VERSION 5.8 ;
BUSBITCHARS "[]" ;
DIVIDERCHAR "/" ;
UNITS
    DATABASE MICRONS 1000 ;
END UNITS

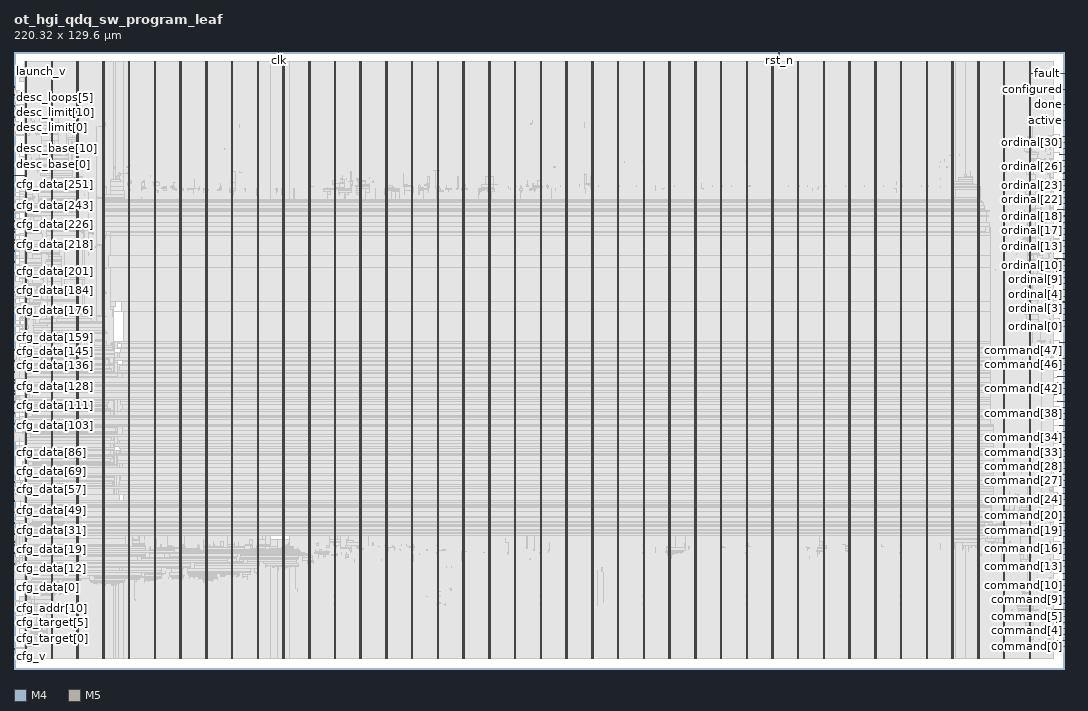
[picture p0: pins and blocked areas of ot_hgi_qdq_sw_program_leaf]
MACRO ot_hgi_qdq_sw_program_leaf
  FOREIGN ot_hgi_qdq_sw_program_leaf 0 0 ;
  CLASS BLOCK ;
  SIZE 220.32 BY 129.6 ;
  PIN active
    DIRECTION OUTPUT ;
    USE SIGNAL ;
    PORT
      LAYER M4 ;
        RECT  220.236 115.056 220.32 115.08 ;
    END
    PORT
      LAYER M4 ;
        RECT  219.409 115.056 220.284 115.08 ;
    END
  END active
  PIN cfg_addr[0]
    DIRECTION INPUT ;
    USE SIGNAL ;
    PORT
      LAYER M4 ;
        RECT  0 11.136 0.084 11.16 ;
    END
  END cfg_addr[0]
  PIN cfg_addr[10]
    DIRECTION INPUT ;
    USE SIGNAL ;
    PORT
      LAYER M4 ;
        RECT  0 14.4 0.084 14.424 ;
    END
  END cfg_addr[10]
  PIN cfg_addr[11]
    DIRECTION INPUT ;
    USE SIGNAL ;
    PORT
      LAYER M4 ;
        RECT  0 14.736 0.084 14.76 ;
    END
  END cfg_addr[11]
  PIN cfg_addr[1]
    DIRECTION INPUT ;
    USE SIGNAL ;
    PORT
      LAYER M4 ;
        RECT  0 11.472 0.084 11.496 ;
    END
  END cfg_addr[1]
  PIN cfg_addr[2]
    DIRECTION INPUT ;
    USE SIGNAL ;
    PORT
      LAYER M4 ;
        RECT  0 11.76 0.084 11.784 ;
    END
  END cfg_addr[2]
  PIN cfg_addr[3]
    DIRECTION INPUT ;
    USE SIGNAL ;
    PORT
      LAYER M4 ;
        RECT  0 12.096 0.084 12.12 ;
    END
  END cfg_addr[3]
  PIN cfg_addr[4]
    DIRECTION INPUT ;
    USE SIGNAL ;
    PORT
      LAYER M4 ;
        RECT  0 12.432 0.084 12.456 ;
    END
  END cfg_addr[4]
  PIN cfg_addr[5]
    DIRECTION INPUT ;
    USE SIGNAL ;
    PORT
      LAYER M4 ;
        RECT  0 12.768 0.084 12.792 ;
    END
  END cfg_addr[5]
  PIN cfg_addr[6]
    DIRECTION INPUT ;
    USE SIGNAL ;
    PORT
      LAYER M4 ;
        RECT  0 13.104 0.084 13.128 ;
    END
  END cfg_addr[6]
  PIN cfg_addr[7]
    DIRECTION INPUT ;
    USE SIGNAL ;
    PORT
      LAYER M4 ;
        RECT  0 13.44 0.084 13.464 ;
    END
  END cfg_addr[7]
  PIN cfg_addr[8]
    DIRECTION INPUT ;
    USE SIGNAL ;
    PORT
      LAYER M4 ;
        RECT  0 13.776 0.084 13.8 ;
    END
  END cfg_addr[8]
  PIN cfg_addr[9]
    DIRECTION INPUT ;
    USE SIGNAL ;
    PORT
      LAYER M4 ;
        RECT  0 14.112 0.084 14.136 ;
    END
  END cfg_addr[9]
  PIN cfg_data[0]
    DIRECTION INPUT ;
    USE SIGNAL ;
    PORT
      LAYER M4 ;
        RECT  0 17.088 0.084 17.112 ;
    END
  END cfg_data[0]
  PIN cfg_data[100]
    DIRECTION INPUT ;
    USE SIGNAL ;
    PORT
      LAYER M4 ;
        RECT  0 50.064 0.084 50.088 ;
    END
  END cfg_data[100]
  PIN cfg_data[101]
    DIRECTION INPUT ;
    USE SIGNAL ;
    PORT
      LAYER M4 ;
        RECT  0 50.4 0.084 50.424 ;
    END
  END cfg_data[101]
  PIN cfg_data[102]
    DIRECTION INPUT ;
    USE SIGNAL ;
    PORT
      LAYER M4 ;
        RECT  0 50.736 0.084 50.76 ;
    END
  END cfg_data[102]
  PIN cfg_data[103]
    DIRECTION INPUT ;
    USE SIGNAL ;
    PORT
      LAYER M4 ;
        RECT  0 51.072 0.084 51.096 ;
    END
  END cfg_data[103]
  PIN cfg_data[104]
    DIRECTION INPUT ;
    USE SIGNAL ;
    PORT
      LAYER M4 ;
        RECT  0 51.408 0.084 51.432 ;
    END
  END cfg_data[104]
  PIN cfg_data[105]
    DIRECTION INPUT ;
    USE SIGNAL ;
    PORT
      LAYER M4 ;
        RECT  0 51.744 0.084 51.768 ;
    END
  END cfg_data[105]
  PIN cfg_data[106]
    DIRECTION INPUT ;
    USE SIGNAL ;
    PORT
      LAYER M4 ;
        RECT  0 52.08 0.084 52.104 ;
    END
  END cfg_data[106]
  PIN cfg_data[107]
    DIRECTION INPUT ;
    USE SIGNAL ;
    PORT
      LAYER M4 ;
        RECT  0 52.416 0.084 52.44 ;
    END
  END cfg_data[107]
  PIN cfg_data[108]
    DIRECTION INPUT ;
    USE SIGNAL ;
    PORT
      LAYER M4 ;
        RECT  0 52.704 0.084 52.728 ;
    END
  END cfg_data[108]
  PIN cfg_data[109]
    DIRECTION INPUT ;
    USE SIGNAL ;
    PORT
      LAYER M4 ;
        RECT  0 53.04 0.084 53.064 ;
    END
  END cfg_data[109]
  PIN cfg_data[10]
    DIRECTION INPUT ;
    USE SIGNAL ;
    PORT
      LAYER M4 ;
        RECT  0 20.4 0.084 20.424 ;
    END
  END cfg_data[10]
  PIN cfg_data[110]
    DIRECTION INPUT ;
    USE SIGNAL ;
    PORT
      LAYER M4 ;
        RECT  0 53.376 0.084 53.4 ;
    END
  END cfg_data[110]
  PIN cfg_data[111]
    DIRECTION INPUT ;
    USE SIGNAL ;
    PORT
      LAYER M4 ;
        RECT  0 53.712 0.084 53.736 ;
    END
  END cfg_data[111]
  PIN cfg_data[112]
    DIRECTION INPUT ;
    USE SIGNAL ;
    PORT
      LAYER M4 ;
        RECT  0 54.048 0.084 54.072 ;
    END
  END cfg_data[112]
  PIN cfg_data[113]
    DIRECTION INPUT ;
    USE SIGNAL ;
    PORT
      LAYER M4 ;
        RECT  0 54.384 0.084 54.408 ;
    END
  END cfg_data[113]
  PIN cfg_data[114]
    DIRECTION INPUT ;
    USE SIGNAL ;
    PORT
      LAYER M4 ;
        RECT  0 54.72 0.084 54.744 ;
    END
  END cfg_data[114]
  PIN cfg_data[115]
    DIRECTION INPUT ;
    USE SIGNAL ;
    PORT
      LAYER M4 ;
        RECT  0 55.056 0.084 55.08 ;
    END
  END cfg_data[115]
  PIN cfg_data[116]
    DIRECTION INPUT ;
    USE SIGNAL ;
    PORT
      LAYER M4 ;
        RECT  0 55.344 0.084 55.368 ;
    END
  END cfg_data[116]
  PIN cfg_data[117]
    DIRECTION INPUT ;
    USE SIGNAL ;
    PORT
      LAYER M4 ;
        RECT  0 55.68 0.084 55.704 ;
    END
  END cfg_data[117]
  PIN cfg_data[118]
    DIRECTION INPUT ;
    USE SIGNAL ;
    PORT
      LAYER M4 ;
        RECT  0 56.016 0.084 56.04 ;
    END
  END cfg_data[118]
  PIN cfg_data[119]
    DIRECTION INPUT ;
    USE SIGNAL ;
    PORT
      LAYER M4 ;
        RECT  0 56.352 0.084 56.376 ;
    END
  END cfg_data[119]
  PIN cfg_data[11]
    DIRECTION INPUT ;
    USE SIGNAL ;
    PORT
      LAYER M4 ;
        RECT  0 20.736 0.084 20.76 ;
    END
  END cfg_data[11]
  PIN cfg_data[120]
    DIRECTION INPUT ;
    USE SIGNAL ;
    PORT
      LAYER M4 ;
        RECT  0 56.688 0.084 56.712 ;
    END
  END cfg_data[120]
  PIN cfg_data[121]
    DIRECTION INPUT ;
    USE SIGNAL ;
    PORT
      LAYER M4 ;
        RECT  0 57.024 0.084 57.048 ;
    END
  END cfg_data[121]
  PIN cfg_data[122]
    DIRECTION INPUT ;
    USE SIGNAL ;
    PORT
      LAYER M4 ;
        RECT  0 57.36 0.084 57.384 ;
    END
  END cfg_data[122]
  PIN cfg_data[123]
    DIRECTION INPUT ;
    USE SIGNAL ;
    PORT
      LAYER M4 ;
        RECT  0 57.696 0.084 57.72 ;
    END
  END cfg_data[123]
  PIN cfg_data[124]
    DIRECTION INPUT ;
    USE SIGNAL ;
    PORT
      LAYER M4 ;
        RECT  0 57.984 0.084 58.008 ;
    END
  END cfg_data[124]
  PIN cfg_data[125]
    DIRECTION INPUT ;
    USE SIGNAL ;
    PORT
      LAYER M4 ;
        RECT  0 58.32 0.084 58.344 ;
    END
  END cfg_data[125]
  PIN cfg_data[126]
    DIRECTION INPUT ;
    USE SIGNAL ;
    PORT
      LAYER M4 ;
        RECT  0 58.656 0.084 58.68 ;
    END
  END cfg_data[126]
  PIN cfg_data[127]
    DIRECTION INPUT ;
    USE SIGNAL ;
    PORT
      LAYER M4 ;
        RECT  0 58.992 0.084 59.016 ;
    END
  END cfg_data[127]
  PIN cfg_data[128]
    DIRECTION INPUT ;
    USE SIGNAL ;
    PORT
      LAYER M4 ;
        RECT  0 59.328 0.084 59.352 ;
    END
  END cfg_data[128]
  PIN cfg_data[129]
    DIRECTION INPUT ;
    USE SIGNAL ;
    PORT
      LAYER M4 ;
        RECT  0 59.664 0.084 59.688 ;
    END
  END cfg_data[129]
  PIN cfg_data[12]
    DIRECTION INPUT ;
    USE SIGNAL ;
    PORT
      LAYER M4 ;
        RECT  0 21.024 0.084 21.048 ;
    END
  END cfg_data[12]
  PIN cfg_data[130]
    DIRECTION INPUT ;
    USE SIGNAL ;
    PORT
      LAYER M4 ;
        RECT  0 60 0.084 60.024 ;
    END
  END cfg_data[130]
  PIN cfg_data[131]
    DIRECTION INPUT ;
    USE SIGNAL ;
    PORT
      LAYER M4 ;
        RECT  0 60.336 0.084 60.36 ;
    END
  END cfg_data[131]
  PIN cfg_data[132]
    DIRECTION INPUT ;
    USE SIGNAL ;
    PORT
      LAYER M4 ;
        RECT  0 60.624 0.084 60.648 ;
    END
  END cfg_data[132]
  PIN cfg_data[133]
    DIRECTION INPUT ;
    USE SIGNAL ;
    PORT
      LAYER M4 ;
        RECT  0 60.96 0.084 60.984 ;
    END
  END cfg_data[133]
  PIN cfg_data[134]
    DIRECTION INPUT ;
    USE SIGNAL ;
    PORT
      LAYER M4 ;
        RECT  0 61.296 0.084 61.32 ;
    END
  END cfg_data[134]
  PIN cfg_data[135]
    DIRECTION INPUT ;
    USE SIGNAL ;
    PORT
      LAYER M4 ;
        RECT  0 61.632 0.084 61.656 ;
    END
  END cfg_data[135]
  PIN cfg_data[136]
    DIRECTION INPUT ;
    USE SIGNAL ;
    PORT
      LAYER M4 ;
        RECT  0 61.968 0.084 61.992 ;
    END
  END cfg_data[136]
  PIN cfg_data[137]
    DIRECTION INPUT ;
    USE SIGNAL ;
    PORT
      LAYER M4 ;
        RECT  0 62.304 0.084 62.328 ;
    END
  END cfg_data[137]
  PIN cfg_data[138]
    DIRECTION INPUT ;
    USE SIGNAL ;
    PORT
      LAYER M4 ;
        RECT  0 62.64 0.084 62.664 ;
    END
  END cfg_data[138]
  PIN cfg_data[139]
    DIRECTION INPUT ;
    USE SIGNAL ;
    PORT
      LAYER M4 ;
        RECT  0 62.976 0.084 63 ;
    END
  END cfg_data[139]
  PIN cfg_data[13]
    DIRECTION INPUT ;
    USE SIGNAL ;
    PORT
      LAYER M4 ;
        RECT  0 21.36 0.084 21.384 ;
    END
  END cfg_data[13]
  PIN cfg_data[140]
    DIRECTION INPUT ;
    USE SIGNAL ;
    PORT
      LAYER M4 ;
        RECT  0 63.264 0.084 63.288 ;
    END
  END cfg_data[140]
  PIN cfg_data[141]
    DIRECTION INPUT ;
    USE SIGNAL ;
    PORT
      LAYER M4 ;
        RECT  0 63.6 0.084 63.624 ;
    END
  END cfg_data[141]
  PIN cfg_data[142]
    DIRECTION INPUT ;
    USE SIGNAL ;
    PORT
      LAYER M4 ;
        RECT  0 63.936 0.084 63.96 ;
    END
  END cfg_data[142]
  PIN cfg_data[143]
    DIRECTION INPUT ;
    USE SIGNAL ;
    PORT
      LAYER M4 ;
        RECT  0 64.272 0.084 64.296 ;
    END
  END cfg_data[143]
  PIN cfg_data[144]
    DIRECTION INPUT ;
    USE SIGNAL ;
    PORT
      LAYER M4 ;
        RECT  0 64.608 0.084 64.632 ;
    END
  END cfg_data[144]
  PIN cfg_data[145]
    DIRECTION INPUT ;
    USE SIGNAL ;
    PORT
      LAYER M4 ;
        RECT  0 64.944 0.084 64.968 ;
    END
  END cfg_data[145]
  PIN cfg_data[146]
    DIRECTION INPUT ;
    USE SIGNAL ;
    PORT
      LAYER M4 ;
        RECT  0 65.28 0.084 65.304 ;
    END
  END cfg_data[146]
  PIN cfg_data[147]
    DIRECTION INPUT ;
    USE SIGNAL ;
    PORT
      LAYER M4 ;
        RECT  0 65.616 0.084 65.64 ;
    END
  END cfg_data[147]
  PIN cfg_data[148]
    DIRECTION INPUT ;
    USE SIGNAL ;
    PORT
      LAYER M4 ;
        RECT  0 65.904 0.084 65.928 ;
    END
  END cfg_data[148]
  PIN cfg_data[149]
    DIRECTION INPUT ;
    USE SIGNAL ;
    PORT
      LAYER M4 ;
        RECT  0 66.24 0.084 66.264 ;
    END
  END cfg_data[149]
  PIN cfg_data[14]
    DIRECTION INPUT ;
    USE SIGNAL ;
    PORT
      LAYER M4 ;
        RECT  0 21.696 0.084 21.72 ;
    END
  END cfg_data[14]
  PIN cfg_data[150]
    DIRECTION INPUT ;
    USE SIGNAL ;
    PORT
      LAYER M4 ;
        RECT  0 66.576 0.084 66.6 ;
    END
  END cfg_data[150]
  PIN cfg_data[151]
    DIRECTION INPUT ;
    USE SIGNAL ;
    PORT
      LAYER M4 ;
        RECT  0 66.912 0.084 66.936 ;
    END
  END cfg_data[151]
  PIN cfg_data[152]
    DIRECTION INPUT ;
    USE SIGNAL ;
    PORT
      LAYER M4 ;
        RECT  0 67.248 0.084 67.272 ;
    END
  END cfg_data[152]
  PIN cfg_data[153]
    DIRECTION INPUT ;
    USE SIGNAL ;
    PORT
      LAYER M4 ;
        RECT  0 67.584 0.084 67.608 ;
    END
  END cfg_data[153]
  PIN cfg_data[154]
    DIRECTION INPUT ;
    USE SIGNAL ;
    PORT
      LAYER M4 ;
        RECT  0 67.92 0.084 67.944 ;
    END
  END cfg_data[154]
  PIN cfg_data[155]
    DIRECTION INPUT ;
    USE SIGNAL ;
    PORT
      LAYER M4 ;
        RECT  0 68.256 0.084 68.28 ;
    END
  END cfg_data[155]
  PIN cfg_data[156]
    DIRECTION INPUT ;
    USE SIGNAL ;
    PORT
      LAYER M4 ;
        RECT  0 68.544 0.084 68.568 ;
    END
  END cfg_data[156]
  PIN cfg_data[157]
    DIRECTION INPUT ;
    USE SIGNAL ;
    PORT
      LAYER M4 ;
        RECT  0 68.88 0.084 68.904 ;
    END
  END cfg_data[157]
  PIN cfg_data[158]
    DIRECTION INPUT ;
    USE SIGNAL ;
    PORT
      LAYER M4 ;
        RECT  0 69.216 0.084 69.24 ;
    END
  END cfg_data[158]
  PIN cfg_data[159]
    DIRECTION INPUT ;
    USE SIGNAL ;
    PORT
      LAYER M4 ;
        RECT  0 69.552 0.084 69.576 ;
    END
  END cfg_data[159]
  PIN cfg_data[15]
    DIRECTION INPUT ;
    USE SIGNAL ;
    PORT
      LAYER M4 ;
        RECT  0 22.032 0.084 22.056 ;
    END
  END cfg_data[15]
  PIN cfg_data[160]
    DIRECTION INPUT ;
    USE SIGNAL ;
    PORT
      LAYER M4 ;
        RECT  0 69.888 0.084 69.912 ;
    END
  END cfg_data[160]
  PIN cfg_data[161]
    DIRECTION INPUT ;
    USE SIGNAL ;
    PORT
      LAYER M4 ;
        RECT  0 70.224 0.084 70.248 ;
    END
  END cfg_data[161]
  PIN cfg_data[162]
    DIRECTION INPUT ;
    USE SIGNAL ;
    PORT
      LAYER M4 ;
        RECT  0 70.56 0.084 70.584 ;
    END
  END cfg_data[162]
  PIN cfg_data[163]
    DIRECTION INPUT ;
    USE SIGNAL ;
    PORT
      LAYER M4 ;
        RECT  0 70.896 0.084 70.92 ;
    END
  END cfg_data[163]
  PIN cfg_data[164]
    DIRECTION INPUT ;
    USE SIGNAL ;
    PORT
      LAYER M4 ;
        RECT  0 71.184 0.084 71.208 ;
    END
  END cfg_data[164]
  PIN cfg_data[165]
    DIRECTION INPUT ;
    USE SIGNAL ;
    PORT
      LAYER M4 ;
        RECT  0 71.52 0.084 71.544 ;
    END
  END cfg_data[165]
  PIN cfg_data[166]
    DIRECTION INPUT ;
    USE SIGNAL ;
    PORT
      LAYER M4 ;
        RECT  0 71.856 0.084 71.88 ;
    END
  END cfg_data[166]
  PIN cfg_data[167]
    DIRECTION INPUT ;
    USE SIGNAL ;
    PORT
      LAYER M4 ;
        RECT  0 72.192 0.084 72.216 ;
    END
  END cfg_data[167]
  PIN cfg_data[168]
    DIRECTION INPUT ;
    USE SIGNAL ;
    PORT
      LAYER M4 ;
        RECT  0 72.528 0.084 72.552 ;
    END
  END cfg_data[168]
  PIN cfg_data[169]
    DIRECTION INPUT ;
    USE SIGNAL ;
    PORT
      LAYER M4 ;
        RECT  0 72.864 0.084 72.888 ;
    END
  END cfg_data[169]
  PIN cfg_data[16]
    DIRECTION INPUT ;
    USE SIGNAL ;
    PORT
      LAYER M4 ;
        RECT  0 22.368 0.084 22.392 ;
    END
  END cfg_data[16]
  PIN cfg_data[170]
    DIRECTION INPUT ;
    USE SIGNAL ;
    PORT
      LAYER M4 ;
        RECT  0 73.2 0.084 73.224 ;
    END
  END cfg_data[170]
  PIN cfg_data[171]
    DIRECTION INPUT ;
    USE SIGNAL ;
    PORT
      LAYER M4 ;
        RECT  0 73.536 0.084 73.56 ;
    END
  END cfg_data[171]
  PIN cfg_data[172]
    DIRECTION INPUT ;
    USE SIGNAL ;
    PORT
      LAYER M4 ;
        RECT  0 73.824 0.084 73.848 ;
    END
  END cfg_data[172]
  PIN cfg_data[173]
    DIRECTION INPUT ;
    USE SIGNAL ;
    PORT
      LAYER M4 ;
        RECT  0 74.16 0.084 74.184 ;
    END
  END cfg_data[173]
  PIN cfg_data[174]
    DIRECTION INPUT ;
    USE SIGNAL ;
    PORT
      LAYER M4 ;
        RECT  0 74.496 0.084 74.52 ;
    END
  END cfg_data[174]
  PIN cfg_data[175]
    DIRECTION INPUT ;
    USE SIGNAL ;
    PORT
      LAYER M4 ;
        RECT  0 74.832 0.084 74.856 ;
    END
  END cfg_data[175]
  PIN cfg_data[176]
    DIRECTION INPUT ;
    USE SIGNAL ;
    PORT
      LAYER M4 ;
        RECT  0 75.168 0.084 75.192 ;
    END
  END cfg_data[176]
  PIN cfg_data[177]
    DIRECTION INPUT ;
    USE SIGNAL ;
    PORT
      LAYER M4 ;
        RECT  0 75.504 0.084 75.528 ;
    END
  END cfg_data[177]
  PIN cfg_data[178]
    DIRECTION INPUT ;
    USE SIGNAL ;
    PORT
      LAYER M4 ;
        RECT  0 75.84 0.084 75.864 ;
    END
  END cfg_data[178]
  PIN cfg_data[179]
    DIRECTION INPUT ;
    USE SIGNAL ;
    PORT
      LAYER M4 ;
        RECT  0 76.176 0.084 76.2 ;
    END
  END cfg_data[179]
  PIN cfg_data[17]
    DIRECTION INPUT ;
    USE SIGNAL ;
    PORT
      LAYER M4 ;
        RECT  0 22.704 0.084 22.728 ;
    END
  END cfg_data[17]
  PIN cfg_data[180]
    DIRECTION INPUT ;
    USE SIGNAL ;
    PORT
      LAYER M4 ;
        RECT  0 76.464 0.084 76.488 ;
    END
  END cfg_data[180]
  PIN cfg_data[181]
    DIRECTION INPUT ;
    USE SIGNAL ;
    PORT
      LAYER M4 ;
        RECT  0 76.8 0.084 76.824 ;
    END
  END cfg_data[181]
  PIN cfg_data[182]
    DIRECTION INPUT ;
    USE SIGNAL ;
    PORT
      LAYER M4 ;
        RECT  0 77.136 0.084 77.16 ;
    END
  END cfg_data[182]
  PIN cfg_data[183]
    DIRECTION INPUT ;
    USE SIGNAL ;
    PORT
      LAYER M4 ;
        RECT  0 77.472 0.084 77.496 ;
    END
  END cfg_data[183]
  PIN cfg_data[184]
    DIRECTION INPUT ;
    USE SIGNAL ;
    PORT
      LAYER M4 ;
        RECT  0 77.808 0.084 77.832 ;
    END
  END cfg_data[184]
  PIN cfg_data[185]
    DIRECTION INPUT ;
    USE SIGNAL ;
    PORT
      LAYER M4 ;
        RECT  0 78.144 0.084 78.168 ;
    END
  END cfg_data[185]
  PIN cfg_data[186]
    DIRECTION INPUT ;
    USE SIGNAL ;
    PORT
      LAYER M4 ;
        RECT  0 78.48 0.084 78.504 ;
    END
  END cfg_data[186]
  PIN cfg_data[187]
    DIRECTION INPUT ;
    USE SIGNAL ;
    PORT
      LAYER M4 ;
        RECT  0 78.816 0.084 78.84 ;
    END
  END cfg_data[187]
  PIN cfg_data[188]
    DIRECTION INPUT ;
    USE SIGNAL ;
    PORT
      LAYER M4 ;
        RECT  0 79.104 0.084 79.128 ;
    END
  END cfg_data[188]
  PIN cfg_data[189]
    DIRECTION INPUT ;
    USE SIGNAL ;
    PORT
      LAYER M4 ;
        RECT  0 79.44 0.084 79.464 ;
    END
  END cfg_data[189]
  PIN cfg_data[18]
    DIRECTION INPUT ;
    USE SIGNAL ;
    PORT
      LAYER M4 ;
        RECT  0 23.04 0.084 23.064 ;
    END
  END cfg_data[18]
  PIN cfg_data[190]
    DIRECTION INPUT ;
    USE SIGNAL ;
    PORT
      LAYER M4 ;
        RECT  0 79.776 0.084 79.8 ;
    END
  END cfg_data[190]
  PIN cfg_data[191]
    DIRECTION INPUT ;
    USE SIGNAL ;
    PORT
      LAYER M4 ;
        RECT  0 80.112 0.084 80.136 ;
    END
  END cfg_data[191]
  PIN cfg_data[192]
    DIRECTION INPUT ;
    USE SIGNAL ;
    PORT
      LAYER M4 ;
        RECT  0 80.448 0.084 80.472 ;
    END
  END cfg_data[192]
  PIN cfg_data[193]
    DIRECTION INPUT ;
    USE SIGNAL ;
    PORT
      LAYER M4 ;
        RECT  0 80.784 0.084 80.808 ;
    END
  END cfg_data[193]
  PIN cfg_data[194]
    DIRECTION INPUT ;
    USE SIGNAL ;
    PORT
      LAYER M4 ;
        RECT  0 81.12 0.084 81.144 ;
    END
  END cfg_data[194]
  PIN cfg_data[195]
    DIRECTION INPUT ;
    USE SIGNAL ;
    PORT
      LAYER M4 ;
        RECT  0 81.456 0.084 81.48 ;
    END
  END cfg_data[195]
  PIN cfg_data[196]
    DIRECTION INPUT ;
    USE SIGNAL ;
    PORT
      LAYER M4 ;
        RECT  0 81.744 0.084 81.768 ;
    END
  END cfg_data[196]
  PIN cfg_data[197]
    DIRECTION INPUT ;
    USE SIGNAL ;
    PORT
      LAYER M4 ;
        RECT  0 82.08 0.084 82.104 ;
    END
  END cfg_data[197]
  PIN cfg_data[198]
    DIRECTION INPUT ;
    USE SIGNAL ;
    PORT
      LAYER M4 ;
        RECT  0 82.416 0.084 82.44 ;
    END
  END cfg_data[198]
  PIN cfg_data[199]
    DIRECTION INPUT ;
    USE SIGNAL ;
    PORT
      LAYER M4 ;
        RECT  0 82.752 0.084 82.776 ;
    END
  END cfg_data[199]
  PIN cfg_data[19]
    DIRECTION INPUT ;
    USE SIGNAL ;
    PORT
      LAYER M4 ;
        RECT  0 23.376 0.084 23.4 ;
    END
  END cfg_data[19]
  PIN cfg_data[1]
    DIRECTION INPUT ;
    USE SIGNAL ;
    PORT
      LAYER M4 ;
        RECT  0 17.424 0.084 17.448 ;
    END
  END cfg_data[1]
  PIN cfg_data[200]
    DIRECTION INPUT ;
    USE SIGNAL ;
    PORT
      LAYER M4 ;
        RECT  0 83.088 0.084 83.112 ;
    END
  END cfg_data[200]
  PIN cfg_data[201]
    DIRECTION INPUT ;
    USE SIGNAL ;
    PORT
      LAYER M4 ;
        RECT  0 83.424 0.084 83.448 ;
    END
  END cfg_data[201]
  PIN cfg_data[202]
    DIRECTION INPUT ;
    USE SIGNAL ;
    PORT
      LAYER M4 ;
        RECT  0 83.76 0.084 83.784 ;
    END
  END cfg_data[202]
  PIN cfg_data[203]
    DIRECTION INPUT ;
    USE SIGNAL ;
    PORT
      LAYER M4 ;
        RECT  0 84.096 0.084 84.12 ;
    END
  END cfg_data[203]
  PIN cfg_data[204]
    DIRECTION INPUT ;
    USE SIGNAL ;
    PORT
      LAYER M4 ;
        RECT  0 84.384 0.084 84.408 ;
    END
  END cfg_data[204]
  PIN cfg_data[205]
    DIRECTION INPUT ;
    USE SIGNAL ;
    PORT
      LAYER M4 ;
        RECT  0 84.72 0.084 84.744 ;
    END
  END cfg_data[205]
  PIN cfg_data[206]
    DIRECTION INPUT ;
    USE SIGNAL ;
    PORT
      LAYER M4 ;
        RECT  0 85.056 0.084 85.08 ;
    END
  END cfg_data[206]
  PIN cfg_data[207]
    DIRECTION INPUT ;
    USE SIGNAL ;
    PORT
      LAYER M4 ;
        RECT  0 85.392 0.084 85.416 ;
    END
  END cfg_data[207]
  PIN cfg_data[208]
    DIRECTION INPUT ;
    USE SIGNAL ;
    PORT
      LAYER M4 ;
        RECT  0 85.728 0.084 85.752 ;
    END
  END cfg_data[208]
  PIN cfg_data[209]
    DIRECTION INPUT ;
    USE SIGNAL ;
    PORT
      LAYER M4 ;
        RECT  0 86.064 0.084 86.088 ;
    END
  END cfg_data[209]
  PIN cfg_data[20]
    DIRECTION INPUT ;
    USE SIGNAL ;
    PORT
      LAYER M4 ;
        RECT  0 23.664 0.084 23.688 ;
    END
  END cfg_data[20]
  PIN cfg_data[210]
    DIRECTION INPUT ;
    USE SIGNAL ;
    PORT
      LAYER M4 ;
        RECT  0 86.4 0.084 86.424 ;
    END
  END cfg_data[210]
  PIN cfg_data[211]
    DIRECTION INPUT ;
    USE SIGNAL ;
    PORT
      LAYER M4 ;
        RECT  0 86.736 0.084 86.76 ;
    END
  END cfg_data[211]
  PIN cfg_data[212]
    DIRECTION INPUT ;
    USE SIGNAL ;
    PORT
      LAYER M4 ;
        RECT  0 87.024 0.084 87.048 ;
    END
  END cfg_data[212]
  PIN cfg_data[213]
    DIRECTION INPUT ;
    USE SIGNAL ;
    PORT
      LAYER M4 ;
        RECT  0 87.36 0.084 87.384 ;
    END
  END cfg_data[213]
  PIN cfg_data[214]
    DIRECTION INPUT ;
    USE SIGNAL ;
    PORT
      LAYER M4 ;
        RECT  0 87.696 0.084 87.72 ;
    END
  END cfg_data[214]
  PIN cfg_data[215]
    DIRECTION INPUT ;
    USE SIGNAL ;
    PORT
      LAYER M4 ;
        RECT  0 88.032 0.084 88.056 ;
    END
  END cfg_data[215]
  PIN cfg_data[216]
    DIRECTION INPUT ;
    USE SIGNAL ;
    PORT
      LAYER M4 ;
        RECT  0 88.368 0.084 88.392 ;
    END
  END cfg_data[216]
  PIN cfg_data[217]
    DIRECTION INPUT ;
    USE SIGNAL ;
    PORT
      LAYER M4 ;
        RECT  0 88.704 0.084 88.728 ;
    END
  END cfg_data[217]
  PIN cfg_data[218]
    DIRECTION INPUT ;
    USE SIGNAL ;
    PORT
      LAYER M4 ;
        RECT  0 89.04 0.084 89.064 ;
    END
  END cfg_data[218]
  PIN cfg_data[219]
    DIRECTION INPUT ;
    USE SIGNAL ;
    PORT
      LAYER M4 ;
        RECT  0 89.376 0.084 89.4 ;
    END
  END cfg_data[219]
  PIN cfg_data[21]
    DIRECTION INPUT ;
    USE SIGNAL ;
    PORT
      LAYER M4 ;
        RECT  0 24 0.084 24.024 ;
    END
  END cfg_data[21]
  PIN cfg_data[220]
    DIRECTION INPUT ;
    USE SIGNAL ;
    PORT
      LAYER M4 ;
        RECT  0 89.664 0.084 89.688 ;
    END
  END cfg_data[220]
  PIN cfg_data[221]
    DIRECTION INPUT ;
    USE SIGNAL ;
    PORT
      LAYER M4 ;
        RECT  0 90 0.084 90.024 ;
    END
  END cfg_data[221]
  PIN cfg_data[222]
    DIRECTION INPUT ;
    USE SIGNAL ;
    PORT
      LAYER M4 ;
        RECT  0 90.336 0.084 90.36 ;
    END
  END cfg_data[222]
  PIN cfg_data[223]
    DIRECTION INPUT ;
    USE SIGNAL ;
    PORT
      LAYER M4 ;
        RECT  0 90.672 0.084 90.696 ;
    END
  END cfg_data[223]
  PIN cfg_data[224]
    DIRECTION INPUT ;
    USE SIGNAL ;
    PORT
      LAYER M4 ;
        RECT  0 91.008 0.084 91.032 ;
    END
  END cfg_data[224]
  PIN cfg_data[225]
    DIRECTION INPUT ;
    USE SIGNAL ;
    PORT
      LAYER M4 ;
        RECT  0 91.344 0.084 91.368 ;
    END
  END cfg_data[225]
  PIN cfg_data[226]
    DIRECTION INPUT ;
    USE SIGNAL ;
    PORT
      LAYER M4 ;
        RECT  0 91.68 0.084 91.704 ;
    END
  END cfg_data[226]
  PIN cfg_data[227]
    DIRECTION INPUT ;
    USE SIGNAL ;
    PORT
      LAYER M4 ;
        RECT  0 92.016 0.084 92.04 ;
    END
  END cfg_data[227]
  PIN cfg_data[228]
    DIRECTION INPUT ;
    USE SIGNAL ;
    PORT
      LAYER M4 ;
        RECT  0 92.304 0.084 92.328 ;
    END
  END cfg_data[228]
  PIN cfg_data[229]
    DIRECTION INPUT ;
    USE SIGNAL ;
    PORT
      LAYER M4 ;
        RECT  0 92.64 0.084 92.664 ;
    END
  END cfg_data[229]
  PIN cfg_data[22]
    DIRECTION INPUT ;
    USE SIGNAL ;
    PORT
      LAYER M4 ;
        RECT  0 24.336 0.084 24.36 ;
    END
  END cfg_data[22]
  PIN cfg_data[230]
    DIRECTION INPUT ;
    USE SIGNAL ;
    PORT
      LAYER M4 ;
        RECT  0 92.976 0.084 93 ;
    END
  END cfg_data[230]
  PIN cfg_data[231]
    DIRECTION INPUT ;
    USE SIGNAL ;
    PORT
      LAYER M4 ;
        RECT  0 93.312 0.084 93.336 ;
    END
  END cfg_data[231]
  PIN cfg_data[232]
    DIRECTION INPUT ;
    USE SIGNAL ;
    PORT
      LAYER M4 ;
        RECT  0 93.648 0.084 93.672 ;
    END
  END cfg_data[232]
  PIN cfg_data[233]
    DIRECTION INPUT ;
    USE SIGNAL ;
    PORT
      LAYER M4 ;
        RECT  0 93.984 0.084 94.008 ;
    END
  END cfg_data[233]
  PIN cfg_data[234]
    DIRECTION INPUT ;
    USE SIGNAL ;
    PORT
      LAYER M4 ;
        RECT  0 94.32 0.084 94.344 ;
    END
  END cfg_data[234]
  PIN cfg_data[235]
    DIRECTION INPUT ;
    USE SIGNAL ;
    PORT
      LAYER M4 ;
        RECT  0 94.656 0.084 94.68 ;
    END
  END cfg_data[235]
  PIN cfg_data[236]
    DIRECTION INPUT ;
    USE SIGNAL ;
    PORT
      LAYER M4 ;
        RECT  0 94.944 0.084 94.968 ;
    END
  END cfg_data[236]
  PIN cfg_data[237]
    DIRECTION INPUT ;
    USE SIGNAL ;
    PORT
      LAYER M4 ;
        RECT  0 95.28 0.084 95.304 ;
    END
  END cfg_data[237]
  PIN cfg_data[238]
    DIRECTION INPUT ;
    USE SIGNAL ;
    PORT
      LAYER M4 ;
        RECT  0 95.616 0.084 95.64 ;
    END
  END cfg_data[238]
  PIN cfg_data[239]
    DIRECTION INPUT ;
    USE SIGNAL ;
    PORT
      LAYER M4 ;
        RECT  0 95.952 0.084 95.976 ;
    END
  END cfg_data[239]
  PIN cfg_data[23]
    DIRECTION INPUT ;
    USE SIGNAL ;
    PORT
      LAYER M4 ;
        RECT  0 24.672 0.084 24.696 ;
    END
  END cfg_data[23]
  PIN cfg_data[240]
    DIRECTION INPUT ;
    USE SIGNAL ;
    PORT
      LAYER M4 ;
        RECT  0 96.288 0.084 96.312 ;
    END
  END cfg_data[240]
  PIN cfg_data[241]
    DIRECTION INPUT ;
    USE SIGNAL ;
    PORT
      LAYER M4 ;
        RECT  0 96.624 0.084 96.648 ;
    END
  END cfg_data[241]
  PIN cfg_data[242]
    DIRECTION INPUT ;
    USE SIGNAL ;
    PORT
      LAYER M4 ;
        RECT  0 96.96 0.084 96.984 ;
    END
  END cfg_data[242]
  PIN cfg_data[243]
    DIRECTION INPUT ;
    USE SIGNAL ;
    PORT
      LAYER M4 ;
        RECT  0 97.296 0.084 97.32 ;
    END
  END cfg_data[243]
  PIN cfg_data[244]
    DIRECTION INPUT ;
    USE SIGNAL ;
    PORT
      LAYER M4 ;
        RECT  0 97.584 0.084 97.608 ;
    END
  END cfg_data[244]
  PIN cfg_data[245]
    DIRECTION INPUT ;
    USE SIGNAL ;
    PORT
      LAYER M4 ;
        RECT  0 97.92 0.084 97.944 ;
    END
  END cfg_data[245]
  PIN cfg_data[246]
    DIRECTION INPUT ;
    USE SIGNAL ;
    PORT
      LAYER M4 ;
        RECT  0 98.256 0.084 98.28 ;
    END
  END cfg_data[246]
  PIN cfg_data[247]
    DIRECTION INPUT ;
    USE SIGNAL ;
    PORT
      LAYER M4 ;
        RECT  0 98.592 0.084 98.616 ;
    END
  END cfg_data[247]
  PIN cfg_data[248]
    DIRECTION INPUT ;
    USE SIGNAL ;
    PORT
      LAYER M4 ;
        RECT  0 98.928 0.084 98.952 ;
    END
  END cfg_data[248]
  PIN cfg_data[249]
    DIRECTION INPUT ;
    USE SIGNAL ;
    PORT
      LAYER M4 ;
        RECT  0 99.264 0.084 99.288 ;
    END
  END cfg_data[249]
  PIN cfg_data[24]
    DIRECTION INPUT ;
    USE SIGNAL ;
    PORT
      LAYER M4 ;
        RECT  0 25.008 0.084 25.032 ;
    END
  END cfg_data[24]
  PIN cfg_data[250]
    DIRECTION INPUT ;
    USE SIGNAL ;
    PORT
      LAYER M4 ;
        RECT  0 99.6 0.084 99.624 ;
    END
  END cfg_data[250]
  PIN cfg_data[251]
    DIRECTION INPUT ;
    USE SIGNAL ;
    PORT
      LAYER M4 ;
        RECT  0 99.936 0.084 99.96 ;
    END
  END cfg_data[251]
  PIN cfg_data[252]
    DIRECTION INPUT ;
    USE SIGNAL ;
    PORT
      LAYER M4 ;
        RECT  0 100.224 0.084 100.248 ;
    END
  END cfg_data[252]
  PIN cfg_data[253]
    DIRECTION INPUT ;
    USE SIGNAL ;
    PORT
      LAYER M4 ;
        RECT  0 100.56 0.084 100.584 ;
    END
  END cfg_data[253]
  PIN cfg_data[254]
    DIRECTION INPUT ;
    USE SIGNAL ;
    PORT
      LAYER M4 ;
        RECT  0 100.896 0.084 100.92 ;
    END
  END cfg_data[254]
  PIN cfg_data[255]
    DIRECTION INPUT ;
    USE SIGNAL ;
    PORT
      LAYER M4 ;
        RECT  0 101.232 0.084 101.256 ;
    END
  END cfg_data[255]
  PIN cfg_data[25]
    DIRECTION INPUT ;
    USE SIGNAL ;
    PORT
      LAYER M4 ;
        RECT  0 25.344 0.084 25.368 ;
    END
  END cfg_data[25]
  PIN cfg_data[26]
    DIRECTION INPUT ;
    USE SIGNAL ;
    PORT
      LAYER M4 ;
        RECT  0 25.68 0.084 25.704 ;
    END
  END cfg_data[26]
  PIN cfg_data[27]
    DIRECTION INPUT ;
    USE SIGNAL ;
    PORT
      LAYER M4 ;
        RECT  0 26.016 0.084 26.04 ;
    END
  END cfg_data[27]
  PIN cfg_data[28]
    DIRECTION INPUT ;
    USE SIGNAL ;
    PORT
      LAYER M4 ;
        RECT  0 26.304 0.084 26.328 ;
    END
  END cfg_data[28]
  PIN cfg_data[29]
    DIRECTION INPUT ;
    USE SIGNAL ;
    PORT
      LAYER M4 ;
        RECT  0 26.64 0.084 26.664 ;
    END
  END cfg_data[29]
  PIN cfg_data[2]
    DIRECTION INPUT ;
    USE SIGNAL ;
    PORT
      LAYER M4 ;
        RECT  0 17.76 0.084 17.784 ;
    END
  END cfg_data[2]
  PIN cfg_data[30]
    DIRECTION INPUT ;
    USE SIGNAL ;
    PORT
      LAYER M4 ;
        RECT  0 26.976 0.084 27 ;
    END
  END cfg_data[30]
  PIN cfg_data[31]
    DIRECTION INPUT ;
    USE SIGNAL ;
    PORT
      LAYER M4 ;
        RECT  0 27.312 0.084 27.336 ;
    END
  END cfg_data[31]
  PIN cfg_data[32]
    DIRECTION INPUT ;
    USE SIGNAL ;
    PORT
      LAYER M4 ;
        RECT  0 27.648 0.084 27.672 ;
    END
  END cfg_data[32]
  PIN cfg_data[33]
    DIRECTION INPUT ;
    USE SIGNAL ;
    PORT
      LAYER M4 ;
        RECT  0 27.984 0.084 28.008 ;
    END
  END cfg_data[33]
  PIN cfg_data[34]
    DIRECTION INPUT ;
    USE SIGNAL ;
    PORT
      LAYER M4 ;
        RECT  0 28.32 0.084 28.344 ;
    END
  END cfg_data[34]
  PIN cfg_data[35]
    DIRECTION INPUT ;
    USE SIGNAL ;
    PORT
      LAYER M4 ;
        RECT  0 28.656 0.084 28.68 ;
    END
  END cfg_data[35]
  PIN cfg_data[36]
    DIRECTION INPUT ;
    USE SIGNAL ;
    PORT
      LAYER M4 ;
        RECT  0 28.944 0.084 28.968 ;
    END
  END cfg_data[36]
  PIN cfg_data[37]
    DIRECTION INPUT ;
    USE SIGNAL ;
    PORT
      LAYER M4 ;
        RECT  0 29.28 0.084 29.304 ;
    END
  END cfg_data[37]
  PIN cfg_data[38]
    DIRECTION INPUT ;
    USE SIGNAL ;
    PORT
      LAYER M4 ;
        RECT  0 29.616 0.084 29.64 ;
    END
  END cfg_data[38]
  PIN cfg_data[39]
    DIRECTION INPUT ;
    USE SIGNAL ;
    PORT
      LAYER M4 ;
        RECT  0 29.952 0.084 29.976 ;
    END
  END cfg_data[39]
  PIN cfg_data[3]
    DIRECTION INPUT ;
    USE SIGNAL ;
    PORT
      LAYER M4 ;
        RECT  0 18.096 0.084 18.12 ;
    END
  END cfg_data[3]
  PIN cfg_data[40]
    DIRECTION INPUT ;
    USE SIGNAL ;
    PORT
      LAYER M4 ;
        RECT  0 30.288 0.084 30.312 ;
    END
  END cfg_data[40]
  PIN cfg_data[41]
    DIRECTION INPUT ;
    USE SIGNAL ;
    PORT
      LAYER M4 ;
        RECT  0 30.624 0.084 30.648 ;
    END
  END cfg_data[41]
  PIN cfg_data[42]
    DIRECTION INPUT ;
    USE SIGNAL ;
    PORT
      LAYER M4 ;
        RECT  0 30.96 0.084 30.984 ;
    END
  END cfg_data[42]
  PIN cfg_data[43]
    DIRECTION INPUT ;
    USE SIGNAL ;
    PORT
      LAYER M4 ;
        RECT  0 31.296 0.084 31.32 ;
    END
  END cfg_data[43]
  PIN cfg_data[44]
    DIRECTION INPUT ;
    USE SIGNAL ;
    PORT
      LAYER M4 ;
        RECT  0 31.584 0.084 31.608 ;
    END
  END cfg_data[44]
  PIN cfg_data[45]
    DIRECTION INPUT ;
    USE SIGNAL ;
    PORT
      LAYER M4 ;
        RECT  0 31.92 0.084 31.944 ;
    END
  END cfg_data[45]
  PIN cfg_data[46]
    DIRECTION INPUT ;
    USE SIGNAL ;
    PORT
      LAYER M4 ;
        RECT  0 32.256 0.084 32.28 ;
    END
  END cfg_data[46]
  PIN cfg_data[47]
    DIRECTION INPUT ;
    USE SIGNAL ;
    PORT
      LAYER M4 ;
        RECT  0 32.592 0.084 32.616 ;
    END
  END cfg_data[47]
  PIN cfg_data[48]
    DIRECTION INPUT ;
    USE SIGNAL ;
    PORT
      LAYER M4 ;
        RECT  0 32.928 0.084 32.952 ;
    END
  END cfg_data[48]
  PIN cfg_data[49]
    DIRECTION INPUT ;
    USE SIGNAL ;
    PORT
      LAYER M4 ;
        RECT  0 33.264 0.084 33.288 ;
    END
  END cfg_data[49]
  PIN cfg_data[4]
    DIRECTION INPUT ;
    USE SIGNAL ;
    PORT
      LAYER M4 ;
        RECT  0 18.384 0.084 18.408 ;
    END
  END cfg_data[4]
  PIN cfg_data[50]
    DIRECTION INPUT ;
    USE SIGNAL ;
    PORT
      LAYER M4 ;
        RECT  0 33.6 0.084 33.624 ;
    END
  END cfg_data[50]
  PIN cfg_data[51]
    DIRECTION INPUT ;
    USE SIGNAL ;
    PORT
      LAYER M4 ;
        RECT  0 33.936 0.084 33.96 ;
    END
  END cfg_data[51]
  PIN cfg_data[52]
    DIRECTION INPUT ;
    USE SIGNAL ;
    PORT
      LAYER M4 ;
        RECT  0 34.224 0.084 34.248 ;
    END
  END cfg_data[52]
  PIN cfg_data[53]
    DIRECTION INPUT ;
    USE SIGNAL ;
    PORT
      LAYER M4 ;
        RECT  0 34.56 0.084 34.584 ;
    END
  END cfg_data[53]
  PIN cfg_data[54]
    DIRECTION INPUT ;
    USE SIGNAL ;
    PORT
      LAYER M4 ;
        RECT  0 34.896 0.084 34.92 ;
    END
  END cfg_data[54]
  PIN cfg_data[55]
    DIRECTION INPUT ;
    USE SIGNAL ;
    PORT
      LAYER M4 ;
        RECT  0 35.232 0.084 35.256 ;
    END
  END cfg_data[55]
  PIN cfg_data[56]
    DIRECTION INPUT ;
    USE SIGNAL ;
    PORT
      LAYER M4 ;
        RECT  0 35.568 0.084 35.592 ;
    END
  END cfg_data[56]
  PIN cfg_data[57]
    DIRECTION INPUT ;
    USE SIGNAL ;
    PORT
      LAYER M4 ;
        RECT  0 35.904 0.084 35.928 ;
    END
  END cfg_data[57]
  PIN cfg_data[58]
    DIRECTION INPUT ;
    USE SIGNAL ;
    PORT
      LAYER M4 ;
        RECT  0 36.24 0.084 36.264 ;
    END
  END cfg_data[58]
  PIN cfg_data[59]
    DIRECTION INPUT ;
    USE SIGNAL ;
    PORT
      LAYER M4 ;
        RECT  0 36.576 0.084 36.6 ;
    END
  END cfg_data[59]
  PIN cfg_data[5]
    DIRECTION INPUT ;
    USE SIGNAL ;
    PORT
      LAYER M4 ;
        RECT  0 18.72 0.084 18.744 ;
    END
  END cfg_data[5]
  PIN cfg_data[60]
    DIRECTION INPUT ;
    USE SIGNAL ;
    PORT
      LAYER M4 ;
        RECT  0 36.864 0.084 36.888 ;
    END
  END cfg_data[60]
  PIN cfg_data[61]
    DIRECTION INPUT ;
    USE SIGNAL ;
    PORT
      LAYER M4 ;
        RECT  0 37.2 0.084 37.224 ;
    END
  END cfg_data[61]
  PIN cfg_data[62]
    DIRECTION INPUT ;
    USE SIGNAL ;
    PORT
      LAYER M4 ;
        RECT  0 37.536 0.084 37.56 ;
    END
  END cfg_data[62]
  PIN cfg_data[63]
    DIRECTION INPUT ;
    USE SIGNAL ;
    PORT
      LAYER M4 ;
        RECT  0 37.872 0.084 37.896 ;
    END
  END cfg_data[63]
  PIN cfg_data[64]
    DIRECTION INPUT ;
    USE SIGNAL ;
    PORT
      LAYER M4 ;
        RECT  0 38.208 0.084 38.232 ;
    END
  END cfg_data[64]
  PIN cfg_data[65]
    DIRECTION INPUT ;
    USE SIGNAL ;
    PORT
      LAYER M4 ;
        RECT  0 38.544 0.084 38.568 ;
    END
  END cfg_data[65]
  PIN cfg_data[66]
    DIRECTION INPUT ;
    USE SIGNAL ;
    PORT
      LAYER M4 ;
        RECT  0 38.88 0.084 38.904 ;
    END
  END cfg_data[66]
  PIN cfg_data[67]
    DIRECTION INPUT ;
    USE SIGNAL ;
    PORT
      LAYER M4 ;
        RECT  0 39.216 0.084 39.24 ;
    END
  END cfg_data[67]
  PIN cfg_data[68]
    DIRECTION INPUT ;
    USE SIGNAL ;
    PORT
      LAYER M4 ;
        RECT  0 39.504 0.084 39.528 ;
    END
  END cfg_data[68]
  PIN cfg_data[69]
    DIRECTION INPUT ;
    USE SIGNAL ;
    PORT
      LAYER M4 ;
        RECT  0 39.84 0.084 39.864 ;
    END
  END cfg_data[69]
  PIN cfg_data[6]
    DIRECTION INPUT ;
    USE SIGNAL ;
    PORT
      LAYER M4 ;
        RECT  0 19.056 0.084 19.08 ;
    END
  END cfg_data[6]
  PIN cfg_data[70]
    DIRECTION INPUT ;
    USE SIGNAL ;
    PORT
      LAYER M4 ;
        RECT  0 40.176 0.084 40.2 ;
    END
  END cfg_data[70]
  PIN cfg_data[71]
    DIRECTION INPUT ;
    USE SIGNAL ;
    PORT
      LAYER M4 ;
        RECT  0 40.512 0.084 40.536 ;
    END
  END cfg_data[71]
  PIN cfg_data[72]
    DIRECTION INPUT ;
    USE SIGNAL ;
    PORT
      LAYER M4 ;
        RECT  0 40.848 0.084 40.872 ;
    END
  END cfg_data[72]
  PIN cfg_data[73]
    DIRECTION INPUT ;
    USE SIGNAL ;
    PORT
      LAYER M4 ;
        RECT  0 41.184 0.084 41.208 ;
    END
  END cfg_data[73]
  PIN cfg_data[74]
    DIRECTION INPUT ;
    USE SIGNAL ;
    PORT
      LAYER M4 ;
        RECT  0 41.52 0.084 41.544 ;
    END
  END cfg_data[74]
  PIN cfg_data[75]
    DIRECTION INPUT ;
    USE SIGNAL ;
    PORT
      LAYER M4 ;
        RECT  0 41.856 0.084 41.88 ;
    END
  END cfg_data[75]
  PIN cfg_data[76]
    DIRECTION INPUT ;
    USE SIGNAL ;
    PORT
      LAYER M4 ;
        RECT  0 42.144 0.084 42.168 ;
    END
  END cfg_data[76]
  PIN cfg_data[77]
    DIRECTION INPUT ;
    USE SIGNAL ;
    PORT
      LAYER M4 ;
        RECT  0 42.48 0.084 42.504 ;
    END
  END cfg_data[77]
  PIN cfg_data[78]
    DIRECTION INPUT ;
    USE SIGNAL ;
    PORT
      LAYER M4 ;
        RECT  0 42.816 0.084 42.84 ;
    END
  END cfg_data[78]
  PIN cfg_data[79]
    DIRECTION INPUT ;
    USE SIGNAL ;
    PORT
      LAYER M4 ;
        RECT  0 43.152 0.084 43.176 ;
    END
  END cfg_data[79]
  PIN cfg_data[7]
    DIRECTION INPUT ;
    USE SIGNAL ;
    PORT
      LAYER M4 ;
        RECT  0 19.392 0.084 19.416 ;
    END
  END cfg_data[7]
  PIN cfg_data[80]
    DIRECTION INPUT ;
    USE SIGNAL ;
    PORT
      LAYER M4 ;
        RECT  0 43.488 0.084 43.512 ;
    END
  END cfg_data[80]
  PIN cfg_data[81]
    DIRECTION INPUT ;
    USE SIGNAL ;
    PORT
      LAYER M4 ;
        RECT  0 43.824 0.084 43.848 ;
    END
  END cfg_data[81]
  PIN cfg_data[82]
    DIRECTION INPUT ;
    USE SIGNAL ;
    PORT
      LAYER M4 ;
        RECT  0 44.16 0.084 44.184 ;
    END
  END cfg_data[82]
  PIN cfg_data[83]
    DIRECTION INPUT ;
    USE SIGNAL ;
    PORT
      LAYER M4 ;
        RECT  0 44.496 0.084 44.52 ;
    END
  END cfg_data[83]
  PIN cfg_data[84]
    DIRECTION INPUT ;
    USE SIGNAL ;
    PORT
      LAYER M4 ;
        RECT  0 44.784 0.084 44.808 ;
    END
  END cfg_data[84]
  PIN cfg_data[85]
    DIRECTION INPUT ;
    USE SIGNAL ;
    PORT
      LAYER M4 ;
        RECT  0 45.12 0.084 45.144 ;
    END
  END cfg_data[85]
  PIN cfg_data[86]
    DIRECTION INPUT ;
    USE SIGNAL ;
    PORT
      LAYER M4 ;
        RECT  0 45.456 0.084 45.48 ;
    END
  END cfg_data[86]
  PIN cfg_data[87]
    DIRECTION INPUT ;
    USE SIGNAL ;
    PORT
      LAYER M4 ;
        RECT  0 45.792 0.084 45.816 ;
    END
  END cfg_data[87]
  PIN cfg_data[88]
    DIRECTION INPUT ;
    USE SIGNAL ;
    PORT
      LAYER M4 ;
        RECT  0 46.128 0.084 46.152 ;
    END
  END cfg_data[88]
  PIN cfg_data[89]
    DIRECTION INPUT ;
    USE SIGNAL ;
    PORT
      LAYER M4 ;
        RECT  0 46.464 0.084 46.488 ;
    END
  END cfg_data[89]
  PIN cfg_data[8]
    DIRECTION INPUT ;
    USE SIGNAL ;
    PORT
      LAYER M4 ;
        RECT  0 19.728 0.084 19.752 ;
    END
  END cfg_data[8]
  PIN cfg_data[90]
    DIRECTION INPUT ;
    USE SIGNAL ;
    PORT
      LAYER M4 ;
        RECT  0 46.8 0.084 46.824 ;
    END
  END cfg_data[90]
  PIN cfg_data[91]
    DIRECTION INPUT ;
    USE SIGNAL ;
    PORT
      LAYER M4 ;
        RECT  0 47.136 0.084 47.16 ;
    END
  END cfg_data[91]
  PIN cfg_data[92]
    DIRECTION INPUT ;
    USE SIGNAL ;
    PORT
      LAYER M4 ;
        RECT  0 47.424 0.084 47.448 ;
    END
  END cfg_data[92]
  PIN cfg_data[93]
    DIRECTION INPUT ;
    USE SIGNAL ;
    PORT
      LAYER M4 ;
        RECT  0 47.76 0.084 47.784 ;
    END
  END cfg_data[93]
  PIN cfg_data[94]
    DIRECTION INPUT ;
    USE SIGNAL ;
    PORT
      LAYER M4 ;
        RECT  0 48.096 0.084 48.12 ;
    END
  END cfg_data[94]
  PIN cfg_data[95]
    DIRECTION INPUT ;
    USE SIGNAL ;
    PORT
      LAYER M4 ;
        RECT  0 48.432 0.084 48.456 ;
    END
  END cfg_data[95]
  PIN cfg_data[96]
    DIRECTION INPUT ;
    USE SIGNAL ;
    PORT
      LAYER M4 ;
        RECT  0 48.768 0.084 48.792 ;
    END
  END cfg_data[96]
  PIN cfg_data[97]
    DIRECTION INPUT ;
    USE SIGNAL ;
    PORT
      LAYER M4 ;
        RECT  0 49.104 0.084 49.128 ;
    END
  END cfg_data[97]
  PIN cfg_data[98]
    DIRECTION INPUT ;
    USE SIGNAL ;
    PORT
      LAYER M4 ;
        RECT  0 49.44 0.084 49.464 ;
    END
  END cfg_data[98]
  PIN cfg_data[99]
    DIRECTION INPUT ;
    USE SIGNAL ;
    PORT
      LAYER M4 ;
        RECT  0 49.776 0.084 49.8 ;
    END
  END cfg_data[99]
  PIN cfg_data[9]
    DIRECTION INPUT ;
    USE SIGNAL ;
    PORT
      LAYER M4 ;
        RECT  0 20.064 0.084 20.088 ;
    END
  END cfg_data[9]
  PIN cfg_target[0]
    DIRECTION INPUT ;
    USE SIGNAL ;
    PORT
      LAYER M4 ;
        RECT  0 6.48 0.084 6.504 ;
    END
  END cfg_target[0]
  PIN cfg_target[1]
    DIRECTION INPUT ;
    USE SIGNAL ;
    PORT
      LAYER M4 ;
        RECT  0 6.816 0.084 6.84 ;
    END
  END cfg_target[1]
  PIN cfg_target[2]
    DIRECTION INPUT ;
    USE SIGNAL ;
    PORT
      LAYER M4 ;
        RECT  0 7.152 0.084 7.176 ;
    END
  END cfg_target[2]
  PIN cfg_target[3]
    DIRECTION INPUT ;
    USE SIGNAL ;
    PORT
      LAYER M4 ;
        RECT  0 7.488 0.084 7.512 ;
    END
  END cfg_target[3]
  PIN cfg_target[4]
    DIRECTION INPUT ;
    USE SIGNAL ;
    PORT
      LAYER M4 ;
        RECT  0 7.824 0.084 7.848 ;
    END
  END cfg_target[4]
  PIN cfg_target[5]
    DIRECTION INPUT ;
    USE SIGNAL ;
    PORT
      LAYER M4 ;
        RECT  0 8.112 0.084 8.136 ;
    END
  END cfg_target[5]
  PIN cfg_target[6]
    DIRECTION INPUT ;
    USE SIGNAL ;
    PORT
      LAYER M4 ;
        RECT  0 8.448 0.084 8.472 ;
    END
  END cfg_target[6]
  PIN cfg_target[7]
    DIRECTION INPUT ;
    USE SIGNAL ;
    PORT
      LAYER M4 ;
        RECT  0 8.784 0.084 8.808 ;
    END
  END cfg_target[7]
  PIN cfg_v
    DIRECTION INPUT ;
    USE SIGNAL ;
    PORT
      LAYER M4 ;
        RECT  0 4.176 0.084 4.2 ;
    END
    PORT
      LAYER M4 ;
        RECT  0.06 4.176 0.137 4.2 ;
    END
  END cfg_v
  PIN clk
    DIRECTION INPUT ;
    USE SIGNAL ;
    PORT
      LAYER M5 ;
        RECT  55.488 129.516 55.512 129.6 ;
    END
    PORT
      LAYER M5 ;
        RECT  55.488 127.463 55.512 129.552 ;
    END
  END clk
  PIN command[0]
    DIRECTION OUTPUT ;
    USE SIGNAL ;
    PORT
      LAYER M4 ;
        RECT  220.236 4.656 220.32 4.68 ;
    END
    PORT
      LAYER M4 ;
        RECT  218.869 4.656 220.284 4.68 ;
    END
  END command[0]
  PIN command[10]
    DIRECTION OUTPUT ;
    USE SIGNAL ;
    PORT
      LAYER M4 ;
        RECT  220.236 17.52 220.32 17.544 ;
    END
    PORT
      LAYER M4 ;
        RECT  219.409 17.52 220.284 17.544 ;
    END
  END command[10]
  PIN command[11]
    DIRECTION OUTPUT ;
    USE SIGNAL ;
    PORT
      LAYER M4 ;
        RECT  220.236 18.816 220.32 18.84 ;
    END
    PORT
      LAYER M4 ;
        RECT  219.409 18.816 220.284 18.84 ;
    END
  END command[11]
  PIN command[12]
    DIRECTION OUTPUT ;
    USE SIGNAL ;
    PORT
      LAYER M4 ;
        RECT  220.236 20.112 220.32 20.136 ;
    END
    PORT
      LAYER M4 ;
        RECT  219.409 20.112 220.284 20.136 ;
    END
  END command[12]
  PIN command[13]
    DIRECTION OUTPUT ;
    USE SIGNAL ;
    PORT
      LAYER M4 ;
        RECT  220.236 21.408 220.32 21.432 ;
    END
    PORT
      LAYER M4 ;
        RECT  219.409 21.408 220.284 21.432 ;
    END
  END command[13]
  PIN command[14]
    DIRECTION OUTPUT ;
    USE SIGNAL ;
    PORT
      LAYER M4 ;
        RECT  220.236 22.704 220.32 22.728 ;
    END
    PORT
      LAYER M4 ;
        RECT  219.409 22.704 220.284 22.728 ;
    END
  END command[14]
  PIN command[15]
    DIRECTION OUTPUT ;
    USE SIGNAL ;
    PORT
      LAYER M4 ;
        RECT  220.236 23.952 220.32 23.976 ;
    END
    PORT
      LAYER M4 ;
        RECT  219.409 23.952 220.284 23.976 ;
    END
  END command[15]
  PIN command[16]
    DIRECTION OUTPUT ;
    USE SIGNAL ;
    PORT
      LAYER M4 ;
        RECT  220.236 25.248 220.32 25.272 ;
    END
    PORT
      LAYER M4 ;
        RECT  219.445 25.248 220.284 25.272 ;
    END
  END command[16]
  PIN command[17]
    DIRECTION OUTPUT ;
    USE SIGNAL ;
    PORT
      LAYER M4 ;
        RECT  220.236 26.544 220.32 26.568 ;
    END
    PORT
      LAYER M4 ;
        RECT  219.409 26.544 220.284 26.568 ;
    END
  END command[17]
  PIN command[18]
    DIRECTION OUTPUT ;
    USE SIGNAL ;
    PORT
      LAYER M4 ;
        RECT  220.236 27.84 220.32 27.864 ;
    END
    PORT
      LAYER M4 ;
        RECT  219.409 27.84 220.284 27.864 ;
    END
  END command[18]
  PIN command[19]
    DIRECTION OUTPUT ;
    USE SIGNAL ;
    PORT
      LAYER M4 ;
        RECT  220.236 29.136 220.32 29.16 ;
    END
    PORT
      LAYER M4 ;
        RECT  219.445 29.136 220.284 29.16 ;
    END
  END command[19]
  PIN command[1]
    DIRECTION OUTPUT ;
    USE SIGNAL ;
    PORT
      LAYER M4 ;
        RECT  220.236 5.904 220.32 5.928 ;
    END
    PORT
      LAYER M4 ;
        RECT  218.869 5.904 220.284 5.928 ;
    END
  END command[1]
  PIN command[20]
    DIRECTION OUTPUT ;
    USE SIGNAL ;
    PORT
      LAYER M4 ;
        RECT  220.236 30.432 220.32 30.456 ;
    END
    PORT
      LAYER M4 ;
        RECT  219.445 30.432 220.284 30.456 ;
    END
  END command[20]
  PIN command[21]
    DIRECTION OUTPUT ;
    USE SIGNAL ;
    PORT
      LAYER M4 ;
        RECT  220.236 31.728 220.32 31.752 ;
    END
    PORT
      LAYER M4 ;
        RECT  218.833 31.728 220.284 31.752 ;
    END
  END command[21]
  PIN command[22]
    DIRECTION OUTPUT ;
    USE SIGNAL ;
    PORT
      LAYER M4 ;
        RECT  220.236 33.024 220.32 33.048 ;
    END
    PORT
      LAYER M4 ;
        RECT  219.409 33.024 220.284 33.048 ;
    END
  END command[22]
  PIN command[23]
    DIRECTION OUTPUT ;
    USE SIGNAL ;
    PORT
      LAYER M4 ;
        RECT  220.236 34.272 220.32 34.296 ;
    END
    PORT
      LAYER M4 ;
        RECT  219.409 34.272 220.284 34.296 ;
    END
  END command[23]
  PIN command[24]
    DIRECTION OUTPUT ;
    USE SIGNAL ;
    PORT
      LAYER M4 ;
        RECT  220.236 35.568 220.32 35.592 ;
    END
    PORT
      LAYER M4 ;
        RECT  219.445 35.568 220.284 35.592 ;
    END
  END command[24]
  PIN command[25]
    DIRECTION OUTPUT ;
    USE SIGNAL ;
    PORT
      LAYER M4 ;
        RECT  220.236 36.864 220.32 36.888 ;
    END
    PORT
      LAYER M4 ;
        RECT  218.833 36.864 220.284 36.888 ;
    END
  END command[25]
  PIN command[26]
    DIRECTION OUTPUT ;
    USE SIGNAL ;
    PORT
      LAYER M4 ;
        RECT  220.236 38.16 220.32 38.184 ;
    END
    PORT
      LAYER M4 ;
        RECT  219.409 38.16 220.284 38.184 ;
    END
  END command[26]
  PIN command[27]
    DIRECTION OUTPUT ;
    USE SIGNAL ;
    PORT
      LAYER M4 ;
        RECT  220.236 39.456 220.32 39.48 ;
    END
    PORT
      LAYER M4 ;
        RECT  219.409 39.456 220.284 39.48 ;
    END
  END command[27]
  PIN command[28]
    DIRECTION OUTPUT ;
    USE SIGNAL ;
    PORT
      LAYER M4 ;
        RECT  220.236 40.752 220.32 40.776 ;
    END
    PORT
      LAYER M4 ;
        RECT  219.409 40.752 220.284 40.776 ;
    END
  END command[28]
  PIN command[29]
    DIRECTION OUTPUT ;
    USE SIGNAL ;
    PORT
      LAYER M4 ;
        RECT  220.236 42.048 220.32 42.072 ;
    END
    PORT
      LAYER M4 ;
        RECT  219.409 42.048 220.284 42.072 ;
    END
  END command[29]
  PIN command[2]
    DIRECTION OUTPUT ;
    USE SIGNAL ;
    PORT
      LAYER M4 ;
        RECT  220.236 7.2 220.32 7.224 ;
    END
    PORT
      LAYER M4 ;
        RECT  218.833 7.2 220.284 7.224 ;
    END
  END command[2]
  PIN command[30]
    DIRECTION OUTPUT ;
    USE SIGNAL ;
    PORT
      LAYER M4 ;
        RECT  220.236 43.296 220.32 43.32 ;
    END
    PORT
      LAYER M4 ;
        RECT  219.409 43.296 220.284 43.32 ;
    END
  END command[30]
  PIN command[31]
    DIRECTION OUTPUT ;
    USE SIGNAL ;
    PORT
      LAYER M4 ;
        RECT  220.236 44.592 220.32 44.616 ;
    END
    PORT
      LAYER M4 ;
        RECT  219.409 44.592 220.284 44.616 ;
    END
  END command[31]
  PIN command[32]
    DIRECTION OUTPUT ;
    USE SIGNAL ;
    PORT
      LAYER M4 ;
        RECT  220.236 45.888 220.32 45.912 ;
    END
    PORT
      LAYER M4 ;
        RECT  218.869 45.888 220.284 45.912 ;
    END
  END command[32]
  PIN command[33]
    DIRECTION OUTPUT ;
    USE SIGNAL ;
    PORT
      LAYER M4 ;
        RECT  220.236 47.184 220.32 47.208 ;
    END
    PORT
      LAYER M4 ;
        RECT  219.409 47.184 220.284 47.208 ;
    END
  END command[33]
  PIN command[34]
    DIRECTION OUTPUT ;
    USE SIGNAL ;
    PORT
      LAYER M4 ;
        RECT  220.236 48.48 220.32 48.504 ;
    END
    PORT
      LAYER M4 ;
        RECT  219.445 48.48 220.284 48.504 ;
    END
  END command[34]
  PIN command[35]
    DIRECTION OUTPUT ;
    USE SIGNAL ;
    PORT
      LAYER M4 ;
        RECT  220.236 49.776 220.32 49.8 ;
    END
    PORT
      LAYER M4 ;
        RECT  218.869 49.776 220.284 49.8 ;
    END
  END command[35]
  PIN command[36]
    DIRECTION OUTPUT ;
    USE SIGNAL ;
    PORT
      LAYER M4 ;
        RECT  220.236 51.072 220.32 51.096 ;
    END
    PORT
      LAYER M4 ;
        RECT  219.409 51.072 220.284 51.096 ;
    END
  END command[36]
  PIN command[37]
    DIRECTION OUTPUT ;
    USE SIGNAL ;
    PORT
      LAYER M4 ;
        RECT  220.236 52.32 220.32 52.344 ;
    END
    PORT
      LAYER M4 ;
        RECT  219.409 52.32 220.284 52.344 ;
    END
  END command[37]
  PIN command[38]
    DIRECTION OUTPUT ;
    USE SIGNAL ;
    PORT
      LAYER M4 ;
        RECT  220.236 53.616 220.32 53.64 ;
    END
    PORT
      LAYER M4 ;
        RECT  219.445 53.616 220.284 53.64 ;
    END
  END command[38]
  PIN command[39]
    DIRECTION OUTPUT ;
    USE SIGNAL ;
    PORT
      LAYER M4 ;
        RECT  220.236 54.912 220.32 54.936 ;
    END
    PORT
      LAYER M4 ;
        RECT  219.409 54.912 220.284 54.936 ;
    END
  END command[39]
  PIN command[3]
    DIRECTION OUTPUT ;
    USE SIGNAL ;
    PORT
      LAYER M4 ;
        RECT  220.236 8.496 220.32 8.52 ;
    END
    PORT
      LAYER M4 ;
        RECT  218.293 8.496 220.284 8.52 ;
    END
  END command[3]
  PIN command[40]
    DIRECTION OUTPUT ;
    USE SIGNAL ;
    PORT
      LAYER M4 ;
        RECT  220.236 56.208 220.32 56.232 ;
    END
    PORT
      LAYER M4 ;
        RECT  218.869 56.208 220.284 56.232 ;
    END
  END command[40]
  PIN command[41]
    DIRECTION OUTPUT ;
    USE SIGNAL ;
    PORT
      LAYER M4 ;
        RECT  220.236 57.504 220.32 57.528 ;
    END
    PORT
      LAYER M4 ;
        RECT  218.293 57.504 220.284 57.528 ;
    END
  END command[41]
  PIN command[42]
    DIRECTION OUTPUT ;
    USE SIGNAL ;
    PORT
      LAYER M4 ;
        RECT  220.236 58.8 220.32 58.824 ;
    END
    PORT
      LAYER M4 ;
        RECT  219.445 58.8 220.284 58.824 ;
    END
  END command[42]
  PIN command[43]
    DIRECTION OUTPUT ;
    USE SIGNAL ;
    PORT
      LAYER M4 ;
        RECT  220.236 60.096 220.32 60.12 ;
    END
    PORT
      LAYER M4 ;
        RECT  218.869 60.096 220.284 60.12 ;
    END
  END command[43]
  PIN command[44]
    DIRECTION OUTPUT ;
    USE SIGNAL ;
    PORT
      LAYER M4 ;
        RECT  220.236 61.344 220.32 61.368 ;
    END
    PORT
      LAYER M4 ;
        RECT  218.869 61.344 220.284 61.368 ;
    END
  END command[44]
  PIN command[45]
    DIRECTION OUTPUT ;
    USE SIGNAL ;
    PORT
      LAYER M4 ;
        RECT  220.236 62.64 220.32 62.664 ;
    END
    PORT
      LAYER M4 ;
        RECT  218.869 62.64 220.284 62.664 ;
    END
  END command[45]
  PIN command[46]
    DIRECTION OUTPUT ;
    USE SIGNAL ;
    PORT
      LAYER M4 ;
        RECT  220.236 63.936 220.32 63.96 ;
    END
    PORT
      LAYER M4 ;
        RECT  219.445 63.936 220.284 63.96 ;
    END
  END command[46]
  PIN command[47]
    DIRECTION OUTPUT ;
    USE SIGNAL ;
    PORT
      LAYER M4 ;
        RECT  220.236 65.232 220.32 65.256 ;
    END
    PORT
      LAYER M4 ;
        RECT  219.409 65.232 220.284 65.256 ;
    END
  END command[47]
  PIN command[4]
    DIRECTION OUTPUT ;
    USE SIGNAL ;
    PORT
      LAYER M4 ;
        RECT  220.236 9.792 220.32 9.816 ;
    END
    PORT
      LAYER M4 ;
        RECT  218.833 9.792 220.284 9.816 ;
    END
  END command[4]
  PIN command[5]
    DIRECTION OUTPUT ;
    USE SIGNAL ;
    PORT
      LAYER M4 ;
        RECT  220.236 11.088 220.32 11.112 ;
    END
    PORT
      LAYER M4 ;
        RECT  219.409 11.088 220.284 11.112 ;
    END
  END command[5]
  PIN command[6]
    DIRECTION OUTPUT ;
    USE SIGNAL ;
    PORT
      LAYER M4 ;
        RECT  220.236 12.384 220.32 12.408 ;
    END
    PORT
      LAYER M4 ;
        RECT  218.293 12.384 220.284 12.408 ;
    END
  END command[6]
  PIN command[7]
    DIRECTION OUTPUT ;
    USE SIGNAL ;
    PORT
      LAYER M4 ;
        RECT  220.236 13.68 220.32 13.704 ;
    END
    PORT
      LAYER M4 ;
        RECT  219.409 13.68 220.284 13.704 ;
    END
  END command[7]
  PIN command[8]
    DIRECTION OUTPUT ;
    USE SIGNAL ;
    PORT
      LAYER M4 ;
        RECT  220.236 14.928 220.32 14.952 ;
    END
    PORT
      LAYER M4 ;
        RECT  218.833 14.928 220.284 14.952 ;
    END
  END command[8]
  PIN command[9]
    DIRECTION OUTPUT ;
    USE SIGNAL ;
    PORT
      LAYER M4 ;
        RECT  220.236 16.224 220.32 16.248 ;
    END
    PORT
      LAYER M4 ;
        RECT  218.869 16.224 220.284 16.248 ;
    END
  END command[9]
  PIN command_v
    DIRECTION OUTPUT ;
    USE SIGNAL ;
    PORT
      LAYER M4 ;
        RECT  220.236 68.544 220.32 68.568 ;
    END
    PORT
      LAYER M4 ;
        RECT  219.409 68.544 220.284 68.568 ;
    END
  END command_v
  PIN configured
    DIRECTION OUTPUT ;
    USE SIGNAL ;
    PORT
      LAYER M4 ;
        RECT  220.236 121.632 220.32 121.656 ;
    END
    PORT
      LAYER M4 ;
        RECT  219.409 121.632 220.284 121.656 ;
    END
  END configured
  PIN desc_base[0]
    DIRECTION INPUT ;
    USE SIGNAL ;
    PORT
      LAYER M4 ;
        RECT  0 105.888 0.084 105.912 ;
    END
  END desc_base[0]
  PIN desc_base[10]
    DIRECTION INPUT ;
    USE SIGNAL ;
    PORT
      LAYER M4 ;
        RECT  0 109.2 0.084 109.224 ;
    END
  END desc_base[10]
  PIN desc_base[11]
    DIRECTION INPUT ;
    USE SIGNAL ;
    PORT
      LAYER M4 ;
        RECT  0 109.536 0.084 109.56 ;
    END
  END desc_base[11]
  PIN desc_base[1]
    DIRECTION INPUT ;
    USE SIGNAL ;
    PORT
      LAYER M4 ;
        RECT  0 106.224 0.084 106.248 ;
    END
  END desc_base[1]
  PIN desc_base[2]
    DIRECTION INPUT ;
    USE SIGNAL ;
    PORT
      LAYER M4 ;
        RECT  0 106.56 0.084 106.584 ;
    END
  END desc_base[2]
  PIN desc_base[3]
    DIRECTION INPUT ;
    USE SIGNAL ;
    PORT
      LAYER M4 ;
        RECT  0 106.896 0.084 106.92 ;
    END
  END desc_base[3]
  PIN desc_base[4]
    DIRECTION INPUT ;
    USE SIGNAL ;
    PORT
      LAYER M4 ;
        RECT  0 107.232 0.084 107.256 ;
    END
  END desc_base[4]
  PIN desc_base[5]
    DIRECTION INPUT ;
    USE SIGNAL ;
    PORT
      LAYER M4 ;
        RECT  0 107.52 0.084 107.544 ;
    END
  END desc_base[5]
  PIN desc_base[6]
    DIRECTION INPUT ;
    USE SIGNAL ;
    PORT
      LAYER M4 ;
        RECT  0 107.856 0.084 107.88 ;
    END
  END desc_base[6]
  PIN desc_base[7]
    DIRECTION INPUT ;
    USE SIGNAL ;
    PORT
      LAYER M4 ;
        RECT  0 108.192 0.084 108.216 ;
    END
  END desc_base[7]
  PIN desc_base[8]
    DIRECTION INPUT ;
    USE SIGNAL ;
    PORT
      LAYER M4 ;
        RECT  0 108.528 0.084 108.552 ;
    END
  END desc_base[8]
  PIN desc_base[9]
    DIRECTION INPUT ;
    USE SIGNAL ;
    PORT
      LAYER M4 ;
        RECT  0 108.864 0.084 108.888 ;
    END
  END desc_base[9]
  PIN desc_limit[0]
    DIRECTION INPUT ;
    USE SIGNAL ;
    PORT
      LAYER M4 ;
        RECT  0 111.84 0.084 111.864 ;
    END
  END desc_limit[0]
  PIN desc_limit[10]
    DIRECTION INPUT ;
    USE SIGNAL ;
    PORT
      LAYER M4 ;
        RECT  0 115.152 0.084 115.176 ;
    END
  END desc_limit[10]
  PIN desc_limit[11]
    DIRECTION INPUT ;
    USE SIGNAL ;
    PORT
      LAYER M4 ;
        RECT  0 115.488 0.084 115.512 ;
    END
  END desc_limit[11]
  PIN desc_limit[12]
    DIRECTION INPUT ;
    USE SIGNAL ;
    PORT
      LAYER M4 ;
        RECT  0 115.824 0.084 115.848 ;
    END
  END desc_limit[12]
  PIN desc_limit[1]
    DIRECTION INPUT ;
    USE SIGNAL ;
    PORT
      LAYER M4 ;
        RECT  0 112.176 0.084 112.2 ;
    END
  END desc_limit[1]
  PIN desc_limit[2]
    DIRECTION INPUT ;
    USE SIGNAL ;
    PORT
      LAYER M4 ;
        RECT  0 112.512 0.084 112.536 ;
    END
  END desc_limit[2]
  PIN desc_limit[3]
    DIRECTION INPUT ;
    USE SIGNAL ;
    PORT
      LAYER M4 ;
        RECT  0 112.848 0.084 112.872 ;
    END
  END desc_limit[3]
  PIN desc_limit[4]
    DIRECTION INPUT ;
    USE SIGNAL ;
    PORT
      LAYER M4 ;
        RECT  0 113.184 0.084 113.208 ;
    END
  END desc_limit[4]
  PIN desc_limit[5]
    DIRECTION INPUT ;
    USE SIGNAL ;
    PORT
      LAYER M4 ;
        RECT  0 113.52 0.084 113.544 ;
    END
  END desc_limit[5]
  PIN desc_limit[6]
    DIRECTION INPUT ;
    USE SIGNAL ;
    PORT
      LAYER M4 ;
        RECT  0 113.856 0.084 113.88 ;
    END
  END desc_limit[6]
  PIN desc_limit[7]
    DIRECTION INPUT ;
    USE SIGNAL ;
    PORT
      LAYER M4 ;
        RECT  0 114.144 0.084 114.168 ;
    END
  END desc_limit[7]
  PIN desc_limit[8]
    DIRECTION INPUT ;
    USE SIGNAL ;
    PORT
      LAYER M4 ;
        RECT  0 114.48 0.084 114.504 ;
    END
  END desc_limit[8]
  PIN desc_limit[9]
    DIRECTION INPUT ;
    USE SIGNAL ;
    PORT
      LAYER M4 ;
        RECT  0 114.816 0.084 114.84 ;
    END
  END desc_limit[9]
  PIN desc_loops[0]
    DIRECTION INPUT ;
    USE SIGNAL ;
    PORT
      LAYER M4 ;
        RECT  0 118.128 0.084 118.152 ;
    END
  END desc_loops[0]
  PIN desc_loops[10]
    DIRECTION INPUT ;
    USE SIGNAL ;
    PORT
      LAYER M4 ;
        RECT  0 121.44 0.084 121.464 ;
    END
  END desc_loops[10]
  PIN desc_loops[11]
    DIRECTION INPUT ;
    USE SIGNAL ;
    PORT
      LAYER M4 ;
        RECT  0 121.776 0.084 121.8 ;
    END
  END desc_loops[11]
  PIN desc_loops[12]
    DIRECTION INPUT ;
    USE SIGNAL ;
    PORT
      LAYER M4 ;
        RECT  0 122.112 0.084 122.136 ;
    END
  END desc_loops[12]
  PIN desc_loops[13]
    DIRECTION INPUT ;
    USE SIGNAL ;
    PORT
      LAYER M4 ;
        RECT  0 122.448 0.084 122.472 ;
    END
  END desc_loops[13]
  PIN desc_loops[14]
    DIRECTION INPUT ;
    USE SIGNAL ;
    PORT
      LAYER M4 ;
        RECT  0 122.784 0.084 122.808 ;
    END
  END desc_loops[14]
  PIN desc_loops[15]
    DIRECTION INPUT ;
    USE SIGNAL ;
    PORT
      LAYER M4 ;
        RECT  0 123.072 0.084 123.096 ;
    END
  END desc_loops[15]
  PIN desc_loops[1]
    DIRECTION INPUT ;
    USE SIGNAL ;
    PORT
      LAYER M4 ;
        RECT  0 118.464 0.084 118.488 ;
    END
  END desc_loops[1]
  PIN desc_loops[2]
    DIRECTION INPUT ;
    USE SIGNAL ;
    PORT
      LAYER M4 ;
        RECT  0 118.8 0.084 118.824 ;
    END
  END desc_loops[2]
  PIN desc_loops[3]
    DIRECTION INPUT ;
    USE SIGNAL ;
    PORT
      LAYER M4 ;
        RECT  0 119.136 0.084 119.16 ;
    END
  END desc_loops[3]
  PIN desc_loops[4]
    DIRECTION INPUT ;
    USE SIGNAL ;
    PORT
      LAYER M4 ;
        RECT  0 119.472 0.084 119.496 ;
    END
  END desc_loops[4]
  PIN desc_loops[5]
    DIRECTION INPUT ;
    USE SIGNAL ;
    PORT
      LAYER M4 ;
        RECT  0 119.808 0.084 119.832 ;
    END
  END desc_loops[5]
  PIN desc_loops[6]
    DIRECTION INPUT ;
    USE SIGNAL ;
    PORT
      LAYER M4 ;
        RECT  0 120.144 0.084 120.168 ;
    END
  END desc_loops[6]
  PIN desc_loops[7]
    DIRECTION INPUT ;
    USE SIGNAL ;
    PORT
      LAYER M4 ;
        RECT  0 120.432 0.084 120.456 ;
    END
  END desc_loops[7]
  PIN desc_loops[8]
    DIRECTION INPUT ;
    USE SIGNAL ;
    PORT
      LAYER M4 ;
        RECT  0 120.768 0.084 120.792 ;
    END
  END desc_loops[8]
  PIN desc_loops[9]
    DIRECTION INPUT ;
    USE SIGNAL ;
    PORT
      LAYER M4 ;
        RECT  0 121.104 0.084 121.128 ;
    END
  END desc_loops[9]
  PIN desc_v
    DIRECTION INPUT ;
    USE SIGNAL ;
    PORT
      LAYER M4 ;
        RECT  0 103.584 0.084 103.608 ;
    END
    PORT
      LAYER M4 ;
        RECT  0.06 103.584 2.408 103.608 ;
    END
  END desc_v
  PIN done
    DIRECTION OUTPUT ;
    USE SIGNAL ;
    PORT
      LAYER M4 ;
        RECT  220.236 118.368 220.32 118.392 ;
    END
    PORT
      LAYER M4 ;
        RECT  220.201 118.368 220.284 118.392 ;
    END
  END done
  PIN fault
    DIRECTION OUTPUT ;
    USE SIGNAL ;
    PORT
      LAYER M4 ;
        RECT  220.236 124.944 220.32 124.968 ;
    END
    PORT
      LAYER M4 ;
        RECT  213.304 124.944 220.284 124.968 ;
    END
  END fault
  PIN launch_v
    DIRECTION INPUT ;
    USE SIGNAL ;
    PORT
      LAYER M4 ;
        RECT  0 125.424 0.084 125.448 ;
    END
    PORT
      LAYER M4 ;
        RECT  0.06 125.424 0.137 125.448 ;
    END
  END launch_v
  PIN ordinal[0]
    DIRECTION OUTPUT ;
    USE SIGNAL ;
    PORT
      LAYER M4 ;
        RECT  220.236 71.808 220.32 71.832 ;
    END
    PORT
      LAYER M4 ;
        RECT  219.409 71.808 220.284 71.832 ;
    END
  END ordinal[0]
  PIN ordinal[10]
    DIRECTION OUTPUT ;
    USE SIGNAL ;
    PORT
      LAYER M4 ;
        RECT  220.236 84.72 220.32 84.744 ;
    END
    PORT
      LAYER M4 ;
        RECT  219.409 84.72 220.284 84.744 ;
    END
  END ordinal[10]
  PIN ordinal[11]
    DIRECTION OUTPUT ;
    USE SIGNAL ;
    PORT
      LAYER M4 ;
        RECT  220.236 86.016 220.32 86.04 ;
    END
    PORT
      LAYER M4 ;
        RECT  218.293 86.016 220.284 86.04 ;
    END
  END ordinal[11]
  PIN ordinal[12]
    DIRECTION OUTPUT ;
    USE SIGNAL ;
    PORT
      LAYER M4 ;
        RECT  220.236 87.264 220.32 87.288 ;
    END
    PORT
      LAYER M4 ;
        RECT  219.409 87.264 220.284 87.288 ;
    END
  END ordinal[12]
  PIN ordinal[13]
    DIRECTION OUTPUT ;
    USE SIGNAL ;
    PORT
      LAYER M4 ;
        RECT  220.236 88.56 220.32 88.584 ;
    END
    PORT
      LAYER M4 ;
        RECT  220.201 88.56 220.284 88.584 ;
    END
  END ordinal[13]
  PIN ordinal[14]
    DIRECTION OUTPUT ;
    USE SIGNAL ;
    PORT
      LAYER M4 ;
        RECT  220.236 89.856 220.32 89.88 ;
    END
    PORT
      LAYER M4 ;
        RECT  219.409 89.856 220.284 89.88 ;
    END
  END ordinal[14]
  PIN ordinal[15]
    DIRECTION OUTPUT ;
    USE SIGNAL ;
    PORT
      LAYER M4 ;
        RECT  220.236 91.152 220.32 91.176 ;
    END
    PORT
      LAYER M4 ;
        RECT  219.409 91.152 220.284 91.176 ;
    END
  END ordinal[15]
  PIN ordinal[16]
    DIRECTION OUTPUT ;
    USE SIGNAL ;
    PORT
      LAYER M4 ;
        RECT  220.236 92.448 220.32 92.472 ;
    END
    PORT
      LAYER M4 ;
        RECT  219.409 92.448 220.284 92.472 ;
    END
  END ordinal[16]
  PIN ordinal[17]
    DIRECTION OUTPUT ;
    USE SIGNAL ;
    PORT
      LAYER M4 ;
        RECT  220.236 93.744 220.32 93.768 ;
    END
    PORT
      LAYER M4 ;
        RECT  220.201 93.744 220.284 93.768 ;
    END
  END ordinal[17]
  PIN ordinal[18]
    DIRECTION OUTPUT ;
    USE SIGNAL ;
    PORT
      LAYER M4 ;
        RECT  220.236 95.04 220.32 95.064 ;
    END
    PORT
      LAYER M4 ;
        RECT  220.201 95.04 220.284 95.064 ;
    END
  END ordinal[18]
  PIN ordinal[19]
    DIRECTION OUTPUT ;
    USE SIGNAL ;
    PORT
      LAYER M4 ;
        RECT  220.236 96.336 220.32 96.36 ;
    END
    PORT
      LAYER M4 ;
        RECT  218.869 96.336 220.284 96.36 ;
    END
  END ordinal[19]
  PIN ordinal[1]
    DIRECTION OUTPUT ;
    USE SIGNAL ;
    PORT
      LAYER M4 ;
        RECT  220.236 73.104 220.32 73.128 ;
    END
    PORT
      LAYER M4 ;
        RECT  219.409 73.104 220.284 73.128 ;
    END
  END ordinal[1]
  PIN ordinal[20]
    DIRECTION OUTPUT ;
    USE SIGNAL ;
    PORT
      LAYER M4 ;
        RECT  220.236 97.584 220.32 97.608 ;
    END
    PORT
      LAYER M4 ;
        RECT  219.409 97.584 220.284 97.608 ;
    END
  END ordinal[20]
  PIN ordinal[21]
    DIRECTION OUTPUT ;
    USE SIGNAL ;
    PORT
      LAYER M4 ;
        RECT  220.236 98.88 220.32 98.904 ;
    END
    PORT
      LAYER M4 ;
        RECT  219.409 98.88 220.284 98.904 ;
    END
  END ordinal[21]
  PIN ordinal[22]
    DIRECTION OUTPUT ;
    USE SIGNAL ;
    PORT
      LAYER M4 ;
        RECT  220.236 100.176 220.32 100.2 ;
    END
    PORT
      LAYER M4 ;
        RECT  219.409 100.176 220.284 100.2 ;
    END
  END ordinal[22]
  PIN ordinal[23]
    DIRECTION OUTPUT ;
    USE SIGNAL ;
    PORT
      LAYER M4 ;
        RECT  220.236 101.472 220.32 101.496 ;
    END
    PORT
      LAYER M4 ;
        RECT  219.445 101.472 220.284 101.496 ;
    END
  END ordinal[23]
  PIN ordinal[24]
    DIRECTION OUTPUT ;
    USE SIGNAL ;
    PORT
      LAYER M4 ;
        RECT  220.236 102.768 220.32 102.792 ;
    END
    PORT
      LAYER M4 ;
        RECT  219.409 102.768 220.284 102.792 ;
    END
  END ordinal[24]
  PIN ordinal[25]
    DIRECTION OUTPUT ;
    USE SIGNAL ;
    PORT
      LAYER M4 ;
        RECT  220.236 104.064 220.32 104.088 ;
    END
    PORT
      LAYER M4 ;
        RECT  219.409 104.064 220.284 104.088 ;
    END
  END ordinal[25]
  PIN ordinal[26]
    DIRECTION OUTPUT ;
    USE SIGNAL ;
    PORT
      LAYER M4 ;
        RECT  220.236 105.36 220.32 105.384 ;
    END
    PORT
      LAYER M4 ;
        RECT  220.201 105.36 220.284 105.384 ;
    END
  END ordinal[26]
  PIN ordinal[27]
    DIRECTION OUTPUT ;
    USE SIGNAL ;
    PORT
      LAYER M4 ;
        RECT  220.236 106.608 220.32 106.632 ;
    END
    PORT
      LAYER M4 ;
        RECT  218.869 106.608 220.284 106.632 ;
    END
  END ordinal[27]
  PIN ordinal[28]
    DIRECTION OUTPUT ;
    USE SIGNAL ;
    PORT
      LAYER M4 ;
        RECT  220.236 107.904 220.32 107.928 ;
    END
    PORT
      LAYER M4 ;
        RECT  219.409 107.904 220.284 107.928 ;
    END
  END ordinal[28]
  PIN ordinal[29]
    DIRECTION OUTPUT ;
    USE SIGNAL ;
    PORT
      LAYER M4 ;
        RECT  220.236 109.2 220.32 109.224 ;
    END
    PORT
      LAYER M4 ;
        RECT  219.409 109.2 220.284 109.224 ;
    END
  END ordinal[29]
  PIN ordinal[2]
    DIRECTION OUTPUT ;
    USE SIGNAL ;
    PORT
      LAYER M4 ;
        RECT  220.236 74.4 220.32 74.424 ;
    END
    PORT
      LAYER M4 ;
        RECT  219.409 74.4 220.284 74.424 ;
    END
  END ordinal[2]
  PIN ordinal[30]
    DIRECTION OUTPUT ;
    USE SIGNAL ;
    PORT
      LAYER M4 ;
        RECT  220.236 110.496 220.32 110.52 ;
    END
    PORT
      LAYER M4 ;
        RECT  220.201 110.496 220.284 110.52 ;
    END
  END ordinal[30]
  PIN ordinal[31]
    DIRECTION OUTPUT ;
    USE SIGNAL ;
    PORT
      LAYER M4 ;
        RECT  220.236 111.792 220.32 111.816 ;
    END
    PORT
      LAYER M4 ;
        RECT  219.409 111.792 220.284 111.816 ;
    END
  END ordinal[31]
  PIN ordinal[3]
    DIRECTION OUTPUT ;
    USE SIGNAL ;
    PORT
      LAYER M4 ;
        RECT  220.236 75.696 220.32 75.72 ;
    END
    PORT
      LAYER M4 ;
        RECT  220.201 75.696 220.284 75.72 ;
    END
  END ordinal[3]
  PIN ordinal[4]
    DIRECTION OUTPUT ;
    USE SIGNAL ;
    PORT
      LAYER M4 ;
        RECT  220.236 76.992 220.32 77.016 ;
    END
    PORT
      LAYER M4 ;
        RECT  219.409 76.992 220.284 77.016 ;
    END
  END ordinal[4]
  PIN ordinal[5]
    DIRECTION OUTPUT ;
    USE SIGNAL ;
    PORT
      LAYER M4 ;
        RECT  220.236 78.24 220.32 78.264 ;
    END
    PORT
      LAYER M4 ;
        RECT  219.409 78.24 220.284 78.264 ;
    END
  END ordinal[5]
  PIN ordinal[6]
    DIRECTION OUTPUT ;
    USE SIGNAL ;
    PORT
      LAYER M4 ;
        RECT  220.236 79.536 220.32 79.56 ;
    END
    PORT
      LAYER M4 ;
        RECT  218.833 79.536 220.284 79.56 ;
    END
  END ordinal[6]
  PIN ordinal[7]
    DIRECTION OUTPUT ;
    USE SIGNAL ;
    PORT
      LAYER M4 ;
        RECT  220.236 80.832 220.32 80.856 ;
    END
    PORT
      LAYER M4 ;
        RECT  219.409 80.832 220.284 80.856 ;
    END
  END ordinal[7]
  PIN ordinal[8]
    DIRECTION OUTPUT ;
    USE SIGNAL ;
    PORT
      LAYER M4 ;
        RECT  220.236 82.128 220.32 82.152 ;
    END
    PORT
      LAYER M4 ;
        RECT  218.833 82.128 220.284 82.152 ;
    END
  END ordinal[8]
  PIN ordinal[9]
    DIRECTION OUTPUT ;
    USE SIGNAL ;
    PORT
      LAYER M4 ;
        RECT  220.236 83.424 220.32 83.448 ;
    END
    PORT
      LAYER M4 ;
        RECT  218.833 83.424 220.284 83.448 ;
    END
  END ordinal[9]
  PIN rst_n
    DIRECTION INPUT ;
    USE SIGNAL ;
    PORT
      LAYER M5 ;
        RECT  160.512 129.516 160.536 129.6 ;
    END
    PORT
      LAYER M5 ;
        RECT  160.512 127.237 160.536 129.552 ;
    END
  END rst_n
  PIN VDD
    DIRECTION INOUT ;
    USE POWER ;
    PORT
      LAYER M5 ;
        RECT  213.192 2.151 213.312 127.449 ;
        RECT  207.792 2.151 207.912 127.449 ;
        RECT  202.392 2.151 202.512 127.449 ;
        RECT  196.992 2.151 197.112 127.449 ;
        RECT  191.592 2.151 191.712 127.449 ;
        RECT  186.192 2.151 186.312 127.449 ;
        RECT  180.792 2.151 180.912 127.449 ;
        RECT  175.392 2.151 175.512 127.449 ;
        RECT  169.992 2.151 170.112 127.449 ;
        RECT  164.592 2.151 164.712 127.449 ;
        RECT  159.192 2.151 159.312 127.449 ;
        RECT  153.792 2.151 153.912 127.449 ;
        RECT  148.392 2.151 148.512 127.449 ;
        RECT  142.992 2.151 143.112 127.449 ;
        RECT  137.592 2.151 137.712 127.449 ;
        RECT  132.192 2.151 132.312 127.449 ;
        RECT  126.792 2.151 126.912 127.449 ;
        RECT  121.392 2.151 121.512 127.449 ;
        RECT  115.992 2.151 116.112 127.449 ;
        RECT  110.592 2.151 110.712 127.449 ;
        RECT  105.192 2.151 105.312 127.449 ;
        RECT  99.792 2.151 99.912 127.449 ;
        RECT  94.392 2.151 94.512 127.449 ;
        RECT  88.992 2.151 89.112 127.449 ;
        RECT  83.592 2.151 83.712 127.449 ;
        RECT  78.192 2.151 78.312 127.449 ;
        RECT  72.792 2.151 72.912 127.449 ;
        RECT  67.392 2.151 67.512 127.449 ;
        RECT  61.992 2.151 62.112 127.449 ;
        RECT  56.592 2.151 56.712 127.449 ;
        RECT  51.192 2.151 51.312 127.449 ;
        RECT  45.792 2.151 45.912 127.449 ;
        RECT  40.392 2.151 40.512 127.449 ;
        RECT  34.992 2.151 35.112 127.449 ;
        RECT  29.592 2.151 29.712 127.449 ;
        RECT  24.192 2.151 24.312 127.449 ;
        RECT  18.792 2.151 18.912 127.449 ;
        RECT  13.392 2.151 13.512 127.449 ;
        RECT  7.992 2.151 8.112 127.449 ;
        RECT  2.592 2.151 2.712 127.449 ;
    END
  END VDD
  PIN VSS
    DIRECTION INOUT ;
    USE GROUND ;
    PORT
      LAYER M5 ;
        RECT  213 2.137 213.12 127.463 ;
        RECT  207.6 2.137 207.72 127.463 ;
        RECT  202.2 2.137 202.32 127.463 ;
        RECT  196.8 2.137 196.92 127.463 ;
        RECT  191.4 2.137 191.52 127.463 ;
        RECT  186 2.137 186.12 127.463 ;
        RECT  180.6 2.137 180.72 127.463 ;
        RECT  175.2 2.137 175.32 127.463 ;
        RECT  169.8 2.137 169.92 127.463 ;
        RECT  164.4 2.137 164.52 127.463 ;
        RECT  159 2.137 159.12 127.463 ;
        RECT  153.6 2.137 153.72 127.463 ;
        RECT  148.2 2.137 148.32 127.463 ;
        RECT  142.8 2.137 142.92 127.463 ;
        RECT  137.4 2.137 137.52 127.463 ;
        RECT  132 2.137 132.12 127.463 ;
        RECT  126.6 2.137 126.72 127.463 ;
        RECT  121.2 2.137 121.32 127.463 ;
        RECT  115.8 2.137 115.92 127.463 ;
        RECT  110.4 2.137 110.52 127.463 ;
        RECT  105 2.137 105.12 127.463 ;
        RECT  99.6 2.137 99.72 127.463 ;
        RECT  94.2 2.137 94.32 127.463 ;
        RECT  88.8 2.137 88.92 127.463 ;
        RECT  83.4 2.137 83.52 127.463 ;
        RECT  78 2.137 78.12 127.463 ;
        RECT  72.6 2.137 72.72 127.463 ;
        RECT  67.2 2.137 67.32 127.463 ;
        RECT  61.8 2.137 61.92 127.463 ;
        RECT  56.4 2.137 56.52 127.463 ;
        RECT  51 2.137 51.12 127.463 ;
        RECT  45.6 2.137 45.72 127.463 ;
        RECT  40.2 2.137 40.32 127.463 ;
        RECT  34.8 2.137 34.92 127.463 ;
        RECT  29.4 2.137 29.52 127.463 ;
        RECT  24 2.137 24.12 127.463 ;
        RECT  18.6 2.137 18.72 127.463 ;
        RECT  13.2 2.137 13.32 127.463 ;
        RECT  7.8 2.137 7.92 127.463 ;
        RECT  2.4 2.137 2.52 127.463 ;
    END
  END VSS
  # OT_OBS_CLOSED layer=M5 d_um=1.536 added=165
  OBS
    LAYER RVTN ;
     RECT  2.16 2.16 218.16 2.295 ;
     RECT  2.16 2.565 218.16 2.835 ;
     RECT  2.16 3.105 218.16 3.375 ;
     RECT  2.16 3.645 218.16 3.915 ;
     RECT  2.16 4.185 218.16 4.455 ;
     RECT  2.16 4.725 218.16 4.995 ;
     RECT  2.16 5.265 218.16 5.535 ;
     RECT  2.16 5.805 218.16 6.075 ;
     RECT  2.16 6.345 218.16 6.615 ;
     RECT  2.16 6.885 218.16 7.155 ;
     RECT  2.16 7.425 218.16 7.695 ;
     RECT  2.16 7.965 218.16 8.235 ;
     RECT  2.16 8.505 218.16 8.775 ;
     RECT  2.16 9.045 218.16 9.315 ;
     RECT  2.16 9.585 218.16 9.855 ;
     RECT  2.16 10.125 218.16 10.395 ;
     RECT  2.16 10.665 218.16 10.935 ;
     RECT  2.16 11.205 218.16 11.475 ;
     RECT  2.16 11.745 218.16 12.015 ;
     RECT  2.16 12.285 218.16 12.555 ;
     RECT  2.16 12.825 218.16 13.095 ;
     RECT  2.16 13.365 218.16 13.635 ;
     RECT  2.16 13.905 218.16 14.175 ;
     RECT  2.16 14.445 218.16 14.715 ;
     RECT  2.16 14.985 218.16 15.255 ;
     RECT  2.16 15.525 218.16 15.795 ;
     RECT  2.16 16.065 218.16 16.335 ;
     RECT  2.16 16.605 218.16 16.875 ;
     RECT  2.16 17.145 218.16 17.415 ;
     RECT  2.16 17.685 218.16 17.955 ;
     RECT  2.16 18.225 218.16 18.495 ;
     RECT  2.16 18.765 218.16 19.035 ;
     RECT  2.16 19.305 218.16 19.575 ;
     RECT  2.16 19.845 218.16 20.115 ;
     RECT  2.16 20.385 218.16 20.655 ;
     RECT  2.16 20.925 218.16 21.195 ;
     RECT  2.16 21.465 218.16 21.735 ;
     RECT  2.16 22.005 218.16 22.275 ;
     RECT  2.16 22.545 218.16 22.815 ;
     RECT  2.16 23.085 218.16 23.355 ;
     RECT  2.16 23.625 218.16 23.895 ;
     RECT  2.16 24.165 218.16 24.435 ;
     RECT  2.16 24.705 218.16 24.975 ;
     RECT  2.16 25.245 218.16 25.515 ;
     RECT  2.16 25.785 218.16 25.92 ;
     RECT  2.16 25.92 20.844 26.055 ;
     RECT  199.692 25.92 218.16 26.055 ;
     RECT  2.16 26.325 20.844 26.595 ;
     RECT  199.692 26.325 218.16 26.595 ;
     RECT  2.16 26.865 20.844 27.135 ;
     RECT  199.692 26.865 218.16 27.135 ;
     RECT  2.16 27.405 20.844 27.675 ;
     RECT  199.692 27.405 218.16 27.675 ;
     RECT  2.16 27.945 20.844 28.215 ;
     RECT  199.692 27.945 218.16 28.215 ;
     RECT  2.16 28.485 20.844 28.755 ;
     RECT  199.692 28.485 218.16 28.755 ;
     RECT  2.16 29.025 20.844 29.295 ;
     RECT  199.692 29.025 218.16 29.295 ;
     RECT  2.16 29.565 20.844 29.835 ;
     RECT  199.692 29.565 218.16 29.835 ;
     RECT  2.16 30.105 20.844 30.375 ;
     RECT  199.692 30.105 218.16 30.375 ;
     RECT  2.16 30.645 20.844 30.915 ;
     RECT  199.692 30.645 218.16 30.915 ;
     RECT  2.16 31.185 20.844 31.455 ;
     RECT  199.692 31.185 218.16 31.455 ;
     RECT  2.16 31.725 20.844 31.995 ;
     RECT  199.692 31.725 218.16 31.995 ;
     RECT  2.16 32.265 20.844 32.535 ;
     RECT  199.692 32.265 218.16 32.535 ;
     RECT  2.16 32.805 20.844 33.075 ;
     RECT  199.692 32.805 218.16 33.075 ;
     RECT  2.16 33.345 20.844 33.615 ;
     RECT  199.692 33.345 218.16 33.615 ;
     RECT  2.16 33.885 20.844 34.155 ;
     RECT  199.692 33.885 218.16 34.155 ;
     RECT  2.16 34.425 20.844 34.695 ;
     RECT  199.692 34.425 218.16 34.695 ;
     RECT  2.16 34.965 20.844 35.235 ;
     RECT  199.692 34.965 218.16 35.235 ;
     RECT  2.16 35.505 20.844 35.775 ;
     RECT  199.692 35.505 218.16 35.775 ;
     RECT  2.16 36.045 20.844 36.315 ;
     RECT  199.692 36.045 218.16 36.315 ;
     RECT  2.16 36.585 20.844 36.855 ;
     RECT  199.692 36.585 218.16 36.855 ;
     RECT  2.16 37.125 20.844 37.395 ;
     RECT  199.692 37.125 218.16 37.395 ;
     RECT  2.16 37.665 20.844 37.935 ;
     RECT  199.692 37.665 218.16 37.935 ;
     RECT  2.16 38.205 20.844 38.475 ;
     RECT  199.692 38.205 218.16 38.475 ;
     RECT  2.16 38.745 20.844 39.015 ;
     RECT  199.692 38.745 218.16 39.015 ;
     RECT  2.16 39.285 20.844 39.555 ;
     RECT  199.692 39.285 218.16 39.555 ;
     RECT  2.16 39.825 20.844 40.095 ;
     RECT  199.692 39.825 218.16 40.095 ;
     RECT  2.16 40.365 20.844 40.635 ;
     RECT  199.692 40.365 218.16 40.635 ;
     RECT  2.16 40.905 20.844 41.175 ;
     RECT  199.692 40.905 218.16 41.175 ;
     RECT  2.16 41.445 20.844 41.715 ;
     RECT  199.692 41.445 218.16 41.715 ;
     RECT  2.16 41.985 20.844 42.255 ;
     RECT  199.692 41.985 218.16 42.255 ;
     RECT  2.16 42.525 20.844 42.795 ;
     RECT  199.692 42.525 218.16 42.795 ;
     RECT  2.16 43.065 20.844 43.335 ;
     RECT  199.692 43.065 218.16 43.335 ;
     RECT  2.16 43.605 20.844 43.875 ;
     RECT  199.692 43.605 218.16 43.875 ;
     RECT  2.16 44.145 20.844 44.415 ;
     RECT  199.692 44.145 218.16 44.415 ;
     RECT  2.16 44.685 20.844 44.955 ;
     RECT  199.692 44.685 218.16 44.955 ;
     RECT  2.16 45.225 20.844 45.495 ;
     RECT  199.692 45.225 218.16 45.495 ;
     RECT  2.16 45.765 20.844 46.035 ;
     RECT  199.692 45.765 218.16 46.035 ;
     RECT  2.16 46.305 20.844 46.575 ;
     RECT  199.692 46.305 218.16 46.575 ;
     RECT  2.16 46.845 20.844 47.115 ;
     RECT  199.692 46.845 218.16 47.115 ;
     RECT  2.16 47.385 20.844 47.655 ;
     RECT  199.692 47.385 218.16 47.655 ;
     RECT  2.16 47.925 20.844 48.195 ;
     RECT  199.692 47.925 218.16 48.195 ;
     RECT  2.16 48.465 20.844 48.735 ;
     RECT  199.692 48.465 218.16 48.735 ;
     RECT  2.16 49.005 20.844 49.275 ;
     RECT  199.692 49.005 218.16 49.275 ;
     RECT  2.16 49.545 20.844 49.815 ;
     RECT  199.692 49.545 218.16 49.815 ;
     RECT  2.16 50.085 20.844 50.355 ;
     RECT  199.692 50.085 218.16 50.355 ;
     RECT  2.16 50.625 20.844 50.895 ;
     RECT  199.692 50.625 218.16 50.895 ;
     RECT  2.16 51.165 20.844 51.435 ;
     RECT  199.692 51.165 218.16 51.435 ;
     RECT  2.16 51.705 20.844 51.975 ;
     RECT  199.692 51.705 218.16 51.975 ;
     RECT  2.16 52.245 20.844 52.515 ;
     RECT  199.692 52.245 218.16 52.515 ;
     RECT  2.16 52.785 20.844 53.055 ;
     RECT  199.692 52.785 218.16 53.055 ;
     RECT  2.16 53.325 20.844 53.595 ;
     RECT  199.692 53.325 218.16 53.595 ;
     RECT  2.16 53.865 20.844 54.135 ;
     RECT  199.692 53.865 218.16 54.135 ;
     RECT  2.16 54.405 20.844 54.675 ;
     RECT  199.692 54.405 218.16 54.675 ;
     RECT  2.16 54.945 20.844 55.215 ;
     RECT  199.692 54.945 218.16 55.215 ;
     RECT  2.16 55.485 20.844 55.755 ;
     RECT  199.692 55.485 218.16 55.755 ;
     RECT  2.16 56.025 20.844 56.295 ;
     RECT  199.692 56.025 218.16 56.295 ;
     RECT  2.16 56.565 20.844 56.835 ;
     RECT  199.692 56.565 218.16 56.835 ;
     RECT  2.16 57.105 20.844 57.375 ;
     RECT  199.692 57.105 218.16 57.375 ;
     RECT  2.16 57.645 20.844 57.915 ;
     RECT  199.692 57.645 218.16 57.915 ;
     RECT  2.16 58.185 20.844 58.455 ;
     RECT  199.692 58.185 218.16 58.455 ;
     RECT  2.16 58.725 20.844 58.995 ;
     RECT  199.692 58.725 218.16 58.995 ;
     RECT  2.16 59.265 20.844 59.535 ;
     RECT  199.692 59.265 218.16 59.535 ;
     RECT  2.16 59.805 20.844 60.075 ;
     RECT  199.692 59.805 218.16 60.075 ;
     RECT  2.16 60.345 20.844 60.615 ;
     RECT  199.692 60.345 218.16 60.615 ;
     RECT  2.16 60.885 20.844 61.155 ;
     RECT  199.692 60.885 218.16 61.155 ;
     RECT  2.16 61.425 20.844 61.695 ;
     RECT  199.692 61.425 218.16 61.695 ;
     RECT  2.16 61.965 20.844 62.235 ;
     RECT  199.692 61.965 218.16 62.235 ;
     RECT  2.16 62.505 20.844 62.775 ;
     RECT  199.692 62.505 218.16 62.775 ;
     RECT  2.16 63.045 20.844 63.315 ;
     RECT  199.692 63.045 218.16 63.315 ;
     RECT  2.16 63.585 20.844 63.855 ;
     RECT  199.692 63.585 218.16 63.855 ;
     RECT  2.16 64.125 20.844 64.395 ;
     RECT  199.692 64.125 218.16 64.395 ;
     RECT  2.16 64.665 20.844 64.935 ;
     RECT  199.692 64.665 218.16 64.935 ;
     RECT  2.16 65.205 20.844 65.475 ;
     RECT  199.692 65.205 218.16 65.475 ;
     RECT  2.16 65.745 20.844 66.015 ;
     RECT  199.692 65.745 218.16 66.015 ;
     RECT  2.16 66.285 20.844 66.555 ;
     RECT  199.692 66.285 218.16 66.555 ;
     RECT  2.16 66.825 20.844 67.095 ;
     RECT  199.692 66.825 218.16 67.095 ;
     RECT  2.16 67.365 20.844 67.635 ;
     RECT  199.692 67.365 218.16 67.635 ;
     RECT  2.16 67.905 20.844 68.175 ;
     RECT  199.692 67.905 218.16 68.175 ;
     RECT  2.16 68.445 20.844 68.715 ;
     RECT  199.692 68.445 218.16 68.715 ;
     RECT  2.16 68.985 20.844 69.255 ;
     RECT  199.692 68.985 218.16 69.255 ;
     RECT  2.16 69.525 20.844 69.795 ;
     RECT  199.692 69.525 218.16 69.795 ;
     RECT  2.16 70.065 20.844 70.335 ;
     RECT  199.692 70.065 218.16 70.335 ;
     RECT  2.16 70.605 20.844 70.875 ;
     RECT  199.692 70.605 218.16 70.875 ;
     RECT  2.16 71.145 20.844 71.415 ;
     RECT  199.692 71.145 218.16 71.415 ;
     RECT  2.16 71.685 20.844 71.955 ;
     RECT  199.692 71.685 218.16 71.955 ;
     RECT  2.16 72.225 20.844 72.495 ;
     RECT  199.692 72.225 218.16 72.495 ;
     RECT  2.16 72.765 20.844 73.035 ;
     RECT  199.692 72.765 218.16 73.035 ;
     RECT  2.16 73.305 20.844 73.575 ;
     RECT  199.692 73.305 218.16 73.575 ;
     RECT  2.16 73.845 20.844 74.115 ;
     RECT  199.692 73.845 218.16 74.115 ;
     RECT  2.16 74.385 20.844 74.655 ;
     RECT  199.692 74.385 218.16 74.655 ;
     RECT  2.16 74.925 20.844 75.195 ;
     RECT  199.692 74.925 218.16 75.195 ;
     RECT  2.16 75.465 20.844 75.735 ;
     RECT  199.692 75.465 218.16 75.735 ;
     RECT  2.16 76.005 20.844 76.275 ;
     RECT  199.692 76.005 218.16 76.275 ;
     RECT  2.16 76.545 20.844 76.815 ;
     RECT  199.692 76.545 218.16 76.815 ;
     RECT  2.16 77.085 20.844 77.355 ;
     RECT  199.692 77.085 218.16 77.355 ;
     RECT  2.16 77.625 20.844 77.895 ;
     RECT  199.692 77.625 218.16 77.895 ;
     RECT  2.16 78.165 20.844 78.435 ;
     RECT  199.692 78.165 218.16 78.435 ;
     RECT  2.16 78.705 20.844 78.975 ;
     RECT  199.692 78.705 218.16 78.975 ;
     RECT  2.16 79.245 20.844 79.515 ;
     RECT  199.692 79.245 218.16 79.515 ;
     RECT  2.16 79.785 20.844 80.055 ;
     RECT  199.692 79.785 218.16 80.055 ;
     RECT  2.16 80.325 20.844 80.595 ;
     RECT  199.692 80.325 218.16 80.595 ;
     RECT  2.16 80.865 20.844 81.135 ;
     RECT  199.692 80.865 218.16 81.135 ;
     RECT  2.16 81.405 20.844 81.675 ;
     RECT  199.692 81.405 218.16 81.675 ;
     RECT  2.16 81.945 20.844 82.215 ;
     RECT  199.692 81.945 218.16 82.215 ;
     RECT  2.16 82.485 20.844 82.755 ;
     RECT  199.692 82.485 218.16 82.755 ;
     RECT  2.16 83.025 20.844 83.295 ;
     RECT  199.692 83.025 218.16 83.295 ;
     RECT  2.16 83.565 20.844 83.835 ;
     RECT  199.692 83.565 218.16 83.835 ;
     RECT  2.16 84.105 20.844 84.375 ;
     RECT  199.692 84.105 218.16 84.375 ;
     RECT  2.16 84.645 20.844 84.915 ;
     RECT  199.692 84.645 218.16 84.915 ;
     RECT  2.16 85.185 20.844 85.455 ;
     RECT  199.692 85.185 218.16 85.455 ;
     RECT  2.16 85.725 20.844 85.995 ;
     RECT  199.692 85.725 218.16 85.995 ;
     RECT  2.16 86.265 20.844 86.535 ;
     RECT  199.692 86.265 218.16 86.535 ;
     RECT  2.16 86.805 20.844 87.075 ;
     RECT  199.692 86.805 218.16 87.075 ;
     RECT  2.16 87.345 20.844 87.615 ;
     RECT  199.692 87.345 218.16 87.615 ;
     RECT  2.16 87.885 20.844 88.155 ;
     RECT  199.692 87.885 218.16 88.155 ;
     RECT  2.16 88.425 20.844 88.695 ;
     RECT  199.692 88.425 218.16 88.695 ;
     RECT  2.16 88.965 20.844 89.235 ;
     RECT  199.692 88.965 218.16 89.235 ;
     RECT  2.16 89.505 20.844 89.775 ;
     RECT  199.692 89.505 218.16 89.775 ;
     RECT  2.16 90.045 20.844 90.315 ;
     RECT  199.692 90.045 218.16 90.315 ;
     RECT  2.16 90.585 20.844 90.855 ;
     RECT  199.692 90.585 218.16 90.855 ;
     RECT  2.16 91.125 20.844 91.395 ;
     RECT  199.692 91.125 218.16 91.395 ;
     RECT  2.16 91.665 20.844 91.935 ;
     RECT  199.692 91.665 218.16 91.935 ;
     RECT  2.16 92.205 20.844 92.475 ;
     RECT  199.692 92.205 218.16 92.475 ;
     RECT  2.16 92.745 20.844 93.015 ;
     RECT  199.692 92.745 218.16 93.015 ;
     RECT  2.16 93.285 20.844 93.555 ;
     RECT  199.692 93.285 218.16 93.555 ;
     RECT  2.16 93.825 20.844 94.095 ;
     RECT  199.692 93.825 218.16 94.095 ;
     RECT  2.16 94.365 20.844 94.635 ;
     RECT  199.692 94.365 218.16 94.635 ;
     RECT  2.16 94.905 20.844 95.175 ;
     RECT  199.692 94.905 218.16 95.175 ;
     RECT  2.16 95.445 20.844 95.715 ;
     RECT  199.692 95.445 218.16 95.715 ;
     RECT  2.16 95.985 20.844 96.255 ;
     RECT  199.692 95.985 218.16 96.255 ;
     RECT  2.16 96.525 20.844 96.795 ;
     RECT  199.692 96.525 218.16 96.795 ;
     RECT  2.16 97.065 20.844 97.335 ;
     RECT  199.692 97.065 218.16 97.335 ;
     RECT  2.16 97.605 20.844 97.875 ;
     RECT  199.692 97.605 218.16 97.875 ;
     RECT  2.16 98.145 20.844 98.415 ;
     RECT  199.692 98.145 218.16 98.415 ;
     RECT  2.16 98.685 20.844 98.955 ;
     RECT  199.692 98.685 218.16 98.955 ;
     RECT  2.16 99.225 20.844 99.495 ;
     RECT  199.692 99.225 218.16 99.495 ;
     RECT  2.16 99.765 20.844 100.035 ;
     RECT  199.692 99.765 218.16 100.035 ;
     RECT  2.16 100.305 20.844 100.575 ;
     RECT  199.692 100.305 218.16 100.575 ;
     RECT  2.16 100.845 218.16 101.115 ;
     RECT  2.16 101.385 218.16 101.655 ;
     RECT  2.16 101.925 218.16 102.195 ;
     RECT  2.16 102.465 218.16 102.735 ;
     RECT  2.16 103.005 218.16 103.275 ;
     RECT  2.16 103.545 218.16 103.815 ;
     RECT  2.16 104.085 218.16 104.355 ;
     RECT  2.16 104.625 218.16 104.895 ;
     RECT  2.16 105.165 218.16 105.435 ;
     RECT  2.16 105.705 218.16 105.975 ;
     RECT  2.16 106.245 218.16 106.515 ;
     RECT  2.16 106.785 218.16 107.055 ;
     RECT  2.16 107.325 218.16 107.595 ;
     RECT  2.16 107.865 218.16 108.135 ;
     RECT  2.16 108.405 218.16 108.675 ;
     RECT  2.16 108.945 218.16 109.215 ;
     RECT  2.16 109.485 218.16 109.755 ;
     RECT  2.16 110.025 218.16 110.295 ;
     RECT  2.16 110.565 218.16 110.835 ;
     RECT  2.16 111.105 218.16 111.375 ;
     RECT  2.16 111.645 218.16 111.915 ;
     RECT  2.16 112.185 218.16 112.455 ;
     RECT  2.16 112.725 218.16 112.995 ;
     RECT  2.16 113.265 218.16 113.535 ;
     RECT  2.16 113.805 218.16 114.075 ;
     RECT  2.16 114.345 218.16 114.615 ;
     RECT  2.16 114.885 218.16 115.155 ;
     RECT  2.16 115.425 218.16 115.695 ;
     RECT  2.16 115.965 218.16 116.235 ;
     RECT  2.16 116.505 218.16 116.775 ;
     RECT  2.16 117.045 218.16 117.315 ;
     RECT  2.16 117.585 218.16 117.855 ;
     RECT  2.16 118.125 218.16 118.395 ;
     RECT  2.16 118.665 218.16 118.935 ;
     RECT  2.16 119.205 218.16 119.475 ;
     RECT  2.16 119.745 218.16 120.015 ;
     RECT  2.16 120.285 218.16 120.555 ;
     RECT  2.16 120.825 218.16 121.095 ;
     RECT  2.16 121.365 218.16 121.635 ;
     RECT  2.16 121.905 218.16 122.175 ;
     RECT  2.16 122.445 218.16 122.715 ;
     RECT  2.16 122.985 218.16 123.255 ;
     RECT  2.16 123.525 218.16 123.795 ;
     RECT  2.16 124.065 218.16 124.335 ;
     RECT  2.16 124.605 218.16 124.875 ;
     RECT  2.16 125.145 218.16 125.415 ;
     RECT  2.16 125.685 218.16 125.955 ;
     RECT  2.16 126.225 218.16 126.495 ;
     RECT  2.16 126.765 218.16 127.035 ;
     RECT  2.16 127.305 218.16 127.44 ;
    LAYER RVTP ;
     RECT  2.16 2.295 218.16 2.565 ;
     RECT  2.16 2.835 218.16 3.105 ;
     RECT  2.16 3.375 218.16 3.645 ;
     RECT  2.16 3.915 218.16 4.185 ;
     RECT  2.16 4.455 218.16 4.725 ;
     RECT  2.16 4.995 218.16 5.265 ;
     RECT  2.16 5.535 218.16 5.805 ;
     RECT  2.16 6.075 218.16 6.345 ;
     RECT  2.16 6.615 218.16 6.885 ;
     RECT  2.16 7.155 218.16 7.425 ;
     RECT  2.16 7.695 218.16 7.965 ;
     RECT  2.16 8.235 218.16 8.505 ;
     RECT  2.16 8.775 218.16 9.045 ;
     RECT  2.16 9.315 218.16 9.585 ;
     RECT  2.16 9.855 218.16 10.125 ;
     RECT  2.16 10.395 218.16 10.665 ;
     RECT  2.16 10.935 218.16 11.205 ;
     RECT  2.16 11.475 218.16 11.745 ;
     RECT  2.16 12.015 218.16 12.285 ;
     RECT  2.16 12.555 218.16 12.825 ;
     RECT  2.16 13.095 218.16 13.365 ;
     RECT  2.16 13.635 218.16 13.905 ;
     RECT  2.16 14.175 218.16 14.445 ;
     RECT  2.16 14.715 218.16 14.985 ;
     RECT  2.16 15.255 218.16 15.525 ;
     RECT  2.16 15.795 218.16 16.065 ;
     RECT  2.16 16.335 218.16 16.605 ;
     RECT  2.16 16.875 218.16 17.145 ;
     RECT  2.16 17.415 218.16 17.685 ;
     RECT  2.16 17.955 218.16 18.225 ;
     RECT  2.16 18.495 218.16 18.765 ;
     RECT  2.16 19.035 218.16 19.305 ;
     RECT  2.16 19.575 218.16 19.845 ;
     RECT  2.16 20.115 218.16 20.385 ;
     RECT  2.16 20.655 218.16 20.925 ;
     RECT  2.16 21.195 218.16 21.465 ;
     RECT  2.16 21.735 218.16 22.005 ;
     RECT  2.16 22.275 218.16 22.545 ;
     RECT  2.16 22.815 218.16 23.085 ;
     RECT  2.16 23.355 218.16 23.625 ;
     RECT  2.16 23.895 218.16 24.165 ;
     RECT  2.16 24.435 218.16 24.705 ;
     RECT  2.16 24.975 218.16 25.245 ;
     RECT  2.16 25.515 218.16 25.785 ;
     RECT  2.16 26.055 20.844 26.325 ;
     RECT  199.692 26.055 218.16 26.325 ;
     RECT  2.16 26.595 20.844 26.865 ;
     RECT  199.692 26.595 218.16 26.865 ;
     RECT  2.16 27.135 20.844 27.405 ;
     RECT  199.692 27.135 218.16 27.405 ;
     RECT  2.16 27.675 20.844 27.945 ;
     RECT  199.692 27.675 218.16 27.945 ;
     RECT  2.16 28.215 20.844 28.485 ;
     RECT  199.692 28.215 218.16 28.485 ;
     RECT  2.16 28.755 20.844 29.025 ;
     RECT  199.692 28.755 218.16 29.025 ;
     RECT  2.16 29.295 20.844 29.565 ;
     RECT  199.692 29.295 218.16 29.565 ;
     RECT  2.16 29.835 20.844 30.105 ;
     RECT  199.692 29.835 218.16 30.105 ;
     RECT  2.16 30.375 20.844 30.645 ;
     RECT  199.692 30.375 218.16 30.645 ;
     RECT  2.16 30.915 20.844 31.185 ;
     RECT  199.692 30.915 218.16 31.185 ;
     RECT  2.16 31.455 20.844 31.725 ;
     RECT  199.692 31.455 218.16 31.725 ;
     RECT  2.16 31.995 20.844 32.265 ;
     RECT  199.692 31.995 218.16 32.265 ;
     RECT  2.16 32.535 20.844 32.805 ;
     RECT  199.692 32.535 218.16 32.805 ;
     RECT  2.16 33.075 20.844 33.345 ;
     RECT  199.692 33.075 218.16 33.345 ;
     RECT  2.16 33.615 20.844 33.885 ;
     RECT  199.692 33.615 218.16 33.885 ;
     RECT  2.16 34.155 20.844 34.425 ;
     RECT  199.692 34.155 218.16 34.425 ;
     RECT  2.16 34.695 20.844 34.965 ;
     RECT  199.692 34.695 218.16 34.965 ;
     RECT  2.16 35.235 20.844 35.505 ;
     RECT  199.692 35.235 218.16 35.505 ;
     RECT  2.16 35.775 20.844 36.045 ;
     RECT  199.692 35.775 218.16 36.045 ;
     RECT  2.16 36.315 20.844 36.585 ;
     RECT  199.692 36.315 218.16 36.585 ;
     RECT  2.16 36.855 20.844 37.125 ;
     RECT  199.692 36.855 218.16 37.125 ;
     RECT  2.16 37.395 20.844 37.665 ;
     RECT  199.692 37.395 218.16 37.665 ;
     RECT  2.16 37.935 20.844 38.205 ;
     RECT  199.692 37.935 218.16 38.205 ;
     RECT  2.16 38.475 20.844 38.745 ;
     RECT  199.692 38.475 218.16 38.745 ;
     RECT  2.16 39.015 20.844 39.285 ;
     RECT  199.692 39.015 218.16 39.285 ;
     RECT  2.16 39.555 20.844 39.825 ;
     RECT  199.692 39.555 218.16 39.825 ;
     RECT  2.16 40.095 20.844 40.365 ;
     RECT  199.692 40.095 218.16 40.365 ;
     RECT  2.16 40.635 20.844 40.905 ;
     RECT  199.692 40.635 218.16 40.905 ;
     RECT  2.16 41.175 20.844 41.445 ;
     RECT  199.692 41.175 218.16 41.445 ;
     RECT  2.16 41.715 20.844 41.985 ;
     RECT  199.692 41.715 218.16 41.985 ;
     RECT  2.16 42.255 20.844 42.525 ;
     RECT  199.692 42.255 218.16 42.525 ;
     RECT  2.16 42.795 20.844 43.065 ;
     RECT  199.692 42.795 218.16 43.065 ;
     RECT  2.16 43.335 20.844 43.605 ;
     RECT  199.692 43.335 218.16 43.605 ;
     RECT  2.16 43.875 20.844 44.145 ;
     RECT  199.692 43.875 218.16 44.145 ;
     RECT  2.16 44.415 20.844 44.685 ;
     RECT  199.692 44.415 218.16 44.685 ;
     RECT  2.16 44.955 20.844 45.225 ;
     RECT  199.692 44.955 218.16 45.225 ;
     RECT  2.16 45.495 20.844 45.765 ;
     RECT  199.692 45.495 218.16 45.765 ;
     RECT  2.16 46.035 20.844 46.305 ;
     RECT  199.692 46.035 218.16 46.305 ;
     RECT  2.16 46.575 20.844 46.845 ;
     RECT  199.692 46.575 218.16 46.845 ;
     RECT  2.16 47.115 20.844 47.385 ;
     RECT  199.692 47.115 218.16 47.385 ;
     RECT  2.16 47.655 20.844 47.925 ;
     RECT  199.692 47.655 218.16 47.925 ;
     RECT  2.16 48.195 20.844 48.465 ;
     RECT  199.692 48.195 218.16 48.465 ;
     RECT  2.16 48.735 20.844 49.005 ;
     RECT  199.692 48.735 218.16 49.005 ;
     RECT  2.16 49.275 20.844 49.545 ;
     RECT  199.692 49.275 218.16 49.545 ;
     RECT  2.16 49.815 20.844 50.085 ;
     RECT  199.692 49.815 218.16 50.085 ;
     RECT  2.16 50.355 20.844 50.625 ;
     RECT  199.692 50.355 218.16 50.625 ;
     RECT  2.16 50.895 20.844 51.165 ;
     RECT  199.692 50.895 218.16 51.165 ;
     RECT  2.16 51.435 20.844 51.705 ;
     RECT  199.692 51.435 218.16 51.705 ;
     RECT  2.16 51.975 20.844 52.245 ;
     RECT  199.692 51.975 218.16 52.245 ;
     RECT  2.16 52.515 20.844 52.785 ;
     RECT  199.692 52.515 218.16 52.785 ;
     RECT  2.16 53.055 20.844 53.325 ;
     RECT  199.692 53.055 218.16 53.325 ;
     RECT  2.16 53.595 20.844 53.865 ;
     RECT  199.692 53.595 218.16 53.865 ;
     RECT  2.16 54.135 20.844 54.405 ;
     RECT  199.692 54.135 218.16 54.405 ;
     RECT  2.16 54.675 20.844 54.945 ;
     RECT  199.692 54.675 218.16 54.945 ;
     RECT  2.16 55.215 20.844 55.485 ;
     RECT  199.692 55.215 218.16 55.485 ;
     RECT  2.16 55.755 20.844 56.025 ;
     RECT  199.692 55.755 218.16 56.025 ;
     RECT  2.16 56.295 20.844 56.565 ;
     RECT  199.692 56.295 218.16 56.565 ;
     RECT  2.16 56.835 20.844 57.105 ;
     RECT  199.692 56.835 218.16 57.105 ;
     RECT  2.16 57.375 20.844 57.645 ;
     RECT  199.692 57.375 218.16 57.645 ;
     RECT  2.16 57.915 20.844 58.185 ;
     RECT  199.692 57.915 218.16 58.185 ;
     RECT  2.16 58.455 20.844 58.725 ;
     RECT  199.692 58.455 218.16 58.725 ;
     RECT  2.16 58.995 20.844 59.265 ;
     RECT  199.692 58.995 218.16 59.265 ;
     RECT  2.16 59.535 20.844 59.805 ;
     RECT  199.692 59.535 218.16 59.805 ;
     RECT  2.16 60.075 20.844 60.345 ;
     RECT  199.692 60.075 218.16 60.345 ;
     RECT  2.16 60.615 20.844 60.885 ;
     RECT  199.692 60.615 218.16 60.885 ;
     RECT  2.16 61.155 20.844 61.425 ;
     RECT  199.692 61.155 218.16 61.425 ;
     RECT  2.16 61.695 20.844 61.965 ;
     RECT  199.692 61.695 218.16 61.965 ;
     RECT  2.16 62.235 20.844 62.505 ;
     RECT  199.692 62.235 218.16 62.505 ;
     RECT  2.16 62.775 20.844 63.045 ;
     RECT  199.692 62.775 218.16 63.045 ;
     RECT  2.16 63.315 20.844 63.585 ;
     RECT  199.692 63.315 218.16 63.585 ;
     RECT  2.16 63.855 20.844 64.125 ;
     RECT  199.692 63.855 218.16 64.125 ;
     RECT  2.16 64.395 20.844 64.665 ;
     RECT  199.692 64.395 218.16 64.665 ;
     RECT  2.16 64.935 20.844 65.205 ;
     RECT  199.692 64.935 218.16 65.205 ;
     RECT  2.16 65.475 20.844 65.745 ;
     RECT  199.692 65.475 218.16 65.745 ;
     RECT  2.16 66.015 20.844 66.285 ;
     RECT  199.692 66.015 218.16 66.285 ;
     RECT  2.16 66.555 20.844 66.825 ;
     RECT  199.692 66.555 218.16 66.825 ;
     RECT  2.16 67.095 20.844 67.365 ;
     RECT  199.692 67.095 218.16 67.365 ;
     RECT  2.16 67.635 20.844 67.905 ;
     RECT  199.692 67.635 218.16 67.905 ;
     RECT  2.16 68.175 20.844 68.445 ;
     RECT  199.692 68.175 218.16 68.445 ;
     RECT  2.16 68.715 20.844 68.985 ;
     RECT  199.692 68.715 218.16 68.985 ;
     RECT  2.16 69.255 20.844 69.525 ;
     RECT  199.692 69.255 218.16 69.525 ;
     RECT  2.16 69.795 20.844 70.065 ;
     RECT  199.692 69.795 218.16 70.065 ;
     RECT  2.16 70.335 20.844 70.605 ;
     RECT  199.692 70.335 218.16 70.605 ;
     RECT  2.16 70.875 20.844 71.145 ;
     RECT  199.692 70.875 218.16 71.145 ;
     RECT  2.16 71.415 20.844 71.685 ;
     RECT  199.692 71.415 218.16 71.685 ;
     RECT  2.16 71.955 20.844 72.225 ;
     RECT  199.692 71.955 218.16 72.225 ;
     RECT  2.16 72.495 20.844 72.765 ;
     RECT  199.692 72.495 218.16 72.765 ;
     RECT  2.16 73.035 20.844 73.305 ;
     RECT  199.692 73.035 218.16 73.305 ;
     RECT  2.16 73.575 20.844 73.845 ;
     RECT  199.692 73.575 218.16 73.845 ;
     RECT  2.16 74.115 20.844 74.385 ;
     RECT  199.692 74.115 218.16 74.385 ;
     RECT  2.16 74.655 20.844 74.925 ;
     RECT  199.692 74.655 218.16 74.925 ;
     RECT  2.16 75.195 20.844 75.465 ;
     RECT  199.692 75.195 218.16 75.465 ;
     RECT  2.16 75.735 20.844 76.005 ;
     RECT  199.692 75.735 218.16 76.005 ;
     RECT  2.16 76.275 20.844 76.545 ;
     RECT  199.692 76.275 218.16 76.545 ;
     RECT  2.16 76.815 20.844 77.085 ;
     RECT  199.692 76.815 218.16 77.085 ;
     RECT  2.16 77.355 20.844 77.625 ;
     RECT  199.692 77.355 218.16 77.625 ;
     RECT  2.16 77.895 20.844 78.165 ;
     RECT  199.692 77.895 218.16 78.165 ;
     RECT  2.16 78.435 20.844 78.705 ;
     RECT  199.692 78.435 218.16 78.705 ;
     RECT  2.16 78.975 20.844 79.245 ;
     RECT  199.692 78.975 218.16 79.245 ;
     RECT  2.16 79.515 20.844 79.785 ;
     RECT  199.692 79.515 218.16 79.785 ;
     RECT  2.16 80.055 20.844 80.325 ;
     RECT  199.692 80.055 218.16 80.325 ;
     RECT  2.16 80.595 20.844 80.865 ;
     RECT  199.692 80.595 218.16 80.865 ;
     RECT  2.16 81.135 20.844 81.405 ;
     RECT  199.692 81.135 218.16 81.405 ;
     RECT  2.16 81.675 20.844 81.945 ;
     RECT  199.692 81.675 218.16 81.945 ;
     RECT  2.16 82.215 20.844 82.485 ;
     RECT  199.692 82.215 218.16 82.485 ;
     RECT  2.16 82.755 20.844 83.025 ;
     RECT  199.692 82.755 218.16 83.025 ;
     RECT  2.16 83.295 20.844 83.565 ;
     RECT  199.692 83.295 218.16 83.565 ;
     RECT  2.16 83.835 20.844 84.105 ;
     RECT  199.692 83.835 218.16 84.105 ;
     RECT  2.16 84.375 20.844 84.645 ;
     RECT  199.692 84.375 218.16 84.645 ;
     RECT  2.16 84.915 20.844 85.185 ;
     RECT  199.692 84.915 218.16 85.185 ;
     RECT  2.16 85.455 20.844 85.725 ;
     RECT  199.692 85.455 218.16 85.725 ;
     RECT  2.16 85.995 20.844 86.265 ;
     RECT  199.692 85.995 218.16 86.265 ;
     RECT  2.16 86.535 20.844 86.805 ;
     RECT  199.692 86.535 218.16 86.805 ;
     RECT  2.16 87.075 20.844 87.345 ;
     RECT  199.692 87.075 218.16 87.345 ;
     RECT  2.16 87.615 20.844 87.885 ;
     RECT  199.692 87.615 218.16 87.885 ;
     RECT  2.16 88.155 20.844 88.425 ;
     RECT  199.692 88.155 218.16 88.425 ;
     RECT  2.16 88.695 20.844 88.965 ;
     RECT  199.692 88.695 218.16 88.965 ;
     RECT  2.16 89.235 20.844 89.505 ;
     RECT  199.692 89.235 218.16 89.505 ;
     RECT  2.16 89.775 20.844 90.045 ;
     RECT  199.692 89.775 218.16 90.045 ;
     RECT  2.16 90.315 20.844 90.585 ;
     RECT  199.692 90.315 218.16 90.585 ;
     RECT  2.16 90.855 20.844 91.125 ;
     RECT  199.692 90.855 218.16 91.125 ;
     RECT  2.16 91.395 20.844 91.665 ;
     RECT  199.692 91.395 218.16 91.665 ;
     RECT  2.16 91.935 20.844 92.205 ;
     RECT  199.692 91.935 218.16 92.205 ;
     RECT  2.16 92.475 20.844 92.745 ;
     RECT  199.692 92.475 218.16 92.745 ;
     RECT  2.16 93.015 20.844 93.285 ;
     RECT  199.692 93.015 218.16 93.285 ;
     RECT  2.16 93.555 20.844 93.825 ;
     RECT  199.692 93.555 218.16 93.825 ;
     RECT  2.16 94.095 20.844 94.365 ;
     RECT  199.692 94.095 218.16 94.365 ;
     RECT  2.16 94.635 20.844 94.905 ;
     RECT  199.692 94.635 218.16 94.905 ;
     RECT  2.16 95.175 20.844 95.445 ;
     RECT  199.692 95.175 218.16 95.445 ;
     RECT  2.16 95.715 20.844 95.985 ;
     RECT  199.692 95.715 218.16 95.985 ;
     RECT  2.16 96.255 20.844 96.525 ;
     RECT  199.692 96.255 218.16 96.525 ;
     RECT  2.16 96.795 20.844 97.065 ;
     RECT  199.692 96.795 218.16 97.065 ;
     RECT  2.16 97.335 20.844 97.605 ;
     RECT  199.692 97.335 218.16 97.605 ;
     RECT  2.16 97.875 20.844 98.145 ;
     RECT  199.692 97.875 218.16 98.145 ;
     RECT  2.16 98.415 20.844 98.685 ;
     RECT  199.692 98.415 218.16 98.685 ;
     RECT  2.16 98.955 20.844 99.225 ;
     RECT  199.692 98.955 218.16 99.225 ;
     RECT  2.16 99.495 20.844 99.765 ;
     RECT  199.692 99.495 218.16 99.765 ;
     RECT  2.16 100.035 20.844 100.305 ;
     RECT  199.692 100.035 218.16 100.305 ;
     RECT  2.16 100.575 20.844 100.71 ;
     RECT  199.692 100.575 218.16 100.71 ;
     RECT  2.16 100.71 218.16 100.845 ;
     RECT  2.16 101.115 218.16 101.385 ;
     RECT  2.16 101.655 218.16 101.925 ;
     RECT  2.16 102.195 218.16 102.465 ;
     RECT  2.16 102.735 218.16 103.005 ;
     RECT  2.16 103.275 218.16 103.545 ;
     RECT  2.16 103.815 218.16 104.085 ;
     RECT  2.16 104.355 218.16 104.625 ;
     RECT  2.16 104.895 218.16 105.165 ;
     RECT  2.16 105.435 218.16 105.705 ;
     RECT  2.16 105.975 218.16 106.245 ;
     RECT  2.16 106.515 218.16 106.785 ;
     RECT  2.16 107.055 218.16 107.325 ;
     RECT  2.16 107.595 218.16 107.865 ;
     RECT  2.16 108.135 218.16 108.405 ;
     RECT  2.16 108.675 218.16 108.945 ;
     RECT  2.16 109.215 218.16 109.485 ;
     RECT  2.16 109.755 218.16 110.025 ;
     RECT  2.16 110.295 218.16 110.565 ;
     RECT  2.16 110.835 218.16 111.105 ;
     RECT  2.16 111.375 218.16 111.645 ;
     RECT  2.16 111.915 218.16 112.185 ;
     RECT  2.16 112.455 218.16 112.725 ;
     RECT  2.16 112.995 218.16 113.265 ;
     RECT  2.16 113.535 218.16 113.805 ;
     RECT  2.16 114.075 218.16 114.345 ;
     RECT  2.16 114.615 218.16 114.885 ;
     RECT  2.16 115.155 218.16 115.425 ;
     RECT  2.16 115.695 218.16 115.965 ;
     RECT  2.16 116.235 218.16 116.505 ;
     RECT  2.16 116.775 218.16 117.045 ;
     RECT  2.16 117.315 218.16 117.585 ;
     RECT  2.16 117.855 218.16 118.125 ;
     RECT  2.16 118.395 218.16 118.665 ;
     RECT  2.16 118.935 218.16 119.205 ;
     RECT  2.16 119.475 218.16 119.745 ;
     RECT  2.16 120.015 218.16 120.285 ;
     RECT  2.16 120.555 218.16 120.825 ;
     RECT  2.16 121.095 218.16 121.365 ;
     RECT  2.16 121.635 218.16 121.905 ;
     RECT  2.16 122.175 218.16 122.445 ;
     RECT  2.16 122.715 218.16 122.985 ;
     RECT  2.16 123.255 218.16 123.525 ;
     RECT  2.16 123.795 218.16 124.065 ;
     RECT  2.16 124.335 218.16 124.605 ;
     RECT  2.16 124.875 218.16 125.145 ;
     RECT  2.16 125.415 218.16 125.685 ;
     RECT  2.16 125.955 218.16 126.225 ;
     RECT  2.16 126.495 218.16 126.765 ;
     RECT  2.16 127.035 218.16 127.305 ;
    LAYER M1 ;
     RECT  2.16 2.151 218.16 25.929 ;
     RECT  22.896 28.08 197.64 98.55 ;
     RECT  2.16 25.929 20.844 100.701 ;
     RECT  199.692 25.929 218.16 100.701 ;
     RECT  2.16 100.701 218.16 127.449 ;
    LAYER M2 ;
     RECT  0.067 28.152 0.103 28.17 ;
     RECT  0.103 24.912 0.139 24.93 ;
     RECT  0.103 26.262 0.139 26.28 ;
     RECT  0.103 35.172 0.139 35.19 ;
     RECT  0.103 36.522 0.139 36.54 ;
     RECT  0.103 54.072 0.139 54.63 ;
     RECT  0.103 59.814 0.139 59.832 ;
     RECT  0.103 61.632 0.139 62.838 ;
     RECT  0.103 64.332 0.139 67.32 ;
     RECT  0.103 79.056 0.139 79.074 ;
     RECT  0.103 81.072 0.139 81.09 ;
     RECT  0.103 91.062 0.139 91.08 ;
     RECT  0.103 92.952 0.139 92.97 ;
     RECT  0.103 94.032 0.139 94.59 ;
     RECT  0.103 97.542 0.139 97.56 ;
     RECT  0.103 111.852 0.139 111.87 ;
     RECT  0.103 21.942 0.535 21.96 ;
     RECT  0.103 22.752 0.535 23.31 ;
     RECT  0.139 24.912 0.535 26.28 ;
     RECT  0.103 27.072 0.535 28.17 ;
     RECT  0.103 44.73 0.535 44.748 ;
     RECT  0.103 56.61 0.535 56.628 ;
     RECT  0.103 57.42 0.535 57.438 ;
     RECT  0.103 69.462 0.535 69.48 ;
     RECT  0.103 86.202 0.535 86.22 ;
     RECT  0.103 88.092 0.535 90.036 ;
     RECT  0.103 95.958 0.535 95.976 ;
     RECT  0.103 105.75 0.535 105.768 ;
     RECT  0.103 119.52 0.535 121.32 ;
     RECT  0.103 14.112 1.147 14.436 ;
     RECT  0.535 21.942 1.147 23.31 ;
     RECT  0.535 24.912 1.147 28.17 ;
     RECT  0.103 29.232 1.147 29.25 ;
     RECT  0.103 33.012 1.147 33.408 ;
     RECT  0.535 44.73 1.147 45.288 ;
     RECT  0.103 52.29 1.147 52.848 ;
     RECT  0.139 59.58 1.147 59.832 ;
     RECT  0.139 60.93 1.147 62.838 ;
     RECT  0.139 64.17 1.147 67.32 ;
     RECT  0.103 71.964 1.147 72.216 ;
     RECT  0.535 73.08 1.147 73.098 ;
     RECT  0.139 79.02 1.147 79.074 ;
     RECT  0.535 82.494 1.147 82.512 ;
     RECT  0.103 84.582 1.147 84.87 ;
     RECT  0.535 86.202 1.147 86.832 ;
     RECT  0.535 87.66 1.147 90.036 ;
     RECT  0.139 90.9 1.147 91.08 ;
     RECT  0.535 95.724 1.147 95.976 ;
     RECT  0.103 99.972 1.147 99.99 ;
     RECT  0.103 109.422 1.147 109.71 ;
     RECT  0.535 119.25 1.147 121.32 ;
     RECT  1.147 8.442 1.183 8.46 ;
     RECT  1.147 71.964 1.183 72.288 ;
     RECT  1.147 123.192 1.183 123.21 ;
     RECT  1.183 8.442 1.219 9 ;
     RECT  1.147 9.792 1.219 9.81 ;
     RECT  1.183 101.322 1.219 101.34 ;
     RECT  1.147 102.132 1.219 102.15 ;
     RECT  1.183 123.192 1.219 123.48 ;
     RECT  1.219 123.192 1.255 123.75 ;
     RECT  0.103 41.76 1.291 42.48 ;
     RECT  0.103 76.05 1.291 76.77 ;
     RECT  1.147 73.08 1.327 73.8 ;
     RECT  0.103 39.222 1.435 39.51 ;
     RECT  1.147 99.972 1.687 100.53 ;
     RECT  1.219 101.322 1.687 102.15 ;
     RECT  0.103 6.39 1.723 6.84 ;
     RECT  0.103 11.142 1.723 11.16 ;
     RECT  0.103 12.492 1.723 13.05 ;
     RECT  1.147 21.672 1.723 23.31 ;
     RECT  1.147 24.642 1.723 28.17 ;
     RECT  1.147 33.012 1.723 33.57 ;
     RECT  0.103 37.332 1.723 38.16 ;
     RECT  1.435 39.222 1.723 39.582 ;
     RECT  1.147 40.842 1.723 40.86 ;
     RECT  1.291 41.76 1.723 42.552 ;
     RECT  0.103 51.102 1.723 51.498 ;
     RECT  0.139 53.91 1.723 54.63 ;
     RECT  0.535 68.796 1.723 69.48 ;
     RECT  0.103 70.614 1.723 70.632 ;
     RECT  1.183 71.892 1.723 72.288 ;
     RECT  1.327 73.08 1.723 73.908 ;
     RECT  0.103 75.204 1.723 75.222 ;
     RECT  0.139 80.262 1.723 81.36 ;
     RECT  1.147 82.422 1.723 82.512 ;
     RECT  0.139 97.308 1.723 97.668 ;
     RECT  0.535 105.75 1.723 106.2 ;
     RECT  1.147 107.532 1.723 107.55 ;
     RECT  0.103 113.202 1.723 114.84 ;
     RECT  0.103 118.332 1.723 118.35 ;
     RECT  0.103 4.392 2.16 4.41 ;
     RECT  1.723 6.39 2.16 7.38 ;
     RECT  1.219 8.442 2.16 9.81 ;
     RECT  1.723 11.142 2.16 13.05 ;
     RECT  1.147 14.112 2.16 15.21 ;
     RECT  1.723 17.082 2.16 17.1 ;
     RECT  0.103 18.702 2.16 20.178 ;
     RECT  1.723 21.672 2.16 23.85 ;
     RECT  1.723 24.642 2.16 28.476 ;
     RECT  1.147 29.232 2.16 29.322 ;
     RECT  0.103 30.582 2.16 31.14 ;
     RECT  0.103 31.932 2.16 31.95 ;
     RECT  1.723 33.012 2.16 34.182 ;
     RECT  0.139 35.172 2.16 36.54 ;
     RECT  1.723 37.332 2.16 39.582 ;
     RECT  1.723 40.41 2.16 40.86 ;
     RECT  1.723 41.76 2.16 43.29 ;
     RECT  1.147 44.73 2.16 45.45 ;
     RECT  0.535 46.35 2.16 46.872 ;
     RECT  0.103 47.7 2.16 49.572 ;
     RECT  1.723 50.67 2.16 51.498 ;
     RECT  1.147 52.29 2.16 53.01 ;
     RECT  1.723 53.91 2.16 55.278 ;
     RECT  0.535 56.61 2.16 57.438 ;
     RECT  0.535 58.536 2.16 58.554 ;
     RECT  1.147 59.58 2.16 60.03 ;
     RECT  1.147 60.93 2.16 63.27 ;
     RECT  1.147 64.17 2.16 67.59 ;
     RECT  1.723 68.382 2.16 72.288 ;
     RECT  1.723 73.08 2.16 75.222 ;
     RECT  1.291 76.05 2.16 76.842 ;
     RECT  0.103 77.67 2.16 78.228 ;
     RECT  1.147 79.02 2.16 79.47 ;
     RECT  1.723 80.262 2.16 82.512 ;
     RECT  0.103 83.772 2.16 83.79 ;
     RECT  1.147 84.582 2.16 85.41 ;
     RECT  1.147 86.202 2.16 90.036 ;
     RECT  1.147 90.9 2.16 91.35 ;
     RECT  0.139 92.25 2.16 94.59 ;
     RECT  1.147 95.724 2.16 96.048 ;
     RECT  1.723 96.84 2.16 97.668 ;
     RECT  0.103 98.46 2.16 99.18 ;
     RECT  1.687 99.972 2.16 102.15 ;
     RECT  1.723 105.75 2.16 107.55 ;
     RECT  1.147 109.152 2.16 109.71 ;
     RECT  0.139 111.852 2.16 112.248 ;
     RECT  1.723 113.202 2.16 115.11 ;
     RECT  0.103 116.172 2.16 116.19 ;
     RECT  1.723 118.17 2.16 118.35 ;
     RECT  1.147 119.142 2.16 121.32 ;
     RECT  1.255 123.192 2.16 124.02 ;
     RECT  0.103 125.622 2.16 125.64 ;
     RECT  2.16 2.151 20.844 127.449 ;
     RECT  20.844 77.094 20.867 77.85 ;
     RECT  20.844 78.948 20.903 79.506 ;
     RECT  20.844 80.334 20.939 81.234 ;
     RECT  20.939 80.334 20.975 80.784 ;
     RECT  20.844 82.656 21.011 86.904 ;
     RECT  20.844 30.816 21.119 68.634 ;
     RECT  20.844 2.151 21.227 29.754 ;
     RECT  20.844 93.834 21.263 127.449 ;
     RECT  21.227 2.151 21.299 29.664 ;
     RECT  21.299 28.998 21.335 29.664 ;
     RECT  20.844 88.704 21.335 90.378 ;
     RECT  20.844 76.086 21.371 76.104 ;
     RECT  20.903 78.948 21.407 78.966 ;
     RECT  21.011 83.502 21.443 86.904 ;
     RECT  21.119 31.806 21.479 45.828 ;
     RECT  20.975 80.766 21.479 80.784 ;
     RECT  21.443 83.574 21.515 86.904 ;
     RECT  21.515 85.77 21.587 86.904 ;
     RECT  21.515 83.574 21.623 84.564 ;
     RECT  21.335 28.998 21.659 29.286 ;
     RECT  21.479 31.806 21.659 35.604 ;
     RECT  21.119 46.584 21.659 51.894 ;
     RECT  21.623 84.114 21.659 84.564 ;
     RECT  21.119 52.686 21.695 66.474 ;
     RECT  21.695 52.686 21.731 58.14 ;
     RECT  21.695 59.076 21.731 63.846 ;
     RECT  21.119 67.266 21.731 68.634 ;
     RECT  21.263 93.834 21.839 96.174 ;
     RECT  21.299 2.151 21.911 28.134 ;
     RECT  21.839 93.834 21.911 94.014 ;
     RECT  20.867 77.094 21.947 77.112 ;
     RECT  21.659 84.114 21.983 84.132 ;
     RECT  21.659 32.004 22.019 35.424 ;
     RECT  21.335 88.776 22.019 90.378 ;
     RECT  22.019 89.316 22.091 90.378 ;
     RECT  21.479 36.594 22.127 45.828 ;
     RECT  21.839 95.148 22.127 96.174 ;
     RECT  21.659 28.998 22.163 29.016 ;
     RECT  21.119 30.816 22.163 30.906 ;
     RECT  22.019 32.004 22.163 34.884 ;
     RECT  22.127 36.666 22.163 45.828 ;
     RECT  22.091 89.856 22.163 90.378 ;
     RECT  22.163 30.816 22.279 30.834 ;
     RECT  21.911 2.151 22.896 28.044 ;
     RECT  22.279 30.582 22.896 30.834 ;
     RECT  22.163 32.004 22.896 33.03 ;
     RECT  22.163 34.056 22.896 34.884 ;
     RECT  22.163 36.666 22.896 36.684 ;
     RECT  22.163 37.746 22.896 45.828 ;
     RECT  21.659 46.584 22.896 51.804 ;
     RECT  21.731 52.686 22.896 58.104 ;
     RECT  21.731 59.544 22.896 63.846 ;
     RECT  21.695 64.674 22.896 66.474 ;
     RECT  21.731 67.266 22.896 67.392 ;
     RECT  21.731 68.256 22.896 68.634 ;
     RECT  20.844 74.934 22.896 74.952 ;
     RECT  21.011 82.656 22.896 82.674 ;
     RECT  21.587 86.436 22.896 86.904 ;
     RECT  22.163 90.36 22.896 90.378 ;
     RECT  20.844 91.476 22.896 91.692 ;
     RECT  20.844 92.988 22.896 93.006 ;
     RECT  21.911 93.996 22.896 94.014 ;
     RECT  22.127 95.148 22.896 95.166 ;
     RECT  22.127 96.156 22.896 96.174 ;
     RECT  21.263 96.966 22.896 127.449 ;
     RECT  22.896 2.151 53.771 127.449 ;
     RECT  53.771 2.151 55.355 27.198 ;
     RECT  55.355 2.151 57.775 27.126 ;
     RECT  53.771 28.08 57.775 127.449 ;
     RECT  57.775 2.151 197.64 127.449 ;
     RECT  197.64 30.501 197.843 31.212 ;
     RECT  197.64 34.596 198.059 34.65 ;
     RECT  197.64 36.981 198.383 36.999 ;
     RECT  197.64 39.87 198.455 69.894 ;
     RECT  197.64 70.884 198.455 71.514 ;
     RECT  198.455 65.718 198.491 69.894 ;
     RECT  198.391 96.156 198.499 96.174 ;
     RECT  198.455 70.92 198.527 71.514 ;
     RECT  197.64 94.572 198.607 94.59 ;
     RECT  197.64 79.596 198.679 80.01 ;
     RECT  197.843 30.816 198.715 31.212 ;
     RECT  198.751 82.566 198.823 82.584 ;
     RECT  198.787 84.042 198.823 84.06 ;
     RECT  198.823 82.566 198.895 84.06 ;
     RECT  198.059 34.596 198.967 34.614 ;
     RECT  199.075 95.346 199.147 95.364 ;
     RECT  198.499 96.156 199.147 96.516 ;
     RECT  198.931 35.676 199.183 35.694 ;
     RECT  197.64 38.646 199.255 38.664 ;
     RECT  198.527 71.19 199.255 71.514 ;
     RECT  198.679 79.182 199.327 80.01 ;
     RECT  197.64 80.838 199.327 80.856 ;
     RECT  199.327 79.182 199.363 80.856 ;
     RECT  198.455 39.87 199.399 64.962 ;
     RECT  199.183 92.952 199.435 92.97 ;
     RECT  198.607 93.906 199.435 94.59 ;
     RECT  198.715 30.816 199.507 31.95 ;
     RECT  198.931 37.026 199.507 37.044 ;
     RECT  199.399 39.834 199.507 64.962 ;
     RECT  198.491 65.754 199.507 69.894 ;
     RECT  199.255 38.106 199.543 38.664 ;
     RECT  199.507 39.834 199.543 69.894 ;
     RECT  199.543 38.106 199.579 38.934 ;
     RECT  197.64 2.151 199.692 28.584 ;
     RECT  199.507 30.312 199.692 31.95 ;
     RECT  197.64 32.706 199.692 33.174 ;
     RECT  198.967 34.596 199.692 34.884 ;
     RECT  199.183 35.676 199.692 36.036 ;
     RECT  199.507 36.936 199.692 37.044 ;
     RECT  199.579 37.836 199.692 38.934 ;
     RECT  199.543 39.726 199.692 69.894 ;
     RECT  199.255 71.154 199.692 71.514 ;
     RECT  198.679 73.206 199.692 73.224 ;
     RECT  199.579 74.934 199.692 74.952 ;
     RECT  199.363 79.182 199.692 80.892 ;
     RECT  198.895 82.566 199.692 84.096 ;
     RECT  198.607 85.896 199.692 85.914 ;
     RECT  199.471 91.44 199.692 91.458 ;
     RECT  199.435 92.952 199.692 94.59 ;
     RECT  199.147 95.346 199.692 96.516 ;
     RECT  197.64 97.272 199.692 127.449 ;
     RECT  199.692 2.151 218.16 127.449 ;
     RECT  218.16 8.406 218.327 8.424 ;
     RECT  218.16 12.366 218.327 12.384 ;
     RECT  218.16 57.42 218.327 57.438 ;
     RECT  218.16 85.896 218.327 85.914 ;
     RECT  218.16 7.236 218.867 7.254 ;
     RECT  218.16 10.026 218.867 10.044 ;
     RECT  218.16 15.156 218.867 15.174 ;
     RECT  218.16 31.806 218.867 31.824 ;
     RECT  218.16 36.936 218.867 36.954 ;
     RECT  218.16 78.876 218.867 79.614 ;
     RECT  218.16 82.386 218.867 82.404 ;
     RECT  218.16 83.736 218.867 83.754 ;
     RECT  218.16 4.626 218.903 4.644 ;
     RECT  218.16 5.886 218.903 5.904 ;
     RECT  218.16 16.146 218.903 16.164 ;
     RECT  218.16 45.846 218.903 45.864 ;
     RECT  218.16 49.716 218.903 49.734 ;
     RECT  218.16 56.106 218.903 56.124 ;
     RECT  218.16 60.084 218.903 60.102 ;
     RECT  218.16 61.2 218.903 61.218 ;
     RECT  218.16 62.586 218.903 62.604 ;
     RECT  218.16 95.616 218.903 96.174 ;
     RECT  218.16 106.416 218.903 106.434 ;
     RECT  218.16 11.376 219.443 11.394 ;
     RECT  218.16 13.806 219.443 13.824 ;
     RECT  218.16 17.586 219.443 17.604 ;
     RECT  218.16 18.666 219.443 18.684 ;
     RECT  218.16 20.124 219.443 20.142 ;
     RECT  218.16 21.636 219.443 21.654 ;
     RECT  218.16 22.986 219.443 23.004 ;
     RECT  218.16 24.336 219.443 24.894 ;
     RECT  218.16 26.766 219.443 26.784 ;
     RECT  218.16 27.846 219.443 27.864 ;
     RECT  218.16 33.246 219.443 33.264 ;
     RECT  218.16 34.326 219.443 34.344 ;
     RECT  218.16 38.376 219.443 38.394 ;
     RECT  218.16 39.726 219.443 39.744 ;
     RECT  218.16 41.346 219.443 42.084 ;
     RECT  218.16 43.506 219.443 43.524 ;
     RECT  218.16 44.856 219.443 44.874 ;
     RECT  218.16 47.322 219.443 47.34 ;
     RECT  218.16 51.102 219.443 51.12 ;
     RECT  218.16 52.416 219.443 52.434 ;
     RECT  218.16 55.116 219.443 55.134 ;
     RECT  218.16 65.916 219.443 65.934 ;
     RECT  218.16 68.886 219.443 68.904 ;
     RECT  218.16 72.126 219.443 72.144 ;
     RECT  218.16 73.476 219.443 73.494 ;
     RECT  218.16 74.556 219.443 74.574 ;
     RECT  218.16 77.256 219.443 77.274 ;
     RECT  218.867 78.876 219.443 78.894 ;
     RECT  218.16 81.036 219.443 81.054 ;
     RECT  218.16 84.816 219.443 84.834 ;
     RECT  218.16 87.516 219.443 87.534 ;
     RECT  218.16 90.216 219.443 90.234 ;
     RECT  218.16 91.17 219.443 91.188 ;
     RECT  218.16 92.646 219.443 92.664 ;
     RECT  218.16 97.776 219.443 97.794 ;
     RECT  218.16 99.126 219.443 99.144 ;
     RECT  218.16 100.746 219.443 101.304 ;
     RECT  218.16 102.78 219.443 102.798 ;
     RECT  218.16 104.256 219.443 104.274 ;
     RECT  218.16 108.306 219.443 108.324 ;
     RECT  218.16 109.386 219.443 109.404 ;
     RECT  218.16 112.086 219.443 112.104 ;
     RECT  218.16 115.326 219.443 115.344 ;
     RECT  218.16 121.644 219.443 121.662 ;
     RECT  219.443 24.876 219.479 24.894 ;
     RECT  218.16 28.926 219.479 28.944 ;
     RECT  218.16 30.006 219.479 30.024 ;
     RECT  218.16 35.136 219.479 35.154 ;
     RECT  218.16 48.402 219.479 48.42 ;
     RECT  218.16 53.262 219.479 53.28 ;
     RECT  218.16 58.662 219.479 58.68 ;
     RECT  218.16 63.756 219.479 63.774 ;
     RECT  219.443 101.286 219.479 101.304 ;
     RECT  218.16 75.906 220.235 75.924 ;
     RECT  218.16 89.136 220.235 89.154 ;
     RECT  218.16 94.176 220.235 94.194 ;
     RECT  218.903 95.616 220.235 95.634 ;
     RECT  218.16 105.606 220.235 105.624 ;
     RECT  218.16 110.844 220.235 110.862 ;
     RECT  218.16 118.566 220.235 118.584 ;
    LAYER M3 ;
     RECT  2.415 2.143 2.505 2.413 ;
     RECT  7.815 2.143 7.905 2.413 ;
     RECT  13.215 2.143 13.305 2.413 ;
     RECT  18.615 2.143 18.705 2.413 ;
     RECT  24.015 2.143 24.105 2.413 ;
     RECT  29.415 2.143 29.505 2.413 ;
     RECT  34.815 2.143 34.905 2.413 ;
     RECT  40.215 2.143 40.305 2.413 ;
     RECT  45.615 2.143 45.705 2.413 ;
     RECT  51.015 2.143 51.105 2.413 ;
     RECT  56.415 2.143 56.505 2.413 ;
     RECT  61.815 2.143 61.905 2.413 ;
     RECT  67.215 2.143 67.305 2.413 ;
     RECT  72.615 2.143 72.705 2.413 ;
     RECT  78.015 2.143 78.105 2.413 ;
     RECT  83.415 2.143 83.505 2.413 ;
     RECT  88.815 2.143 88.905 2.413 ;
     RECT  94.215 2.143 94.305 2.413 ;
     RECT  99.615 2.143 99.705 2.413 ;
     RECT  105.015 2.143 105.105 2.413 ;
     RECT  110.415 2.143 110.505 2.413 ;
     RECT  115.815 2.143 115.905 2.413 ;
     RECT  121.215 2.143 121.305 2.413 ;
     RECT  126.615 2.143 126.705 2.413 ;
     RECT  132.015 2.143 132.105 2.413 ;
     RECT  137.415 2.143 137.505 2.413 ;
     RECT  142.815 2.143 142.905 2.413 ;
     RECT  148.215 2.143 148.305 2.413 ;
     RECT  153.615 2.143 153.705 2.413 ;
     RECT  159.015 2.143 159.105 2.413 ;
     RECT  164.415 2.143 164.505 2.413 ;
     RECT  169.815 2.143 169.905 2.413 ;
     RECT  175.215 2.143 175.305 2.413 ;
     RECT  180.615 2.143 180.705 2.413 ;
     RECT  186.015 2.143 186.105 2.413 ;
     RECT  191.415 2.143 191.505 2.413 ;
     RECT  196.815 2.143 196.905 2.413 ;
     RECT  202.215 2.143 202.305 2.413 ;
     RECT  207.615 2.143 207.705 2.413 ;
     RECT  213.015 2.143 213.105 2.413 ;
     RECT  0.108 4.171 0.126 4.415 ;
     RECT  2.415 2.413 2.697 4.531 ;
     RECT  2.415 4.531 2.898 4.657 ;
     RECT  4.104 4.531 4.122 4.657 ;
     RECT  2.415 4.657 4.122 4.685 ;
     RECT  218.88 4.621 218.898 4.685 ;
     RECT  4.32 4.693 4.338 4.733 ;
     RECT  2.415 4.685 3.546 5.117 ;
     RECT  3.456 5.117 3.546 5.189 ;
     RECT  3.456 5.189 3.474 5.225 ;
     RECT  218.88 5.881 218.898 5.933 ;
     RECT  217.548 5.881 217.566 5.999 ;
     RECT  213.015 2.413 213.297 6.151 ;
     RECT  217.044 6.115 217.422 6.151 ;
     RECT  215.172 6.151 215.19 6.235 ;
     RECT  215.028 6.235 215.19 6.269 ;
     RECT  215.964 6.151 215.982 6.269 ;
     RECT  216.864 6.151 217.422 6.269 ;
     RECT  215.028 6.269 215.046 6.275 ;
     RECT  4.644 4.801 4.662 6.385 ;
     RECT  3.924 6.385 4.662 6.421 ;
     RECT  217.224 6.269 217.422 6.539 ;
     RECT  3.852 6.421 4.662 6.691 ;
     RECT  3.78 6.691 4.734 6.781 ;
     RECT  0.108 6.385 0.126 6.845 ;
     RECT  3.78 6.781 4.878 7.231 ;
     RECT  218.844 7.195 218.862 7.259 ;
     RECT  217.26 6.539 217.278 7.349 ;
     RECT  1.152 7.147 1.17 7.357 ;
     RECT  2.415 5.117 2.697 7.357 ;
     RECT  3.78 7.231 5.094 7.387 ;
     RECT  3.78 7.387 5.274 7.393 ;
     RECT  3.42 7.393 5.274 7.465 ;
     RECT  6.12 7.321 6.138 7.465 ;
     RECT  1.152 7.357 2.697 7.517 ;
     RECT  213.015 6.151 213.894 7.579 ;
     RECT  213.015 7.579 214.182 7.619 ;
     RECT  217.728 7.465 217.746 7.619 ;
     RECT  3.42 7.465 6.138 7.663 ;
     RECT  6.912 7.501 6.93 7.663 ;
     RECT  3.42 7.663 6.93 7.699 ;
     RECT  3.42 7.699 7.038 7.889 ;
     RECT  3.42 7.889 7.002 7.961 ;
     RECT  3.42 7.961 6.93 8.159 ;
     RECT  2.415 7.517 2.697 8.311 ;
     RECT  3.42 8.159 4.914 8.311 ;
     RECT  6.84 8.159 6.93 8.429 ;
     RECT  1.152 7.517 1.242 8.443 ;
     RECT  5.688 8.159 5.994 8.465 ;
     RECT  6.84 8.429 6.858 8.525 ;
     RECT  218.304 8.401 218.322 8.525 ;
     RECT  5.688 8.465 5.706 8.699 ;
     RECT  217.512 8.581 217.53 8.699 ;
     RECT  215.964 8.851 216.09 8.969 ;
     RECT  217.836 8.815 217.854 8.969 ;
     RECT  214.74 8.977 214.758 9.053 ;
     RECT  213.015 7.619 213.894 9.085 ;
     RECT  2.415 8.311 4.914 9.115 ;
     RECT  2.415 9.115 5.274 9.239 ;
     RECT  2.415 9.239 4.734 9.437 ;
     RECT  2.415 9.437 3.834 9.509 ;
     RECT  1.152 8.443 1.278 9.545 ;
     RECT  2.415 9.509 3.15 9.545 ;
     RECT  2.415 9.545 2.79 9.779 ;
     RECT  217.224 9.661 217.386 9.779 ;
     RECT  212.292 9.085 213.894 9.787 ;
     RECT  1.152 9.545 1.17 9.815 ;
     RECT  217.368 9.779 217.386 9.815 ;
     RECT  217.512 9.931 217.53 10.049 ;
     RECT  218.844 9.787 218.862 10.049 ;
     RECT  216.36 9.931 216.378 10.085 ;
     RECT  212.112 9.787 213.894 10.201 ;
     RECT  4.644 9.437 4.662 10.267 ;
     RECT  0.108 11.128 0.126 11.165 ;
     RECT  215.748 11.128 215.766 11.165 ;
     RECT  2.415 9.779 2.697 11.245 ;
     RECT  211.68 10.201 213.894 11.281 ;
     RECT  217.296 11.011 217.566 11.281 ;
     RECT  3.528 11.281 3.546 11.371 ;
     RECT  4.644 10.267 5.166 11.371 ;
     RECT  6.84 10.741 6.858 11.371 ;
     RECT  217.224 11.281 217.674 11.399 ;
     RECT  219.42 11.083 219.438 11.399 ;
     RECT  6.84 11.371 6.966 11.419 ;
     RECT  7.815 2.413 8.097 11.419 ;
     RECT  217.224 11.399 217.242 11.435 ;
     RECT  6.84 11.419 8.097 11.453 ;
     RECT  3.456 11.371 5.526 11.551 ;
     RECT  1.728 11.245 2.697 11.755 ;
     RECT  1.152 11.755 2.697 11.821 ;
     RECT  3.456 11.551 5.67 11.821 ;
     RECT  1.152 11.821 5.67 11.939 ;
     RECT  6.948 11.453 8.097 11.947 ;
     RECT  5.688 11.947 5.706 12.209 ;
     RECT  210.816 12.091 210.834 12.217 ;
     RECT  211.68 11.281 214.362 12.217 ;
     RECT  210.816 12.217 214.362 12.289 ;
     RECT  1.152 11.939 4.662 12.317 ;
     RECT  209.34 12.235 209.358 12.361 ;
     RECT  217.656 12.361 218.322 12.413 ;
     RECT  1.152 12.317 3.546 12.461 ;
     RECT  209.34 12.361 209.502 12.479 ;
     RECT  210.816 12.289 214.866 12.479 ;
     RECT  217.656 12.413 217.782 12.479 ;
     RECT  210.816 12.479 214.362 12.509 ;
     RECT  209.34 12.479 209.358 12.515 ;
     RECT  210.816 12.509 213.894 12.559 ;
     RECT  210.708 12.559 213.894 12.595 ;
     RECT  216.684 12.523 216.702 12.749 ;
     RECT  217.764 12.479 217.782 12.749 ;
     RECT  6.948 11.947 8.298 12.991 ;
     RECT  210.636 12.595 213.894 13.019 ;
     RECT  2.415 12.461 3.546 13.055 ;
     RECT  210.636 13.019 213.642 13.133 ;
     RECT  4.32 12.317 4.662 13.171 ;
     RECT  5.58 12.901 5.598 13.171 ;
     RECT  206.352 13.333 206.37 13.387 ;
     RECT  210.636 13.133 213.534 13.387 ;
     RECT  210.348 13.387 213.534 13.433 ;
     RECT  2.415 13.055 2.697 13.435 ;
     RECT  206.352 13.387 206.406 13.469 ;
     RECT  210.456 13.433 213.534 13.469 ;
     RECT  110.415 2.413 110.697 13.525 ;
     RECT  6.948 12.991 8.37 13.531 ;
     RECT  67.215 2.413 67.497 13.531 ;
     RECT  78.015 2.413 78.297 13.531 ;
     RECT  88.815 2.413 89.097 13.531 ;
     RECT  90.612 13.291 90.63 13.531 ;
     RECT  99.615 2.413 99.897 13.531 ;
     RECT  121.215 2.413 121.497 13.531 ;
     RECT  132.015 2.413 132.297 13.531 ;
     RECT  142.815 2.413 143.097 13.531 ;
     RECT  153.615 2.413 153.897 13.531 ;
     RECT  164.415 2.413 164.697 13.531 ;
     RECT  175.215 2.413 175.497 13.531 ;
     RECT  186.015 2.413 186.297 13.531 ;
     RECT  196.815 2.413 197.097 13.531 ;
     RECT  110.304 13.525 110.697 13.565 ;
     RECT  206.388 13.469 206.406 13.565 ;
     RECT  4.32 13.171 5.598 13.567 ;
     RECT  6.84 13.531 8.37 13.567 ;
     RECT  67.104 13.531 67.497 13.568 ;
     RECT  77.904 13.531 78.297 13.568 ;
     RECT  88.704 13.531 89.097 13.568 ;
     RECT  90.036 13.531 90.63 13.568 ;
     RECT  99.504 13.531 99.897 13.568 ;
     RECT  121.104 13.531 121.497 13.568 ;
     RECT  131.904 13.531 132.297 13.568 ;
     RECT  142.704 13.531 143.097 13.568 ;
     RECT  153.504 13.531 153.897 13.568 ;
     RECT  164.304 13.531 164.697 13.568 ;
     RECT  175.104 13.531 175.497 13.568 ;
     RECT  185.904 13.531 186.297 13.568 ;
     RECT  196.704 13.531 197.097 13.568 ;
     RECT  211.86 13.469 213.534 13.631 ;
     RECT  3.456 13.055 3.546 13.639 ;
     RECT  4.32 13.567 8.37 13.639 ;
     RECT  3.456 13.639 8.37 13.757 ;
     RECT  88.815 13.568 89.097 13.819 ;
     RECT  90.612 13.568 90.63 13.829 ;
     RECT  219.42 13.675 219.438 13.829 ;
     RECT  2.304 13.435 2.697 13.865 ;
     RECT  88.815 13.819 89.514 13.865 ;
     RECT  210.456 13.469 210.942 13.865 ;
     RECT  216.756 13.801 216.774 13.901 ;
     RECT  210.924 13.865 210.942 13.973 ;
     RECT  2.415 13.865 2.697 13.981 ;
     RECT  3.456 13.757 3.582 13.981 ;
     RECT  215.64 13.981 215.658 14.099 ;
     RECT  217.188 13.981 217.566 14.099 ;
     RECT  1.152 12.461 1.17 14.107 ;
     RECT  214.524 14.203 214.542 14.243 ;
     RECT  0.108 12.091 0.126 14.441 ;
     RECT  22.824 14.347 22.842 14.477 ;
     RECT  2.415 13.981 3.582 14.485 ;
     RECT  4.32 13.757 8.37 14.485 ;
     RECT  211.5 14.449 211.518 14.485 ;
     RECT  212.292 13.631 213.534 14.485 ;
     RECT  211.5 14.485 213.534 14.513 ;
     RECT  25.452 14.443 25.47 14.521 ;
     RECT  25.236 14.521 25.47 14.549 ;
     RECT  213.015 14.513 213.534 14.549 ;
     RECT  1.152 14.107 1.242 14.594 ;
     RECT  90.648 14.611 90.666 14.669 ;
     RECT  2.415 14.485 8.37 14.675 ;
     RECT  91.764 14.635 91.782 14.675 ;
     RECT  2.415 14.675 3.546 14.731 ;
     RECT  217.296 14.099 217.566 14.755 ;
     RECT  211.5 14.513 212.094 14.875 ;
     RECT  217.296 14.755 217.674 14.909 ;
     RECT  2.304 14.731 3.546 14.945 ;
     RECT  211.392 14.875 212.094 15.016 ;
     RECT  210.924 15.016 212.094 15.053 ;
     RECT  217.296 14.909 217.386 15.061 ;
     RECT  67.215 13.568 67.497 15.151 ;
     RECT  78.015 13.568 78.297 15.151 ;
     RECT  99.615 13.568 99.897 15.151 ;
     RECT  110.415 13.565 110.697 15.151 ;
     RECT  121.215 13.568 121.497 15.151 ;
     RECT  132.015 13.568 132.297 15.151 ;
     RECT  142.815 13.568 143.097 15.151 ;
     RECT  153.615 13.568 153.897 15.151 ;
     RECT  164.415 13.568 164.697 15.151 ;
     RECT  175.215 13.568 175.497 15.151 ;
     RECT  186.015 13.568 186.297 15.151 ;
     RECT  196.815 13.568 197.097 15.151 ;
     RECT  2.415 14.945 3.546 15.179 ;
     RECT  217.116 15.061 217.386 15.179 ;
     RECT  218.844 14.923 218.862 15.179 ;
     RECT  67.104 15.151 67.497 15.197 ;
     RECT  77.904 15.151 78.297 15.197 ;
     RECT  90.612 15.151 90.63 15.197 ;
     RECT  99.504 15.151 99.897 15.197 ;
     RECT  110.304 15.151 110.697 15.197 ;
     RECT  121.104 15.151 121.497 15.197 ;
     RECT  131.904 15.151 132.297 15.197 ;
     RECT  142.704 15.151 143.097 15.197 ;
     RECT  153.504 15.151 153.897 15.197 ;
     RECT  164.304 15.151 164.697 15.197 ;
     RECT  175.104 15.151 175.497 15.197 ;
     RECT  185.904 15.151 186.297 15.197 ;
     RECT  196.704 15.151 197.097 15.197 ;
     RECT  206.352 15.019 206.37 15.197 ;
     RECT  1.152 14.594 1.17 15.215 ;
     RECT  3.528 15.179 3.546 15.215 ;
     RECT  88.815 13.865 89.097 15.259 ;
     RECT  217.116 15.179 217.134 15.287 ;
     RECT  86.652 15.163 86.67 15.293 ;
     RECT  88.815 15.259 89.514 15.296 ;
     RECT  211.392 15.053 212.094 15.331 ;
     RECT  211.392 15.331 212.13 15.389 ;
     RECT  4.32 14.675 8.37 15.457 ;
     RECT  4.32 15.457 8.55 15.565 ;
     RECT  4.32 15.565 8.73 15.593 ;
     RECT  10.512 15.529 10.53 15.727 ;
     RECT  4.392 15.593 8.73 15.799 ;
     RECT  9.648 15.601 9.666 15.799 ;
     RECT  10.476 15.727 10.53 15.799 ;
     RECT  211.536 15.389 212.13 15.871 ;
     RECT  213.015 14.549 213.297 15.871 ;
     RECT  211.536 15.871 213.297 15.989 ;
     RECT  9.648 15.799 10.53 16.069 ;
     RECT  4.392 15.799 8.91 16.105 ;
     RECT  9.648 16.069 11.07 16.105 ;
     RECT  4.392 16.105 11.574 16.133 ;
     RECT  218.88 16.141 218.898 16.253 ;
     RECT  217.548 16.141 217.566 16.259 ;
     RECT  88.815 15.296 89.097 16.267 ;
     RECT  211.536 15.989 212.022 16.267 ;
     RECT  90.612 16.231 90.63 16.301 ;
     RECT  88.815 16.267 89.514 16.304 ;
     RECT  211.32 16.267 212.022 16.439 ;
     RECT  211.32 16.439 211.554 16.529 ;
     RECT  215.136 16.501 215.154 16.541 ;
     RECT  4.536 16.133 11.574 16.589 ;
     RECT  217.404 16.375 217.494 16.601 ;
     RECT  217.404 16.601 217.422 16.681 ;
     RECT  213.015 15.989 213.297 16.771 ;
     RECT  91.692 16.555 91.71 16.795 ;
     RECT  4.536 16.589 9.306 16.799 ;
     RECT  59.4 16.267 59.418 16.799 ;
     RECT  91.332 16.795 91.71 16.799 ;
     RECT  215.28 16.681 215.298 16.799 ;
     RECT  217.224 16.681 217.422 16.799 ;
     RECT  4.536 16.799 5.994 16.835 ;
     RECT  91.332 16.799 91.35 16.835 ;
     RECT  2.415 15.179 2.697 16.915 ;
     RECT  10.188 16.589 11.574 16.943 ;
     RECT  212.832 16.771 213.297 16.951 ;
     RECT  10.26 16.943 11.574 16.979 ;
     RECT  212.436 16.951 213.297 17.021 ;
     RECT  6.732 16.799 9.306 17.069 ;
     RECT  2.268 16.915 2.697 17.077 ;
     RECT  3.528 16.951 3.546 17.077 ;
     RECT  1.728 17.077 3.546 17.117 ;
     RECT  10.476 16.979 11.574 17.117 ;
     RECT  211.536 16.529 211.554 17.117 ;
     RECT  212.616 17.021 213.297 17.117 ;
     RECT  6.732 17.069 8.19 17.213 ;
     RECT  2.268 17.117 3.546 17.453 ;
     RECT  2.304 17.453 3.546 17.491 ;
     RECT  4.536 16.835 5.922 17.491 ;
     RECT  18.615 2.413 18.897 17.581 ;
     RECT  219.42 17.515 219.438 17.609 ;
     RECT  18.615 17.581 19.134 17.611 ;
     RECT  20.556 17.611 20.574 17.725 ;
     RECT  20.556 17.725 20.61 17.761 ;
     RECT  21.42 17.611 21.438 17.761 ;
     RECT  18.615 17.611 19.278 17.851 ;
     RECT  20.448 17.761 21.51 17.851 ;
     RECT  217.728 17.725 217.746 17.879 ;
     RECT  20.376 17.851 21.51 17.887 ;
     RECT  18.615 17.851 19.35 17.923 ;
     RECT  18.615 17.923 19.638 17.947 ;
     RECT  212.688 17.117 213.297 17.947 ;
     RECT  216.936 17.851 216.954 17.951 ;
     RECT  214.488 17.803 214.506 17.981 ;
     RECT  18.612 17.947 19.638 17.995 ;
     RECT  20.376 17.887 22.23 17.995 ;
     RECT  212.472 17.947 213.297 18.023 ;
     RECT  17.424 17.689 17.442 18.031 ;
     RECT  18.612 17.995 22.23 18.031 ;
     RECT  2.304 17.491 5.922 18.121 ;
     RECT  6.732 17.213 8.097 18.121 ;
     RECT  8.964 17.069 9.306 18.121 ;
     RECT  10.476 17.117 10.494 18.121 ;
     RECT  16.632 18.031 17.442 18.121 ;
     RECT  18.252 18.031 22.23 18.121 ;
     RECT  23.004 17.959 23.022 18.121 ;
     RECT  16.488 18.121 17.442 18.139 ;
     RECT  18.252 18.121 23.022 18.139 ;
     RECT  40.215 2.413 40.497 18.139 ;
     RECT  11.232 17.117 11.574 18.157 ;
     RECT  12.312 17.041 12.33 18.157 ;
     RECT  16.488 18.139 23.022 18.157 ;
     RECT  10.44 18.121 10.494 18.193 ;
     RECT  11.232 18.157 12.33 18.193 ;
     RECT  214.632 18.031 214.65 18.221 ;
     RECT  2.304 18.121 9.306 18.257 ;
     RECT  10.44 18.193 12.33 18.265 ;
     RECT  10.332 18.265 12.33 18.301 ;
     RECT  13.215 2.413 13.497 18.301 ;
     RECT  15.948 18.157 23.022 18.391 ;
     RECT  25.236 14.549 25.254 18.391 ;
     RECT  2.34 18.257 9.306 18.419 ;
     RECT  10.332 18.301 13.497 18.427 ;
     RECT  2.34 18.419 2.862 18.455 ;
     RECT  10.26 18.427 13.497 18.499 ;
     RECT  41.616 18.301 41.634 18.499 ;
     RECT  10.224 18.499 13.497 18.535 ;
     RECT  27.432 18.121 27.45 18.535 ;
     RECT  28.26 18.463 28.278 18.535 ;
     RECT  29.415 2.413 29.697 18.535 ;
     RECT  39.708 18.139 40.497 18.535 ;
     RECT  41.328 18.499 41.634 18.535 ;
     RECT  15.948 18.391 23.13 18.563 ;
     RECT  39.708 18.535 41.634 18.571 ;
     RECT  3.6 18.419 9.306 18.689 ;
     RECT  25.236 18.391 25.686 18.697 ;
     RECT  10.224 18.535 14.094 18.733 ;
     RECT  3.96 18.689 9.306 18.769 ;
     RECT  10.08 18.733 14.094 18.769 ;
     RECT  25.236 18.697 26.19 18.769 ;
     RECT  24.015 2.413 24.297 18.805 ;
     RECT  25.236 18.769 26.262 18.805 ;
     RECT  34.815 2.413 35.097 18.805 ;
     RECT  39.708 18.571 41.67 18.805 ;
     RECT  14.976 18.769 14.994 18.841 ;
     RECT  24.015 18.805 26.262 18.841 ;
     RECT  27.432 18.535 29.697 18.841 ;
     RECT  39.6 18.805 41.67 18.841 ;
     RECT  48.96 18.697 48.978 18.841 ;
     RECT  219.42 18.661 219.438 18.845 ;
     RECT  16.884 18.563 23.13 18.931 ;
     RECT  24.015 18.841 26.406 18.931 ;
     RECT  34.815 18.805 35.298 18.931 ;
     RECT  39.6 18.841 41.886 18.931 ;
     RECT  42.732 18.769 42.75 18.931 ;
     RECT  217.332 18.841 217.35 18.931 ;
     RECT  2.415 18.455 2.862 18.959 ;
     RECT  3.96 18.769 14.094 18.967 ;
     RECT  14.94 18.841 14.994 18.967 ;
     RECT  15.768 18.565 15.786 18.967 ;
     RECT  27.432 18.841 30.186 18.967 ;
     RECT  33.264 18.805 33.282 18.967 ;
     RECT  38.772 18.805 38.79 18.997 ;
     RECT  33.264 18.967 33.57 19.039 ;
     RECT  34.308 18.931 35.406 19.039 ;
     RECT  27.432 18.967 30.294 19.075 ;
     RECT  38.628 18.997 38.79 19.075 ;
     RECT  39.6 18.931 42.75 19.075 ;
     RECT  45.615 2.413 45.897 19.099 ;
     RECT  38.628 19.075 42.75 19.103 ;
     RECT  16.884 18.931 26.406 19.111 ;
     RECT  27.432 19.075 30.978 19.111 ;
     RECT  33.264 19.039 35.406 19.111 ;
     RECT  217.332 18.931 217.386 19.111 ;
     RECT  214.668 19.075 214.686 19.133 ;
     RECT  217.332 19.111 217.602 19.229 ;
     RECT  33.264 19.111 35.622 19.237 ;
     RECT  37.8 18.931 37.818 19.237 ;
     RECT  32.328 19.051 32.346 19.265 ;
     RECT  47.988 19.237 48.006 19.273 ;
     RECT  43.2 19.111 43.218 19.301 ;
     RECT  16.884 19.111 30.978 19.309 ;
     RECT  46.728 19.273 46.746 19.309 ;
     RECT  16.848 19.309 30.978 19.337 ;
     RECT  45.576 19.099 45.897 19.339 ;
     RECT  33.084 19.237 35.622 19.381 ;
     RECT  36.864 19.003 36.882 19.381 ;
     RECT  37.656 19.237 37.818 19.381 ;
     RECT  38.628 19.103 42.426 19.381 ;
     RECT  47.988 19.273 48.114 19.381 ;
     RECT  48.96 18.841 49.086 19.381 ;
     RECT  16.848 19.337 26.694 19.471 ;
     RECT  36.864 19.381 42.426 19.507 ;
     RECT  44.064 19.471 44.082 19.507 ;
     RECT  32.688 19.381 35.622 19.543 ;
     RECT  36.792 19.507 42.426 19.543 ;
     RECT  16.704 19.471 26.694 19.579 ;
     RECT  43.416 19.507 44.082 19.579 ;
     RECT  3.96 18.967 15.786 19.615 ;
     RECT  3.852 19.615 15.786 19.651 ;
     RECT  16.632 19.579 26.694 19.651 ;
     RECT  46.728 19.309 47.178 19.651 ;
     RECT  32.688 19.543 35.73 19.679 ;
     RECT  2.415 18.959 2.697 19.723 ;
     RECT  43.416 19.579 44.406 19.741 ;
     RECT  45.576 19.339 45.99 19.741 ;
     RECT  43.416 19.741 45.99 19.813 ;
     RECT  46.728 19.651 47.25 19.813 ;
     RECT  47.988 19.381 49.086 19.813 ;
     RECT  27.468 19.337 30.978 19.849 ;
     RECT  36.612 19.543 42.426 19.849 ;
     RECT  51.015 2.413 51.297 20.011 ;
     RECT  36.54 19.849 42.426 20.047 ;
     RECT  2.304 19.723 2.697 20.075 ;
     RECT  27.468 19.849 31.302 20.083 ;
     RECT  36.36 20.047 42.426 20.083 ;
     RECT  43.416 19.813 47.25 20.083 ;
     RECT  27.468 20.083 31.77 20.111 ;
     RECT  219.42 20.107 219.438 20.147 ;
     RECT  36.36 20.083 47.25 20.155 ;
     RECT  47.988 19.813 49.626 20.155 ;
     RECT  0.108 18.235 0.126 20.183 ;
     RECT  36.36 20.155 49.626 20.183 ;
     RECT  3.744 19.651 26.694 20.191 ;
     RECT  3.564 20.191 26.694 20.309 ;
     RECT  32.688 19.679 35.442 20.309 ;
     RECT  123.624 13.873 123.642 20.309 ;
     RECT  4.032 20.309 26.694 20.317 ;
     RECT  27.468 20.111 30.978 20.317 ;
     RECT  50.976 20.011 51.297 20.317 ;
     RECT  33.012 20.309 35.442 20.345 ;
     RECT  56.415 2.413 56.697 20.353 ;
     RECT  36.468 20.183 49.626 20.389 ;
     RECT  2.34 20.075 2.697 20.425 ;
     RECT  217.548 20.191 217.566 20.425 ;
     RECT  36.468 20.389 49.77 20.429 ;
     RECT  31.752 20.111 31.77 20.453 ;
     RECT  212.688 18.023 213.297 20.461 ;
     RECT  217.548 20.425 217.854 20.461 ;
     RECT  122.364 13.333 122.382 20.579 ;
     RECT  217.296 20.461 217.854 20.579 ;
     RECT  4.032 20.317 30.978 20.615 ;
     RECT  210.24 20.779 210.258 20.849 ;
     RECT  2.34 20.425 3.222 21.019 ;
     RECT  211.068 21.001 211.086 21.091 ;
     RECT  31.932 21.067 32.022 21.115 ;
     RECT  33.012 20.345 35.406 21.115 ;
     RECT  212.688 20.461 213.354 21.119 ;
     RECT  56.34 20.353 56.697 21.127 ;
     RECT  36.468 20.429 49.626 21.155 ;
     RECT  31.932 21.115 35.406 21.163 ;
     RECT  37.836 21.155 49.626 21.163 ;
     RECT  50.508 20.317 51.297 21.163 ;
     RECT  31.932 21.163 35.658 21.199 ;
     RECT  2.304 21.019 3.222 21.235 ;
     RECT  4.032 20.615 22.05 21.235 ;
     RECT  22.788 20.615 30.978 21.235 ;
     RECT  31.788 21.199 35.658 21.235 ;
     RECT  36.468 21.155 37.026 21.271 ;
     RECT  54.576 21.235 54.594 21.271 ;
     RECT  56.34 21.127 57.042 21.271 ;
     RECT  211.068 21.091 211.446 21.271 ;
     RECT  217.296 20.579 217.422 21.271 ;
     RECT  123.372 20.425 123.39 21.299 ;
     RECT  2.304 21.235 22.05 21.397 ;
     RECT  22.788 21.235 35.658 21.397 ;
     RECT  36.396 21.271 37.026 21.397 ;
     RECT  212.688 21.119 213.297 21.397 ;
     RECT  59.148 16.915 59.166 21.403 ;
     RECT  211.068 21.271 211.878 21.403 ;
     RECT  212.652 21.397 213.297 21.403 ;
     RECT  2.304 21.397 37.026 21.425 ;
     RECT  90.648 21.361 90.666 21.437 ;
     RECT  91.764 21.397 91.782 21.437 ;
     RECT  59.148 21.403 59.706 21.451 ;
     RECT  211.068 21.403 213.297 21.461 ;
     RECT  55.584 20.587 55.602 21.496 ;
     RECT  56.34 21.271 57.33 21.496 ;
     RECT  55.584 21.496 57.33 21.499 ;
     RECT  58.464 21.451 59.706 21.499 ;
     RECT  54.144 21.271 54.738 21.505 ;
     RECT  55.584 21.499 59.706 21.505 ;
     RECT  217.224 21.271 217.422 21.505 ;
     RECT  52.668 21.397 52.686 21.541 ;
     RECT  214.848 21.505 214.866 21.541 ;
     RECT  217.008 21.505 217.422 21.541 ;
     RECT  214.344 21.541 214.866 21.581 ;
     RECT  216.216 21.541 216.234 21.659 ;
     RECT  217.008 21.541 217.53 21.659 ;
     RECT  219.42 21.403 219.438 21.659 ;
     RECT  210.24 21.691 210.258 21.731 ;
     RECT  37.836 21.163 51.297 21.775 ;
     RECT  52.668 21.541 53.19 21.811 ;
     RECT  54.144 21.505 59.706 21.811 ;
     RECT  61.815 2.413 62.097 21.811 ;
     RECT  214.344 21.581 214.362 21.839 ;
     RECT  210.312 21.739 210.33 21.929 ;
     RECT  211.068 21.461 211.734 22.027 ;
     RECT  210.96 22.027 211.734 22.073 ;
     RECT  52.668 21.811 59.706 22.081 ;
     RECT  212.472 21.461 213.297 22.081 ;
     RECT  2.415 21.425 37.026 22.171 ;
     RECT  37.836 21.775 51.57 22.199 ;
     RECT  52.344 22.081 59.706 22.199 ;
     RECT  211.248 22.073 211.734 22.199 ;
     RECT  212.472 22.081 213.642 22.199 ;
     RECT  61.776 21.811 62.097 22.219 ;
     RECT  2.415 22.171 37.062 22.243 ;
     RECT  37.836 22.199 48.15 22.243 ;
     RECT  2.415 22.243 48.15 22.271 ;
     RECT  61.596 22.219 62.097 22.351 ;
     RECT  62.82 22.219 62.838 22.351 ;
     RECT  121.215 15.197 121.497 22.459 ;
     RECT  211.248 22.199 211.374 22.505 ;
     RECT  48.96 22.199 51.57 22.549 ;
     RECT  52.344 22.199 59.202 22.549 ;
     RECT  45.576 22.271 48.15 22.577 ;
     RECT  0.108 21.211 0.126 22.585 ;
     RECT  1.152 20.731 1.17 22.585 ;
     RECT  61.596 22.351 62.838 22.621 ;
     RECT  83.415 2.413 83.697 22.621 ;
     RECT  217.188 22.585 217.206 22.621 ;
     RECT  207.615 2.413 207.897 22.711 ;
     RECT  0.108 22.585 1.17 22.733 ;
     RECT  61.524 22.621 62.838 22.739 ;
     RECT  2.415 22.271 44.766 22.775 ;
     RECT  121.104 22.459 121.497 22.775 ;
     RECT  61.524 22.739 62.73 22.795 ;
     RECT  60.444 22.585 60.462 22.819 ;
     RECT  61.236 22.795 62.73 22.819 ;
     RECT  94.215 2.413 94.497 22.855 ;
     RECT  212.472 22.199 213.297 22.891 ;
     RECT  217.188 22.621 217.422 22.891 ;
     RECT  108.072 22.891 108.09 22.981 ;
     RECT  211.284 22.505 211.374 22.981 ;
     RECT  212.328 22.891 213.297 22.981 ;
     RECT  71.352 22.441 71.37 23.009 ;
     RECT  217.188 22.891 217.53 23.009 ;
     RECT  219.42 22.699 219.438 23.009 ;
     RECT  48.96 22.549 59.202 23.017 ;
     RECT  77.04 22.819 77.058 23.045 ;
     RECT  214.524 22.795 214.542 23.045 ;
     RECT  47.412 22.577 48.15 23.053 ;
     RECT  48.96 23.017 59.526 23.053 ;
     RECT  108.072 22.981 108.342 23.08 ;
     RECT  108.072 23.08 108.378 23.081 ;
     RECT  211.284 22.981 213.354 23.081 ;
     RECT  137.415 2.413 137.697 23.089 ;
     RECT  217.512 23.009 217.53 23.117 ;
     RECT  26.676 22.775 44.766 23.125 ;
     RECT  45.576 22.577 46.638 23.125 ;
     RECT  108.36 23.081 108.378 23.189 ;
     RECT  47.412 23.053 59.526 23.251 ;
     RECT  0.108 22.733 0.126 23.315 ;
     RECT  60.444 22.819 62.73 23.315 ;
     RECT  26.676 23.125 46.638 23.351 ;
     RECT  26.676 23.351 31.662 23.357 ;
     RECT  212.616 23.081 213.354 23.357 ;
     RECT  69.516 23.125 69.534 23.371 ;
     RECT  47.412 23.251 59.706 23.423 ;
     RECT  212.688 23.357 213.354 23.431 ;
     RECT  64.872 23.323 64.89 23.521 ;
     RECT  69.516 23.371 70.29 23.549 ;
     RECT  32.616 23.351 46.638 23.557 ;
     RECT  2.415 22.775 25.902 23.659 ;
     RECT  26.676 23.357 27.522 23.659 ;
     RECT  167.004 23.083 167.022 23.693 ;
     RECT  47.628 23.423 59.706 23.791 ;
     RECT  60.444 23.315 62.694 23.791 ;
     RECT  67.215 15.197 67.497 23.791 ;
     RECT  1.152 22.733 1.17 23.827 ;
     RECT  2.304 23.659 27.522 23.827 ;
     RECT  47.628 23.791 62.694 23.837 ;
     RECT  202.215 2.413 202.497 23.863 ;
     RECT  66.672 23.791 67.497 23.899 ;
     RECT  137.415 23.089 137.97 23.899 ;
     RECT  66.672 23.899 67.842 23.927 ;
     RECT  47.628 23.837 62.19 23.936 ;
     RECT  64.872 23.521 65.358 23.947 ;
     RECT  211.284 23.081 211.878 23.947 ;
     RECT  69.516 23.549 70.11 23.963 ;
     RECT  216.972 23.935 216.99 23.971 ;
     RECT  64.872 23.947 65.466 23.995 ;
     RECT  1.152 23.827 27.522 24.029 ;
     RECT  63.864 23.161 63.882 24.061 ;
     RECT  64.872 23.995 65.538 24.061 ;
     RECT  137.124 23.899 137.97 24.061 ;
     RECT  69.516 23.963 69.858 24.089 ;
     RECT  83.415 22.621 83.898 24.089 ;
     RECT  216.972 23.971 217.386 24.089 ;
     RECT  217.368 24.089 217.386 24.125 ;
     RECT  137.124 24.061 138.438 24.133 ;
     RECT  32.616 23.557 46.89 24.169 ;
     RECT  47.628 23.936 62.097 24.169 ;
     RECT  63.864 24.061 65.934 24.169 ;
     RECT  28.368 23.357 31.662 24.205 ;
     RECT  32.616 24.169 62.097 24.205 ;
     RECT  210.888 23.947 211.878 24.205 ;
     RECT  28.368 24.205 62.097 24.233 ;
     RECT  202.215 23.863 202.95 24.233 ;
     RECT  168.516 23.593 168.534 24.241 ;
     RECT  212.688 23.431 213.426 24.241 ;
     RECT  67.215 23.927 67.842 24.269 ;
     RECT  84.996 24.097 85.014 24.269 ;
     RECT  110.415 15.197 110.697 24.325 ;
     RECT  68.724 24.097 68.742 24.331 ;
     RECT  78.015 15.197 78.297 24.331 ;
     RECT  88.815 16.304 89.097 24.331 ;
     RECT  99.615 15.197 99.897 24.331 ;
     RECT  103.536 23.971 103.554 24.331 ;
     RECT  121.215 22.775 121.497 24.331 ;
     RECT  132.015 15.197 132.297 24.331 ;
     RECT  142.815 15.197 143.097 24.331 ;
     RECT  153.615 15.197 153.897 24.331 ;
     RECT  164.415 15.197 164.697 24.331 ;
     RECT  175.215 15.197 175.497 24.331 ;
     RECT  186.015 15.197 186.297 24.331 ;
     RECT  196.815 15.197 197.097 24.331 ;
     RECT  210.348 24.205 211.878 24.331 ;
     RECT  212.688 24.241 213.57 24.331 ;
     RECT  28.368 24.233 60.966 24.359 ;
     RECT  68.652 24.331 68.742 24.359 ;
     RECT  210.348 24.331 213.57 24.359 ;
     RECT  217.512 24.241 217.53 24.359 ;
     RECT  219.42 23.947 219.438 24.359 ;
     RECT  110.304 24.325 110.697 24.365 ;
     RECT  2.304 24.029 27.522 24.367 ;
     RECT  103.536 24.331 103.698 24.367 ;
     RECT  137.124 24.133 139.122 24.367 ;
     RECT  69.84 24.089 69.858 24.368 ;
     RECT  77.904 24.331 78.297 24.368 ;
     RECT  88.704 24.331 89.097 24.368 ;
     RECT  99.504 24.331 99.897 24.368 ;
     RECT  121.104 24.331 121.497 24.368 ;
     RECT  131.904 24.331 132.297 24.368 ;
     RECT  142.704 24.331 143.097 24.368 ;
     RECT  153.504 24.331 153.897 24.368 ;
     RECT  164.304 24.331 164.697 24.368 ;
     RECT  185.904 24.331 186.297 24.368 ;
     RECT  196.704 24.331 197.097 24.368 ;
     RECT  139.86 24.169 139.878 24.379 ;
     RECT  2.304 24.367 27.594 24.395 ;
     RECT  103.536 24.367 103.77 24.395 ;
     RECT  28.368 24.359 60.894 24.431 ;
     RECT  63 24.169 65.934 24.439 ;
     RECT  139.86 24.379 140.202 24.439 ;
     RECT  28.368 24.431 33.786 24.467 ;
     RECT  68.652 24.359 68.67 24.467 ;
     RECT  98.604 24.367 98.622 24.467 ;
     RECT  103.68 24.395 103.77 24.467 ;
     RECT  136.8 24.367 139.122 24.475 ;
     RECT  139.86 24.439 140.238 24.475 ;
     RECT  63 24.439 66.186 24.503 ;
     RECT  2.415 24.395 27.594 24.511 ;
     RECT  28.368 24.467 33.75 24.511 ;
     RECT  136.8 24.475 140.274 24.511 ;
     RECT  70.668 24.367 70.686 24.601 ;
     RECT  93.816 22.855 94.497 24.601 ;
     RECT  168.516 24.241 169.038 24.601 ;
     RECT  63.288 24.503 66.186 24.629 ;
     RECT  93.816 24.601 94.95 24.629 ;
     RECT  136.8 24.511 140.346 24.629 ;
     RECT  1.152 24.029 1.17 24.665 ;
     RECT  168.336 24.601 169.038 24.673 ;
     RECT  169.815 2.413 170.097 24.673 ;
     RECT  34.704 24.431 60.174 24.701 ;
     RECT  63.288 24.629 64.602 24.701 ;
     RECT  65.52 24.629 66.186 24.701 ;
     RECT  175.104 24.331 175.497 24.709 ;
     RECT  134.568 24.511 134.586 24.736 ;
     RECT  136.908 24.629 140.346 24.736 ;
     RECT  94.215 24.629 94.95 24.737 ;
     RECT  70.668 24.601 70.902 24.749 ;
     RECT  34.704 24.701 59.886 24.773 ;
     RECT  168.336 24.673 170.097 24.773 ;
     RECT  136.908 24.736 140.382 24.781 ;
     RECT  210.456 24.359 213.57 24.809 ;
     RECT  70.668 24.749 70.758 24.871 ;
     RECT  109.044 24.781 109.062 24.871 ;
     RECT  112.176 24.511 112.194 24.871 ;
     RECT  65.52 24.701 65.538 24.899 ;
     RECT  210.456 24.809 213.297 24.899 ;
     RECT  78.015 24.368 78.297 24.907 ;
     RECT  88.815 24.368 89.097 24.907 ;
     RECT  90.612 24.871 90.63 24.907 ;
     RECT  2.415 24.511 33.75 24.935 ;
     RECT  34.704 24.773 59.85 24.935 ;
     RECT  83.415 24.089 83.697 24.943 ;
     RECT  174.6 24.709 175.497 24.943 ;
     RECT  88.815 24.907 90.63 24.944 ;
     RECT  64.116 24.701 64.602 24.971 ;
     RECT  89.892 24.944 90.63 24.989 ;
     RECT  81.036 24.907 81.054 25.003 ;
     RECT  28.332 24.935 33.75 25.007 ;
     RECT  64.188 24.971 64.386 25.007 ;
     RECT  86.652 24.907 86.67 25.007 ;
     RECT  89.892 24.989 89.91 25.007 ;
     RECT  109.044 24.871 109.314 25.007 ;
     RECT  112.176 24.871 112.446 25.007 ;
     RECT  39.852 24.935 59.85 25.037 ;
     RECT  28.332 25.007 28.602 25.043 ;
     RECT  49.572 25.037 59.85 25.043 ;
     RECT  64.188 25.007 64.206 25.043 ;
     RECT  80.964 25.003 81.054 25.043 ;
     RECT  39.852 25.037 48.51 25.079 ;
     RECT  63.288 24.701 63.306 25.079 ;
     RECT  210.924 24.899 213.297 25.079 ;
     RECT  167.688 25.015 167.706 25.085 ;
     RECT  72.615 2.413 72.897 25.141 ;
     RECT  28.332 25.043 28.566 25.169 ;
     RECT  34.704 24.935 39.078 25.169 ;
     RECT  53.64 25.043 59.85 25.169 ;
     RECT  2.415 24.935 27.594 25.205 ;
     RECT  34.704 25.169 38.934 25.205 ;
     RECT  79.848 24.871 79.866 25.213 ;
     RECT  141.588 25.141 141.606 25.213 ;
     RECT  166.5 24.871 166.518 25.213 ;
     RECT  168.552 24.773 170.097 25.213 ;
     RECT  29.415 25.007 33.75 25.226 ;
     RECT  34.704 25.205 36.738 25.226 ;
     RECT  72.615 25.141 73.314 25.243 ;
     RECT  134.532 24.736 134.586 25.249 ;
     RECT  196.815 24.368 197.097 25.249 ;
     RECT  37.692 25.205 38.934 25.277 ;
     RECT  79.848 25.213 80.01 25.277 ;
     RECT  219.456 24.871 219.474 25.277 ;
     RECT  0.108 24.667 0.126 25.285 ;
     RECT  174.528 24.943 175.497 25.285 ;
     RECT  198.936 24.907 198.954 25.285 ;
     RECT  166.464 25.213 166.518 25.291 ;
     RECT  29.415 25.226 36.738 25.313 ;
     RECT  49.572 25.043 52.866 25.313 ;
     RECT  53.64 25.169 58.626 25.313 ;
     RECT  72.18 25.243 73.314 25.313 ;
     RECT  69.084 25.249 69.102 25.321 ;
     RECT  70.344 24.871 70.758 25.321 ;
     RECT  28.44 25.169 28.566 25.349 ;
     RECT  38.232 25.277 38.934 25.349 ;
     RECT  53.64 25.313 58.59 25.373 ;
     RECT  72.18 25.313 72.897 25.411 ;
     RECT  83.415 24.943 83.826 25.411 ;
     RECT  148.215 2.413 148.497 25.411 ;
     RECT  202.215 24.233 202.497 25.411 ;
     RECT  28.476 25.349 28.566 25.439 ;
     RECT  29.415 25.313 35.982 25.439 ;
     RECT  59.544 25.169 59.562 25.439 ;
     RECT  136.908 24.781 140.814 25.439 ;
     RECT  166.464 25.291 167.022 25.439 ;
     RECT  214.056 25.321 214.074 25.439 ;
     RECT  148.215 25.411 149.346 25.469 ;
     RECT  34.704 25.439 35.982 25.475 ;
     RECT  39.852 25.079 48.438 25.475 ;
     RECT  56.124 25.373 58.59 25.475 ;
     RECT  80.64 25.435 80.73 25.475 ;
     RECT  168.552 25.213 170.442 25.475 ;
     RECT  68.508 25.321 70.758 25.483 ;
     RECT  78.015 24.907 78.678 25.483 ;
     RECT  79.776 25.411 79.794 25.483 ;
     RECT  200.34 24.745 200.358 25.483 ;
     RECT  29.415 25.439 30.978 25.511 ;
     RECT  56.16 25.475 58.59 25.511 ;
     RECT  68.508 25.483 70.83 25.511 ;
     RECT  134.532 25.249 134.622 25.511 ;
     RECT  139.68 25.439 140.814 25.511 ;
     RECT  141.588 25.213 141.642 25.511 ;
     RECT  166.464 25.439 166.482 25.511 ;
     RECT  31.788 25.439 33.426 25.517 ;
     RECT  136.98 25.439 138.87 25.517 ;
     RECT  140.58 25.511 140.814 25.517 ;
     RECT  148.215 25.469 149.274 25.517 ;
     RECT  78.015 25.483 79.794 25.52 ;
     RECT  65.556 25.483 65.574 25.531 ;
     RECT  30.708 25.511 30.978 25.547 ;
     RECT  65.556 25.531 65.934 25.555 ;
     RECT  82.98 25.411 83.826 25.555 ;
     RECT  38.592 25.349 38.934 25.565 ;
     RECT  81.468 25.411 81.486 25.565 ;
     RECT  78.015 25.52 78.678 25.583 ;
     RECT  80.712 25.475 80.73 25.583 ;
     RECT  134.532 25.511 134.55 25.583 ;
     RECT  136.98 25.517 138.006 25.583 ;
     RECT  67.215 24.269 67.497 25.591 ;
     RECT  200.34 25.483 200.574 25.591 ;
     RECT  201.852 25.411 202.497 25.591 ;
     RECT  39.852 25.475 43.974 25.613 ;
     RECT  82.98 25.555 84.114 25.613 ;
     RECT  30.708 25.547 30.942 25.619 ;
     RECT  44.748 25.475 48.438 25.619 ;
     RECT  53.64 25.373 55.35 25.619 ;
     RECT  56.304 25.511 58.59 25.619 ;
     RECT  136.98 25.583 137.697 25.619 ;
     RECT  141.624 25.511 141.642 25.619 ;
     RECT  28.548 25.439 28.566 25.661 ;
     RECT  54.936 25.619 55.35 25.661 ;
     RECT  79.452 25.52 79.794 25.661 ;
     RECT  166.356 25.555 166.374 25.661 ;
     RECT  2.415 25.205 27.558 25.667 ;
     RECT  61.815 24.233 62.097 25.667 ;
     RECT  71.82 25.411 72.897 25.667 ;
     RECT  88.815 24.944 89.097 25.667 ;
     RECT  94.215 24.737 94.497 25.667 ;
     RECT  99.615 24.368 99.897 25.667 ;
     RECT  105.015 2.413 105.297 25.667 ;
     RECT  110.415 24.365 110.697 25.667 ;
     RECT  115.815 2.413 116.097 25.667 ;
     RECT  121.215 24.368 121.497 25.667 ;
     RECT  126.615 2.413 126.897 25.667 ;
     RECT  132.015 24.368 132.297 25.667 ;
     RECT  137.34 25.619 137.697 25.667 ;
     RECT  142.815 24.368 143.097 25.667 ;
     RECT  159.015 2.413 159.297 25.667 ;
     RECT  164.415 24.368 164.697 25.667 ;
     RECT  174.492 25.285 175.497 25.667 ;
     RECT  180.615 2.413 180.897 25.667 ;
     RECT  186.015 24.368 186.297 25.667 ;
     RECT  191.415 2.413 191.697 25.667 ;
     RECT  153.615 24.368 153.897 25.681 ;
     RECT  196.815 25.249 197.37 25.681 ;
     RECT  32.112 25.517 33.426 25.709 ;
     RECT  34.704 25.475 35.946 25.709 ;
     RECT  39.852 25.613 42.138 25.709 ;
     RECT  47.088 25.619 47.574 25.709 ;
     RECT  48.348 25.619 48.438 25.709 ;
     RECT  53.64 25.619 54.126 25.709 ;
     RECT  148.215 25.517 148.914 25.709 ;
     RECT  217.836 25.051 217.854 25.709 ;
     RECT  182.376 25.681 182.394 25.717 ;
     RECT  216.756 25.591 216.774 25.745 ;
     RECT  47.088 25.709 47.43 25.757 ;
     RECT  82.656 25.681 82.674 25.757 ;
     RECT  153.615 25.681 154.458 25.757 ;
     RECT  32.112 25.709 33.246 25.781 ;
     RECT  76.572 25.681 76.59 25.781 ;
     RECT  50.868 25.313 52.866 25.789 ;
     RECT  53.64 25.709 53.766 25.789 ;
     RECT  196.704 25.681 197.37 25.789 ;
     RECT  182.052 25.717 182.394 25.805 ;
     RECT  32.112 25.781 32.958 25.817 ;
     RECT  39.852 25.709 40.305 25.825 ;
     RECT  49.572 25.313 50.094 25.825 ;
     RECT  78.015 25.583 78.354 25.825 ;
     RECT  174.492 25.667 175.41 25.825 ;
     RECT  198.936 25.285 199.242 25.825 ;
     RECT  196.704 25.789 197.406 25.852 ;
     RECT  48.42 25.709 48.438 25.853 ;
     RECT  49.392 25.825 50.094 25.861 ;
     RECT  63.576 25.825 63.594 25.861 ;
     RECT  67.215 25.591 67.698 25.861 ;
     RECT  68.508 25.511 68.562 25.861 ;
     RECT  69.66 25.511 70.83 25.861 ;
     RECT  71.82 25.667 72.705 25.861 ;
     RECT  198.936 25.825 199.422 25.861 ;
     RECT  200.34 25.591 200.862 25.861 ;
     RECT  201.672 25.591 202.497 25.861 ;
     RECT  205.092 24.097 205.11 25.861 ;
     RECT  32.112 25.817 32.886 25.889 ;
     RECT  38.592 25.565 38.862 25.889 ;
     RECT  50.868 25.789 53.766 25.889 ;
     RECT  69.66 25.861 72.705 25.889 ;
     RECT  2.415 25.667 24.105 25.937 ;
     RECT  29.415 25.511 29.862 25.937 ;
     RECT  39.78 25.825 40.305 25.937 ;
     RECT  51.015 25.889 53.766 25.937 ;
     RECT  61.815 25.667 61.905 25.937 ;
     RECT  69.696 25.889 72.705 25.937 ;
     RECT  83.415 25.613 83.79 25.937 ;
     RECT  94.215 25.667 94.305 25.937 ;
     RECT  105.015 25.667 105.105 25.937 ;
     RECT  115.815 25.667 115.905 25.937 ;
     RECT  126.615 25.667 126.705 25.937 ;
     RECT  137.34 25.667 137.505 25.937 ;
     RECT  148.215 25.709 148.305 25.937 ;
     RECT  159.015 25.667 159.105 25.937 ;
     RECT  169.02 25.475 170.442 25.937 ;
     RECT  180.615 25.667 180.705 25.937 ;
     RECT  191.415 25.667 191.505 25.937 ;
     RECT  67.215 25.861 68.562 25.951 ;
     RECT  88.815 25.667 89.01 25.951 ;
     RECT  99.615 25.667 99.81 25.951 ;
     RECT  110.415 25.667 110.61 25.951 ;
     RECT  121.215 25.667 121.41 25.951 ;
     RECT  132.015 25.667 132.21 25.951 ;
     RECT  142.815 25.667 143.01 25.951 ;
     RECT  153.615 25.757 154.098 25.951 ;
     RECT  164.415 25.667 164.61 25.951 ;
     RECT  186.015 25.667 186.21 25.951 ;
     RECT  194.364 25.147 194.382 25.963 ;
     RECT  170.424 25.937 170.442 25.979 ;
     RECT  198.936 25.861 200.862 25.987 ;
     RECT  201.6 25.861 202.497 25.987 ;
     RECT  56.304 25.619 57.798 25.997 ;
     RECT  77.724 25.825 78.354 25.997 ;
     RECT  79.452 25.661 79.47 25.997 ;
     RECT  88.704 25.951 89.01 25.997 ;
     RECT  99.504 25.951 99.81 25.997 ;
     RECT  110.304 25.951 110.61 25.997 ;
     RECT  121.104 25.951 121.41 25.997 ;
     RECT  131.904 25.951 132.21 25.997 ;
     RECT  142.704 25.951 143.01 25.997 ;
     RECT  153.504 25.951 154.098 25.997 ;
     RECT  164.304 25.951 164.61 25.997 ;
     RECT  174.384 25.825 175.41 25.997 ;
     RECT  185.904 25.951 186.21 25.997 ;
     RECT  24.84 25.667 27.558 26.015 ;
     RECT  34.704 25.709 35.73 26.015 ;
     RECT  38.7 25.889 38.862 26.015 ;
     RECT  65.556 25.555 66.186 26.015 ;
     RECT  48.672 25.861 50.094 26.045 ;
     RECT  81.252 25.861 81.27 26.045 ;
     RECT  82.368 25.861 82.386 26.045 ;
     RECT  2.415 25.937 23.886 26.087 ;
     RECT  24.84 26.015 27.378 26.087 ;
     RECT  30.708 25.619 30.87 26.087 ;
     RECT  35.064 26.015 35.73 26.087 ;
     RECT  51.228 25.937 53.766 26.087 ;
     RECT  41.076 25.709 41.094 26.093 ;
     RECT  44.748 25.619 46.242 26.093 ;
     RECT  77.976 25.997 78.354 26.093 ;
     RECT  83.772 25.937 83.79 26.093 ;
     RECT  194.364 25.963 194.49 26.093 ;
     RECT  174.384 25.997 174.402 26.095 ;
     RECT  57.276 25.997 57.798 26.123 ;
     RECT  41.868 25.709 42.138 26.141 ;
     RECT  173.844 26.095 174.402 26.141 ;
     RECT  182.052 25.805 182.07 26.141 ;
     RECT  44.748 26.093 45.09 26.159 ;
     RECT  53.64 26.087 53.766 26.159 ;
     RECT  174.384 26.141 174.402 26.189 ;
     RECT  30.708 26.087 30.798 26.204 ;
     RECT  38.7 26.015 38.79 26.204 ;
     RECT  41.868 26.141 42.03 26.204 ;
     RECT  194.364 26.093 194.382 26.237 ;
     RECT  140.76 25.517 140.814 26.249 ;
     RECT  154.08 25.997 154.098 26.249 ;
     RECT  0.108 25.285 0.162 26.299 ;
     RECT  0.108 26.299 0.558 26.393 ;
     RECT  63.576 25.861 63.846 26.393 ;
     RECT  205.056 25.861 205.11 26.401 ;
     RECT  214.848 26.251 214.866 26.401 ;
     RECT  24.84 26.087 27.306 26.429 ;
     RECT  196.668 25.852 197.406 26.446 ;
     RECT  32.112 25.889 32.202 26.474 ;
     RECT  69.696 25.937 72.45 26.477 ;
     RECT  66.096 26.015 66.186 26.491 ;
     RECT  67.104 25.951 68.562 26.491 ;
     RECT  206.352 26.401 206.37 26.491 ;
     RECT  63.828 26.393 63.846 26.519 ;
     RECT  214.848 26.401 215.01 26.519 ;
     RECT  217.224 26.401 217.422 26.519 ;
     RECT  75.204 25.861 75.474 26.525 ;
     RECT  196.668 26.446 197.694 26.527 ;
     RECT  205.056 26.401 205.578 26.527 ;
     RECT  57.528 26.123 57.798 26.555 ;
     RECT  214.848 26.519 214.866 26.555 ;
     RECT  103.68 24.467 103.698 26.563 ;
     RECT  196.668 26.527 198.09 26.563 ;
     RECT  198.936 25.987 202.497 26.563 ;
     RECT  209.16 26.491 209.178 26.587 ;
     RECT  47.088 25.757 47.106 26.591 ;
     RECT  75.204 26.525 75.222 26.591 ;
     RECT  103.176 26.563 103.698 26.591 ;
     RECT  204.516 26.527 205.578 26.599 ;
     RECT  206.352 26.491 206.406 26.599 ;
     RECT  27.288 26.429 27.306 26.621 ;
     RECT  204.516 26.599 206.406 26.621 ;
     RECT  46.224 26.093 46.242 26.627 ;
     RECT  112.428 25.007 112.446 26.627 ;
     RECT  207.18 22.711 207.897 26.635 ;
     RECT  43.308 25.613 43.974 26.663 ;
     RECT  137.34 25.937 137.358 26.663 ;
     RECT  204.516 26.621 205.938 26.671 ;
     RECT  217.296 26.519 217.422 26.671 ;
     RECT  41.868 26.204 41.886 26.699 ;
     RECT  169.02 25.937 169.578 26.699 ;
     RECT  208.908 26.587 209.178 26.699 ;
     RECT  0.108 26.393 0.162 26.731 ;
     RECT  43.956 26.663 43.974 26.744 ;
     RECT  0.072 26.731 0.162 26.765 ;
     RECT  39.78 25.937 40.086 26.789 ;
     RECT  208.98 26.699 208.998 26.789 ;
     RECT  215.784 26.671 215.802 26.789 ;
     RECT  217.296 26.671 217.53 26.789 ;
     RECT  219.42 26.539 219.438 26.789 ;
     RECT  66.096 26.491 68.562 26.825 ;
     RECT  217.512 26.789 217.53 26.825 ;
     RECT  204.444 26.671 205.938 26.833 ;
     RECT  77.976 26.093 77.994 26.897 ;
     RECT  69.696 26.477 71.154 26.933 ;
     RECT  72.396 26.477 72.45 26.969 ;
     RECT  71.136 26.933 71.154 27.053 ;
     RECT  24.84 26.429 26.262 27.059 ;
     RECT  51.228 26.087 52.866 27.095 ;
     RECT  66.168 26.825 68.562 27.101 ;
     RECT  24.912 27.059 26.262 27.131 ;
     RECT  69.696 26.933 70.146 27.131 ;
     RECT  52.128 27.095 52.866 27.149 ;
     RECT  66.168 27.101 66.798 27.167 ;
     RECT  196.668 26.563 202.497 27.175 ;
     RECT  49.392 26.045 50.094 27.197 ;
     RECT  55.332 25.661 55.35 27.203 ;
     RECT  49.392 27.197 49.41 27.239 ;
     RECT  72.432 26.969 72.45 27.239 ;
     RECT  39.78 26.789 39.798 27.245 ;
     RECT  29.844 25.937 29.862 27.293 ;
     RECT  2.415 26.087 23.346 27.307 ;
     RECT  103.176 26.591 103.194 27.329 ;
     RECT  196.668 27.175 202.77 27.337 ;
     RECT  24.912 27.131 25.074 27.341 ;
     RECT  196.668 27.337 202.806 27.355 ;
     RECT  203.868 26.833 205.938 27.355 ;
     RECT  196.668 27.355 205.938 27.389 ;
     RECT  205.056 27.389 205.938 27.481 ;
     RECT  206.676 26.635 207.897 27.481 ;
     RECT  0.072 26.765 0.126 27.677 ;
     RECT  211.284 25.079 213.297 27.715 ;
     RECT  211.176 27.715 213.297 27.773 ;
     RECT  214.02 27.751 214.038 27.869 ;
     RECT  219.42 27.832 219.438 27.869 ;
     RECT  211.284 27.773 213.297 27.877 ;
     RECT  211.284 27.877 213.894 27.917 ;
     RECT  217.224 27.985 217.242 28.021 ;
     RECT  2.304 27.307 23.346 28.08 ;
     RECT  24.912 27.341 24.93 28.08 ;
     RECT  26.208 27.131 26.262 28.08 ;
     RECT  27.36 27.103 27.378 28.08 ;
     RECT  32.112 26.474 32.13 28.08 ;
     RECT  35.712 26.087 35.73 28.08 ;
     RECT  44.748 26.159 44.766 28.08 ;
     RECT  51.228 27.095 51.246 28.08 ;
     RECT  52.128 27.149 52.722 28.08 ;
     RECT  53.748 26.159 53.766 28.08 ;
     RECT  57.78 26.555 57.798 28.08 ;
     RECT  66.168 27.167 66.186 28.08 ;
     RECT  67.788 27.101 68.562 28.08 ;
     RECT  70.128 27.131 70.146 28.08 ;
     RECT  74.448 25.825 74.466 28.08 ;
     RECT  107.64 25.321 107.658 28.08 ;
     RECT  109.296 25.007 109.314 28.08 ;
     RECT  138.852 25.517 138.87 28.08 ;
     RECT  140.796 26.249 140.814 28.08 ;
     RECT  169.02 26.699 169.038 28.08 ;
     RECT  196.668 27.389 204.174 28.08 ;
     RECT  216.504 28.021 217.242 28.139 ;
     RECT  0.072 27.677 0.09 28.175 ;
     RECT  216.504 28.139 216.522 28.175 ;
     RECT  205.056 27.481 207.897 28.211 ;
     RECT  2.304 28.08 204.174 28.381 ;
     RECT  205.056 28.211 205.434 28.381 ;
     RECT  1.152 27.979 1.17 28.453 ;
     RECT  2.304 28.381 205.434 28.453 ;
     RECT  1.152 28.453 205.434 28.685 ;
     RECT  2.304 28.685 205.434 28.985 ;
     RECT  2.34 28.985 205.434 29.101 ;
     RECT  206.244 28.211 207.897 29.101 ;
     RECT  219.456 28.921 219.474 29.165 ;
     RECT  211.284 27.917 213.39 29.179 ;
     RECT  214.344 29.101 214.362 29.219 ;
     RECT  217.764 29.029 217.782 29.219 ;
     RECT  0.108 29.227 0.126 29.309 ;
     RECT  211.284 29.179 213.426 29.309 ;
     RECT  2.34 29.101 207.897 29.371 ;
     RECT  216.504 28.921 216.522 29.461 ;
     RECT  217.548 29.335 217.566 29.461 ;
     RECT  216.504 29.461 217.566 29.489 ;
     RECT  216.936 29.489 217.566 29.561 ;
     RECT  2.34 29.371 208.026 29.911 ;
     RECT  2.34 29.911 208.242 29.947 ;
     RECT  2.304 29.947 208.242 30.029 ;
     RECT  204.408 30.029 208.242 30.173 ;
     RECT  2.304 30.029 203.67 30.221 ;
     RECT  204.408 30.173 207.897 30.335 ;
     RECT  206.244 30.335 207.897 30.407 ;
     RECT  219.456 30.001 219.474 30.461 ;
     RECT  2.304 30.221 10.494 30.479 ;
     RECT  211.284 29.309 213.297 30.479 ;
     RECT  3.528 30.479 10.494 30.569 ;
     RECT  216.36 30.307 216.378 30.569 ;
     RECT  206.46 30.407 207.897 30.605 ;
     RECT  206.784 30.605 207.897 30.611 ;
     RECT  3.636 30.569 10.494 30.641 ;
     RECT  1.152 28.685 1.17 30.677 ;
     RECT  217.548 29.561 217.566 30.685 ;
     RECT  217.548 30.685 217.854 30.721 ;
     RECT  11.232 30.221 203.67 30.811 ;
     RECT  204.408 30.335 205.362 30.811 ;
     RECT  217.224 30.721 217.854 30.839 ;
     RECT  217.224 30.839 217.242 30.875 ;
     RECT  3.888 30.641 10.494 30.991 ;
     RECT  11.232 30.811 205.362 30.991 ;
     RECT  3.888 30.991 205.362 31.019 ;
     RECT  0.108 30.283 0.126 31.145 ;
     RECT  211.284 30.479 211.302 31.339 ;
     RECT  212.472 30.479 213.297 31.339 ;
     RECT  2.304 30.479 2.697 31.531 ;
     RECT  205.956 31.387 205.974 31.649 ;
     RECT  2.304 31.531 3.006 31.685 ;
     RECT  2.34 31.685 3.006 31.765 ;
     RECT  3.888 31.019 205.074 31.765 ;
     RECT  218.844 31.723 218.862 31.829 ;
     RECT  217.476 31.801 217.494 31.891 ;
     RECT  211.284 31.339 213.297 31.901 ;
     RECT  205.812 31.801 205.902 31.919 ;
     RECT  205.812 31.919 205.83 31.955 ;
     RECT  216.36 31.927 216.378 31.997 ;
     RECT  2.34 31.765 205.074 32.027 ;
     RECT  217.476 31.891 217.746 32.035 ;
     RECT  217.26 32.035 217.818 32.189 ;
     RECT  217.26 32.189 217.746 32.261 ;
     RECT  207.18 30.611 207.897 32.603 ;
     RECT  212.472 31.901 213.297 32.611 ;
     RECT  212.472 32.611 213.714 32.729 ;
     RECT  217.26 32.261 217.422 32.845 ;
     RECT  209.916 32.809 209.934 32.881 ;
     RECT  211.284 31.901 211.554 32.881 ;
     RECT  0.108 31.915 0.126 32.923 ;
     RECT  214.74 32.881 214.758 32.923 ;
     RECT  2.415 32.027 205.074 32.957 ;
     RECT  209.808 32.881 209.934 32.971 ;
     RECT  214.596 32.923 214.758 32.999 ;
     RECT  216.936 32.845 217.422 32.999 ;
     RECT  207.615 32.603 207.897 33.007 ;
     RECT  208.62 32.881 208.638 33.007 ;
     RECT  217.404 32.999 217.422 33.035 ;
     RECT  207.615 33.007 208.638 33.043 ;
     RECT  209.808 32.971 210.294 33.053 ;
     RECT  0.108 32.923 0.162 33.071 ;
     RECT  211.176 32.881 211.554 33.079 ;
     RECT  212.472 32.729 213.462 33.079 ;
     RECT  207.615 33.043 208.89 33.115 ;
     RECT  209.808 33.053 210.006 33.115 ;
     RECT  211.176 33.079 213.462 33.151 ;
     RECT  2.415 32.957 2.97 33.259 ;
     RECT  207.615 33.115 210.006 33.269 ;
     RECT  210.78 33.151 213.462 33.269 ;
     RECT  217.512 33.151 217.53 33.269 ;
     RECT  219.42 33.019 219.438 33.269 ;
     RECT  207.615 33.269 208.89 33.389 ;
     RECT  210.924 33.269 213.462 33.539 ;
     RECT  1.152 32.251 1.17 33.575 ;
     RECT  0.108 33.071 0.126 33.629 ;
     RECT  209.808 33.269 210.006 33.629 ;
     RECT  210.924 33.539 213.354 33.809 ;
     RECT  2.304 33.259 2.97 33.817 ;
     RECT  3.708 32.957 205.074 33.817 ;
     RECT  211.464 33.809 211.59 33.989 ;
     RECT  1.296 33.931 1.314 34.159 ;
     RECT  2.304 33.817 205.074 34.159 ;
     RECT  1.296 34.159 205.074 34.253 ;
     RECT  219.42 34.267 219.438 34.349 ;
     RECT  212.472 33.809 213.354 34.385 ;
     RECT  217.26 34.321 217.278 34.393 ;
     RECT  217.26 34.393 217.458 34.465 ;
     RECT  211.464 33.989 211.482 34.493 ;
     RECT  2.304 34.253 205.074 34.501 ;
     RECT  216.9 34.465 217.458 34.501 ;
     RECT  216.9 34.501 217.566 34.619 ;
     RECT  209.988 33.629 210.006 34.861 ;
     RECT  2.304 34.501 205.434 34.925 ;
     RECT  209.988 34.861 210.33 35.083 ;
     RECT  1.296 34.253 1.314 35.267 ;
     RECT  209.988 35.083 210.582 35.311 ;
     RECT  2.34 34.925 205.434 35.339 ;
     RECT  2.376 35.339 205.434 35.405 ;
     RECT  217.872 35.311 217.89 35.429 ;
     RECT  209.988 35.311 210.942 35.465 ;
     RECT  209.988 35.465 210.006 35.537 ;
     RECT  210.924 35.465 210.942 35.545 ;
     RECT  0.108 34.891 0.126 35.563 ;
     RECT  212.652 34.385 213.354 35.581 ;
     RECT  219.456 35.131 219.474 35.597 ;
     RECT  212.436 35.581 213.354 35.699 ;
     RECT  210.924 35.545 211.518 35.837 ;
     RECT  217.836 35.545 217.854 35.851 ;
     RECT  217.296 35.851 217.854 35.969 ;
     RECT  217.296 35.969 217.314 36.005 ;
     RECT  0.108 35.563 0.162 36.275 ;
     RECT  215.28 33.961 215.298 36.275 ;
     RECT  210.924 35.837 210.942 36.475 ;
     RECT  2.376 35.405 22.158 36.581 ;
     RECT  2.415 36.581 22.158 36.653 ;
     RECT  21.924 36.653 22.158 36.661 ;
     RECT  22.896 35.405 205.434 36.661 ;
     RECT  210.204 36.475 210.942 36.689 ;
     RECT  210.204 36.689 210.222 36.815 ;
     RECT  218.844 36.859 218.862 36.959 ;
     RECT  217.512 36.931 217.53 37.165 ;
     RECT  217.368 37.165 217.71 37.201 ;
     RECT  21.924 36.661 205.434 37.229 ;
     RECT  208.872 33.389 208.89 37.319 ;
     RECT  216.36 37.429 216.378 37.469 ;
     RECT  217.368 37.201 217.926 37.471 ;
     RECT  217.224 37.471 217.926 37.499 ;
     RECT  217.224 37.499 217.854 37.589 ;
     RECT  1.152 36.571 1.17 37.895 ;
     RECT  2.415 36.653 20.862 37.975 ;
     RECT  21.96 37.229 205.434 37.975 ;
     RECT  215.532 36.391 215.55 38.011 ;
     RECT  212.652 35.699 213.354 38.039 ;
     RECT  215.064 38.011 215.55 38.059 ;
     RECT  214.92 38.059 215.55 38.129 ;
     RECT  217.332 37.589 217.854 38.129 ;
     RECT  0.108 36.275 0.126 38.165 ;
     RECT  2.415 37.975 205.434 38.381 ;
     RECT  217.836 38.129 217.854 38.399 ;
     RECT  219.42 38.155 219.438 38.399 ;
     RECT  1.44 38.203 1.458 38.515 ;
     RECT  2.415 38.381 20.718 38.515 ;
     RECT  21.96 38.381 205.434 38.669 ;
     RECT  1.44 38.515 20.718 38.909 ;
     RECT  2.304 38.909 20.718 39.317 ;
     RECT  2.415 39.317 20.718 39.325 ;
     RECT  216.72 39.325 216.738 39.361 ;
     RECT  2.415 39.325 21.15 39.479 ;
     RECT  22.176 38.669 205.434 39.479 ;
     RECT  216.72 39.361 217.386 39.479 ;
     RECT  3.492 39.479 21.15 39.515 ;
     RECT  22.212 39.479 205.434 39.515 ;
     RECT  217.368 39.479 217.386 39.515 ;
     RECT  0.108 39.208 0.126 39.533 ;
     RECT  1.44 38.909 1.458 39.587 ;
     RECT  212.652 38.039 213.297 39.589 ;
     RECT  212.652 39.589 213.39 39.629 ;
     RECT  212.652 39.629 213.297 39.659 ;
     RECT  217.512 39.631 217.53 39.749 ;
     RECT  219.42 39.451 219.438 39.749 ;
     RECT  2.415 39.479 2.697 40.171 ;
     RECT  3.888 39.515 21.15 40.261 ;
     RECT  1.152 39.835 1.17 40.405 ;
     RECT  2.304 40.171 2.697 40.405 ;
     RECT  3.78 40.261 21.15 40.405 ;
     RECT  1.152 40.405 21.15 40.541 ;
     RECT  2.304 40.541 21.15 40.603 ;
     RECT  22.248 39.515 205.434 40.603 ;
     RECT  217.224 40.675 217.242 40.711 ;
     RECT  211.536 40.711 211.554 40.829 ;
     RECT  217.224 40.711 217.674 40.829 ;
     RECT  2.304 40.603 205.434 41.099 ;
     RECT  2.304 41.099 3.114 41.135 ;
     RECT  217.656 40.829 217.674 41.135 ;
     RECT  217.764 41.251 217.782 41.369 ;
     RECT  215.532 38.129 215.55 41.683 ;
     RECT  215.28 41.683 215.55 42.025 ;
     RECT  2.415 41.135 2.934 42.061 ;
     RECT  215.1 42.025 215.55 42.061 ;
     RECT  215.1 42.061 216.09 42.077 ;
     RECT  219.42 40.747 219.438 42.089 ;
     RECT  2.415 42.061 3.114 42.139 ;
     RECT  217.62 42.061 217.638 42.151 ;
     RECT  3.888 41.099 205.434 42.179 ;
     RECT  215.532 42.077 216.09 42.179 ;
     RECT  1.152 40.541 1.314 42.215 ;
     RECT  2.304 42.139 3.114 42.323 ;
     RECT  2.34 42.323 3.114 42.331 ;
     RECT  3.888 42.179 21.726 42.331 ;
     RECT  217.44 42.151 217.638 42.331 ;
     RECT  217.224 42.331 217.638 42.449 ;
     RECT  0.108 41.755 0.126 42.509 ;
     RECT  1.296 42.215 1.314 42.557 ;
     RECT  2.34 42.331 21.726 42.755 ;
     RECT  211.464 40.922 211.482 42.763 ;
     RECT  211.464 42.763 212.022 42.797 ;
     RECT  3.852 42.755 21.726 42.989 ;
     RECT  210.492 42.763 210.51 42.997 ;
     RECT  213.015 39.659 213.297 42.997 ;
     RECT  21.672 42.989 21.726 43.051 ;
     RECT  22.752 42.179 205.434 43.051 ;
     RECT  206.352 42.955 206.37 43.085 ;
     RECT  217.224 42.449 217.494 43.105 ;
     RECT  3.852 42.989 20.754 43.133 ;
     RECT  210.348 42.997 210.51 43.133 ;
     RECT  2.34 42.755 3.114 43.147 ;
     RECT  3.852 43.133 20.718 43.259 ;
     RECT  210.384 43.133 210.51 43.259 ;
     RECT  213.015 42.997 213.786 43.259 ;
     RECT  217.116 43.105 217.494 43.259 ;
     RECT  2.304 43.147 3.114 43.267 ;
     RECT  217.404 43.259 217.494 43.295 ;
     RECT  212.004 42.797 212.022 43.325 ;
     RECT  213.015 43.259 213.606 43.331 ;
     RECT  1.728 43.267 3.114 43.501 ;
     RECT  3.852 43.259 20.214 43.501 ;
     RECT  1.728 43.501 20.214 43.517 ;
     RECT  217.512 43.411 217.53 43.529 ;
     RECT  219.42 43.291 219.438 43.529 ;
     RECT  2.304 43.517 20.214 43.565 ;
     RECT  21.672 43.051 205.434 43.819 ;
     RECT  2.34 43.565 20.214 44.221 ;
     RECT  2.34 44.221 20.646 44.491 ;
     RECT  214.128 44.443 214.146 44.491 ;
     RECT  216.684 44.455 216.702 44.491 ;
     RECT  214.128 44.491 214.326 44.609 ;
     RECT  216.684 44.491 216.954 44.609 ;
     RECT  214.128 44.609 214.146 44.645 ;
     RECT  0.108 44.725 0.126 44.813 ;
     RECT  2.304 44.491 20.718 44.827 ;
     RECT  21.636 43.819 205.434 44.827 ;
     RECT  219.42 44.587 219.438 44.879 ;
     RECT  217.224 44.761 217.242 44.915 ;
     RECT  2.304 44.827 205.434 44.951 ;
     RECT  1.152 44.155 1.17 45.115 ;
     RECT  0.54 45.115 1.17 45.293 ;
     RECT  21.06 44.951 205.434 45.293 ;
     RECT  22.248 45.293 205.434 45.581 ;
     RECT  2.304 44.951 20.214 45.841 ;
     RECT  21.06 45.293 21.078 45.841 ;
     RECT  218.88 45.841 218.898 45.917 ;
     RECT  2.304 45.841 21.078 46.123 ;
     RECT  22.284 45.581 205.434 46.315 ;
     RECT  1.152 45.293 1.17 46.345 ;
     RECT  2.304 46.123 21.114 46.409 ;
     RECT  2.304 46.409 20.214 46.535 ;
     RECT  21.096 46.409 21.114 46.603 ;
     RECT  22.212 46.315 205.434 46.603 ;
     RECT  0.54 46.345 1.17 46.877 ;
     RECT  21.096 46.603 205.434 47.219 ;
     RECT  219.42 47.179 219.438 47.345 ;
     RECT  2.415 46.535 20.214 47.389 ;
     RECT  21.06 47.281 21.078 47.389 ;
     RECT  2.415 47.389 21.078 47.849 ;
     RECT  22.212 47.219 205.434 47.947 ;
     RECT  1.152 46.877 1.17 48.299 ;
     RECT  219.456 48.397 219.474 48.509 ;
     RECT  2.415 47.849 20.538 48.659 ;
     RECT  21.672 47.947 205.434 48.715 ;
     RECT  3.528 48.659 20.538 48.811 ;
     RECT  21.636 48.715 205.434 48.811 ;
     RECT  3.528 48.811 205.434 49.199 ;
     RECT  3.528 49.199 21.726 49.325 ;
     RECT  2.415 48.659 2.697 49.435 ;
     RECT  2.304 49.435 2.697 49.441 ;
     RECT  3.528 49.325 21.654 49.441 ;
     RECT  2.304 49.441 21.654 49.477 ;
     RECT  1.728 49.477 21.654 49.541 ;
     RECT  0.108 47.695 0.126 49.577 ;
     RECT  1.728 49.541 2.697 49.805 ;
     RECT  218.88 49.711 218.898 49.805 ;
     RECT  3.564 49.541 21.654 49.847 ;
     RECT  3.564 49.847 21.366 49.919 ;
     RECT  22.716 49.199 205.434 50.093 ;
     RECT  1.152 50.395 1.17 50.665 ;
     RECT  2.415 49.805 2.697 50.665 ;
     RECT  3.744 49.919 21.366 50.665 ;
     RECT  1.152 50.665 21.366 50.731 ;
     RECT  1.152 50.731 21.654 50.923 ;
     RECT  22.752 50.093 205.434 50.923 ;
     RECT  1.152 50.923 205.434 51.101 ;
     RECT  219.42 51.067 219.438 51.125 ;
     RECT  2.415 51.101 205.434 51.359 ;
     RECT  0.108 50.731 0.126 51.503 ;
     RECT  2.415 51.359 2.697 52.075 ;
     RECT  3.888 51.359 204.894 52.285 ;
     RECT  2.304 52.075 2.697 52.321 ;
     RECT  3.636 52.285 204.894 52.321 ;
     RECT  219.42 52.315 219.438 52.439 ;
     RECT  0.108 52.285 0.126 52.853 ;
     RECT  2.304 52.321 204.894 52.861 ;
     RECT  2.268 52.861 204.894 53.015 ;
     RECT  2.268 53.015 2.862 53.069 ;
     RECT  3.852 53.015 204.894 53.069 ;
     RECT  3.888 53.069 204.894 53.285 ;
     RECT  219.456 53.257 219.474 53.645 ;
     RECT  0.108 53.707 0.126 53.905 ;
     RECT  21.06 53.285 204.894 53.969 ;
     RECT  22.248 53.969 204.894 54.029 ;
     RECT  2.415 53.069 2.862 54.043 ;
     RECT  3.888 53.285 20.25 54.043 ;
     RECT  0.108 53.905 0.162 54.077 ;
     RECT  2.415 54.043 20.25 54.091 ;
     RECT  21.06 53.969 21.15 54.091 ;
     RECT  2.415 54.091 21.15 54.329 ;
     RECT  1.152 51.101 1.17 54.365 ;
     RECT  2.415 54.329 20.214 54.365 ;
     RECT  22.284 54.029 204.894 54.413 ;
     RECT  21.096 54.329 21.15 54.509 ;
     RECT  0.108 54.077 0.126 54.635 ;
     RECT  3.744 54.365 20.214 54.701 ;
     RECT  2.415 54.365 2.697 55.051 ;
     RECT  219.42 54.907 219.438 55.139 ;
     RECT  2.304 55.051 2.697 55.183 ;
     RECT  3.744 54.701 19.674 55.183 ;
     RECT  2.304 55.183 19.674 55.255 ;
     RECT  1.728 55.255 19.674 55.373 ;
     RECT  2.304 55.373 19.674 55.445 ;
     RECT  22.752 54.413 204.894 55.525 ;
     RECT  21.096 54.509 21.114 55.579 ;
     RECT  21.096 55.579 21.15 55.687 ;
     RECT  2.415 55.445 19.674 55.831 ;
     RECT  22.284 55.525 204.894 56.029 ;
     RECT  218.88 56.101 218.898 56.237 ;
     RECT  2.415 55.831 19.926 56.263 ;
     RECT  21.096 55.687 21.186 56.263 ;
     RECT  1.152 56.011 1.17 56.347 ;
     RECT  2.415 56.263 21.186 56.461 ;
     RECT  22.248 56.029 204.894 56.461 ;
     RECT  0.108 56.605 0.126 57.019 ;
     RECT  1.152 56.347 1.206 57.019 ;
     RECT  2.415 56.461 204.894 57.029 ;
     RECT  0.108 57.019 1.206 57.065 ;
     RECT  0.108 57.065 1.17 57.173 ;
     RECT  1.152 57.173 1.17 57.335 ;
     RECT  0.108 57.173 0.126 57.443 ;
     RECT  218.304 57.415 218.322 57.533 ;
     RECT  2.415 57.029 3.15 57.691 ;
     RECT  2.304 57.691 3.15 57.991 ;
     RECT  3.888 57.029 204.894 57.991 ;
     RECT  0.108 58.315 0.126 58.445 ;
     RECT  2.304 57.991 204.894 58.445 ;
     RECT  0.54 58.531 0.558 58.685 ;
     RECT  2.304 58.445 3.078 58.685 ;
     RECT  219.456 58.657 219.474 58.829 ;
     RECT  3.888 58.445 204.894 59.341 ;
     RECT  2.415 58.685 2.754 59.503 ;
     RECT  3.6 59.341 204.894 59.503 ;
     RECT  0.108 59.323 0.126 59.575 ;
     RECT  0.108 59.575 0.162 59.693 ;
     RECT  2.415 59.503 204.894 59.737 ;
     RECT  2.268 59.737 204.894 60.029 ;
     RECT  1.152 58.987 1.17 60.035 ;
     RECT  218.88 60.079 218.898 60.125 ;
     RECT  0.108 59.693 0.126 60.925 ;
     RECT  2.304 60.029 204.894 61.133 ;
     RECT  218.88 61.195 218.898 61.373 ;
     RECT  2.304 61.133 21.726 61.385 ;
     RECT  0.108 60.925 0.162 61.691 ;
     RECT  2.34 61.385 21.726 61.969 ;
     RECT  22.788 61.133 204.894 61.969 ;
     RECT  2.34 61.969 204.894 62.285 ;
     RECT  2.34 62.285 20.79 62.381 ;
     RECT  21.672 62.285 204.894 62.669 ;
     RECT  218.88 62.581 218.898 62.669 ;
     RECT  2.34 62.381 20.502 62.765 ;
     RECT  0.108 61.691 0.126 63.005 ;
     RECT  4.176 62.765 20.502 63.005 ;
     RECT  2.34 62.765 3.186 63.259 ;
     RECT  2.268 63.259 3.186 63.275 ;
     RECT  2.268 63.275 2.697 63.347 ;
     RECT  4.176 63.005 20.106 63.661 ;
     RECT  22.212 62.669 204.894 63.661 ;
     RECT  3.564 63.661 20.106 63.751 ;
     RECT  3.564 63.751 20.574 63.815 ;
     RECT  22.176 63.661 204.894 63.821 ;
     RECT  19.836 63.815 20.574 63.931 ;
     RECT  219.456 63.751 219.474 63.965 ;
     RECT  3.564 63.815 19.098 64.049 ;
     RECT  0.108 63.931 0.126 64.165 ;
     RECT  19.836 63.931 21.186 64.205 ;
     RECT  21.096 64.205 21.186 64.291 ;
     RECT  22.788 63.821 204.894 64.561 ;
     RECT  22.788 64.561 205.11 64.637 ;
     RECT  21.096 64.291 21.69 64.669 ;
     RECT  22.788 64.637 204.894 64.669 ;
     RECT  1.152 61.963 1.17 64.733 ;
     RECT  0.108 64.165 0.162 64.939 ;
     RECT  3.6 64.049 19.098 64.975 ;
     RECT  3.528 64.975 19.098 65.011 ;
     RECT  19.836 64.205 20.106 65.011 ;
     RECT  3.528 65.011 20.106 65.129 ;
     RECT  211.608 64.987 211.626 65.129 ;
     RECT  217.548 65.245 217.566 65.281 ;
     RECT  211.464 65.281 211.482 65.357 ;
     RECT  216.396 65.281 216.414 65.399 ;
     RECT  217.548 65.281 217.854 65.399 ;
     RECT  3.6 65.129 20.106 65.443 ;
     RECT  21.096 64.669 204.894 65.443 ;
     RECT  3.6 65.443 204.894 65.453 ;
     RECT  217.764 65.399 217.854 65.705 ;
     RECT  217.764 65.705 217.782 65.939 ;
     RECT  219.42 65.227 219.438 65.939 ;
     RECT  2.415 63.347 2.697 65.995 ;
     RECT  3.6 65.453 21.186 65.995 ;
     RECT  2.415 65.995 21.186 66.119 ;
     RECT  2.415 66.119 13.878 66.173 ;
     RECT  0.108 64.939 0.558 66.353 ;
     RECT  22.212 65.453 204.894 66.479 ;
     RECT  2.415 66.173 13.77 66.56 ;
     RECT  14.616 66.119 21.186 66.785 ;
     RECT  14.724 66.785 21.186 66.797 ;
     RECT  14.724 66.797 21.114 66.989 ;
     RECT  22.284 66.479 204.894 67.243 ;
     RECT  2.415 66.56 5.49 67.289 ;
     RECT  0.108 66.353 0.126 67.325 ;
     RECT  2.415 67.289 3.006 67.325 ;
     RECT  6.552 66.56 13.77 67.339 ;
     RECT  22.212 67.243 204.894 67.373 ;
     RECT  14.724 66.989 20.718 67.421 ;
     RECT  16.812 67.421 20.718 67.559 ;
     RECT  2.415 67.325 2.697 67.579 ;
     RECT  14.724 67.421 16.002 67.667 ;
     RECT  16.848 67.559 20.718 67.865 ;
     RECT  21.672 67.627 21.726 68.045 ;
     RECT  15.984 67.667 16.002 68.135 ;
     RECT  20.196 67.865 20.718 68.141 ;
     RECT  2.304 67.579 2.697 68.215 ;
     RECT  20.196 68.141 20.682 68.237 ;
     RECT  6.552 67.339 13.95 68.251 ;
     RECT  22.536 67.373 204.894 68.299 ;
     RECT  2.304 68.215 3.222 68.341 ;
     RECT  1.152 66.571 1.17 68.377 ;
     RECT  2.304 68.341 3.258 68.377 ;
     RECT  20.484 68.237 20.682 68.405 ;
     RECT  6.408 68.251 13.95 68.485 ;
     RECT  14.724 67.667 15.21 68.485 ;
     RECT  215.532 42.179 215.55 68.485 ;
     RECT  1.152 68.377 3.258 68.521 ;
     RECT  6.408 68.485 15.21 68.521 ;
     RECT  213.015 43.331 213.297 68.521 ;
     RECT  215.46 68.485 215.766 68.521 ;
     RECT  217.404 68.341 217.422 68.521 ;
     RECT  20.664 68.405 20.682 68.525 ;
     RECT  1.152 68.521 3.33 68.573 ;
     RECT  22.212 68.299 204.894 68.639 ;
     RECT  217.296 68.521 217.422 68.639 ;
     RECT  16.848 67.865 19.422 68.675 ;
     RECT  215.46 68.521 216.126 68.731 ;
     RECT  214.848 68.731 216.126 68.755 ;
     RECT  1.152 68.573 1.17 68.791 ;
     RECT  2.304 68.573 3.33 68.791 ;
     RECT  4.068 67.289 5.49 68.791 ;
     RECT  0.54 68.791 1.17 68.909 ;
     RECT  214.848 68.755 216.342 68.909 ;
     RECT  219.42 68.539 219.438 68.909 ;
     RECT  16.848 68.675 18.897 68.917 ;
     RECT  214.848 68.909 215.802 68.945 ;
     RECT  6.408 68.521 15.426 68.957 ;
     RECT  6.552 68.957 15.426 68.989 ;
     RECT  215.388 68.945 215.766 69.005 ;
     RECT  217.404 68.639 217.422 69.053 ;
     RECT  6.552 68.989 15.462 69.061 ;
     RECT  16.488 68.917 18.897 69.061 ;
     RECT  1.152 68.909 1.17 69.215 ;
     RECT  0.108 69.211 0.126 69.485 ;
     RECT  2.304 68.791 5.49 69.871 ;
     RECT  2.304 69.871 5.778 69.989 ;
     RECT  2.304 69.989 3.15 70.069 ;
     RECT  1.728 70.069 3.15 70.253 ;
     RECT  6.552 69.061 18.897 70.339 ;
     RECT  6.552 70.339 18.954 70.375 ;
     RECT  4.068 69.989 5.778 70.405 ;
     RECT  6.552 70.375 19.026 70.411 ;
     RECT  2.304 70.253 3.15 70.529 ;
     RECT  6.552 70.411 19.53 70.601 ;
     RECT  0.108 70.555 0.126 70.637 ;
     RECT  4.068 70.405 5.814 70.645 ;
     RECT  6.552 70.601 19.206 70.645 ;
     RECT  4.068 70.645 19.206 71.069 ;
     RECT  1.152 70.891 1.17 71.179 ;
     RECT  1.152 71.179 1.206 71.185 ;
     RECT  2.304 70.529 2.862 71.185 ;
     RECT  1.152 71.185 2.862 71.491 ;
     RECT  1.152 71.491 3.042 71.549 ;
     RECT  4.068 71.069 18.897 71.753 ;
     RECT  216.684 71.725 216.702 71.761 ;
     RECT  213.015 68.521 213.75 71.851 ;
     RECT  216.684 71.761 216.954 71.851 ;
     RECT  216.684 71.851 217.386 71.879 ;
     RECT  217.368 71.879 217.386 71.951 ;
     RECT  213.015 71.851 214.362 71.959 ;
     RECT  215.388 69.005 215.406 71.959 ;
     RECT  4.068 71.753 6.93 72.031 ;
     RECT  2.415 71.549 3.042 72.149 ;
     RECT  3.96 72.031 6.93 72.149 ;
     RECT  217.512 72.031 217.53 72.149 ;
     RECT  219.42 71.803 219.438 72.149 ;
     RECT  0.108 71.851 0.126 72.221 ;
     RECT  213.015 71.959 215.406 72.221 ;
     RECT  4.068 72.149 6.93 72.419 ;
     RECT  1.152 71.549 1.206 72.523 ;
     RECT  5.364 72.419 6.93 72.523 ;
     RECT  7.776 71.753 18.897 72.523 ;
     RECT  5.364 72.523 18.897 72.689 ;
     RECT  213.015 72.221 215.226 72.689 ;
     RECT  8.928 72.689 18.897 72.805 ;
     RECT  8.928 72.805 18.99 72.869 ;
     RECT  17.316 72.869 18.99 72.959 ;
     RECT  1.152 72.523 1.35 73.075 ;
     RECT  216.72 73.075 216.738 73.111 ;
     RECT  216.72 73.111 216.954 73.201 ;
     RECT  0.54 73.075 1.35 73.229 ;
     RECT  216.72 73.201 217.386 73.229 ;
     RECT  217.368 73.229 217.386 73.301 ;
     RECT  4.068 72.419 4.446 73.309 ;
     RECT  213.015 72.689 214.902 73.309 ;
     RECT  2.415 72.149 2.862 73.381 ;
     RECT  5.364 72.689 8.154 73.381 ;
     RECT  5.256 73.381 8.154 73.409 ;
     RECT  6.48 73.409 8.154 73.483 ;
     RECT  8.928 72.869 16.326 73.483 ;
     RECT  5.256 73.409 5.706 73.499 ;
     RECT  6.48 73.483 16.326 73.499 ;
     RECT  217.512 73.381 217.53 73.499 ;
     RECT  219.42 73.099 219.438 73.499 ;
     RECT  1.152 73.229 1.35 73.507 ;
     RECT  2.268 73.381 3.186 73.507 ;
     RECT  6.624 73.499 16.326 73.517 ;
     RECT  5.364 73.499 5.562 73.535 ;
     RECT  6.768 73.517 16.326 73.535 ;
     RECT  3.96 73.309 4.446 73.769 ;
     RECT  1.152 73.507 3.186 73.805 ;
     RECT  1.332 73.805 3.186 73.841 ;
     RECT  1.332 73.841 2.697 73.853 ;
     RECT  1.332 73.853 1.35 73.913 ;
     RECT  9.036 73.535 16.29 73.913 ;
     RECT  17.316 72.959 18.897 73.921 ;
     RECT  17.316 73.921 19.458 74.039 ;
     RECT  17.316 74.039 19.026 74.183 ;
     RECT  9.036 73.913 16.038 74.309 ;
     RECT  18.324 74.183 19.026 74.309 ;
     RECT  212.436 73.309 214.902 74.317 ;
     RECT  9.036 74.309 15.822 74.453 ;
     RECT  6.768 73.535 8.262 74.461 ;
     RECT  9.036 74.453 15.678 74.461 ;
     RECT  4.068 73.769 4.446 74.551 ;
     RECT  6.768 74.461 15.678 74.579 ;
     RECT  219.42 74.395 219.438 74.579 ;
     RECT  2.304 73.853 2.697 74.587 ;
     RECT  211.932 74.317 214.902 74.635 ;
     RECT  1.728 74.587 2.697 74.731 ;
     RECT  3.708 74.551 4.446 74.731 ;
     RECT  5.364 73.535 5.382 74.731 ;
     RECT  217.404 74.695 217.422 74.731 ;
     RECT  3.708 74.731 4.482 74.759 ;
     RECT  211.608 74.635 214.902 74.759 ;
     RECT  1.728 74.731 2.934 74.849 ;
     RECT  1.728 74.849 2.697 74.861 ;
     RECT  2.304 74.861 2.697 74.885 ;
     RECT  216.936 74.731 217.422 74.885 ;
     RECT  22.896 68.639 204.894 74.929 ;
     RECT  6.84 74.579 15.678 74.957 ;
     RECT  212.076 74.759 214.902 74.993 ;
     RECT  6.84 74.957 15.426 75.119 ;
     RECT  0.108 75.163 0.126 75.227 ;
     RECT  5.364 74.731 5.454 75.259 ;
     RECT  216.18 75.271 216.198 75.397 ;
     RECT  215.856 75.397 216.198 75.433 ;
     RECT  212.76 74.993 214.902 75.461 ;
     RECT  4.068 74.759 4.482 75.505 ;
     RECT  5.364 75.259 5.778 75.505 ;
     RECT  20.772 73.885 20.79 75.505 ;
     RECT  217.404 74.885 217.422 75.505 ;
     RECT  6.84 75.119 13.59 75.541 ;
     RECT  214.74 75.461 214.902 75.541 ;
     RECT  215.82 75.433 216.198 75.541 ;
     RECT  5.364 75.505 5.922 75.659 ;
     RECT  6.696 75.541 13.59 75.659 ;
     RECT  214.74 75.541 215.082 75.659 ;
     RECT  217.404 75.505 217.854 75.659 ;
     RECT  5.364 75.659 5.778 75.695 ;
     RECT  217.404 75.659 217.422 75.695 ;
     RECT  215.82 75.541 216.342 75.767 ;
     RECT  2.34 74.885 2.697 75.835 ;
     RECT  214.74 75.659 214.902 75.917 ;
     RECT  216.324 75.767 216.342 75.929 ;
     RECT  217.08 75.811 217.098 75.929 ;
     RECT  220.212 75.691 220.23 75.929 ;
     RECT  4.068 75.505 4.554 75.931 ;
     RECT  3.672 75.931 4.59 76.009 ;
     RECT  2.304 75.835 2.697 76.081 ;
     RECT  3.528 76.009 4.59 76.081 ;
     RECT  5.364 75.695 5.382 76.081 ;
     RECT  20.196 75.505 20.79 76.081 ;
     RECT  6.912 75.659 13.59 76.109 ;
     RECT  212.76 75.461 213.966 76.199 ;
     RECT  0.108 76.045 0.126 76.459 ;
     RECT  2.304 76.081 5.382 76.505 ;
     RECT  0.108 76.459 0.558 76.577 ;
     RECT  2.415 76.505 5.382 76.621 ;
     RECT  0.108 76.577 0.126 76.829 ;
     RECT  1.296 75.499 1.314 76.847 ;
     RECT  2.415 76.621 5.526 76.925 ;
     RECT  217.224 76.891 217.386 77.009 ;
     RECT  217.368 77.009 217.386 77.045 ;
     RECT  7.128 76.109 13.59 77.089 ;
     RECT  20.196 76.081 21.366 77.089 ;
     RECT  22.5 74.929 204.894 77.089 ;
     RECT  4.104 76.925 5.526 77.251 ;
     RECT  6.84 77.089 13.59 77.251 ;
     RECT  216.468 77.161 216.486 77.279 ;
     RECT  217.512 77.161 217.53 77.279 ;
     RECT  219.42 76.987 219.438 77.279 ;
     RECT  212.76 76.199 213.57 77.371 ;
     RECT  214.74 75.917 214.758 77.371 ;
     RECT  212.76 77.371 214.758 77.395 ;
     RECT  4.104 77.251 13.59 77.459 ;
     RECT  2.415 76.925 3.258 77.467 ;
     RECT  4.104 77.459 6.246 77.549 ;
     RECT  2.304 77.467 3.258 77.701 ;
     RECT  4.104 77.549 5.922 77.701 ;
     RECT  2.304 77.701 5.922 77.741 ;
     RECT  2.304 77.741 5.742 77.855 ;
     RECT  212.76 77.395 214.938 77.947 ;
     RECT  212.4 77.947 214.938 77.971 ;
     RECT  2.415 77.855 5.742 78.461 ;
     RECT  212.4 77.971 215.01 78.467 ;
     RECT  216.684 78.475 216.702 78.511 ;
     RECT  214.992 78.467 215.01 78.539 ;
     RECT  212.4 78.467 213.93 78.629 ;
     RECT  216.612 78.511 216.702 78.629 ;
     RECT  18.324 74.309 18.897 78.859 ;
     RECT  18.324 78.859 19.458 78.899 ;
     RECT  217.548 78.511 217.566 78.899 ;
     RECT  219.42 78.235 219.438 78.899 ;
     RECT  4.5 78.461 5.742 78.907 ;
     RECT  0.108 77.665 0.126 79.015 ;
     RECT  212.4 78.629 213.75 79.015 ;
     RECT  0.108 79.015 0.162 79.133 ;
     RECT  2.415 78.461 3.69 79.177 ;
     RECT  2.268 79.177 3.69 79.205 ;
     RECT  18.324 78.899 19.17 79.229 ;
     RECT  211.824 79.015 213.75 79.313 ;
     RECT  3.564 79.205 3.69 79.321 ;
     RECT  4.5 78.907 5.886 79.321 ;
     RECT  3.564 79.321 6.03 79.439 ;
     RECT  2.268 79.205 2.697 79.469 ;
     RECT  1.152 77.131 1.17 79.475 ;
     RECT  7.128 77.459 13.59 79.511 ;
     RECT  3.672 79.439 6.03 79.619 ;
     RECT  218.844 79.531 218.862 79.619 ;
     RECT  217.512 79.591 217.53 79.709 ;
     RECT  211.824 79.313 213.714 79.861 ;
     RECT  217.404 79.825 217.422 79.861 ;
     RECT  211.752 79.861 213.714 79.979 ;
     RECT  216.936 79.861 217.422 79.979 ;
     RECT  216.936 79.979 216.954 80.015 ;
     RECT  4.824 79.619 6.03 80.059 ;
     RECT  0.108 79.133 0.126 80.107 ;
     RECT  211.824 79.979 213.714 80.123 ;
     RECT  4.824 80.059 6.174 80.131 ;
     RECT  7.128 79.511 9.882 80.131 ;
     RECT  3.672 79.619 4.014 80.221 ;
     RECT  212.76 80.123 213.714 80.249 ;
     RECT  2.415 79.469 2.697 80.293 ;
     RECT  3.564 80.221 4.014 80.293 ;
     RECT  4.824 80.131 9.882 80.357 ;
     RECT  2.415 80.293 4.014 80.401 ;
     RECT  4.824 80.357 6.246 80.401 ;
     RECT  2.415 80.401 6.246 80.779 ;
     RECT  2.304 80.779 6.246 80.825 ;
     RECT  217.692 80.761 217.71 80.905 ;
     RECT  217.26 80.905 217.71 80.941 ;
     RECT  216.468 80.941 217.854 81.059 ;
     RECT  219.42 80.827 219.438 81.059 ;
     RECT  0.108 80.107 0.162 81.095 ;
     RECT  216.828 81.059 216.846 81.095 ;
     RECT  212.76 80.249 213.678 81.115 ;
     RECT  212.76 81.115 214.398 81.175 ;
     RECT  215.46 81.115 215.478 81.175 ;
     RECT  7.02 80.357 9.882 81.239 ;
     RECT  0.144 81.095 0.162 81.365 ;
     RECT  2.304 80.825 3.114 81.509 ;
     RECT  2.304 81.509 3.078 81.599 ;
     RECT  3.852 80.825 6.246 81.635 ;
     RECT  10.656 79.511 13.59 81.739 ;
     RECT  14.436 75.119 14.85 81.739 ;
     RECT  1.152 81.451 1.17 81.985 ;
     RECT  2.304 81.599 2.754 81.985 ;
     RECT  4.068 81.635 6.246 82.021 ;
     RECT  217.188 81.985 217.206 82.021 ;
     RECT  1.152 81.985 2.754 82.109 ;
     RECT  10.656 81.739 14.85 82.139 ;
     RECT  217.188 82.021 217.386 82.139 ;
     RECT  2.304 82.109 2.754 82.175 ;
     RECT  217.368 82.139 217.386 82.175 ;
     RECT  217.512 82.291 217.53 82.409 ;
     RECT  218.844 82.123 218.862 82.409 ;
     RECT  1.152 82.109 1.17 82.411 ;
     RECT  0.54 82.411 1.17 82.445 ;
     RECT  4.068 82.021 6.39 82.453 ;
     RECT  0.54 82.445 0.558 82.517 ;
     RECT  2.415 82.175 2.754 82.561 ;
     RECT  3.708 82.453 6.39 82.561 ;
     RECT  2.415 82.561 6.39 82.679 ;
     RECT  14.436 82.139 14.85 82.687 ;
     RECT  212.76 81.175 215.694 83.021 ;
     RECT  2.415 82.679 3.33 83.083 ;
     RECT  214.776 83.021 215.694 83.371 ;
     RECT  216.72 83.335 216.738 83.371 ;
     RECT  214.776 83.371 217.422 83.489 ;
     RECT  216.72 83.489 217.422 83.525 ;
     RECT  4.068 82.679 6.39 83.569 ;
     RECT  7.128 81.239 9.882 83.569 ;
     RECT  216.72 83.525 217.206 83.759 ;
     RECT  218.844 83.419 218.862 83.759 ;
     RECT  205.956 83.659 205.974 83.789 ;
     RECT  214.776 83.489 215.766 83.789 ;
     RECT  214.956 83.789 215.766 83.795 ;
     RECT  212.76 83.021 213.966 83.803 ;
     RECT  18.324 79.229 18.897 84.001 ;
     RECT  14.436 82.687 14.922 84.037 ;
     RECT  2.304 83.083 3.33 84.065 ;
     RECT  4.068 83.569 9.882 84.137 ;
     RECT  14.436 84.037 14.958 84.137 ;
     RECT  2.415 84.065 3.33 84.181 ;
     RECT  4.068 84.137 6.174 84.181 ;
     RECT  18.324 84.001 19.458 84.221 ;
     RECT  20.196 77.089 204.894 84.271 ;
     RECT  14.436 84.137 14.922 84.371 ;
     RECT  211.032 84.523 211.05 84.569 ;
     RECT  212.544 83.803 213.966 84.577 ;
     RECT  2.415 84.181 6.174 84.641 ;
     RECT  211.932 84.577 213.966 84.721 ;
     RECT  216.936 84.685 216.954 84.721 ;
     RECT  216.936 84.721 217.242 84.839 ;
     RECT  219.42 84.715 219.438 84.839 ;
     RECT  0.108 83.755 0.126 84.875 ;
     RECT  211.464 84.721 213.966 84.875 ;
     RECT  7.2 84.137 9.882 84.955 ;
     RECT  217.224 84.839 217.242 84.955 ;
     RECT  211.464 84.875 213.858 85.019 ;
     RECT  2.415 84.641 5.814 85.051 ;
     RECT  217.224 84.955 217.422 85.109 ;
     RECT  211.5 85.019 213.858 85.145 ;
     RECT  211.5 85.145 211.518 85.181 ;
     RECT  212.436 85.145 213.858 85.181 ;
     RECT  2.376 85.051 5.814 85.387 ;
     RECT  6.552 84.955 9.882 85.415 ;
     RECT  214.956 83.795 214.974 85.459 ;
     RECT  214.884 85.459 214.974 85.531 ;
     RECT  215.748 83.795 215.766 85.531 ;
     RECT  212.76 85.181 213.858 85.657 ;
     RECT  214.884 85.531 215.766 85.657 ;
     RECT  212.76 85.657 215.766 85.765 ;
     RECT  6.84 85.415 9.882 85.793 ;
     RECT  212.76 85.765 216.054 85.801 ;
     RECT  6.912 85.793 9.882 85.919 ;
     RECT  212.76 85.801 216.234 86.027 ;
     RECT  214.812 86.027 216.234 86.035 ;
     RECT  218.304 85.891 218.322 86.045 ;
     RECT  2.304 85.387 5.814 86.189 ;
     RECT  0.108 86.059 0.126 86.225 ;
     RECT  214.812 86.035 216.99 86.225 ;
     RECT  216.972 86.225 216.99 86.341 ;
     RECT  7.2 85.919 9.882 86.639 ;
     RECT  19.836 84.271 204.894 86.729 ;
     RECT  1.152 84.091 1.17 86.731 ;
     RECT  2.304 86.189 2.898 86.765 ;
     RECT  214.812 86.225 215.766 86.801 ;
     RECT  212.76 86.027 213.894 86.836 ;
     RECT  0.54 86.731 1.17 86.837 ;
     RECT  7.2 86.639 9.522 86.881 ;
     RECT  212.724 86.836 213.894 86.881 ;
     RECT  214.812 86.801 215.154 86.881 ;
     RECT  3.888 86.189 5.814 86.923 ;
     RECT  1.152 86.837 1.17 87.019 ;
     RECT  212.724 86.881 215.154 87.043 ;
     RECT  212.616 87.043 215.154 87.107 ;
     RECT  216.972 86.341 217.314 87.115 ;
     RECT  210.348 86.881 210.366 87.143 ;
     RECT  212.616 87.107 214.938 87.143 ;
     RECT  216.864 87.115 217.314 87.151 ;
     RECT  3.78 86.923 5.814 87.211 ;
     RECT  6.84 86.881 9.522 87.211 ;
     RECT  216.864 87.151 217.422 87.269 ;
     RECT  2.415 86.765 2.898 87.421 ;
     RECT  3.78 87.211 9.522 87.421 ;
     RECT  219.42 87.259 219.438 87.539 ;
     RECT  217.404 87.269 217.422 87.575 ;
     RECT  1.152 87.019 1.206 87.655 ;
     RECT  212.724 87.143 214.938 87.719 ;
     RECT  0.54 87.655 1.206 87.725 ;
     RECT  10.656 82.139 13.59 88.075 ;
     RECT  14.436 84.371 14.85 88.171 ;
     RECT  212.724 87.719 214.902 88.195 ;
     RECT  1.152 87.725 1.206 88.223 ;
     RECT  10.656 88.075 13.698 88.231 ;
     RECT  14.436 88.171 14.886 88.231 ;
     RECT  18.324 84.221 18.897 88.231 ;
     RECT  10.656 88.231 14.886 88.349 ;
     RECT  18.324 88.231 18.99 88.355 ;
     RECT  212.58 88.195 214.902 88.397 ;
     RECT  17.316 74.183 17.334 88.501 ;
     RECT  217.548 88.465 217.566 88.501 ;
     RECT  2.415 87.421 9.522 88.655 ;
     RECT  16.776 88.501 17.334 88.655 ;
     RECT  17.316 88.655 17.334 88.861 ;
     RECT  6.624 88.655 9.522 88.889 ;
     RECT  10.656 88.349 13.59 88.891 ;
     RECT  217.548 88.501 217.854 88.925 ;
     RECT  6.732 88.889 9.522 88.933 ;
     RECT  17.316 88.861 17.406 88.933 ;
     RECT  18.324 88.355 18.897 88.933 ;
     RECT  17.316 88.933 18.897 88.973 ;
     RECT  2.415 88.655 5.814 89.035 ;
     RECT  220.212 88.555 220.23 89.159 ;
     RECT  212.724 88.397 214.902 89.179 ;
     RECT  212.4 89.179 214.902 89.231 ;
     RECT  212.616 89.231 214.902 89.429 ;
     RECT  10.512 88.891 13.59 89.671 ;
     RECT  14.436 88.349 14.85 89.671 ;
     RECT  6.732 88.933 9.594 89.707 ;
     RECT  10.512 89.671 14.85 89.707 ;
     RECT  216.036 88.771 216.054 89.779 ;
     RECT  2.304 89.035 5.814 89.807 ;
     RECT  216.036 89.779 216.378 89.815 ;
     RECT  217.26 89.041 217.278 89.815 ;
     RECT  2.415 89.807 5.814 89.851 ;
     RECT  6.732 89.707 14.85 89.851 ;
     RECT  216.036 89.815 217.278 89.851 ;
     RECT  214.236 89.429 214.902 89.879 ;
     RECT  2.415 89.851 14.85 89.969 ;
     RECT  215.892 89.851 217.422 89.969 ;
     RECT  212.616 89.429 213.426 89.977 ;
     RECT  6.768 89.969 14.85 90.005 ;
     RECT  217.404 89.969 217.422 90.005 ;
     RECT  211.5 89.977 211.518 90.043 ;
     RECT  212.436 89.977 213.426 90.043 ;
     RECT  211.5 90.043 213.426 90.077 ;
     RECT  217.512 90.121 217.53 90.239 ;
     RECT  219.42 89.851 219.438 90.239 ;
     RECT  211.896 90.077 213.426 90.283 ;
     RECT  214.236 89.879 214.254 90.283 ;
     RECT  14.364 90.005 14.85 90.347 ;
     RECT  18.615 88.973 18.897 90.391 ;
     RECT  18.615 90.391 19.098 90.481 ;
     RECT  211.896 90.283 214.254 90.509 ;
     RECT  212.58 90.509 214.254 90.545 ;
     RECT  212.652 90.545 214.254 90.581 ;
     RECT  213.015 90.581 214.254 90.625 ;
     RECT  215.424 90.013 215.442 90.625 ;
     RECT  0.108 88.027 0.126 90.895 ;
     RECT  18.615 90.481 19.242 90.907 ;
     RECT  20.196 86.729 204.894 90.907 ;
     RECT  215.064 90.625 215.442 90.931 ;
     RECT  217.548 90.895 217.566 90.931 ;
     RECT  6.768 90.005 13.59 90.959 ;
     RECT  213.015 90.625 214.326 91.021 ;
     RECT  215.064 90.931 216.162 91.021 ;
     RECT  0.108 90.895 0.162 91.037 ;
     RECT  18.615 90.907 204.894 91.049 ;
     RECT  217.548 90.931 217.674 91.049 ;
     RECT  213.015 91.021 216.162 91.057 ;
     RECT  219.42 91.147 219.438 91.193 ;
     RECT  213.015 91.057 216.342 91.201 ;
     RECT  217.548 91.049 217.566 91.201 ;
     RECT  1.152 88.223 1.17 91.355 ;
     RECT  213.015 91.201 217.566 91.355 ;
     RECT  2.415 89.969 5.886 91.391 ;
     RECT  14.616 90.347 14.85 91.435 ;
     RECT  15.66 86.701 15.678 91.435 ;
     RECT  16.56 91.195 16.578 91.435 ;
     RECT  14.472 91.435 14.85 91.561 ;
     RECT  2.415 91.391 5.814 91.589 ;
     RECT  15.66 91.435 16.578 91.589 ;
     RECT  20.196 91.049 204.894 91.589 ;
     RECT  213.015 91.355 216.054 91.589 ;
     RECT  216.936 91.355 217.566 91.589 ;
     RECT  6.768 90.959 13.497 91.741 ;
     RECT  14.256 91.561 14.85 91.741 ;
     RECT  18.615 91.049 19.35 91.867 ;
     RECT  20.196 91.589 203.814 91.867 ;
     RECT  2.415 91.589 3.366 92.011 ;
     RECT  6.768 91.741 14.85 92.011 ;
     RECT  15.66 91.589 15.678 92.011 ;
     RECT  6.768 92.011 15.678 92.129 ;
     RECT  213.015 91.589 215.334 92.129 ;
     RECT  6.768 92.129 13.554 92.165 ;
     RECT  14.4 92.129 15.678 92.165 ;
     RECT  0.108 91.037 0.126 92.245 ;
     RECT  14.868 92.165 15.678 92.309 ;
     RECT  216.936 91.589 217.386 92.399 ;
     RECT  4.14 91.589 5.814 92.407 ;
     RECT  6.768 92.165 13.497 92.407 ;
     RECT  217.368 92.399 217.386 92.435 ;
     RECT  2.304 92.011 3.366 92.551 ;
     RECT  4.14 92.407 13.497 92.551 ;
     RECT  213.015 92.129 214.974 92.551 ;
     RECT  2.304 92.551 13.497 92.669 ;
     RECT  204.66 91.589 204.894 92.669 ;
     RECT  212.616 92.551 214.974 92.669 ;
     RECT  217.512 92.551 217.53 92.669 ;
     RECT  219.42 92.443 219.438 92.669 ;
     RECT  2.304 92.669 3.366 92.705 ;
     RECT  18.615 91.867 203.814 92.785 ;
     RECT  204.66 92.669 204.75 92.785 ;
     RECT  212.616 92.669 214.902 92.939 ;
     RECT  212.616 92.939 213.498 92.971 ;
     RECT  214.236 92.939 214.902 93.047 ;
     RECT  14.832 92.923 14.85 93.053 ;
     RECT  2.34 92.705 3.366 93.083 ;
     RECT  212.364 92.971 213.498 93.083 ;
     RECT  214.236 93.047 214.326 93.119 ;
     RECT  212.688 93.083 213.498 93.623 ;
     RECT  18.615 92.785 204.75 93.749 ;
     RECT  216.36 93.451 216.378 93.749 ;
     RECT  0.108 92.245 0.162 94.013 ;
     RECT  213.015 93.623 213.498 94.055 ;
     RECT  217.656 93.901 217.674 94.055 ;
     RECT  4.14 92.669 13.497 94.109 ;
     RECT  220.212 93.739 220.23 94.199 ;
     RECT  217.764 94.171 217.962 94.289 ;
     RECT  217.764 94.289 217.782 94.361 ;
     RECT  0.108 94.013 0.126 94.595 ;
     RECT  2.415 93.083 3.366 94.909 ;
     RECT  4.14 94.109 5.814 94.909 ;
     RECT  2.415 94.909 5.814 94.939 ;
     RECT  18.615 93.749 204.102 94.981 ;
     RECT  212.04 95.071 212.058 95.131 ;
     RECT  2.304 94.939 5.814 95.135 ;
     RECT  2.304 95.135 4.158 95.143 ;
     RECT  18.615 94.981 204.534 95.171 ;
     RECT  211.428 95.131 212.058 95.171 ;
     RECT  211.968 95.171 212.058 95.179 ;
     RECT  211.968 95.179 212.094 95.215 ;
     RECT  213.015 94.055 213.39 95.215 ;
     RECT  4.932 95.135 5.814 95.251 ;
     RECT  6.588 94.109 13.497 95.251 ;
     RECT  216.684 95.071 217.386 95.251 ;
     RECT  2.268 95.143 4.158 95.279 ;
     RECT  2.268 95.279 2.79 95.309 ;
     RECT  211.968 95.215 213.39 95.341 ;
     RECT  211.968 95.341 213.462 95.369 ;
     RECT  216.684 95.251 217.854 95.369 ;
     RECT  217.26 95.369 217.854 95.405 ;
     RECT  212.04 95.369 213.462 95.521 ;
     RECT  211.068 95.521 211.086 95.597 ;
     RECT  1.152 93.307 1.17 95.611 ;
     RECT  217.26 95.405 217.278 95.639 ;
     RECT  220.212 95.035 220.23 95.639 ;
     RECT  2.304 95.309 2.79 95.675 ;
     RECT  212.04 95.521 213.498 95.707 ;
     RECT  214.236 93.119 214.254 95.707 ;
     RECT  4.932 95.251 13.497 95.741 ;
     RECT  0.54 95.611 1.17 95.747 ;
     RECT  212.04 95.707 214.254 95.783 ;
     RECT  3.6 95.279 4.158 95.909 ;
     RECT  5.04 95.741 13.497 95.909 ;
     RECT  18.615 95.171 203.994 95.953 ;
     RECT  1.152 95.747 1.17 96.053 ;
     RECT  212.04 95.783 212.202 96.053 ;
     RECT  215.46 95.881 215.586 96.061 ;
     RECT  215.46 96.061 215.874 96.179 ;
     RECT  213.015 95.783 214.254 96.187 ;
     RECT  18.615 95.953 204.606 96.251 ;
     RECT  212.04 96.053 212.094 96.251 ;
     RECT  213.015 96.187 214.362 96.283 ;
     RECT  215.46 96.179 215.586 96.286 ;
     RECT  212.04 96.251 212.058 96.317 ;
     RECT  213.015 96.283 214.578 96.331 ;
     RECT  215.424 96.286 215.586 96.331 ;
     RECT  218.88 96.151 218.898 96.365 ;
     RECT  217.512 96.331 217.53 96.493 ;
     RECT  18.615 96.251 203.886 96.521 ;
     RECT  213.015 96.331 215.586 96.521 ;
     RECT  217.368 96.493 217.53 96.565 ;
     RECT  217.296 96.565 217.818 96.601 ;
     RECT  2.415 95.675 2.79 96.619 ;
     RECT  213.015 96.521 215.514 96.629 ;
     RECT  18.615 96.521 203.67 96.719 ;
     RECT  215.424 96.629 215.514 96.755 ;
     RECT  217.296 96.601 218.034 96.791 ;
     RECT  2.304 96.619 2.79 96.799 ;
     RECT  3.852 95.909 4.158 96.799 ;
     RECT  2.304 96.799 4.158 96.835 ;
     RECT  1.728 96.835 4.158 96.871 ;
     RECT  5.04 95.909 5.814 96.871 ;
     RECT  1.728 96.871 5.814 96.955 ;
     RECT  6.588 95.909 13.497 96.955 ;
     RECT  1.728 96.955 13.497 96.989 ;
     RECT  3.744 96.989 13.497 97.025 ;
     RECT  3.744 97.025 5.598 97.259 ;
     RECT  0.108 95.944 0.126 97.291 ;
     RECT  18.615 96.719 203.562 97.295 ;
     RECT  217.296 96.791 217.386 97.375 ;
     RECT  2.304 96.989 2.97 97.403 ;
     RECT  213.015 96.629 214.254 97.411 ;
     RECT  216.936 97.375 217.386 97.529 ;
     RECT  0.108 97.291 0.162 97.565 ;
     RECT  217.368 97.529 217.386 97.565 ;
     RECT  213.015 97.411 214.29 97.645 ;
     RECT  4.068 97.259 5.598 97.661 ;
     RECT  0.144 97.565 0.162 97.673 ;
     RECT  18.615 97.295 203.49 97.799 ;
     RECT  215.928 97.681 215.946 97.799 ;
     RECT  217.512 97.681 217.53 97.799 ;
     RECT  219.42 97.579 219.438 97.799 ;
     RECT  213.015 97.645 214.758 97.943 ;
     RECT  18.615 97.799 203.238 98.069 ;
     RECT  18.615 98.069 203.166 98.147 ;
     RECT  18.615 98.147 203.094 98.213 ;
     RECT  2.415 97.403 2.97 98.221 ;
     RECT  6.588 97.025 13.497 98.221 ;
     RECT  2.415 98.221 3.258 98.251 ;
     RECT  2.304 98.251 3.258 98.491 ;
     RECT  4.068 97.661 4.086 98.491 ;
     RECT  212.148 98.443 212.166 98.491 ;
     RECT  18.615 98.213 202.878 98.55 ;
     RECT  5.04 97.661 5.382 98.581 ;
     RECT  6.228 98.221 13.497 98.581 ;
     RECT  211.752 98.491 212.166 98.621 ;
     RECT  17.316 88.973 17.334 98.635 ;
     RECT  18.615 98.55 23.13 98.635 ;
     RECT  213.015 97.943 214.254 98.635 ;
     RECT  2.304 98.491 4.086 98.645 ;
     RECT  2.415 98.645 4.086 98.725 ;
     RECT  5.04 98.581 13.497 98.765 ;
     RECT  26.748 98.55 26.766 98.834 ;
     RECT  2.415 98.725 4.266 98.879 ;
     RECT  17.316 98.635 23.13 98.879 ;
     RECT  197.244 98.55 202.878 99.023 ;
     RECT  219.42 98.875 219.438 99.149 ;
     RECT  0.108 98.455 0.126 99.185 ;
     RECT  3.852 98.879 4.266 99.185 ;
     RECT  217.224 99.031 217.242 99.185 ;
     RECT  5.112 98.765 13.497 99.197 ;
     RECT  17.316 98.879 17.586 99.197 ;
     RECT  69.372 98.55 69.534 99.463 ;
     RECT  72.396 98.55 72.414 99.499 ;
     RECT  14.832 99.403 14.85 99.533 ;
     RECT  212.436 98.635 214.254 99.535 ;
     RECT  65.844 98.55 65.862 99.571 ;
     RECT  84.852 99.499 84.87 99.571 ;
     RECT  1.152 97.915 1.17 99.595 ;
     RECT  2.415 98.879 2.697 99.595 ;
     RECT  18.615 98.879 23.13 99.599 ;
     RECT  88.632 98.55 88.65 99.616 ;
     RECT  97.488 98.55 97.506 99.616 ;
     RECT  1.152 99.595 2.697 99.661 ;
     RECT  3.852 99.185 3.87 99.661 ;
     RECT  68.364 99.403 68.382 99.841 ;
     RECT  45.972 99.391 45.99 99.967 ;
     RECT  106.272 98.55 106.29 99.967 ;
     RECT  69.372 99.463 70.11 99.979 ;
     RECT  0.108 99.931 0.126 99.995 ;
     RECT  68.184 99.841 68.382 100.003 ;
     RECT  69.372 99.979 70.722 100.003 ;
     RECT  71.964 99.499 72.414 100.039 ;
     RECT  15.66 92.309 15.678 100.067 ;
     RECT  5.184 99.197 13.497 100.075 ;
     RECT  73.728 98.55 73.746 100.075 ;
     RECT  79.2 98.55 80.01 100.111 ;
     RECT  80.892 98.55 80.91 100.111 ;
     RECT  217.548 100.075 217.566 100.111 ;
     RECT  88.632 99.616 88.938 100.123 ;
     RECT  65.844 99.571 66.402 100.156 ;
     RECT  97.488 99.616 97.758 100.156 ;
     RECT  100.224 98.55 100.242 100.156 ;
     RECT  99.684 100.156 100.242 100.171 ;
     RECT  1.152 99.661 3.87 100.201 ;
     RECT  4.68 100.075 13.497 100.201 ;
     RECT  65.196 100.156 66.402 100.201 ;
     RECT  1.152 100.201 13.497 100.229 ;
     RECT  217.548 100.111 217.854 100.229 ;
     RECT  99.432 100.171 100.242 100.237 ;
     RECT  4.428 100.229 5.634 100.253 ;
     RECT  55.044 99.697 55.062 100.267 ;
     RECT  45.288 99.967 45.99 100.273 ;
     RECT  88.632 100.123 89.478 100.273 ;
     RECT  4.5 100.253 5.382 100.301 ;
     RECT  71.892 100.039 72.414 100.315 ;
     RECT  79.2 100.111 80.91 100.363 ;
     RECT  83.736 100.027 83.754 100.363 ;
     RECT  20.196 99.599 23.13 100.373 ;
     RECT  81.972 99.535 81.99 100.381 ;
     RECT  106.272 99.967 106.542 100.411 ;
     RECT  45.288 100.273 46.314 100.426 ;
     RECT  106.02 100.411 106.542 100.426 ;
     RECT  109.296 100.273 109.314 100.426 ;
     RECT  30.204 99.931 30.222 100.471 ;
     RECT  43.164 100.426 43.254 100.471 ;
     RECT  84.852 99.571 85.122 100.471 ;
     RECT  85.932 98.55 85.95 100.471 ;
     RECT  94.536 99.661 94.554 100.471 ;
     RECT  106.02 100.426 106.614 100.471 ;
     RECT  29.916 100.471 30.222 100.499 ;
     RECT  88.632 100.273 90.09 100.499 ;
     RECT  212.148 99.535 214.254 100.499 ;
     RECT  34.956 100.471 34.974 100.507 ;
     RECT  68.184 100.003 70.722 100.507 ;
     RECT  71.892 100.315 72.63 100.507 ;
     RECT  81.972 100.381 82.278 100.507 ;
     RECT  83.232 100.363 83.754 100.507 ;
     RECT  86.904 100.075 86.922 100.507 ;
     RECT  97.488 100.156 98.046 100.507 ;
     RECT  108.468 100.309 108.486 100.507 ;
     RECT  217.764 100.229 217.854 100.535 ;
     RECT  33.984 100.309 34.002 100.543 ;
     RECT  36.468 100.345 36.486 100.543 ;
     RECT  37.62 99.733 37.638 100.543 ;
     RECT  38.772 100.471 38.79 100.543 ;
     RECT  55.044 100.267 55.278 100.543 ;
     RECT  77.688 99.535 77.706 100.543 ;
     RECT  78.552 100.363 80.91 100.543 ;
     RECT  97.488 100.507 98.622 100.543 ;
     RECT  108.144 100.507 108.486 100.543 ;
     RECT  109.296 100.426 109.494 100.543 ;
     RECT  42.768 100.471 43.254 100.555 ;
     RECT  24.516 100.471 24.534 100.579 ;
     RECT  26.784 100.471 26.802 100.579 ;
     RECT  29.916 100.499 29.934 100.579 ;
     RECT  38.664 100.543 38.79 100.579 ;
     RECT  40.716 100.471 40.734 100.579 ;
     RECT  91.188 100.201 91.206 100.579 ;
     RECT  84.852 100.471 85.95 100.603 ;
     RECT  86.724 100.507 86.922 100.603 ;
     RECT  91.188 100.579 91.854 100.603 ;
     RECT  93.996 100.471 94.554 100.603 ;
     RECT  97.488 100.543 98.694 100.603 ;
     RECT  99.432 100.237 100.89 100.603 ;
     RECT  1.152 100.229 3.402 100.607 ;
     RECT  40.644 100.579 40.734 100.607 ;
     RECT  42.768 100.555 43.614 100.607 ;
     RECT  93.996 100.603 94.59 100.615 ;
     RECT  24.444 100.579 24.534 100.643 ;
     RECT  211.716 100.603 211.734 100.643 ;
     RECT  24.444 100.643 24.462 100.645 ;
     RECT  29.844 100.579 29.934 100.645 ;
     RECT  40.644 100.607 40.662 100.645 ;
     RECT  50.796 99.427 50.814 100.645 ;
     RECT  56.088 99.661 56.106 100.645 ;
     RECT  24.372 100.645 24.462 100.651 ;
     RECT  29.772 100.645 29.934 100.651 ;
     RECT  34.956 100.507 35.658 100.651 ;
     RECT  39.78 99.886 39.798 100.651 ;
     RECT  40.572 100.645 40.662 100.651 ;
     RECT  48.6 100.273 48.618 100.651 ;
     RECT  62.172 100.645 62.19 100.651 ;
     RECT  64.944 100.201 66.402 100.651 ;
     RECT  67.212 100.555 67.23 100.651 ;
     RECT  24.12 100.651 24.462 100.679 ;
     RECT  29.52 100.651 29.934 100.679 ;
     RECT  39.78 100.651 40.662 100.679 ;
     RECT  42.912 100.607 43.614 100.679 ;
     RECT  24.12 100.679 24.39 100.685 ;
     RECT  29.52 100.679 29.79 100.685 ;
     RECT  39.78 100.679 40.59 100.685 ;
     RECT  50.796 100.645 51.39 100.685 ;
     RECT  56.088 100.645 56.79 100.685 ;
     RECT  64.944 100.651 67.302 100.693 ;
     RECT  68.184 100.507 70.794 100.693 ;
     RECT  121.176 100.471 121.194 100.693 ;
     RECT  197.604 99.023 202.878 100.693 ;
     RECT  84.852 100.603 86.922 100.733 ;
     RECT  36.468 100.543 37.638 100.741 ;
     RECT  38.664 100.579 38.934 100.741 ;
     RECT  45.288 100.426 46.386 100.741 ;
     RECT  108.144 100.543 109.494 100.741 ;
     RECT  136.152 100.555 136.17 100.741 ;
     RECT  33.3 100.543 34.002 100.769 ;
     RECT  34.92 100.651 35.658 100.769 ;
     RECT  36.468 100.741 38.934 100.769 ;
     RECT  43.164 100.679 43.614 100.769 ;
     RECT  48.348 100.651 48.618 100.769 ;
     RECT  54.792 100.543 55.278 100.769 ;
     RECT  58.572 98.55 58.842 100.769 ;
     RECT  64.944 100.693 70.794 100.769 ;
     RECT  75.78 98.55 75.798 100.769 ;
     RECT  77.688 100.543 80.91 100.769 ;
     RECT  88.632 100.499 89.478 100.769 ;
     RECT  90.468 100.603 91.854 100.769 ;
     RECT  92.952 100.579 92.97 100.769 ;
     RECT  93.996 100.615 95.13 100.769 ;
     RECT  97.488 100.603 100.89 100.769 ;
     RECT  104.076 100.699 104.094 100.769 ;
     RECT  112.752 98.55 112.77 100.769 ;
     RECT  113.616 100.507 113.634 100.769 ;
     RECT  119.952 99.697 119.97 100.769 ;
     RECT  136.152 100.741 136.494 100.769 ;
     RECT  167.58 100.459 167.598 100.769 ;
     RECT  168.66 100.603 168.678 100.769 ;
     RECT  212.652 100.499 214.254 100.769 ;
     RECT  217.764 100.535 217.782 100.769 ;
     RECT  219.42 100.171 219.438 100.769 ;
     RECT  88.632 100.769 89.19 100.777 ;
     RECT  185.22 99.931 185.238 100.777 ;
     RECT  136.476 100.769 136.494 100.781 ;
     RECT  184.752 100.777 185.238 100.781 ;
     RECT  37.62 100.769 37.962 100.805 ;
     RECT  39.78 100.685 40.497 100.805 ;
     RECT  45.288 100.741 46.458 100.805 ;
     RECT  48.348 100.769 48.366 100.805 ;
     RECT  50.796 100.685 51.297 100.805 ;
     RECT  54.792 100.769 55.062 100.805 ;
     RECT  56.088 100.685 56.697 100.805 ;
     RECT  58.572 100.769 58.662 100.805 ;
     RECT  64.944 100.769 65.79 100.805 ;
     RECT  66.744 100.769 70.794 100.805 ;
     RECT  77.688 100.769 80.658 100.805 ;
     RECT  97.488 100.769 100.53 100.805 ;
     RECT  106.02 100.471 106.686 100.805 ;
     RECT  108.144 100.741 109.71 100.805 ;
     RECT  31.356 100.507 31.914 100.813 ;
     RECT  144.576 100.555 144.594 100.813 ;
     RECT  144.324 100.813 144.594 100.829 ;
     RECT  184.752 100.781 184.77 100.829 ;
     RECT  144.324 100.829 144.342 100.84 ;
     RECT  37.692 100.805 37.962 100.841 ;
     RECT  54.792 100.805 54.81 100.841 ;
     RECT  58.644 100.805 58.662 100.841 ;
     RECT  66.744 100.805 69.39 100.841 ;
     RECT  106.344 100.805 106.686 100.841 ;
     RECT  110.607 100.693 110.697 100.843 ;
     RECT  26.784 100.579 26.874 100.849 ;
     RECT  27.828 100.741 27.846 100.849 ;
     RECT  71.892 100.507 72.99 100.849 ;
     RECT  73.728 100.075 74.61 100.849 ;
     RECT  121.176 100.693 121.497 100.849 ;
     RECT  26.784 100.849 27.846 100.877 ;
     RECT  37.692 100.841 37.89 100.877 ;
     RECT  38.772 100.769 38.934 100.877 ;
     RECT  40.032 100.805 40.497 100.877 ;
     RECT  106.344 100.841 106.614 100.877 ;
     RECT  93.024 100.777 93.042 100.921 ;
     RECT  213.015 100.769 214.254 100.921 ;
     RECT  103.752 100.777 103.806 100.925 ;
     RECT  111.852 100.747 111.87 100.939 ;
     RECT  24.12 100.685 24.297 100.963 ;
     RECT  29.52 100.685 29.697 100.963 ;
     RECT  34.92 100.769 35.097 100.963 ;
     RECT  61.92 100.651 62.19 100.963 ;
     RECT  105.207 100.693 105.297 100.963 ;
     RECT  108.756 100.805 109.71 100.963 ;
     RECT  110.607 100.843 110.718 100.963 ;
     RECT  116.007 100.693 116.097 100.963 ;
     RECT  126.807 100.693 126.897 100.963 ;
     RECT  132.207 100.693 132.297 100.963 ;
     RECT  137.607 100.693 137.697 100.963 ;
     RECT  143.007 100.693 143.097 100.963 ;
     RECT  148.407 100.693 148.497 100.963 ;
     RECT  153.807 100.693 153.897 100.963 ;
     RECT  159.207 100.693 159.297 100.963 ;
     RECT  164.607 100.693 164.697 100.963 ;
     RECT  170.007 100.693 170.097 100.963 ;
     RECT  175.407 100.693 175.497 100.963 ;
     RECT  180.807 100.693 180.897 100.963 ;
     RECT  186.207 100.693 186.297 100.963 ;
     RECT  191.607 100.693 191.697 100.963 ;
     RECT  197.007 100.693 202.878 100.963 ;
     RECT  86.868 100.733 86.922 101.011 ;
     RECT  33.3 100.769 33.642 101.035 ;
     RECT  65.772 100.805 65.79 101.039 ;
     RECT  67.215 100.841 69.39 101.039 ;
     RECT  70.56 100.805 70.794 101.039 ;
     RECT  77.94 100.805 79.794 101.039 ;
     RECT  98.028 100.805 100.53 101.039 ;
     RECT  106.344 100.877 106.542 101.039 ;
     RECT  215.856 100.885 215.874 101.047 ;
     RECT  26.784 100.877 27.522 101.069 ;
     RECT  18.615 99.599 19.422 101.075 ;
     RECT  31.032 100.813 31.914 101.075 ;
     RECT  43.164 100.769 43.47 101.075 ;
     RECT  84.852 100.733 85.95 101.075 ;
     RECT  2.415 100.607 3.402 101.119 ;
     RECT  213.015 100.921 214.29 101.119 ;
     RECT  215.532 101.047 215.874 101.119 ;
     RECT  108.756 100.963 110.718 101.131 ;
     RECT  26.784 101.069 27.45 101.147 ;
     RECT  31.356 101.075 31.914 101.147 ;
     RECT  32.904 101.035 33.642 101.147 ;
     RECT  38.844 100.877 38.934 101.147 ;
     RECT  18.615 101.075 19.35 101.183 ;
     RECT  86.868 101.011 87.21 101.183 ;
     RECT  103.788 100.925 103.806 101.183 ;
     RECT  168.732 100.849 168.75 101.183 ;
     RECT  5.184 100.301 5.382 101.191 ;
     RECT  61.815 100.963 62.19 101.191 ;
     RECT  71.892 100.849 74.61 101.191 ;
     RECT  105.015 100.963 105.297 101.191 ;
     RECT  111.852 100.939 112.194 101.191 ;
     RECT  144.252 100.84 144.342 101.191 ;
     RECT  31.428 101.147 31.914 101.219 ;
     RECT  196.815 100.963 202.878 101.219 ;
     RECT  115.815 100.963 116.097 101.227 ;
     RECT  120.924 100.849 121.497 101.227 ;
     RECT  126.615 100.963 126.897 101.227 ;
     RECT  132.015 100.963 132.297 101.227 ;
     RECT  137.415 100.963 137.697 101.227 ;
     RECT  142.815 100.963 143.097 101.227 ;
     RECT  148.215 100.963 148.497 101.227 ;
     RECT  153.615 100.963 153.897 101.227 ;
     RECT  159.015 100.963 159.297 101.227 ;
     RECT  164.415 100.963 164.697 101.227 ;
     RECT  169.815 100.963 170.097 101.227 ;
     RECT  175.215 100.963 175.497 101.227 ;
     RECT  180.615 100.963 180.897 101.227 ;
     RECT  186.015 100.963 186.297 101.227 ;
     RECT  191.415 100.963 191.697 101.227 ;
     RECT  32.904 101.147 33.57 101.261 ;
     RECT  88.38 100.777 89.19 101.261 ;
     RECT  105.015 101.191 105.39 101.261 ;
     RECT  108.756 101.131 110.79 101.261 ;
     RECT  194.364 101.131 194.382 101.261 ;
     RECT  5.184 101.191 5.526 101.275 ;
     RECT  4.572 101.275 5.526 101.309 ;
     RECT  31.428 101.219 31.446 101.309 ;
     RECT  38.844 101.147 38.862 101.309 ;
     RECT  43.308 101.075 43.47 101.309 ;
     RECT  61.815 101.191 62.766 101.309 ;
     RECT  106.344 101.039 106.47 101.309 ;
     RECT  81.972 100.507 83.862 101.317 ;
     RECT  4.572 101.309 5.202 101.345 ;
     RECT  20.196 100.373 22.986 101.345 ;
     RECT  81.72 101.317 83.862 101.345 ;
     RECT  213.015 101.119 215.874 101.345 ;
     RECT  84.852 101.075 85.302 101.357 ;
     RECT  108.756 101.261 110.697 101.357 ;
     RECT  114.588 101.227 114.606 101.357 ;
     RECT  115.815 101.227 116.19 101.357 ;
     RECT  120.924 101.227 121.59 101.357 ;
     RECT  122.544 101.227 122.562 101.357 ;
     RECT  126.615 101.227 126.99 101.357 ;
     RECT  130.536 101.227 130.554 101.357 ;
     RECT  132.015 101.227 132.39 101.357 ;
     RECT  134.532 100.411 134.55 101.357 ;
     RECT  137.415 101.227 137.79 101.357 ;
     RECT  138.528 101.227 138.546 101.357 ;
     RECT  142.815 101.227 143.19 101.357 ;
     RECT  146.484 101.227 146.502 101.357 ;
     RECT  148.215 101.227 148.59 101.357 ;
     RECT  150.48 101.227 150.498 101.357 ;
     RECT  153.615 101.227 154.494 101.357 ;
     RECT  159.015 101.227 159.39 101.357 ;
     RECT  162.468 101.227 162.486 101.357 ;
     RECT  164.415 101.227 164.79 101.357 ;
     RECT  166.464 101.227 166.482 101.357 ;
     RECT  169.815 101.227 170.19 101.357 ;
     RECT  174.42 101.227 174.438 101.357 ;
     RECT  175.215 101.227 175.59 101.357 ;
     RECT  178.416 101.227 178.434 101.357 ;
     RECT  180.615 101.227 180.99 101.357 ;
     RECT  182.412 101.227 182.43 101.357 ;
     RECT  186.015 101.227 186.39 101.357 ;
     RECT  190.404 101.227 190.422 101.357 ;
     RECT  191.415 101.227 191.79 101.357 ;
     RECT  70.596 101.039 70.794 101.381 ;
     RECT  6.408 100.229 13.497 101.389 ;
     RECT  14.256 100.849 14.274 101.389 ;
     RECT  77.94 101.039 79.47 101.405 ;
     RECT  81.72 101.345 83.697 101.405 ;
     RECT  85.068 101.357 85.302 101.405 ;
     RECT  106.344 101.309 106.362 101.405 ;
     RECT  29.415 100.963 29.697 101.416 ;
     RECT  30.528 101.353 30.582 101.416 ;
     RECT  2.415 101.119 3.474 101.425 ;
     RECT  33.084 101.261 33.57 101.453 ;
     RECT  71.676 101.191 74.61 101.453 ;
     RECT  79.452 101.405 79.47 101.453 ;
     RECT  90.684 100.769 90.702 101.453 ;
     RECT  107.64 101.191 108.018 101.453 ;
     RECT  111.816 101.191 112.194 101.453 ;
     RECT  70.704 101.381 70.794 101.461 ;
     RECT  72.288 101.453 74.61 101.461 ;
     RECT  219.456 101.281 219.474 101.501 ;
     RECT  24.015 100.963 24.297 101.551 ;
     RECT  29.415 101.416 30.582 101.551 ;
     RECT  70.704 101.461 70.866 101.551 ;
     RECT  86.868 101.183 87.138 101.551 ;
     RECT  120.924 101.357 121.497 101.551 ;
     RECT  2.415 101.425 4.014 101.579 ;
     RECT  81.72 101.405 82.494 101.579 ;
     RECT  94.215 100.769 94.842 101.579 ;
     RECT  111.924 101.453 111.942 101.579 ;
     RECT  213.015 101.345 215.01 101.579 ;
     RECT  216.036 101.425 216.054 101.579 ;
     RECT  98.064 101.039 100.53 101.587 ;
     RECT  1.152 100.607 1.242 101.615 ;
     RECT  107.64 101.453 107.73 101.615 ;
     RECT  67.215 101.039 67.497 101.623 ;
     RECT  86.184 101.551 87.138 101.645 ;
     RECT  98.064 101.587 100.71 101.651 ;
     RECT  196.815 101.219 202.662 101.651 ;
     RECT  98.604 101.651 100.71 101.659 ;
     RECT  61.815 101.309 62.118 101.687 ;
     RECT  72.288 101.461 74.682 101.687 ;
     RECT  98.604 101.659 101.43 101.687 ;
     RECT  144.216 101.191 144.342 101.687 ;
     RECT  85.068 101.405 85.086 101.693 ;
     RECT  119.7 100.777 119.718 101.695 ;
     RECT  120.492 101.551 121.497 101.695 ;
     RECT  70.704 101.551 71.082 101.723 ;
     RECT  118.584 101.227 118.602 101.723 ;
     RECT  217.872 101.425 217.89 101.731 ;
     RECT  66.78 101.623 67.497 101.755 ;
     RECT  5.184 101.345 5.202 101.759 ;
     RECT  101.412 101.687 101.43 101.759 ;
     RECT  66.744 101.755 67.497 101.848 ;
     RECT  68.256 101.039 69.318 101.848 ;
     RECT  108.756 101.357 109.062 101.848 ;
     RECT  2.415 101.579 3.546 101.849 ;
     RECT  74.664 101.687 74.682 101.849 ;
     RECT  86.616 101.645 87.138 101.849 ;
     RECT  108.72 101.848 109.062 101.849 ;
     RECT  213.015 101.579 214.938 101.849 ;
     RECT  217.476 101.731 217.89 101.849 ;
     RECT  23.904 101.551 24.297 101.857 ;
     RECT  2.415 101.849 2.79 101.885 ;
     RECT  66.744 101.848 69.318 101.885 ;
     RECT  108.72 101.849 108.738 101.885 ;
     RECT  119.7 101.695 121.497 101.885 ;
     RECT  144.324 101.687 144.342 101.885 ;
     RECT  196.815 101.651 201.258 101.885 ;
     RECT  217.476 101.849 217.854 101.885 ;
     RECT  43.308 101.309 43.326 101.921 ;
     RECT  23.904 101.857 24.534 101.929 ;
     RECT  68.292 101.885 69.318 101.957 ;
     RECT  26.784 101.147 27.378 101.993 ;
     RECT  29.304 101.551 30.582 101.993 ;
     RECT  6.408 101.389 14.274 102.001 ;
     RECT  68.364 101.957 69.318 102.029 ;
     RECT  29.304 101.993 30.258 102.043 ;
     RECT  34.815 100.963 35.097 102.085 ;
     RECT  33.48 101.453 33.57 102.091 ;
     RECT  45.54 100.805 46.458 102.091 ;
     RECT  56.415 100.805 56.697 102.091 ;
     RECT  77.94 101.405 78.297 102.091 ;
     RECT  3.528 101.849 3.546 102.119 ;
     RECT  15.732 102.043 15.75 102.119 ;
     RECT  29.016 102.043 30.258 102.119 ;
     RECT  33.48 102.091 33.822 102.119 ;
     RECT  217.656 101.885 217.854 102.119 ;
     RECT  34.704 102.085 35.097 102.125 ;
     RECT  23.904 101.929 24.57 102.128 ;
     RECT  45.504 102.091 46.458 102.128 ;
     RECT  56.304 102.091 56.697 102.128 ;
     RECT  77.904 102.091 78.297 102.128 ;
     RECT  1.152 101.615 1.17 102.155 ;
     RECT  33.804 102.119 33.822 102.173 ;
     RECT  20.196 101.345 22.914 102.191 ;
     RECT  75.204 102.091 75.402 102.191 ;
     RECT  70.704 101.723 70.938 102.199 ;
     RECT  15.804 102.127 15.822 102.227 ;
     RECT  185.22 101.707 185.238 102.227 ;
     RECT  75.384 102.191 75.402 102.235 ;
     RECT  20.196 102.191 22.842 102.263 ;
     RECT  196.815 101.885 201.222 102.263 ;
     RECT  26.928 101.993 27.378 102.271 ;
     RECT  72.288 101.687 73.674 102.271 ;
     RECT  6.336 102.001 14.274 102.389 ;
     RECT  26.928 102.271 27.486 102.389 ;
     RECT  29.415 102.119 30.258 102.389 ;
     RECT  70.092 102.199 70.938 102.389 ;
     RECT  27.216 102.389 27.486 102.413 ;
     RECT  27.36 102.413 27.486 102.425 ;
     RECT  70.704 102.389 70.938 102.425 ;
     RECT  75.384 102.235 75.474 102.425 ;
     RECT  107.712 101.615 107.73 102.425 ;
     RECT  27.468 102.425 27.486 102.461 ;
     RECT  24.015 102.128 24.57 102.497 ;
     RECT  75.456 102.425 75.474 102.497 ;
     RECT  72.072 102.271 73.674 102.533 ;
     RECT  66.744 101.885 67.497 102.569 ;
     RECT  109.8 101.357 110.697 102.605 ;
     RECT  20.196 102.263 22.302 102.659 ;
     RECT  198.108 102.263 201.222 102.659 ;
     RECT  20.916 102.659 22.302 102.695 ;
     RECT  69.012 102.029 69.318 102.701 ;
     RECT  72.072 102.533 72.954 102.715 ;
     RECT  37.872 100.877 37.89 102.731 ;
     RECT  71.784 102.715 72.954 102.767 ;
     RECT  213.015 101.849 214.722 102.803 ;
     RECT  219.42 102.763 219.438 102.803 ;
     RECT  21.276 102.695 22.05 102.839 ;
     RECT  68.508 102.775 68.85 102.929 ;
     RECT  69.696 102.811 69.714 102.929 ;
     RECT  70.704 102.425 70.902 102.929 ;
     RECT  216.396 102.811 216.414 102.929 ;
     RECT  194.364 102.763 194.382 102.941 ;
     RECT  71.856 102.767 72.954 103.001 ;
     RECT  70.704 102.929 70.83 103.037 ;
     RECT  74.628 102.907 74.646 103.037 ;
     RECT  217.548 102.811 217.566 103.045 ;
     RECT  6.408 102.389 14.274 103.073 ;
     RECT  217.548 103.045 217.854 103.081 ;
     RECT  6.408 103.073 12.366 103.171 ;
     RECT  198.108 102.659 201.114 103.199 ;
     RECT  217.224 103.081 217.854 103.199 ;
     RECT  72.54 103.001 72.954 103.229 ;
     RECT  198.108 103.199 198.126 103.235 ;
     RECT  13.215 103.073 14.274 103.271 ;
     RECT  86.868 101.849 87.138 103.271 ;
     RECT  120.924 101.885 121.497 103.277 ;
     RECT  14.256 103.271 14.274 103.307 ;
     RECT  93.024 100.921 93.294 103.307 ;
     RECT  199.44 103.199 201.114 103.307 ;
     RECT  29.415 102.389 29.697 103.339 ;
     RECT  21.42 102.839 22.05 103.343 ;
     RECT  99.036 101.687 100.53 103.343 ;
     RECT  202.215 101.651 202.662 103.343 ;
     RECT  99.615 103.343 100.53 103.379 ;
     RECT  199.44 103.307 200.718 103.379 ;
     RECT  28.656 103.339 28.674 103.469 ;
     RECT  29.415 103.339 29.79 103.469 ;
     RECT  68.832 102.929 68.85 103.469 ;
     RECT  21.744 103.343 22.05 103.477 ;
     RECT  21.744 103.477 22.446 103.517 ;
     RECT  69.948 103.477 69.966 103.517 ;
     RECT  2.415 101.885 2.697 103.579 ;
     RECT  6.372 103.171 12.366 103.585 ;
     RECT  213.015 102.803 214.29 103.723 ;
     RECT  2.304 103.579 2.697 103.775 ;
     RECT  72.54 103.229 72.897 103.775 ;
     RECT  199.44 103.379 199.854 103.775 ;
     RECT  77.94 102.128 78.297 103.811 ;
     RECT  199.836 103.775 199.854 103.811 ;
     RECT  119.7 101.885 120.186 103.847 ;
     RECT  212.364 103.723 214.29 103.847 ;
     RECT  217.224 103.199 217.386 103.855 ;
     RECT  21.96 103.517 22.446 103.867 ;
     RECT  5.652 103.585 12.366 103.883 ;
     RECT  119.7 103.847 119.718 103.883 ;
     RECT  4.86 103.891 4.878 103.949 ;
     RECT  21.96 103.867 22.662 103.981 ;
     RECT  21.96 103.981 23.166 104.008 ;
     RECT  24.015 102.497 24.297 104.008 ;
     RECT  21.96 104.008 24.297 104.009 ;
     RECT  216.936 103.855 217.386 104.009 ;
     RECT  23.148 104.009 24.297 104.045 ;
     RECT  81.72 101.579 81.738 104.045 ;
     RECT  217.368 104.009 217.386 104.045 ;
     RECT  22.032 104.009 22.05 104.117 ;
     RECT  23.904 104.045 24.297 104.117 ;
     RECT  47.7 104.107 47.718 104.251 ;
     RECT  47.376 104.251 47.718 104.279 ;
     RECT  217.512 104.161 217.53 104.279 ;
     RECT  219.42 104.059 219.438 104.279 ;
     RECT  47.376 104.279 47.394 104.351 ;
     RECT  70.704 103.037 70.722 104.351 ;
     RECT  200.7 103.379 200.718 104.351 ;
     RECT  45.54 102.128 46.458 104.381 ;
     RECT  88.38 101.261 89.097 104.521 ;
     RECT  88.38 104.521 89.226 104.539 ;
     RECT  88.092 104.539 89.226 104.573 ;
     RECT  88.092 104.573 89.097 104.585 ;
     RECT  4.896 104.161 4.914 104.629 ;
     RECT  6.12 103.883 12.186 104.629 ;
     RECT  45.54 104.381 45.897 104.909 ;
     RECT  4.896 104.629 12.186 104.971 ;
     RECT  21.384 105.019 21.402 105.061 ;
     RECT  22.824 104.923 22.842 105.101 ;
     RECT  24.015 104.117 24.297 105.211 ;
     RECT  212.364 103.847 213.966 105.241 ;
     RECT  113.22 105.211 113.238 105.331 ;
     RECT  4.824 104.971 12.186 105.359 ;
     RECT  21.096 105.061 21.402 105.359 ;
     RECT  23.508 105.211 24.297 105.359 ;
     RECT  113.22 105.331 113.526 105.359 ;
     RECT  195.768 105.211 195.786 105.359 ;
     RECT  211.86 105.241 213.966 105.359 ;
     RECT  216.972 105.241 217.062 105.359 ;
     RECT  113.508 105.359 113.526 105.389 ;
     RECT  194.22 105.331 194.238 105.389 ;
     RECT  217.044 105.359 217.062 105.395 ;
     RECT  4.824 105.359 9.954 105.431 ;
     RECT  23.832 105.359 24.297 105.437 ;
     RECT  211.86 105.359 213.93 105.475 ;
     RECT  24.015 105.437 24.297 105.601 ;
     RECT  211.644 105.475 213.93 105.629 ;
     RECT  217.188 105.511 217.206 105.629 ;
     RECT  220.212 105.355 220.23 105.629 ;
     RECT  212.544 105.629 213.93 105.665 ;
     RECT  24.015 105.601 24.426 105.677 ;
     RECT  212.58 105.665 213.93 105.701 ;
     RECT  4.824 105.431 9.486 105.745 ;
     RECT  211.644 105.629 211.662 105.773 ;
     RECT  212.652 105.701 213.93 105.809 ;
     RECT  4.68 105.745 9.486 105.821 ;
     RECT  0.108 105.745 0.126 105.917 ;
     RECT  0.54 106.177 0.558 106.253 ;
     RECT  121.215 103.277 121.497 106.411 ;
     RECT  128.16 106.321 128.178 106.411 ;
     RECT  132.015 101.357 132.297 106.411 ;
     RECT  142.815 101.357 143.097 106.411 ;
     RECT  153.615 101.357 153.897 106.411 ;
     RECT  164.415 101.357 164.697 106.411 ;
     RECT  175.215 101.357 175.497 106.411 ;
     RECT  186.015 101.357 186.297 106.411 ;
     RECT  128.052 106.411 128.178 106.445 ;
     RECT  129.6 106.405 129.618 106.445 ;
     RECT  194.364 106.267 194.382 106.445 ;
     RECT  121.104 106.411 121.497 106.448 ;
     RECT  128.052 106.445 128.07 106.448 ;
     RECT  131.904 106.411 132.297 106.448 ;
     RECT  142.704 106.411 143.097 106.448 ;
     RECT  153.504 106.411 153.897 106.448 ;
     RECT  164.304 106.411 164.697 106.448 ;
     RECT  175.104 106.411 175.497 106.448 ;
     RECT  185.904 106.411 186.297 106.448 ;
     RECT  10.692 105.359 12.186 106.583 ;
     RECT  10.692 106.583 11.43 106.591 ;
     RECT  218.88 106.411 218.898 106.637 ;
     RECT  213.015 105.809 213.93 106.694 ;
     RECT  214.704 106.591 214.866 106.694 ;
     RECT  216.144 106.591 216.162 106.699 ;
     RECT  213.015 106.694 214.866 106.717 ;
     RECT  215.604 106.699 216.162 106.717 ;
     RECT  1.152 106.555 1.17 106.825 ;
     RECT  2.415 103.775 2.697 106.825 ;
     RECT  5.076 105.821 9.486 106.825 ;
     RECT  217.512 106.591 217.53 106.825 ;
     RECT  5.076 106.825 9.81 106.861 ;
     RECT  10.656 106.591 11.43 106.861 ;
     RECT  217.368 106.825 217.818 106.861 ;
     RECT  195.3 106.411 195.318 106.925 ;
     RECT  4.536 106.861 11.43 106.979 ;
     RECT  213.015 106.717 216.342 106.979 ;
     RECT  4.68 106.979 11.43 107.021 ;
     RECT  3.6 106.861 3.618 107.023 ;
     RECT  213.015 106.979 215.478 107.051 ;
     RECT  216.324 106.979 216.342 107.051 ;
     RECT  217.296 106.861 218.034 107.051 ;
     RECT  217.296 107.051 217.314 107.087 ;
     RECT  213.015 107.051 215.334 107.123 ;
     RECT  3.6 107.023 3.762 107.249 ;
     RECT  1.152 106.825 2.697 107.261 ;
     RECT  197.928 107.515 197.946 107.555 ;
     RECT  196.815 102.263 197.097 107.671 ;
     RECT  5.256 107.021 11.43 107.699 ;
     RECT  196.38 107.671 197.097 107.741 ;
     RECT  198.288 107.755 198.486 107.837 ;
     RECT  2.304 107.261 2.697 107.869 ;
     RECT  213.015 107.123 214.722 107.869 ;
     RECT  5.256 107.699 9.99 107.897 ;
     RECT  213.015 107.869 214.866 107.905 ;
     RECT  10.764 107.699 11.43 107.933 ;
     RECT  216.936 107.905 216.954 107.941 ;
     RECT  2.304 107.869 3.366 107.969 ;
     RECT  5.256 107.897 9.882 108.059 ;
     RECT  198.468 107.837 198.486 108.059 ;
     RECT  216.936 107.941 217.422 108.059 ;
     RECT  196.704 107.741 197.097 108.077 ;
     RECT  217.404 108.059 217.422 108.095 ;
     RECT  213.015 107.905 215.01 108.301 ;
     RECT  212.976 108.301 215.01 108.329 ;
     RECT  217.512 108.211 217.53 108.329 ;
     RECT  219.42 107.899 219.438 108.329 ;
     RECT  212.976 108.329 214.686 108.365 ;
     RECT  212.976 108.365 214.65 108.401 ;
     RECT  212.976 108.401 214.254 108.427 ;
     RECT  212.4 108.427 214.254 108.509 ;
     RECT  2.304 107.969 2.862 108.523 ;
     RECT  5.328 108.059 9.378 108.599 ;
     RECT  212.4 108.509 213.534 108.679 ;
     RECT  5.364 108.599 9.378 108.749 ;
     RECT  5.544 108.749 9.378 108.869 ;
     RECT  2.268 108.523 2.862 108.905 ;
     RECT  2.304 108.905 2.862 109.111 ;
     RECT  44.172 109.051 44.19 109.111 ;
     RECT  216.504 108.571 216.522 109.139 ;
     RECT  217.296 109.021 217.386 109.139 ;
     RECT  1.152 107.261 1.17 109.175 ;
     RECT  44.172 109.111 44.37 109.175 ;
     RECT  217.368 109.139 217.386 109.175 ;
     RECT  44.352 109.175 44.37 109.181 ;
     RECT  2.304 109.111 3.042 109.291 ;
     RECT  2.304 109.291 3.114 109.409 ;
     RECT  217.512 109.291 217.53 109.409 ;
     RECT  219.42 109.195 219.438 109.409 ;
     RECT  212.04 108.679 213.534 109.453 ;
     RECT  4.284 108.043 4.302 109.679 ;
     RECT  5.688 108.869 9.378 109.679 ;
     RECT  0.108 109.195 0.126 109.715 ;
     RECT  5.688 109.679 8.514 109.949 ;
     RECT  2.304 109.409 2.697 109.985 ;
     RECT  217.152 110.029 217.17 110.335 ;
     RECT  211.536 109.453 213.534 110.347 ;
     RECT  217.152 110.335 217.566 110.371 ;
     RECT  210.816 110.347 213.534 110.381 ;
     RECT  211.716 110.381 213.534 110.399 ;
     RECT  210.816 110.381 210.978 110.489 ;
     RECT  211.86 110.399 213.534 110.489 ;
     RECT  217.152 110.371 217.854 110.489 ;
     RECT  211.86 110.489 211.878 110.525 ;
     RECT  212.76 110.489 213.534 110.561 ;
     RECT  12.168 106.583 12.186 110.641 ;
     RECT  13.215 103.271 13.497 110.641 ;
     RECT  214.74 110.533 214.758 110.641 ;
     RECT  9.252 109.679 9.378 110.669 ;
     RECT  212.76 110.561 213.462 110.669 ;
     RECT  212.76 110.669 213.354 110.759 ;
     RECT  217.836 110.489 217.854 110.795 ;
     RECT  220.212 110.491 220.23 110.867 ;
     RECT  5.688 109.949 8.442 110.875 ;
     RECT  9.252 110.669 9.27 110.875 ;
     RECT  214.524 110.641 214.758 110.875 ;
     RECT  214.344 110.875 214.758 110.911 ;
     RECT  214.344 110.911 214.902 111.029 ;
     RECT  11.052 107.933 11.43 111.109 ;
     RECT  12.168 110.641 13.497 111.109 ;
     RECT  214.74 111.029 214.902 111.271 ;
     RECT  216 111.073 216.018 111.299 ;
     RECT  214.74 111.271 215.19 111.379 ;
     RECT  11.052 111.109 13.497 111.443 ;
     RECT  13.14 111.443 13.497 111.541 ;
     RECT  13.14 111.541 13.554 111.605 ;
     RECT  214.74 111.379 215.982 111.605 ;
     RECT  212.76 110.759 213.297 111.613 ;
     RECT  13.215 111.605 13.554 111.629 ;
     RECT  212.76 111.613 213.75 111.641 ;
     RECT  214.956 111.605 215.37 111.641 ;
     RECT  217.368 111.685 217.386 111.721 ;
     RECT  217.044 111.721 217.782 111.839 ;
     RECT  0.108 111.835 0.126 111.875 ;
     RECT  217.764 111.839 217.782 111.875 ;
     RECT  2.415 109.985 2.697 111.991 ;
     RECT  217.872 111.991 217.89 112.109 ;
     RECT  219.42 111.787 219.438 112.109 ;
     RECT  0.144 111.955 0.558 112.205 ;
     RECT  4.68 111.955 4.698 112.225 ;
     RECT  5.688 110.875 9.27 112.225 ;
     RECT  4.68 112.225 9.27 112.261 ;
     RECT  4.536 112.261 9.27 112.289 ;
     RECT  2.415 111.991 3.258 112.495 ;
     RECT  5.292 112.289 9.27 112.649 ;
     RECT  4.536 112.289 4.554 112.765 ;
     RECT  2.415 112.495 3.51 112.801 ;
     RECT  0.144 112.205 0.162 112.843 ;
     RECT  2.415 112.801 3.582 112.919 ;
     RECT  4.356 112.765 4.554 112.919 ;
     RECT  2.415 112.919 3.222 113.189 ;
     RECT  0.108 112.843 0.162 113.213 ;
     RECT  11.052 111.443 12.186 113.341 ;
     RECT  2.415 113.189 3.006 113.459 ;
     RECT  5.292 112.649 5.706 113.467 ;
     RECT  6.66 112.649 9.27 113.467 ;
     RECT  1.152 112.507 1.17 113.495 ;
     RECT  18.615 101.183 18.897 113.611 ;
     RECT  13.215 111.629 13.497 113.707 ;
     RECT  17.316 99.197 17.334 113.707 ;
     RECT  18.54 113.611 18.897 113.737 ;
     RECT  17.244 113.707 17.334 113.765 ;
     RECT  18.216 113.737 18.897 113.773 ;
     RECT  13.215 113.707 13.59 113.803 ;
     RECT  17.82 113.773 18.897 113.837 ;
     RECT  13.215 113.803 13.698 113.873 ;
     RECT  4.356 112.919 4.374 113.881 ;
     RECT  18.216 113.837 18.897 113.881 ;
     RECT  13.215 113.873 13.518 113.885 ;
     RECT  18.216 113.881 19.098 113.909 ;
     RECT  5.292 113.467 9.27 113.999 ;
     RECT  10.836 113.341 12.186 114.091 ;
     RECT  10.8 114.091 12.186 114.115 ;
     RECT  3.996 113.881 4.374 114.151 ;
     RECT  10.728 114.115 12.186 114.173 ;
     RECT  47.34 113.575 47.358 114.305 ;
     RECT  108.468 114.241 108.486 114.413 ;
     RECT  2.415 113.459 2.862 114.539 ;
     RECT  106.596 114.421 106.614 114.539 ;
     RECT  108.72 114.421 108.81 114.539 ;
     RECT  213.015 111.641 213.75 114.571 ;
     RECT  214.74 114.421 214.758 114.571 ;
     RECT  18.615 113.909 19.098 114.575 ;
     RECT  119.628 113.539 119.646 114.575 ;
     RECT  5.832 113.999 9.27 114.605 ;
     RECT  3.96 114.151 4.374 114.809 ;
     RECT  0.108 113.213 0.126 114.845 ;
     RECT  216.936 114.925 216.954 114.961 ;
     RECT  4.356 114.809 4.374 115.079 ;
     RECT  108.72 114.539 108.738 115.079 ;
     RECT  216.936 114.961 217.422 115.079 ;
     RECT  2.415 114.539 2.697 115.087 ;
     RECT  217.404 115.079 217.422 115.115 ;
     RECT  213.015 114.571 214.758 115.151 ;
     RECT  1.728 115.087 2.697 115.181 ;
     RECT  214.596 115.151 214.758 115.223 ;
     RECT  213.015 115.151 213.75 115.349 ;
     RECT  214.596 115.223 214.614 115.349 ;
     RECT  217.512 115.231 217.53 115.349 ;
     RECT  219.42 115.051 219.438 115.349 ;
     RECT  5.4 115.147 5.418 115.619 ;
     RECT  3.564 115.051 3.582 115.889 ;
     RECT  6.696 114.605 9.27 115.889 ;
     RECT  2.304 115.181 2.697 115.925 ;
     RECT  11.052 114.173 12.186 115.961 ;
     RECT  5.76 116.005 5.778 116.045 ;
     RECT  3.636 116.041 3.654 116.159 ;
     RECT  0.108 115.819 0.126 116.195 ;
     RECT  24.015 105.677 24.297 116.401 ;
     RECT  24.015 116.401 24.642 116.477 ;
     RECT  10.296 116.545 10.314 116.581 ;
     RECT  11.052 115.961 12.042 116.581 ;
     RECT  24.015 116.477 24.354 116.621 ;
     RECT  7.128 115.889 9.27 116.671 ;
     RECT  10.296 116.581 12.042 116.671 ;
     RECT  7.128 116.671 12.042 116.969 ;
     RECT  51.015 100.805 51.297 117.067 ;
     RECT  51.015 117.067 51.75 117.239 ;
     RECT  51.015 117.239 51.462 117.248 ;
     RECT  7.128 116.969 11.286 117.481 ;
     RECT  5.868 117.403 5.886 117.545 ;
     RECT  6.804 117.481 11.286 117.661 ;
     RECT  6.012 117.661 11.286 117.823 ;
     RECT  12.024 116.969 12.042 117.823 ;
     RECT  213.015 115.349 213.462 118.075 ;
     RECT  2.415 115.925 2.697 118.165 ;
     RECT  1.728 118.165 2.697 118.201 ;
     RECT  217.368 118.165 217.386 118.201 ;
     RECT  148.215 101.357 148.497 118.291 ;
     RECT  217.368 118.201 217.854 118.291 ;
     RECT  0.108 118.123 0.126 118.355 ;
     RECT  39.348 118.315 39.366 118.355 ;
     RECT  217.188 118.291 217.854 118.391 ;
     RECT  1.728 118.201 3.114 118.459 ;
     RECT  6.012 117.823 12.042 118.471 ;
     RECT  40.215 100.877 40.497 118.471 ;
     RECT  212.4 118.075 213.462 118.493 ;
     RECT  1.152 118.459 3.114 118.589 ;
     RECT  40.032 118.471 40.497 118.589 ;
     RECT  148.215 118.291 149.022 118.589 ;
     RECT  217.188 118.391 217.206 118.589 ;
     RECT  220.212 118.363 220.23 118.589 ;
     RECT  5.94 118.471 12.042 118.741 ;
     RECT  3.888 118.741 4.05 118.781 ;
     RECT  4.968 118.741 12.042 118.781 ;
     RECT  1.152 118.589 2.697 118.829 ;
     RECT  4.032 118.781 4.05 118.859 ;
     RECT  21.636 118.939 21.654 118.987 ;
     RECT  5.436 118.781 12.042 119.021 ;
     RECT  5.58 119.021 12.042 119.129 ;
     RECT  21.636 118.987 21.942 119.129 ;
     RECT  1.152 118.829 1.17 119.131 ;
     RECT  0.54 119.131 1.17 119.165 ;
     RECT  0.54 119.165 0.558 119.273 ;
     RECT  2.415 118.829 2.697 119.551 ;
     RECT  2.415 119.551 3.366 119.669 ;
     RECT  5.832 119.129 12.042 119.749 ;
     RECT  13.215 113.885 13.497 119.749 ;
     RECT  2.415 119.669 2.934 119.803 ;
     RECT  29.415 103.469 29.697 119.947 ;
     RECT  5.832 119.749 13.497 120.091 ;
     RECT  29.415 119.947 29.79 120.091 ;
     RECT  29.415 120.091 30.114 120.269 ;
     RECT  4.86 119.983 4.878 120.325 ;
     RECT  5.724 120.091 13.497 120.325 ;
     RECT  4.86 120.325 13.497 120.353 ;
     RECT  5.544 120.353 13.497 120.389 ;
     RECT  2.304 119.803 2.934 120.479 ;
     RECT  2.304 120.479 2.79 120.515 ;
     RECT  0.108 119.467 0.126 120.757 ;
     RECT  0.108 120.757 0.558 120.797 ;
     RECT  186.015 106.448 186.297 120.955 ;
     RECT  10.224 120.389 13.497 121.019 ;
     RECT  10.332 121.019 13.497 121.199 ;
     RECT  185.58 120.955 186.297 121.289 ;
     RECT  187.128 120.991 187.146 121.297 ;
     RECT  0.108 120.797 0.126 121.325 ;
     RECT  172.584 114.115 172.602 121.325 ;
     RECT  187.128 121.297 187.218 121.325 ;
     RECT  2.415 120.515 2.79 121.369 ;
     RECT  182.412 121.297 182.43 121.397 ;
     RECT  187.2 121.325 187.218 121.397 ;
     RECT  5.544 120.389 9.342 121.433 ;
     RECT  211.716 121.297 211.734 121.435 ;
     RECT  6.192 121.433 9.342 121.441 ;
     RECT  210.996 121.435 211.734 121.441 ;
     RECT  2.268 121.369 2.79 121.469 ;
     RECT  4.14 121.135 4.158 121.469 ;
     RECT  213.015 118.493 213.462 121.469 ;
     RECT  10.332 121.199 12.474 121.559 ;
     RECT  119.772 114.691 119.79 121.559 ;
     RECT  6.192 121.441 9.558 121.631 ;
     RECT  210.996 121.441 211.986 121.631 ;
     RECT  211.716 121.631 211.986 121.667 ;
     RECT  219.42 121.627 219.438 121.667 ;
     RECT  6.192 121.631 7.038 121.703 ;
     RECT  211.716 121.667 211.734 121.703 ;
     RECT  2.304 121.469 2.79 121.801 ;
     RECT  3.888 121.711 3.906 121.801 ;
     RECT  2.304 121.801 3.906 121.829 ;
     RECT  10.692 121.559 12.474 121.829 ;
     RECT  216.288 121.531 216.306 121.829 ;
     RECT  217.548 121.711 217.566 121.829 ;
     RECT  5.112 121.441 5.418 121.865 ;
     RECT  6.192 121.703 7.002 121.865 ;
     RECT  7.776 121.631 9.558 121.901 ;
     RECT  6.228 121.865 7.002 121.937 ;
     RECT  10.692 121.829 12.006 121.937 ;
     RECT  7.776 121.901 8.55 121.949 ;
     RECT  9.396 121.901 9.558 121.963 ;
     RECT  9.396 121.963 9.918 121.997 ;
     RECT  10.692 121.937 11.43 121.997 ;
     RECT  7.815 121.949 8.55 122.099 ;
     RECT  9.756 121.997 9.918 122.099 ;
     RECT  10.692 121.997 10.71 122.099 ;
     RECT  217.836 121.945 217.854 122.099 ;
     RECT  2.304 121.829 3.546 122.135 ;
     RECT  9.756 122.099 9.774 122.135 ;
     RECT  216.972 121.981 216.99 122.135 ;
     RECT  6.66 121.937 7.002 122.144 ;
     RECT  1.152 122.107 1.17 122.443 ;
     RECT  6.66 122.144 6.822 122.639 ;
     RECT  1.152 122.443 1.206 122.779 ;
     RECT  6.66 122.639 6.786 122.909 ;
     RECT  4.536 122.791 4.554 123.061 ;
     RECT  1.152 122.779 1.242 123.067 ;
     RECT  4.5 123.061 4.554 123.149 ;
     RECT  4.5 123.149 4.518 123.179 ;
     RECT  1.152 123.067 1.278 123.215 ;
     RECT  2.415 122.135 3.546 123.359 ;
     RECT  5.4 121.865 5.418 123.449 ;
     RECT  6.66 122.909 6.678 123.449 ;
     RECT  1.188 123.215 1.278 123.485 ;
     RECT  2.415 123.359 3.402 123.719 ;
     RECT  1.224 123.485 1.278 123.755 ;
     RECT  2.415 123.719 3.114 123.989 ;
     RECT  1.26 123.755 1.278 124.025 ;
     RECT  34.815 102.125 35.097 124.123 ;
     RECT  45.615 104.909 45.897 124.123 ;
     RECT  56.415 102.128 56.697 124.123 ;
     RECT  67.215 102.569 67.497 124.123 ;
     RECT  78.015 103.811 78.297 124.123 ;
     RECT  88.815 104.585 89.097 124.123 ;
     RECT  99.615 103.379 99.897 124.123 ;
     RECT  110.415 102.605 110.697 124.123 ;
     RECT  121.215 106.448 121.497 124.123 ;
     RECT  132.015 106.448 132.297 124.123 ;
     RECT  34.704 124.123 35.097 124.169 ;
     RECT  45.504 124.123 45.897 124.169 ;
     RECT  56.304 124.123 56.697 124.169 ;
     RECT  67.104 124.123 67.497 124.169 ;
     RECT  77.904 124.123 78.297 124.169 ;
     RECT  88.704 124.123 89.097 124.169 ;
     RECT  99.504 124.123 99.897 124.169 ;
     RECT  110.304 124.123 110.697 124.169 ;
     RECT  121.104 124.123 121.497 124.169 ;
     RECT  131.904 124.123 132.297 124.169 ;
     RECT  140.904 124.123 140.922 124.259 ;
     RECT  142.815 106.448 143.097 124.411 ;
     RECT  142.452 124.411 143.097 124.843 ;
     RECT  142.452 124.843 143.19 124.877 ;
     RECT  142.815 124.877 143.19 124.973 ;
     RECT  7.815 122.099 8.19 125.339 ;
     RECT  7.815 125.339 8.097 125.419 ;
     RECT  7.74 125.419 8.097 125.456 ;
     RECT  6.948 125.419 6.966 125.483 ;
     RECT  3.636 125.383 3.654 125.609 ;
     RECT  7.776 125.456 8.097 125.609 ;
     RECT  0.108 125.419 0.126 125.645 ;
     RECT  2.415 123.989 2.697 127.187 ;
     RECT  7.815 125.609 8.097 127.187 ;
     RECT  13.215 121.199 13.497 127.187 ;
     RECT  18.615 114.575 18.897 127.187 ;
     RECT  24.015 116.621 24.297 127.187 ;
     RECT  29.415 120.269 29.697 127.187 ;
     RECT  34.815 124.169 35.097 127.187 ;
     RECT  40.215 118.589 40.497 127.187 ;
     RECT  45.615 124.169 45.897 127.187 ;
     RECT  51.015 117.248 51.297 127.187 ;
     RECT  56.415 124.169 56.697 127.187 ;
     RECT  61.815 101.687 62.097 127.187 ;
     RECT  67.215 124.169 67.497 127.187 ;
     RECT  72.615 103.775 72.897 127.187 ;
     RECT  78.015 124.169 78.297 127.187 ;
     RECT  83.415 101.405 83.697 127.187 ;
     RECT  88.815 124.169 89.097 127.187 ;
     RECT  94.215 101.579 94.497 127.187 ;
     RECT  99.615 124.169 99.897 127.187 ;
     RECT  105.015 101.261 105.297 127.187 ;
     RECT  110.415 124.169 110.697 127.187 ;
     RECT  115.815 101.357 116.097 127.187 ;
     RECT  121.215 124.169 121.497 127.187 ;
     RECT  126.615 101.357 126.897 127.187 ;
     RECT  132.015 124.169 132.297 127.187 ;
     RECT  137.415 101.357 137.697 127.187 ;
     RECT  142.815 124.973 143.097 127.187 ;
     RECT  148.215 118.589 148.497 127.187 ;
     RECT  153.615 106.448 153.897 127.187 ;
     RECT  159.015 101.357 159.297 127.187 ;
     RECT  164.415 106.448 164.697 127.187 ;
     RECT  169.815 101.357 170.097 127.187 ;
     RECT  175.215 106.448 175.497 127.187 ;
     RECT  180.615 101.357 180.897 127.187 ;
     RECT  186.015 121.289 186.297 127.187 ;
     RECT  191.415 101.357 191.697 127.187 ;
     RECT  196.815 108.077 197.097 127.187 ;
     RECT  202.215 103.343 202.497 127.187 ;
     RECT  207.615 33.389 207.897 127.187 ;
     RECT  213.015 121.469 213.297 127.187 ;
     RECT  173.628 127.237 173.646 127.277 ;
     RECT  174.384 127.201 174.402 127.277 ;
     RECT  2.415 127.187 2.505 127.457 ;
     RECT  7.815 127.187 7.905 127.457 ;
     RECT  13.215 127.187 13.305 127.457 ;
     RECT  18.615 127.187 18.705 127.457 ;
     RECT  24.015 127.187 24.105 127.457 ;
     RECT  29.415 127.187 29.505 127.457 ;
     RECT  34.815 127.187 34.905 127.457 ;
     RECT  40.215 127.187 40.305 127.457 ;
     RECT  45.615 127.187 45.705 127.457 ;
     RECT  51.015 127.187 51.105 127.457 ;
     RECT  56.415 127.187 56.505 127.457 ;
     RECT  61.815 127.187 61.905 127.457 ;
     RECT  67.215 127.187 67.305 127.457 ;
     RECT  72.615 127.187 72.705 127.457 ;
     RECT  78.015 127.187 78.105 127.457 ;
     RECT  83.415 127.187 83.505 127.457 ;
     RECT  88.815 127.187 88.905 127.457 ;
     RECT  94.215 127.187 94.305 127.457 ;
     RECT  99.615 127.187 99.705 127.457 ;
     RECT  105.015 127.187 105.105 127.457 ;
     RECT  110.415 127.187 110.505 127.457 ;
     RECT  115.815 127.187 115.905 127.457 ;
     RECT  121.215 127.187 121.305 127.457 ;
     RECT  126.615 127.187 126.705 127.457 ;
     RECT  132.015 127.187 132.105 127.457 ;
     RECT  137.415 127.187 137.505 127.457 ;
     RECT  142.815 127.187 142.905 127.457 ;
     RECT  148.215 127.187 148.305 127.457 ;
     RECT  153.615 127.187 153.705 127.457 ;
     RECT  159.015 127.187 159.105 127.457 ;
     RECT  164.415 127.187 164.505 127.457 ;
     RECT  169.815 127.187 169.905 127.457 ;
     RECT  175.215 127.187 175.305 127.457 ;
     RECT  180.615 127.187 180.705 127.457 ;
     RECT  186.015 127.187 186.105 127.457 ;
     RECT  191.415 127.187 191.505 127.457 ;
     RECT  196.815 127.187 196.905 127.457 ;
     RECT  202.215 127.187 202.305 127.457 ;
     RECT  207.615 127.187 207.705 127.457 ;
     RECT  213.015 127.187 213.105 127.457 ;
    LAYER M4 ;
     RECT  0.06 6.48 0.137 8.808 ;
     RECT  0.06 11.136 0.137 14.76 ;
     RECT  0.06 17.088 0.137 101.256 ;
     RECT  0.06 105.888 0.137 109.56 ;
     RECT  0.06 111.84 0.137 115.848 ;
     RECT  0.06 118.128 0.137 123.096 ;
     RECT  0.137 19.728 0.173 34.584 ;
     RECT  0.137 35.568 0.173 36.888 ;
     RECT  0.137 49.44 0.173 64.968 ;
     RECT  0.137 78.48 0.173 87.72 ;
     RECT  0.137 90.336 0.173 95.64 ;
     RECT  0.137 112.176 0.173 113.88 ;
     RECT  0.173 19.728 0.179 25.224 ;
     RECT  0.179 19.728 0.569 24.024 ;
     RECT  0.173 26.304 0.569 26.328 ;
     RECT  0.137 38.208 0.569 47.448 ;
     RECT  0.173 54.72 0.569 59.016 ;
     RECT  0.173 64.944 0.569 64.968 ;
     RECT  0.137 67.584 0.569 71.544 ;
     RECT  0.137 72.528 0.569 77.496 ;
     RECT  0.173 80.784 0.569 87.72 ;
     RECT  0.173 94.656 0.569 95.64 ;
     RECT  0.137 106.224 0.569 108.888 ;
     RECT  0.173 112.176 0.569 112.536 ;
     RECT  0.137 118.464 0.569 123.096 ;
     RECT  0.137 7.152 1.181 8.808 ;
     RECT  0.137 11.472 1.181 14.76 ;
     RECT  0.569 19.728 1.181 22.056 ;
     RECT  0.569 23.376 1.181 24.024 ;
     RECT  0.173 27.312 1.181 32.28 ;
     RECT  0.569 38.208 1.181 46.152 ;
     RECT  0.569 47.136 1.181 47.448 ;
     RECT  0.173 49.44 1.181 53.4 ;
     RECT  0.569 57.696 1.181 59.016 ;
     RECT  0.173 60 1.181 63.624 ;
     RECT  0.137 66 1.181 66.6 ;
     RECT  0.569 72.528 1.181 75.864 ;
     RECT  0.569 77.136 1.181 77.496 ;
     RECT  0.173 78.48 1.181 79.464 ;
     RECT  0.569 80.784 1.181 87.384 ;
     RECT  0.137 88.704 1.181 89.064 ;
     RECT  0.173 90.336 1.181 90.36 ;
     RECT  0.173 91.344 1.181 93.336 ;
     RECT  0.569 94.656 1.181 95.304 ;
     RECT  0.137 96.624 1.181 98.28 ;
     RECT  0.137 99.264 1.181 101.256 ;
     RECT  0.569 106.56 1.181 108.888 ;
     RECT  0.569 112.512 1.181 112.536 ;
     RECT  0.569 118.464 1.181 118.824 ;
     RECT  0.569 54.72 1.217 56.376 ;
     RECT  0.569 69.552 1.217 71.544 ;
     RECT  1.181 86.4 1.217 87.048 ;
     RECT  0.569 121.44 1.217 123.096 ;
     RECT  1.181 13.44 1.253 14.76 ;
     RECT  1.181 99.6 1.253 100.92 ;
     RECT  1.217 122.784 1.253 123.096 ;
     RECT  1.181 7.488 1.289 8.472 ;
     RECT  1.253 123.072 1.289 123.096 ;
     RECT  1.181 40.176 1.325 46.152 ;
     RECT  1.181 73.536 1.325 75.864 ;
     RECT  1.181 72.528 1.361 72.552 ;
     RECT  1.289 7.488 2.408 7.512 ;
     RECT  1.181 11.472 2.408 12.456 ;
     RECT  1.253 13.44 2.408 13.464 ;
     RECT  1.253 14.736 2.408 14.76 ;
     RECT  0.137 17.088 2.408 18.264 ;
     RECT  1.181 19.728 2.408 21.24 ;
     RECT  1.181 23.664 2.408 24.024 ;
     RECT  0.179 25.2 2.408 25.224 ;
     RECT  1.181 27.312 2.408 27.336 ;
     RECT  1.181 28.32 2.408 28.968 ;
     RECT  1.181 29.952 2.408 31.608 ;
     RECT  0.173 33.264 2.408 34.584 ;
     RECT  0.173 35.904 2.408 36.888 ;
     RECT  1.181 38.208 2.408 38.904 ;
     RECT  1.325 40.176 2.408 40.872 ;
     RECT  1.325 42.144 2.408 46.152 ;
     RECT  1.181 47.424 2.408 47.448 ;
     RECT  1.181 49.44 2.408 50.088 ;
     RECT  1.181 51.072 2.408 51.096 ;
     RECT  1.181 52.08 2.408 53.064 ;
     RECT  1.217 54.72 2.408 55.704 ;
     RECT  1.181 57.696 2.408 58.44 ;
     RECT  1.181 60 2.408 61.32 ;
     RECT  1.181 62.304 2.408 63.288 ;
     RECT  1.181 66 2.408 66.024 ;
     RECT  0.569 67.584 2.408 68.568 ;
     RECT  1.217 69.552 2.408 70.248 ;
     RECT  1.217 71.52 2.408 71.544 ;
     RECT  1.325 73.536 2.408 74.856 ;
     RECT  1.325 75.84 2.408 75.864 ;
     RECT  1.181 77.472 2.408 77.496 ;
     RECT  1.181 79.44 2.408 79.464 ;
     RECT  1.181 80.784 2.408 83.448 ;
     RECT  1.181 85.056 2.408 85.416 ;
     RECT  1.217 86.4 2.408 86.424 ;
     RECT  1.181 89.04 2.408 89.064 ;
     RECT  1.181 91.344 2.408 92.664 ;
     RECT  1.181 94.944 2.408 95.304 ;
     RECT  1.181 96.624 2.408 96.984 ;
     RECT  1.181 98.256 2.408 98.28 ;
     RECT  1.253 99.6 2.408 99.624 ;
     RECT  1.253 100.896 2.408 100.92 ;
     RECT  1.181 106.896 2.408 108.888 ;
     RECT  0.173 113.856 2.408 113.88 ;
     RECT  0.137 115.152 2.408 115.512 ;
     RECT  1.181 118.8 2.408 118.824 ;
     RECT  0.569 119.808 2.408 119.832 ;
     RECT  1.217 121.44 2.408 121.8 ;
     RECT  2.408 2.148 2.512 127.452 ;
     RECT  2.512 2.418 2.704 127.182 ;
     RECT  2.704 82.752 2.765 83.208 ;
     RECT  2.704 55.68 2.801 56.472 ;
     RECT  2.704 100.896 2.801 100.92 ;
     RECT  2.704 87.984 2.819 88.008 ;
     RECT  2.704 21.216 2.909 21.24 ;
     RECT  2.704 66 3.017 66.936 ;
     RECT  2.704 18.24 3.089 18.264 ;
     RECT  2.704 34.08 3.244 35.448 ;
     RECT  2.704 32.928 3.292 32.952 ;
     RECT  2.704 25.2 3.341 25.224 ;
     RECT  2.704 75.936 3.443 77.544 ;
     RECT  2.704 31.872 3.521 31.896 ;
     RECT  2.704 91.344 3.521 91.368 ;
     RECT  3.017 66.912 3.539 66.936 ;
     RECT  2.704 69.504 3.539 70.104 ;
     RECT  2.704 38.688 3.685 38.712 ;
     RECT  3.443 75.936 3.701 76.92 ;
     RECT  2.704 23.712 3.769 23.736 ;
     RECT  2.704 40.944 3.769 40.968 ;
     RECT  2.704 63.84 3.779 63.864 ;
     RECT  3.733 62.736 3.82 62.76 ;
     RECT  2.704 13.68 3.841 13.704 ;
     RECT  3.685 38.688 3.841 38.808 ;
     RECT  2.704 27.216 3.913 27.912 ;
     RECT  2.704 58.128 3.913 58.44 ;
     RECT  2.704 5.088 3.923 5.112 ;
     RECT  3.913 58.128 3.925 58.68 ;
     RECT  3.769 23.712 3.949 24.6 ;
     RECT  3.841 53.04 3.949 53.064 ;
     RECT  3.877 6.816 3.964 6.984 ;
     RECT  2.704 29.76 4.057 29.784 ;
     RECT  3.964 6.96 4.061 6.984 ;
     RECT  3.913 27.216 4.093 28.776 ;
     RECT  4.057 29.76 4.093 30.408 ;
     RECT  3.841 96.288 4.129 96.312 ;
     RECT  3.949 23.376 4.133 24.6 ;
     RECT  2.704 61.536 4.165 61.56 ;
     RECT  4.093 27.216 4.169 30.408 ;
     RECT  2.704 81.456 4.172 81.48 ;
     RECT  4.172 81.456 4.213 81.576 ;
     RECT  4.169 28.272 4.237 30.408 ;
     RECT  2.801 56.448 4.237 56.472 ;
     RECT  4.213 80.784 4.259 81.576 ;
     RECT  2.704 107.136 4.261 107.16 ;
     RECT  2.704 68.352 4.273 68.376 ;
     RECT  4.261 107.136 4.273 108.072 ;
     RECT  4.273 107.136 4.307 108.744 ;
     RECT  3.697 22.176 4.309 22.2 ;
     RECT  3.769 40.464 4.309 40.968 ;
     RECT  4.165 61.008 4.309 61.56 ;
     RECT  4.273 67.776 4.313 68.376 ;
     RECT  4.307 108.048 4.348 108.744 ;
     RECT  4.237 55.872 4.355 56.472 ;
     RECT  3.244 34.08 4.381 34.968 ;
     RECT  4.201 35.952 4.381 35.976 ;
     RECT  4.309 74.688 4.393 74.712 ;
     RECT  2.704 46.368 4.417 47.352 ;
     RECT  2.704 48.48 4.417 48.504 ;
     RECT  4.169 27.216 4.421 27.24 ;
     RECT  3.841 38.688 4.453 39.24 ;
     RECT  4.309 40.464 4.453 41.064 ;
     RECT  2.704 12.48 4.489 12.504 ;
     RECT  4.309 22.176 4.489 22.248 ;
     RECT  4.417 100.224 4.489 100.248 ;
     RECT  4.417 14.832 4.501 14.856 ;
     RECT  2.704 37.44 4.501 37.464 ;
     RECT  4.453 38.688 4.501 41.064 ;
     RECT  4.501 20.496 4.525 20.52 ;
     RECT  4.501 37.44 4.547 41.064 ;
     RECT  4.489 11.952 4.549 12.504 ;
     RECT  3.841 13.68 4.549 13.752 ;
     RECT  3.925 58.128 4.556 58.824 ;
     RECT  4.489 82.032 4.573 82.056 ;
     RECT  4.547 37.44 4.593 38.808 ;
     RECT  4.549 11.952 4.595 13.752 ;
     RECT  4.489 100.224 4.595 100.296 ;
     RECT  4.595 12.72 4.601 13.752 ;
     RECT  4.549 101.28 4.636 101.304 ;
     RECT  4.601 12.72 4.637 13.704 ;
     RECT  4.556 58.128 4.643 59.784 ;
     RECT  2.704 85.488 4.652 85.512 ;
     RECT  3.769 86.928 4.652 86.952 ;
     RECT  3.733 50.112 4.669 50.136 ;
     RECT  2.704 51.312 4.669 51.336 ;
     RECT  4.643 58.128 4.669 59.256 ;
     RECT  4.093 78.432 4.669 78.456 ;
     RECT  4.652 85.488 4.693 86.952 ;
     RECT  4.417 46.368 4.705 48.504 ;
     RECT  4.525 20.496 4.709 20.616 ;
     RECT  4.669 50.112 4.709 51.336 ;
     RECT  2.765 83.184 4.709 83.208 ;
     RECT  4.693 84.96 4.739 86.952 ;
     RECT  2.704 26.208 4.813 26.232 ;
     RECT  4.309 61.008 4.813 61.8 ;
     RECT  3.949 19.392 4.817 19.416 ;
     RECT  4.309 4.704 4.835 4.728 ;
     RECT  4.709 20.592 4.885 20.616 ;
     RECT  4.489 21.936 4.885 22.248 ;
     RECT  3.841 43.344 4.885 43.368 ;
     RECT  2.704 44.448 4.885 44.472 ;
     RECT  4.813 60.864 4.885 61.8 ;
     RECT  4.237 28.272 4.921 30.84 ;
     RECT  3.769 32.016 4.921 32.424 ;
     RECT  4.381 34.08 4.921 35.976 ;
     RECT  4.885 60.864 4.931 62.136 ;
     RECT  4.921 33.6 4.961 35.976 ;
     RECT  4.133 24.528 4.993 24.6 ;
     RECT  4.813 26.208 4.993 26.52 ;
     RECT  3.877 118.752 4.997 118.776 ;
     RECT  4.355 55.872 5.033 56.328 ;
     RECT  4.313 67.776 5.033 67.8 ;
     RECT  4.705 8.016 5.057 8.04 ;
     RECT  4.525 97.632 5.057 97.656 ;
     RECT  5.029 98.736 5.057 98.76 ;
     RECT  4.133 23.376 5.065 23.4 ;
     RECT  4.931 62.112 5.065 62.136 ;
     RECT  5.057 8.016 5.077 8.088 ;
     RECT  2.704 42.192 5.077 42.216 ;
     RECT  4.885 43.344 5.077 44.472 ;
     RECT  4.309 9.408 5.093 9.432 ;
     RECT  4.921 10.752 5.093 10.776 ;
     RECT  5.057 97.632 5.101 98.76 ;
     RECT  3.701 75.936 5.125 75.96 ;
     RECT  5.077 7.344 5.141 8.088 ;
     RECT  4.931 60.864 5.141 61.128 ;
     RECT  5.093 9.408 5.171 10.776 ;
     RECT  5.125 75.264 5.171 75.96 ;
     RECT  4.921 28.272 5.173 32.424 ;
     RECT  4.961 33.6 5.173 33.624 ;
     RECT  5.171 10.272 5.177 10.776 ;
     RECT  4.789 15.408 5.177 15.432 ;
     RECT  5.033 55.872 5.177 55.944 ;
     RECT  4.885 20.592 5.209 22.248 ;
     RECT  5.065 23.328 5.209 23.4 ;
     RECT  4.705 45.84 5.209 48.504 ;
     RECT  5.101 49.536 5.209 49.56 ;
     RECT  4.547 39.792 5.212 41.064 ;
     RECT  5.077 42.192 5.249 44.472 ;
     RECT  5.209 45.84 5.249 49.56 ;
     RECT  5.209 20.592 5.276 23.4 ;
     RECT  4.993 24.528 5.276 26.52 ;
     RECT  4.739 86.928 5.281 86.952 ;
     RECT  5.201 9.12 5.285 9.144 ;
     RECT  5.281 86.928 5.321 87.24 ;
     RECT  3.949 52.464 5.357 53.064 ;
     RECT  2.704 89.424 5.389 89.448 ;
     RECT  5.276 20.592 5.413 26.52 ;
     RECT  5.173 28.272 5.413 33.624 ;
     RECT  4.961 34.944 5.429 35.976 ;
     RECT  5.212 40.368 5.429 41.064 ;
     RECT  5.125 76.944 5.429 76.968 ;
     RECT  4.525 123.12 5.429 123.144 ;
     RECT  4.741 17.856 5.461 17.88 ;
     RECT  5.389 88.608 5.461 89.448 ;
     RECT  4.593 38.112 5.465 38.808 ;
     RECT  5.177 10.752 5.497 10.776 ;
     RECT  5.461 88.608 5.501 90.072 ;
     RECT  4.693 103.92 5.509 103.944 ;
     RECT  4.652 105.792 5.533 105.816 ;
     RECT  4.655 106.992 5.533 107.016 ;
     RECT  5.249 48.288 5.555 49.56 ;
     RECT  4.489 63.888 5.605 63.912 ;
     RECT  4.525 65.28 5.605 65.304 ;
     RECT  5.533 105.792 5.605 107.016 ;
     RECT  5.101 97.632 5.609 99.192 ;
     RECT  5.429 35.28 5.641 35.976 ;
     RECT  5.065 62.112 5.641 62.52 ;
     RECT  5.605 63.888 5.641 65.304 ;
     RECT  3.539 70.08 5.645 70.104 ;
     RECT  5.497 10.752 5.677 11.448 ;
     RECT  5.413 20.592 5.681 33.624 ;
     RECT  5.177 55.872 5.681 55.896 ;
     RECT  5.389 115.152 5.701 115.176 ;
     RECT  4.669 57.888 5.708 59.256 ;
     RECT  5.141 60.864 5.708 60.888 ;
     RECT  5.701 114.48 5.708 115.176 ;
     RECT  5.641 35.28 5.713 36.408 ;
     RECT  5.249 42.192 5.713 42.792 ;
     RECT  5.609 98.544 5.713 99.192 ;
     RECT  4.595 100.224 5.713 100.248 ;
     RECT  5.708 114.48 5.747 116.04 ;
     RECT  4.709 50.832 5.749 51.336 ;
     RECT  5.357 52.464 5.749 53.016 ;
     RECT  4.259 80.784 5.749 80.808 ;
     RECT  5.533 120.816 5.749 120.84 ;
     RECT  5.101 121.824 5.749 121.848 ;
     RECT  5.641 62.112 5.789 65.304 ;
     RECT  5.171 75.264 5.789 75.288 ;
     RECT  5.749 80.496 5.789 80.808 ;
     RECT  5.708 57.888 5.795 60.888 ;
     RECT  5.747 116.016 5.795 116.04 ;
     RECT  5.555 48.384 5.821 49.56 ;
     RECT  5.749 50.832 5.821 53.016 ;
     RECT  5.677 10.752 5.843 11.976 ;
     RECT  4.129 95.712 5.852 96.312 ;
     RECT  5.605 105.408 5.861 107.016 ;
     RECT  5.795 57.888 5.893 59.544 ;
     RECT  4.669 78.096 5.893 78.456 ;
     RECT  5.245 93.36 5.893 93.384 ;
     RECT  5.509 103.92 5.893 104.04 ;
     RECT  5.461 17.856 5.897 18.792 ;
     RECT  5.501 89.616 5.897 90.072 ;
     RECT  5.852 95.568 5.939 96.312 ;
     RECT  4.637 13.584 5.941 13.704 ;
     RECT  4.741 16.656 5.965 16.68 ;
     RECT  5.939 95.856 5.965 96.312 ;
     RECT  5.425 118.992 5.965 119.016 ;
     RECT  5.861 106.128 5.969 107.016 ;
     RECT  5.941 13.584 6.028 14.376 ;
     RECT  5.969 106.464 6.073 107.016 ;
     RECT  5.681 20.592 6.077 33.336 ;
     RECT  5.965 95.856 6.083 97.128 ;
     RECT  5.065 71.472 6.145 71.496 ;
     RECT  5.749 120.816 6.145 121.848 ;
     RECT  5.141 7.344 6.149 8.04 ;
     RECT  5.749 117.408 6.181 117.432 ;
     RECT  6.145 71.472 6.185 71.976 ;
     RECT  5.893 57.024 6.217 59.544 ;
     RECT  5.893 93.36 6.217 93.48 ;
     RECT  6.037 94.56 6.217 94.584 ;
     RECT  5.321 87.216 6.221 87.24 ;
     RECT  4.669 112.128 6.221 112.152 ;
     RECT  6.145 120.72 6.221 121.848 ;
     RECT  6.109 15.456 6.253 15.48 ;
     RECT  5.965 16.56 6.253 16.68 ;
     RECT  5.795 60.672 6.253 60.888 ;
     RECT  5.789 62.112 6.253 65.016 ;
     RECT  6.253 20.16 6.277 20.184 ;
     RECT  5.965 118.992 6.277 119.688 ;
     RECT  6.221 120.72 6.277 120.744 ;
     RECT  6.149 7.968 6.293 8.04 ;
     RECT  6.028 13.584 6.293 13.704 ;
     RECT  6.077 21.552 6.293 33.336 ;
     RECT  6.217 55.248 6.301 55.368 ;
     RECT  5.897 18.144 6.325 18.792 ;
     RECT  6.277 19.776 6.325 20.184 ;
     RECT  6.073 106.464 6.325 107.544 ;
     RECT  4.348 108.72 6.325 108.744 ;
     RECT  5.713 42 6.329 42.792 ;
     RECT  5.501 88.608 6.361 88.632 ;
     RECT  6.293 21.552 6.365 27.384 ;
     RECT  6.325 108.72 6.371 108.984 ;
     RECT  5.713 98.544 6.397 100.248 ;
     RECT  6.253 15.456 6.428 16.68 ;
     RECT  6.217 93.36 6.505 94.584 ;
     RECT  6.293 32.304 6.509 33.336 ;
     RECT  6.428 14.784 6.515 16.68 ;
     RECT  5.821 48.384 6.545 53.016 ;
     RECT  6.277 118.992 6.545 120.744 ;
     RECT  6.083 95.904 6.563 97.128 ;
     RECT  6.397 98.544 6.565 100.92 ;
     RECT  6.505 102.048 6.565 102.072 ;
     RECT  4.739 84.96 6.581 84.984 ;
     RECT  6.565 98.544 6.604 102.072 ;
     RECT  6.505 92.688 6.613 94.584 ;
     RECT  5.893 103.872 6.613 104.04 ;
     RECT  6.325 106.464 6.649 107.592 ;
     RECT  5.249 44.112 6.653 44.472 ;
     RECT  6.613 92.688 6.653 94.728 ;
     RECT  6.604 98.592 6.707 102.072 ;
     RECT  6.361 87.792 6.721 88.632 ;
     RECT  5.897 89.616 6.721 89.64 ;
     RECT  6.613 103.488 6.721 104.04 ;
     RECT  6.649 106.464 6.733 107.784 ;
     RECT  6.653 94.56 6.755 94.728 ;
     RECT  6.721 87.792 6.761 89.64 ;
     RECT  6.563 97.104 6.793 97.128 ;
     RECT  6.721 103.488 6.793 104.328 ;
     RECT  5.249 45.84 6.829 47.304 ;
     RECT  6.545 48.384 6.829 48.456 ;
     RECT  5.747 114.48 6.829 114.6 ;
     RECT  6.509 32.4 6.833 33.336 ;
     RECT  6.793 103.488 6.865 104.424 ;
     RECT  6.707 100.896 6.901 102.072 ;
     RECT  6.865 103.152 6.901 104.424 ;
     RECT  6.833 33.072 6.937 33.336 ;
     RECT  6.545 49.488 6.937 53.016 ;
     RECT  2.704 54.048 6.937 54.072 ;
     RECT  5.533 39.36 6.949 39.384 ;
     RECT  5.429 40.368 6.949 40.392 ;
     RECT  4.268 73.488 6.973 73.512 ;
     RECT  6.221 121.824 6.973 121.848 ;
     RECT  6.653 92.688 7.004 93.48 ;
     RECT  6.217 56.832 7.009 59.544 ;
     RECT  6.253 60.672 7.009 65.016 ;
     RECT  6.937 33.072 7.045 33.672 ;
     RECT  5.713 35.28 7.045 36.456 ;
     RECT  6.515 16.56 7.148 16.68 ;
     RECT  6.325 18.144 7.148 20.184 ;
     RECT  6.653 44.112 7.153 44.376 ;
     RECT  6.301 55.344 7.153 55.368 ;
     RECT  7.009 56.832 7.153 65.016 ;
     RECT  6.761 89.52 7.225 89.64 ;
     RECT  7.117 111.792 7.225 111.816 ;
     RECT  5.789 80.496 7.244 80.52 ;
     RECT  6.949 39.36 7.261 40.392 ;
     RECT  7.004 92.304 7.261 93.48 ;
     RECT  7.045 33.072 7.297 36.456 ;
     RECT  6.329 42 7.297 42.216 ;
     RECT  7.153 43.776 7.297 44.376 ;
     RECT  6.365 21.552 7.333 27.288 ;
     RECT  7.153 55.344 7.333 55.416 ;
     RECT  6.185 71.952 7.34 71.976 ;
     RECT  6.973 73.488 7.34 74.088 ;
     RECT  5.465 38.112 7.381 38.232 ;
     RECT  6.371 108.96 7.405 108.984 ;
     RECT  6.545 119.088 7.441 120.744 ;
     RECT  6.973 121.824 7.441 122.136 ;
     RECT  7.225 89.52 7.513 89.976 ;
     RECT  7.261 91.344 7.513 93.48 ;
     RECT  7.244 80.496 7.525 80.712 ;
     RECT  7.381 37.68 7.549 38.232 ;
     RECT  7.261 39.36 7.549 40.44 ;
     RECT  7.333 21.552 7.573 27.336 ;
     RECT  7.549 37.68 7.621 40.44 ;
     RECT  7.297 42 7.621 44.376 ;
     RECT  7.333 55.344 7.657 55.464 ;
     RECT  7.573 21.216 7.669 27.336 ;
     RECT  6.293 28.368 7.669 31.176 ;
     RECT  7.621 37.68 7.669 44.376 ;
     RECT  6.829 45.84 7.669 48.456 ;
     RECT  7.405 108.96 7.669 109.176 ;
     RECT  7.669 21.216 7.693 31.176 ;
     RECT  7.669 37.68 7.765 48.456 ;
     RECT  6.937 49.488 7.765 54.072 ;
     RECT  6.661 8.496 7.808 8.52 ;
     RECT  5.843 11.424 7.808 11.976 ;
     RECT  6.293 13.584 7.808 13.608 ;
     RECT  6.515 14.784 7.808 15.48 ;
     RECT  7.148 16.56 7.808 20.184 ;
     RECT  7.693 21.216 7.808 31.416 ;
     RECT  7.297 33.072 7.808 36.696 ;
     RECT  7.765 37.68 7.808 54.072 ;
     RECT  7.657 55.248 7.808 55.464 ;
     RECT  7.153 56.832 7.808 65.544 ;
     RECT  6.001 66.528 7.808 66.552 ;
     RECT  7.045 67.68 7.808 67.704 ;
     RECT  6.397 68.928 7.808 68.952 ;
     RECT  5.785 70.416 7.808 70.44 ;
     RECT  7.34 71.952 7.808 74.088 ;
     RECT  5.893 77.28 7.808 78.456 ;
     RECT  7.525 80.496 7.808 81.288 ;
     RECT  7.621 86.784 7.808 86.808 ;
     RECT  6.761 87.792 7.808 88.152 ;
     RECT  7.513 89.52 7.808 93.48 ;
     RECT  6.755 94.56 7.808 94.632 ;
     RECT  6.563 95.904 7.808 95.928 ;
     RECT  6.793 97.104 7.808 97.56 ;
     RECT  6.707 98.592 7.808 99.72 ;
     RECT  6.901 100.896 7.808 104.424 ;
     RECT  6.733 106.464 7.808 107.592 ;
     RECT  7.669 108.864 7.808 109.176 ;
     RECT  7.225 111.792 7.808 111.864 ;
     RECT  6.829 114 7.808 114.6 ;
     RECT  6.181 117.408 7.808 118.008 ;
     RECT  7.441 119.088 7.808 122.136 ;
     RECT  6.937 125.424 7.808 125.448 ;
     RECT  7.808 2.148 7.912 127.452 ;
     RECT  7.912 2.418 8.104 127.182 ;
     RECT  8.104 121.824 8.165 122.136 ;
     RECT  8.104 30.576 8.201 31.944 ;
     RECT  8.104 76.944 8.237 77.304 ;
     RECT  8.104 15.84 8.243 17.112 ;
     RECT  8.104 52.368 8.339 63.912 ;
     RECT  8.104 100.896 8.339 105.432 ;
     RECT  8.104 42.576 8.345 51.384 ;
     RECT  8.104 89.424 8.345 90.984 ;
     RECT  8.339 52.368 8.381 59.256 ;
     RECT  8.104 115.728 8.389 115.752 ;
     RECT  8.339 101.04 8.417 105.432 ;
     RECT  8.104 114.144 8.428 114.6 ;
     RECT  8.104 33.024 8.453 38.808 ;
     RECT  8.381 52.368 8.489 55.32 ;
     RECT  8.104 80.448 8.531 81.48 ;
     RECT  8.104 99.168 8.531 99.48 ;
     RECT  8.104 106.464 8.531 108.168 ;
     RECT  8.104 39.792 8.627 41.544 ;
     RECT  8.345 42.576 8.633 51.288 ;
     RECT  8.104 64.944 8.633 67.704 ;
     RECT  8.345 90.96 8.705 90.984 ;
     RECT  8.531 107.04 8.777 108.168 ;
     RECT  8.489 52.368 8.819 53.064 ;
     RECT  8.531 80.448 8.849 80.568 ;
     RECT  8.104 116.88 8.857 118.584 ;
     RECT  8.633 42.576 8.867 49.08 ;
     RECT  8.849 80.448 8.867 80.472 ;
     RECT  8.165 121.968 8.867 122.136 ;
     RECT  8.104 25.248 8.921 29.064 ;
     RECT  8.104 109.152 8.963 109.464 ;
     RECT  8.867 42.576 9.029 46.776 ;
     RECT  8.921 25.296 9.065 29.064 ;
     RECT  8.104 72.144 9.097 72.168 ;
     RECT  8.104 69.456 9.101 70.536 ;
     RECT  9.101 69.456 9.133 69.768 ;
     RECT  8.453 33.168 9.137 38.808 ;
     RECT  8.867 47.856 9.137 49.08 ;
     RECT  8.104 21.936 9.169 22.92 ;
     RECT  8.201 30.624 9.173 31.944 ;
     RECT  9.097 72.144 9.205 72.264 ;
     RECT  9.169 21.072 9.209 22.92 ;
     RECT  9.029 42.576 9.209 46.728 ;
     RECT  9.137 48.96 9.209 49.08 ;
     RECT  9.209 42.576 9.245 43.272 ;
     RECT  8.381 56.4 9.245 59.256 ;
     RECT  8.104 73.488 9.245 74.616 ;
     RECT  9.137 33.168 9.281 38.136 ;
     RECT  9.133 69.024 9.281 69.768 ;
     RECT  8.104 119.664 9.313 120.84 ;
     RECT  8.867 121.968 9.313 121.992 ;
     RECT  9.313 119.664 9.317 121.992 ;
     RECT  8.104 92.688 9.349 93.384 ;
     RECT  9.245 42.768 9.353 43.272 ;
     RECT  8.339 60.24 9.353 63.912 ;
     RECT  9.281 69.456 9.353 69.768 ;
     RECT  8.417 101.136 9.397 105.432 ;
     RECT  8.489 54.48 9.413 55.32 ;
     RECT  9.245 56.4 9.413 58.2 ;
     RECT  8.104 87.792 9.457 88.152 ;
     RECT  8.345 89.424 9.457 89.832 ;
     RECT  8.857 116.88 9.457 118.344 ;
     RECT  9.349 91.824 9.461 93.384 ;
     RECT  8.627 39.792 9.493 40.632 ;
     RECT  9.173 30.624 9.497 30.936 ;
     RECT  9.353 60.24 9.569 60.408 ;
     RECT  9.457 116.736 9.569 118.344 ;
     RECT  9.209 49.056 9.605 49.08 ;
     RECT  8.633 64.944 9.605 67.368 ;
     RECT  9.137 47.856 9.628 47.88 ;
     RECT  9.457 87.792 9.637 89.832 ;
     RECT  9.397 101.136 9.637 105.672 ;
     RECT  9.413 54.48 9.641 58.2 ;
     RECT  9.461 91.824 9.641 91.848 ;
     RECT  9.569 116.736 9.677 116.904 ;
     RECT  9.353 61.392 9.709 63.912 ;
     RECT  9.605 64.944 9.709 66.552 ;
     RECT  8.633 50.208 9.713 51.288 ;
     RECT  9.637 87.792 9.721 90.072 ;
     RECT  9.245 74.592 9.733 74.616 ;
     RECT  9.281 36.096 9.749 38.136 ;
     RECT  8.237 76.944 9.779 76.968 ;
     RECT  9.209 44.448 9.893 46.728 ;
     RECT  9.493 39.36 9.925 40.632 ;
     RECT  9.173 31.92 9.961 31.944 ;
     RECT  9.281 33.168 9.961 35.112 ;
     RECT  9.749 36.096 9.965 36.12 ;
     RECT  8.819 53.04 9.997 53.064 ;
     RECT  9.569 118.32 9.997 118.344 ;
     RECT  9.317 119.664 9.997 119.688 ;
     RECT  8.777 107.04 10.001 107.88 ;
     RECT  9.713 51.264 10.021 51.288 ;
     RECT  9.997 52.416 10.021 53.064 ;
     RECT  9.997 118.32 10.037 119.688 ;
     RECT  9.961 31.92 10.073 35.112 ;
     RECT  9.925 39.36 10.109 41.592 ;
     RECT  10.001 107.04 10.109 107.544 ;
     RECT  9.853 91.584 10.141 91.608 ;
     RECT  9.205 72 10.145 72.264 ;
     RECT  9.749 37.392 10.165 38.136 ;
     RECT  10.109 39.36 10.165 40.44 ;
     RECT  8.104 20.016 10.249 20.04 ;
     RECT  9.209 21.072 10.249 22.584 ;
     RECT  10.073 31.92 10.253 35.064 ;
     RECT  10.037 118.32 10.253 119.16 ;
     RECT  9.065 25.296 10.285 28.968 ;
     RECT  9.709 61.392 10.289 66.552 ;
     RECT  10.165 37.392 10.3 40.44 ;
     RECT  10.253 33.504 10.325 35.064 ;
     RECT  9.245 73.488 10.361 73.512 ;
     RECT  10.109 41.568 10.393 41.592 ;
     RECT  10.393 41.568 10.433 41.688 ;
     RECT  10.289 62.208 10.444 66.552 ;
     RECT  10.429 59.232 10.46 59.256 ;
     RECT  10.46 59.184 10.465 59.256 ;
     RECT  9.317 121.056 10.465 121.992 ;
     RECT  10.325 34.08 10.469 35.064 ;
     RECT  9.637 100.8 10.469 105.672 ;
     RECT  9.641 54.48 10.501 56.424 ;
     RECT  10.469 101.136 10.505 105.672 ;
     RECT  10.285 24.672 10.537 28.968 ;
     RECT  9.721 87.792 10.541 89.496 ;
     RECT  8.104 78.432 10.549 78.456 ;
     RECT  9.641 57.456 10.556 58.2 ;
     RECT  10.465 59.184 10.556 60.024 ;
     RECT  9.497 30.912 10.573 30.936 ;
     RECT  10.253 31.92 10.573 31.944 ;
     RECT  10.3 37.392 10.595 39.384 ;
     RECT  8.104 95.904 10.595 95.928 ;
     RECT  10.549 78.336 10.609 78.456 ;
     RECT  10.556 57.456 10.643 60.024 ;
     RECT  10.249 20.016 10.649 22.584 ;
     RECT  9.677 116.736 10.681 116.76 ;
     RECT  10.609 78.336 10.693 78.648 ;
     RECT  10.643 59.232 10.709 60.024 ;
     RECT  10.357 61.008 10.709 61.224 ;
     RECT  10.141 91.44 10.717 91.608 ;
     RECT  10.595 37.392 10.789 38.136 ;
     RECT  8.428 114.144 10.789 114.168 ;
     RECT  10.789 114.096 10.79 114.168 ;
     RECT  10.501 54.384 10.793 56.424 ;
     RECT  10.709 59.232 10.793 61.224 ;
     RECT  10.649 20.016 10.825 20.376 ;
     RECT  10.649 21.648 10.825 22.584 ;
     RECT  10.505 105.408 10.825 105.672 ;
     RECT  10.793 60 10.829 61.224 ;
     RECT  10.573 30.912 10.833 31.944 ;
     RECT  9.353 42.768 10.837 42.792 ;
     RECT  10.145 72.048 10.861 72.264 ;
     RECT  10.429 73.44 10.861 73.464 ;
     RECT  10.021 51.264 10.865 53.064 ;
     RECT  10.595 39.216 10.901 39.384 ;
     RECT  10.825 105.408 10.909 105.816 ;
     RECT  10.837 42.768 10.924 43.368 ;
     RECT  8.243 16.56 10.933 17.112 ;
     RECT  10.825 18.96 10.933 20.376 ;
     RECT  10.693 78.336 10.937 78.456 ;
     RECT  10.789 37.152 10.973 38.136 ;
     RECT  10.901 39.312 10.973 39.384 ;
     RECT  10.933 16.416 10.979 17.112 ;
     RECT  10.979 16.416 11.02 16.584 ;
     RECT  9.893 44.736 11.029 46.728 ;
     RECT  10.505 101.136 11.045 104.088 ;
     RECT  9.713 50.208 11.075 50.232 ;
     RECT  10.865 51.888 11.075 53.064 ;
     RECT  10.3 40.416 11.077 40.44 ;
     RECT  11.02 16.56 11.081 16.584 ;
     RECT  10.933 18.24 11.081 20.376 ;
     RECT  10.825 21.648 11.081 23.304 ;
     RECT  11.077 40.416 11.081 40.584 ;
     RECT  10.973 37.248 11.117 38.136 ;
     RECT  11.117 37.488 11.123 38.136 ;
     RECT  10.433 41.616 11.123 41.688 ;
     RECT  10.109 107.52 11.123 107.544 ;
     RECT  9.461 92.928 11.132 93.384 ;
     RECT  10.717 90.528 11.149 91.608 ;
     RECT  11.132 92.928 11.149 93.432 ;
     RECT  10.973 39.36 11.153 39.384 ;
     RECT  11.029 44.352 11.153 46.728 ;
     RECT  10.909 105.408 11.153 105.672 ;
     RECT  10.253 119.136 11.153 119.16 ;
     RECT  10.537 24.672 11.189 29.016 ;
     RECT  10.643 57.456 11.189 58.2 ;
     RECT  10.541 87.792 11.219 89.448 ;
     RECT  8.963 109.152 11.267 109.176 ;
     RECT  11.123 41.664 11.293 41.688 ;
     RECT  10.924 42.768 11.293 43.32 ;
     RECT  10.861 72.048 11.293 73.464 ;
     RECT  10.681 116.736 11.297 117.912 ;
     RECT  11.293 41.664 11.333 43.32 ;
     RECT  11.293 71.952 11.337 73.464 ;
     RECT  11.149 90.528 11.365 93.432 ;
     RECT  8.104 94.56 11.365 94.584 ;
     RECT  11.081 21.648 11.369 22.584 ;
     RECT  11.153 44.352 11.369 46.152 ;
     RECT  11.297 117.888 11.369 117.912 ;
     RECT  11.365 90.528 11.411 94.584 ;
     RECT  8.104 110.496 11.413 110.52 ;
     RECT  10.79 114.096 11.413 114.12 ;
     RECT  11.297 116.736 11.441 116.76 ;
     RECT  10.465 121.008 11.441 121.992 ;
     RECT  11.369 44.352 11.459 45.816 ;
     RECT  11.413 113.808 11.459 114.12 ;
     RECT  11.411 90.528 11.477 93.672 ;
     RECT  10.793 54.432 11.509 56.424 ;
     RECT  11.189 57.456 11.509 57.864 ;
     RECT  11.219 88.08 11.513 89.448 ;
     RECT  10.829 60.48 11.545 61.224 ;
     RECT  10.444 62.304 11.545 66.552 ;
     RECT  11.123 37.488 11.549 38.088 ;
     RECT  11.545 60.48 11.629 66.552 ;
     RECT  10.469 34.368 11.657 35.064 ;
     RECT  11.459 44.352 11.657 44.472 ;
     RECT  11.075 52.416 11.689 53.064 ;
     RECT  11.689 52.416 11.833 53.352 ;
     RECT  11.509 54.432 11.833 57.864 ;
     RECT  11.756 116.688 11.843 116.712 ;
     RECT  10.833 30.192 11.893 31.944 ;
     RECT  11.833 52.416 11.909 57.864 ;
     RECT  11.629 60.48 11.941 60.6 ;
     RECT  11.893 30.192 11.98 33.672 ;
     RECT  11.333 42.144 12.013 43.32 ;
     RECT  11.657 44.352 12.013 44.376 ;
     RECT  11.98 30.192 12.017 31.944 ;
     RECT  12.013 42.144 12.017 44.376 ;
     RECT  11.081 18.48 12.085 20.376 ;
     RECT  12.017 42.144 12.125 43.656 ;
     RECT  11.189 25.728 12.193 29.016 ;
     RECT  12.017 30.192 12.193 31.416 ;
     RECT  11.909 57.312 12.229 57.864 ;
     RECT  11.941 60 12.229 60.6 ;
     RECT  11.549 37.68 12.265 38.088 ;
     RECT  12.157 70.656 12.373 70.68 ;
     RECT  11.337 71.952 12.373 73.512 ;
     RECT  12.085 18.48 12.409 20.952 ;
     RECT  11.369 21.984 12.409 22.584 ;
     RECT  12.265 37.68 12.517 38.184 ;
     RECT  11.629 61.632 12.553 66.552 ;
     RECT  12.481 67.584 12.553 67.608 ;
     RECT  8.531 99.408 12.589 99.48 ;
     RECT  12.037 51.216 12.625 51.432 ;
     RECT  11.98 33.6 12.661 33.672 ;
     RECT  11.657 35.04 12.661 35.064 ;
     RECT  9.353 69.456 12.697 69.48 ;
     RECT  11.513 89.424 12.733 89.448 ;
     RECT  11.477 90.528 12.733 93.384 ;
     RECT  10.393 49.104 12.769 49.128 ;
     RECT  12.769 47.424 12.841 47.448 ;
     RECT  11.459 45.696 12.901 45.816 ;
     RECT  12.625 50.928 12.913 51.432 ;
     RECT  11.909 52.416 12.913 56.28 ;
     RECT  12.373 70.656 12.949 73.512 ;
     RECT  12.661 33.6 12.985 35.064 ;
     RECT  12.949 70.56 13.045 73.512 ;
     RECT  9.733 74.592 13.045 75.192 ;
     RECT  12.229 57.312 13.052 60.6 ;
     RECT  12.553 61.632 13.052 67.608 ;
     RECT  11.189 24.672 13.057 24.696 ;
     RECT  12.841 47.424 13.057 47.88 ;
     RECT  13.057 24.144 13.093 24.696 ;
     RECT  12.193 25.728 13.093 31.416 ;
     RECT  12.517 41.616 13.093 41.64 ;
     RECT  12.125 42.72 13.093 43.656 ;
     RECT  12.901 44.976 13.093 45.816 ;
     RECT  13.057 47.328 13.093 47.88 ;
     RECT  12.913 50.928 13.093 56.28 ;
     RECT  13.052 57.312 13.093 67.608 ;
     RECT  13.093 24.144 13.165 31.416 ;
     RECT  12.517 36.816 13.165 38.184 ;
     RECT  12.409 18.48 13.208 22.584 ;
     RECT  13.165 24.144 13.208 31.8 ;
     RECT  12.985 33.024 13.208 35.064 ;
     RECT  13.165 36.816 13.208 39.096 ;
     RECT  11.081 40.56 13.208 40.584 ;
     RECT  13.093 41.616 13.208 43.656 ;
     RECT  13.093 44.976 13.208 47.88 ;
     RECT  12.769 49.008 13.208 49.128 ;
     RECT  13.093 50.928 13.208 67.608 ;
     RECT  12.697 69.216 13.208 69.48 ;
     RECT  13.045 70.56 13.208 75.192 ;
     RECT  10.937 78.432 13.208 78.456 ;
     RECT  10.549 82.128 13.208 82.152 ;
     RECT  11.513 88.08 13.208 88.152 ;
     RECT  12.733 89.424 13.208 93.384 ;
     RECT  8.104 97.536 13.208 97.56 ;
     RECT  12.589 99.408 13.208 100.008 ;
     RECT  11.045 101.136 13.208 104.04 ;
     RECT  11.153 105.408 13.208 105.432 ;
     RECT  11.413 110.496 13.208 111.144 ;
     RECT  11.459 113.808 13.208 113.88 ;
     RECT  11.221 118.992 13.208 119.016 ;
     RECT  11.441 121.008 13.208 121.032 ;
     RECT  13.208 2.148 13.312 127.452 ;
     RECT  13.312 2.418 13.504 127.182 ;
     RECT  13.504 113.712 13.529 113.88 ;
     RECT  13.504 29.28 13.565 35.064 ;
     RECT  13.504 42 13.601 50.088 ;
     RECT  13.504 18.48 13.619 24.36 ;
     RECT  13.504 51.312 13.619 58.584 ;
     RECT  13.504 88.08 13.619 91.848 ;
     RECT  13.504 111.6 13.619 111.624 ;
     RECT  13.565 33.552 13.667 35.064 ;
     RECT  13.619 88.08 13.709 89.448 ;
     RECT  13.619 91.44 13.709 91.848 ;
     RECT  13.601 44.448 13.781 50.088 ;
     RECT  13.619 18.48 13.907 23.4 ;
     RECT  13.907 18.48 13.955 22.056 ;
     RECT  13.601 42 14.069 42.984 ;
     RECT  13.504 62.304 14.195 67.8 ;
     RECT  13.504 68.832 14.195 69.48 ;
     RECT  13.504 40.464 14.213 40.584 ;
     RECT  13.504 36.432 14.321 36.456 ;
     RECT  13.504 74.592 14.321 74.616 ;
     RECT  13.781 44.448 14.465 47.448 ;
     RECT  14.213 40.56 14.569 40.584 ;
     RECT  13.504 37.488 14.573 39.096 ;
     RECT  14.069 42.192 14.605 42.984 ;
     RECT  13.504 60.048 14.605 60.936 ;
     RECT  14.195 62.304 14.605 67.272 ;
     RECT  13.565 29.28 14.641 32.088 ;
     RECT  13.667 33.552 14.641 33.624 ;
     RECT  14.641 29.28 14.677 33.624 ;
     RECT  13.667 34.704 14.677 35.064 ;
     RECT  13.504 25.776 14.681 27.72 ;
     RECT  14.677 29.232 14.713 35.064 ;
     RECT  14.681 25.776 14.717 26.136 ;
     RECT  14.605 42.192 14.717 43.32 ;
     RECT  13.619 55.248 14.749 58.584 ;
     RECT  13.504 72.48 14.78 73.56 ;
     RECT  13.781 48.432 14.785 50.088 ;
     RECT  14.465 44.64 14.789 47.448 ;
     RECT  14.78 72 14.821 73.56 ;
     RECT  14.573 37.488 14.825 38.904 ;
     RECT  14.785 48.432 14.825 50.184 ;
     RECT  14.825 49.44 14.857 50.184 ;
     RECT  14.821 71.808 14.861 73.56 ;
     RECT  13.504 92.928 14.861 93.384 ;
     RECT  13.504 99.408 14.861 100.008 ;
     RECT  14.861 71.808 14.867 72.024 ;
     RECT  14.857 49.44 14.893 50.28 ;
     RECT  13.619 51.312 14.893 53.928 ;
     RECT  14.749 55.152 14.893 58.584 ;
     RECT  14.605 60.048 14.893 67.272 ;
     RECT  14.789 44.64 14.897 47.064 ;
     RECT  13.504 70.56 14.897 70.824 ;
     RECT  14.893 55.152 14.929 67.272 ;
     RECT  14.893 49.44 14.933 53.928 ;
     RECT  14.929 55.008 14.977 67.272 ;
     RECT  14.897 70.56 15.005 70.584 ;
     RECT  14.933 52.176 15.037 53.928 ;
     RECT  14.977 55.008 15.037 58.584 ;
     RECT  14.977 60.048 15.041 67.272 ;
     RECT  14.933 49.44 15.149 50.712 ;
     RECT  14.713 29.088 15.217 35.064 ;
     RECT  14.825 37.488 15.217 37.704 ;
     RECT  14.717 43.248 15.217 43.32 ;
     RECT  15.217 29.088 15.325 35.544 ;
     RECT  15.041 60.336 15.365 67.272 ;
     RECT  14.825 38.88 15.401 38.904 ;
     RECT  14.897 44.64 15.473 46.776 ;
     RECT  15.325 29.04 15.509 35.544 ;
     RECT  14.681 27.216 15.541 27.72 ;
     RECT  15.509 29.04 15.541 31.368 ;
     RECT  15.509 32.448 15.545 35.544 ;
     RECT  14.717 42.192 15.545 42.216 ;
     RECT  15.365 61.968 15.545 67.272 ;
     RECT  15.541 27.216 15.581 31.368 ;
     RECT  14.717 25.776 15.613 26.088 ;
     RECT  15.545 34.704 15.617 35.544 ;
     RECT  15.217 43.248 15.721 43.416 ;
     RECT  13.955 19.056 15.725 22.056 ;
     RECT  15.725 19.056 15.74 21.816 ;
     RECT  13.907 23.28 15.793 23.4 ;
     RECT  15.149 49.44 15.797 50.28 ;
     RECT  15.74 18.576 15.827 21.816 ;
     RECT  15.613 25.296 15.901 26.088 ;
     RECT  15.473 44.88 15.905 46.776 ;
     RECT  15.901 24.528 15.925 26.088 ;
     RECT  15.925 24.48 15.973 26.088 ;
     RECT  15.217 37.2 15.973 37.704 ;
     RECT  14.861 73.344 16.013 73.56 ;
     RECT  15.973 24.48 16.019 26.232 ;
     RECT  14.893 48.192 16.045 48.408 ;
     RECT  15.797 49.44 16.045 49.56 ;
     RECT  16.013 73.344 16.049 73.368 ;
     RECT  15.037 52.176 16.117 58.584 ;
     RECT  14.867 71.808 16.153 71.832 ;
     RECT  15.365 60.336 16.157 60.984 ;
     RECT  16.117 52.176 16.189 58.872 ;
     RECT  14.569 40.56 16.225 40.728 ;
     RECT  15.905 45.456 16.225 46.776 ;
     RECT  16.045 48.192 16.225 49.56 ;
     RECT  16.153 50.736 16.225 50.76 ;
     RECT  16.189 52.176 16.225 59.832 ;
     RECT  16.153 71.664 16.225 71.832 ;
     RECT  16.157 60.96 16.265 60.984 ;
     RECT  13.709 91.44 16.265 91.464 ;
     RECT  15.545 32.448 16.307 33.048 ;
     RECT  16.225 39.744 16.333 40.728 ;
     RECT  15.973 37.2 16.405 38.184 ;
     RECT  14.195 69.456 16.46 69.48 ;
     RECT  16.46 68.928 16.547 69.48 ;
     RECT  16.405 37.056 16.549 38.184 ;
     RECT  15.545 61.968 16.549 67.08 ;
     RECT  16.225 71.616 16.549 71.832 ;
     RECT  16.549 61.968 16.585 67.176 ;
     RECT  16.547 69.024 16.595 69.48 ;
     RECT  13.709 88.128 16.595 89.448 ;
     RECT  16.501 90.912 16.633 91.224 ;
     RECT  16.549 71.472 16.657 71.832 ;
     RECT  15.617 35.04 16.693 35.544 ;
     RECT  16.333 39.744 16.693 41.112 ;
     RECT  15.721 42.672 16.693 43.416 ;
     RECT  16.549 37.056 16.757 38.424 ;
     RECT  16.693 39.744 16.757 43.416 ;
     RECT  15.827 19.536 16.789 21.816 ;
     RECT  15.793 22.8 16.789 23.4 ;
     RECT  14.861 99.456 16.789 100.008 ;
     RECT  16.693 18.528 16.837 18.552 ;
     RECT  16.789 19.536 16.837 23.4 ;
     RECT  16.757 37.056 16.877 43.416 ;
     RECT  16.225 50.736 16.877 59.832 ;
     RECT  13.504 118.992 16.933 119.976 ;
     RECT  16.019 25.776 16.945 26.232 ;
     RECT  15.581 27.216 16.945 30.936 ;
     RECT  16.877 37.344 16.945 43.416 ;
     RECT  16.595 69.456 16.945 69.48 ;
     RECT  16.657 70.8 16.945 71.832 ;
     RECT  16.693 35.04 16.988 35.88 ;
     RECT  16.988 35.04 17.075 35.976 ;
     RECT  17.075 35.04 17.089 35.304 ;
     RECT  16.945 37.344 17.125 44.184 ;
     RECT  16.225 45.456 17.125 49.56 ;
     RECT  16.877 50.88 17.125 59.832 ;
     RECT  16.837 18.528 17.129 23.4 ;
     RECT  17.089 34.944 17.129 35.304 ;
     RECT  16.945 25.776 17.161 30.936 ;
     RECT  17.129 19.344 17.165 23.4 ;
     RECT  13.529 113.712 17.273 113.832 ;
     RECT  16.585 61.968 17.305 67.416 ;
     RECT  17.161 25.776 17.317 31.176 ;
     RECT  16.019 24.48 17.341 24.504 ;
     RECT  13.504 81.744 17.363 81.768 ;
     RECT  17.125 37.344 17.411 49.56 ;
     RECT  17.305 61.008 17.417 67.416 ;
     RECT  17.165 19.344 17.489 22.824 ;
     RECT  17.341 23.952 17.489 24.504 ;
     RECT  16.945 69.456 17.521 71.832 ;
     RECT  17.521 69.456 17.653 72.216 ;
     RECT  17.125 50.88 17.845 59.88 ;
     RECT  16.789 98.88 17.881 100.008 ;
     RECT  17.411 37.344 17.893 39.624 ;
     RECT  13.504 105.408 17.941 105.432 ;
     RECT  17.317 25.776 17.948 31.8 ;
     RECT  18.061 18.144 18.097 18.168 ;
     RECT  17.489 19.344 18.097 22.776 ;
     RECT  17.489 23.952 18.169 23.976 ;
     RECT  17.948 25.776 18.421 31.944 ;
     RECT  16.307 33.024 18.421 33.048 ;
     RECT  18.097 18.144 18.601 22.776 ;
     RECT  13.504 14.352 18.608 14.376 ;
     RECT  18.601 17.952 18.608 22.776 ;
     RECT  18.169 23.904 18.608 23.976 ;
     RECT  18.421 25.776 18.608 33.048 ;
     RECT  17.129 34.944 18.608 34.968 ;
     RECT  17.893 36.816 18.608 39.624 ;
     RECT  17.411 40.704 18.608 49.56 ;
     RECT  17.845 50.736 18.608 59.88 ;
     RECT  17.417 61.68 18.608 67.416 ;
     RECT  17.653 69.456 18.608 72.984 ;
     RECT  13.504 78.432 18.608 78.456 ;
     RECT  17.413 84.048 18.608 84.072 ;
     RECT  16.595 88.128 18.608 88.968 ;
     RECT  16.633 90.912 18.608 90.936 ;
     RECT  14.861 93.024 18.608 93.384 ;
     RECT  13.504 97.536 18.608 97.56 ;
     RECT  17.881 98.64 18.608 100.008 ;
     RECT  13.504 101.136 18.608 104.04 ;
     RECT  17.941 105.36 18.608 105.432 ;
     RECT  17.273 113.808 18.608 113.832 ;
     RECT  17.317 116.448 18.608 116.472 ;
     RECT  16.933 118.32 18.608 119.976 ;
     RECT  18.608 2.148 18.712 127.452 ;
     RECT  18.712 2.418 18.904 127.182 ;
     RECT  18.904 93.024 19.043 93.384 ;
     RECT  18.904 46.992 19.073 60.456 ;
     RECT  18.904 94.368 19.139 94.584 ;
     RECT  18.904 84.048 19.181 84.216 ;
     RECT  18.904 90.912 19.181 91.176 ;
     RECT  18.904 78.432 19.283 79.224 ;
     RECT  18.904 86.64 19.379 86.664 ;
     RECT  19.139 94.56 19.379 94.584 ;
     RECT  19.283 78.432 19.469 78.888 ;
     RECT  19.181 84.048 19.469 84.072 ;
     RECT  18.904 17.616 19.505 33.672 ;
     RECT  18.904 34.8 19.505 38.472 ;
     RECT  19.505 17.616 19.649 29.928 ;
     RECT  18.904 88.128 19.667 88.344 ;
     RECT  19.649 22.56 19.757 29.928 ;
     RECT  19.073 49.056 19.757 60.456 ;
     RECT  19.505 30.912 19.897 33.672 ;
     RECT  19.505 34.8 19.897 36.264 ;
     RECT  18.904 39.6 19.933 45.864 ;
     RECT  18.904 61.68 19.933 67.848 ;
     RECT  19.933 39.6 19.969 45.96 ;
     RECT  19.073 46.992 19.969 47.88 ;
     RECT  19.181 90.912 19.973 90.936 ;
     RECT  19.933 61.488 20.185 67.848 ;
     RECT  19.969 39.6 20.509 47.88 ;
     RECT  19.757 49.248 20.509 60.456 ;
     RECT  20.185 61.488 20.509 68.232 ;
     RECT  19.505 37.344 20.545 38.472 ;
     RECT  20.509 39.6 20.545 48.072 ;
     RECT  20.509 49.248 20.653 68.232 ;
     RECT  18.904 69.456 20.653 69.48 ;
     RECT  19.757 28.944 20.869 29.928 ;
     RECT  19.897 30.912 20.869 36.264 ;
     RECT  19.649 17.616 20.905 21.432 ;
     RECT  20.905 17.616 20.941 21.576 ;
     RECT  19.757 22.56 20.941 27.96 ;
     RECT  20.545 37.344 21.049 48.072 ;
     RECT  20.653 49.248 21.049 69.48 ;
     RECT  20.869 28.944 21.107 36.264 ;
     RECT  20.941 17.616 21.161 27.96 ;
     RECT  21.049 37.344 21.395 69.48 ;
     RECT  19.469 78.432 21.395 78.456 ;
     RECT  18.904 105.024 21.413 105.432 ;
     RECT  21.161 17.616 21.449 20.04 ;
     RECT  21.395 37.344 21.491 68.616 ;
     RECT  21.449 18.144 21.521 20.04 ;
     RECT  21.413 105.072 21.781 105.432 ;
     RECT  19.667 88.128 21.923 88.152 ;
     RECT  18.904 118.32 21.953 119.976 ;
     RECT  19.043 93.36 21.971 93.384 ;
     RECT  18.904 98.88 22.345 104.04 ;
     RECT  22.345 98.736 22.501 104.04 ;
     RECT  18.904 97.536 22.556 97.56 ;
     RECT  22.501 98.64 22.556 104.04 ;
     RECT  21.521 18.72 22.705 20.04 ;
     RECT  21.161 21.12 22.705 27.96 ;
     RECT  22.705 18.72 22.741 27.96 ;
     RECT  21.107 28.944 22.741 36.168 ;
     RECT  18.904 14.352 22.813 14.376 ;
     RECT  22.556 97.536 22.813 104.04 ;
     RECT  21.781 105.072 22.813 105.672 ;
     RECT  22.813 14.352 22.853 14.472 ;
     RECT  22.741 18.72 22.889 36.168 ;
     RECT  22.889 18.912 22.896 36.168 ;
     RECT  21.491 37.68 22.896 68.616 ;
     RECT  22.896 18.912 22.925 68.616 ;
     RECT  22.925 18.96 22.968 68.616 ;
     RECT  22.813 97.536 22.968 105.672 ;
     RECT  22.853 14.448 24.008 14.472 ;
     RECT  22.968 18.96 24.008 105.672 ;
     RECT  18.904 116.448 24.008 116.472 ;
     RECT  21.953 118.32 24.008 118.968 ;
     RECT  21.953 119.952 24.008 119.976 ;
     RECT  24.008 2.148 24.112 127.452 ;
     RECT  24.112 2.418 24.304 127.182 ;
     RECT  24.304 116.448 24.419 116.616 ;
     RECT  24.304 118.32 24.419 118.968 ;
     RECT  24.304 18.96 24.437 105.672 ;
     RECT  24.437 18.96 24.467 105.48 ;
     RECT  24.467 18.96 24.545 105.384 ;
     RECT  24.419 116.448 24.653 116.472 ;
     RECT  24.545 19.056 25.229 105.384 ;
     RECT  24.304 14.448 25.481 14.472 ;
     RECT  25.229 19.056 26.125 19.8 ;
     RECT  25.229 21.168 27.133 105.384 ;
     RECT  26.125 18.816 27.169 19.8 ;
     RECT  27.133 20.928 27.169 105.384 ;
     RECT  27.169 18.816 27.497 105.384 ;
     RECT  27.497 103.248 27.635 105.384 ;
     RECT  27.497 18.816 27.677 102.168 ;
     RECT  27.677 19.008 29.408 102.168 ;
     RECT  27.635 103.248 29.408 104.04 ;
     RECT  27.635 105.36 29.408 105.384 ;
     RECT  24.419 118.32 29.408 118.344 ;
     RECT  24.304 119.952 29.408 119.976 ;
     RECT  29.408 2.148 29.512 127.452 ;
     RECT  29.512 2.418 29.704 127.182 ;
     RECT  29.704 119.952 29.801 120.264 ;
     RECT  29.801 120.24 30.169 120.264 ;
     RECT  29.704 19.056 30.197 19.896 ;
     RECT  30.197 19.776 30.269 19.896 ;
     RECT  29.704 20.88 30.773 102.168 ;
     RECT  30.773 21.264 31.921 102.168 ;
     RECT  31.921 21.12 31.993 102.168 ;
     RECT  30.269 19.872 32.317 19.896 ;
     RECT  31.993 21.072 33.001 102.168 ;
     RECT  32.317 19.056 33.145 19.896 ;
     RECT  33.001 20.88 33.145 102.168 ;
     RECT  33.145 19.056 33.301 102.168 ;
     RECT  33.301 18.144 33.833 102.168 ;
     RECT  33.833 18.144 34.808 102.12 ;
     RECT  29.704 103.248 34.808 104.04 ;
     RECT  29.704 105.36 34.808 105.384 ;
     RECT  32.917 109.152 34.808 109.176 ;
     RECT  29.704 118.32 34.808 118.344 ;
     RECT  29.704 124.128 34.808 124.152 ;
     RECT  34.808 2.148 34.912 127.452 ;
     RECT  34.912 2.418 35.104 127.182 ;
     RECT  35.104 20.064 35.201 20.136 ;
     RECT  35.201 20.112 36.421 20.136 ;
     RECT  36.421 20.064 36.529 20.136 ;
     RECT  35.104 21.408 36.529 102.12 ;
     RECT  36.529 20.064 36.997 102.12 ;
     RECT  36.997 20.016 37.577 102.12 ;
     RECT  37.577 20.112 37.649 102.12 ;
     RECT  37.649 20.592 38.333 102.12 ;
     RECT  38.333 20.64 39.161 102.12 ;
     RECT  35.104 18.144 39.553 19.032 ;
     RECT  39.553 18.144 40.208 20.184 ;
     RECT  39.161 21.456 40.208 102.12 ;
     RECT  35.104 103.248 40.208 104.04 ;
     RECT  35.104 105.36 40.208 105.384 ;
     RECT  35.104 109.152 40.208 109.176 ;
     RECT  35.104 118.32 40.208 118.344 ;
     RECT  35.104 124.128 40.208 124.152 ;
     RECT  40.208 2.148 40.312 127.452 ;
     RECT  40.312 2.418 40.504 127.182 ;
     RECT  40.504 20.832 41.069 102.12 ;
     RECT  40.504 18.816 41.645 19.8 ;
     RECT  41.069 20.928 41.933 102.12 ;
     RECT  41.645 19.104 42.041 19.8 ;
     RECT  42.041 19.104 42.185 19.224 ;
     RECT  41.933 21.072 42.185 102.12 ;
     RECT  42.185 21.12 42.257 102.12 ;
     RECT  42.257 21.36 42.797 102.12 ;
     RECT  40.504 103.248 43.285 104.04 ;
     RECT  40.504 109.152 44.053 109.176 ;
     RECT  44.053 109.056 44.201 109.176 ;
     RECT  44.201 109.152 44.381 109.176 ;
     RECT  42.797 21.408 44.489 102.12 ;
     RECT  44.737 20.352 44.953 20.376 ;
     RECT  43.285 103.248 45.529 104.136 ;
     RECT  40.504 105.36 45.529 105.384 ;
     RECT  42.185 19.104 45.601 19.128 ;
     RECT  44.953 20.304 45.601 20.376 ;
     RECT  45.601 19.104 45.608 20.376 ;
     RECT  44.489 21.456 45.608 102.12 ;
     RECT  45.529 103.248 45.608 105.384 ;
     RECT  40.504 124.128 45.608 124.152 ;
     RECT  45.608 2.148 45.712 127.452 ;
     RECT  45.712 2.418 45.904 127.182 ;
     RECT  45.904 19.344 46.073 19.848 ;
     RECT  46.073 19.344 47.189 19.368 ;
     RECT  45.904 20.832 48.049 102.12 ;
     RECT  48.049 20.448 48.085 102.12 ;
     RECT  48.085 20.016 48.521 102.12 ;
     RECT  48.521 20.016 48.593 20.04 ;
     RECT  48.521 21.12 49.724 102.12 ;
     RECT  49.724 20.4 49.811 102.12 ;
     RECT  49.811 21.216 51.008 102.12 ;
     RECT  45.904 103.248 51.008 105.384 ;
     RECT  47.365 117.072 51.008 117.096 ;
     RECT  45.904 124.128 51.008 124.152 ;
     RECT  51.008 2.148 51.112 127.452 ;
     RECT  51.112 2.418 51.304 127.182 ;
     RECT  51.304 117.072 51.761 117.24 ;
     RECT  51.304 21.408 54.605 102.12 ;
     RECT  51.761 117.216 55.285 117.24 ;
     RECT  54.605 21.456 56.408 102.12 ;
     RECT  51.304 103.248 56.408 105.384 ;
     RECT  55.285 117.12 56.408 117.432 ;
     RECT  51.304 124.128 56.408 124.152 ;
     RECT  56.408 2.148 56.512 127.452 ;
     RECT  56.512 2.418 56.704 127.182 ;
     RECT  56.704 21.456 57.953 102.12 ;
     RECT  57.953 21.456 58.493 21.48 ;
     RECT  59.677 21.408 61.541 21.432 ;
     RECT  57.953 22.464 61.541 102.12 ;
     RECT  59.389 16.272 61.573 16.296 ;
     RECT  61.237 15.264 61.808 15.288 ;
     RECT  61.573 16.272 61.808 16.824 ;
     RECT  61.541 21.408 61.808 102.12 ;
     RECT  56.704 103.248 61.808 105.384 ;
     RECT  56.704 124.128 61.808 124.152 ;
     RECT  61.808 2.148 61.912 127.452 ;
     RECT  61.912 2.418 62.104 127.182 ;
     RECT  62.104 21.408 62.723 102.12 ;
     RECT  62.723 21.408 62.893 23.352 ;
     RECT  62.893 22.464 64.969 23.352 ;
     RECT  62.723 24.384 64.969 102.12 ;
     RECT  64.969 22.464 65.549 102.12 ;
     RECT  62.104 13.536 67.208 13.56 ;
     RECT  62.104 15.168 67.208 15.192 ;
     RECT  62.104 16.272 67.208 16.824 ;
     RECT  62.893 21.408 67.208 21.432 ;
     RECT  65.549 22.464 67.208 23.352 ;
     RECT  65.549 24.384 67.208 102.12 ;
     RECT  62.104 103.248 67.208 105.384 ;
     RECT  62.104 124.128 67.208 124.152 ;
     RECT  67.208 2.148 67.312 127.452 ;
     RECT  67.312 2.418 67.504 127.182 ;
     RECT  67.504 24.384 69.001 102.12 ;
     RECT  67.504 103.248 69.001 105.384 ;
     RECT  69.001 24.384 69.829 105.384 ;
     RECT  67.504 22.464 70.045 23.352 ;
     RECT  69.829 24.336 70.045 105.384 ;
     RECT  67.504 15.168 70.069 15.192 ;
     RECT  67.504 13.536 70.261 13.56 ;
     RECT  70.069 14.64 70.261 15.192 ;
     RECT  70.045 22.464 70.345 105.384 ;
     RECT  70.345 24.336 71.165 105.384 ;
     RECT  70.261 13.536 72.608 15.192 ;
     RECT  67.504 16.272 72.608 16.824 ;
     RECT  67.504 21.408 72.608 21.432 ;
     RECT  70.345 22.464 72.608 23.352 ;
     RECT  71.165 24.336 72.608 26.52 ;
     RECT  71.165 27.648 72.608 105.384 ;
     RECT  67.504 124.128 72.608 124.152 ;
     RECT  72.608 2.148 72.712 26.52 ;
     RECT  72.608 27.648 72.712 127.452 ;
     RECT  72.712 2.418 72.904 26.52 ;
     RECT  72.712 27.648 72.904 127.182 ;
     RECT  72.904 27.648 74.477 105.384 ;
     RECT  72.904 24.336 75.485 26.52 ;
     RECT  72.904 13.536 78.008 15.192 ;
     RECT  72.904 16.272 78.008 16.824 ;
     RECT  72.904 21.408 78.008 21.432 ;
     RECT  72.904 22.464 78.008 23.352 ;
     RECT  75.485 24.336 78.008 26.472 ;
     RECT  74.477 27.888 78.008 105.384 ;
     RECT  72.904 124.128 78.008 124.152 ;
     RECT  78.008 2.148 78.112 26.472 ;
     RECT  78.008 27.888 78.112 127.452 ;
     RECT  78.112 2.418 78.304 26.472 ;
     RECT  78.112 27.888 78.304 127.182 ;
     RECT  78.304 27.888 79.765 105.384 ;
     RECT  78.304 13.536 83.408 15.192 ;
     RECT  78.304 16.272 83.408 16.824 ;
     RECT  78.304 21.408 83.408 21.432 ;
     RECT  78.304 22.464 83.408 23.352 ;
     RECT  78.304 24.336 83.408 26.472 ;
     RECT  79.765 27.744 83.408 105.384 ;
     RECT  78.304 124.128 83.408 124.152 ;
     RECT  83.408 2.148 83.512 26.472 ;
     RECT  83.408 27.744 83.512 127.452 ;
     RECT  83.512 2.418 83.704 26.472 ;
     RECT  83.512 27.744 83.704 127.182 ;
     RECT  83.704 13.536 86.641 15.192 ;
     RECT  86.641 13.536 88.808 15.288 ;
     RECT  83.704 16.272 88.808 16.824 ;
     RECT  83.704 21.408 88.808 21.432 ;
     RECT  83.704 22.464 88.808 23.352 ;
     RECT  83.704 24.336 88.808 26.472 ;
     RECT  83.704 27.744 88.808 105.384 ;
     RECT  83.704 124.128 88.808 124.152 ;
     RECT  88.808 2.148 88.912 26.472 ;
     RECT  88.808 27.744 88.912 127.452 ;
     RECT  88.912 2.418 89.104 26.472 ;
     RECT  88.912 27.744 89.104 127.182 ;
     RECT  89.104 13.536 89.525 15.288 ;
     RECT  89.104 16.272 89.525 16.824 ;
     RECT  89.525 13.536 90.601 13.56 ;
     RECT  89.525 14.64 90.601 14.664 ;
     RECT  89.525 16.8 90.601 16.824 ;
     RECT  90.601 14.64 90.677 15.192 ;
     RECT  89.104 21.408 90.677 21.432 ;
     RECT  90.601 16.272 91.361 16.824 ;
     RECT  90.601 13.296 91.669 13.56 ;
     RECT  91.361 16.272 91.721 16.584 ;
     RECT  91.669 13.296 91.753 13.848 ;
     RECT  90.677 15.168 91.753 15.192 ;
     RECT  91.753 13.296 94.208 15.192 ;
     RECT  91.721 16.272 94.208 16.296 ;
     RECT  91.753 21.408 94.208 21.432 ;
     RECT  89.104 22.464 94.208 23.352 ;
     RECT  89.104 24.336 94.208 26.472 ;
     RECT  89.104 27.744 94.208 105.384 ;
     RECT  89.104 124.128 94.208 124.152 ;
     RECT  94.208 2.148 94.312 26.472 ;
     RECT  94.208 27.744 94.312 127.452 ;
     RECT  94.312 2.418 94.504 26.472 ;
     RECT  94.312 27.744 94.504 127.182 ;
     RECT  94.504 13.296 99.608 15.192 ;
     RECT  94.504 16.272 99.608 16.296 ;
     RECT  94.504 21.408 99.608 21.432 ;
     RECT  94.504 22.464 99.608 23.352 ;
     RECT  94.504 24.336 99.608 26.472 ;
     RECT  94.504 27.744 99.608 105.384 ;
     RECT  94.504 124.128 99.608 124.152 ;
     RECT  99.608 2.148 99.712 26.472 ;
     RECT  99.608 27.744 99.712 127.452 ;
     RECT  99.712 2.418 99.904 26.472 ;
     RECT  99.712 27.744 99.904 127.182 ;
     RECT  99.904 13.296 105.008 15.192 ;
     RECT  99.904 16.272 105.008 16.296 ;
     RECT  99.904 21.408 105.008 21.432 ;
     RECT  99.904 22.464 105.008 23.352 ;
     RECT  99.904 24.336 105.008 26.472 ;
     RECT  99.904 27.744 105.008 105.384 ;
     RECT  99.904 124.128 105.008 124.152 ;
     RECT  105.008 2.148 105.112 26.472 ;
     RECT  105.008 27.744 105.112 127.452 ;
     RECT  105.112 2.418 105.304 26.472 ;
     RECT  105.112 27.744 105.304 127.182 ;
     RECT  105.304 22.464 108.899 23.352 ;
     RECT  105.304 13.296 110.408 15.192 ;
     RECT  105.304 16.272 110.408 16.296 ;
     RECT  105.304 21.408 110.408 21.432 ;
     RECT  108.899 22.464 110.408 23.304 ;
     RECT  105.304 24.336 110.408 26.472 ;
     RECT  105.304 27.744 110.408 105.384 ;
     RECT  105.304 124.128 110.408 124.152 ;
     RECT  110.408 2.148 110.512 26.472 ;
     RECT  110.408 27.744 110.512 127.452 ;
     RECT  110.512 2.418 110.704 26.472 ;
     RECT  110.512 27.744 110.704 127.182 ;
     RECT  110.704 22.464 112.211 23.304 ;
     RECT  110.704 27.744 113.537 105.384 ;
     RECT  110.704 13.296 115.808 15.192 ;
     RECT  110.704 16.272 115.808 16.296 ;
     RECT  110.704 21.408 115.808 21.432 ;
     RECT  112.211 22.464 115.808 23.112 ;
     RECT  110.704 24.336 115.808 26.472 ;
     RECT  113.537 27.744 115.808 104.904 ;
     RECT  111.973 106.416 115.808 106.44 ;
     RECT  110.704 124.128 115.808 124.152 ;
     RECT  115.808 2.148 115.912 26.472 ;
     RECT  115.808 27.744 115.912 127.452 ;
     RECT  115.912 2.418 116.104 26.472 ;
     RECT  115.912 27.744 116.104 127.182 ;
     RECT  116.104 13.296 121.208 15.192 ;
     RECT  116.104 16.272 121.208 16.296 ;
     RECT  116.104 21.408 121.208 21.432 ;
     RECT  116.104 22.464 121.208 23.112 ;
     RECT  116.104 24.336 121.208 26.472 ;
     RECT  116.104 27.744 121.208 104.904 ;
     RECT  116.104 106.416 121.208 106.44 ;
     RECT  116.104 124.128 121.208 124.152 ;
     RECT  121.208 2.148 121.312 26.472 ;
     RECT  121.208 27.744 121.312 127.452 ;
     RECT  121.312 2.418 121.504 26.472 ;
     RECT  121.312 27.744 121.504 127.182 ;
     RECT  121.504 13.296 126.608 15.192 ;
     RECT  121.504 16.272 126.608 16.296 ;
     RECT  121.504 21.408 126.608 21.432 ;
     RECT  121.504 23.088 126.608 23.112 ;
     RECT  121.504 24.336 126.608 26.472 ;
     RECT  121.504 27.744 126.608 104.904 ;
     RECT  121.504 106.416 126.608 106.44 ;
     RECT  121.504 124.128 126.608 124.152 ;
     RECT  126.608 2.148 126.712 26.472 ;
     RECT  126.608 27.744 126.712 127.452 ;
     RECT  126.712 2.418 126.904 26.472 ;
     RECT  126.712 27.744 126.904 127.182 ;
     RECT  126.904 13.296 132.008 15.192 ;
     RECT  126.904 16.272 132.008 16.296 ;
     RECT  126.904 21.408 132.008 21.432 ;
     RECT  126.904 23.088 132.008 23.112 ;
     RECT  126.904 24.336 132.008 26.472 ;
     RECT  126.904 27.744 132.008 104.904 ;
     RECT  126.904 106.416 132.008 106.44 ;
     RECT  126.904 124.128 132.008 124.152 ;
     RECT  132.008 2.148 132.112 26.472 ;
     RECT  132.008 27.744 132.112 127.452 ;
     RECT  132.112 2.418 132.304 26.472 ;
     RECT  132.112 27.744 132.304 127.182 ;
     RECT  132.304 13.296 137.408 15.192 ;
     RECT  132.304 16.272 137.408 16.296 ;
     RECT  132.304 21.408 137.408 21.432 ;
     RECT  132.304 23.088 137.408 23.112 ;
     RECT  132.304 24.336 137.408 26.472 ;
     RECT  132.304 27.744 137.408 104.904 ;
     RECT  132.304 106.416 137.408 106.44 ;
     RECT  132.304 124.128 137.408 124.152 ;
     RECT  137.408 2.148 137.512 26.472 ;
     RECT  137.408 27.744 137.512 127.452 ;
     RECT  137.512 2.418 137.704 26.472 ;
     RECT  137.512 27.744 137.704 127.182 ;
     RECT  137.704 124.128 140.933 124.152 ;
     RECT  137.704 13.296 142.808 15.192 ;
     RECT  137.704 16.272 142.808 16.296 ;
     RECT  137.704 21.408 142.808 21.432 ;
     RECT  137.704 23.088 142.808 23.112 ;
     RECT  137.704 24.336 142.808 26.472 ;
     RECT  137.704 27.744 142.808 104.904 ;
     RECT  137.704 106.416 142.808 106.44 ;
     RECT  142.441 124.848 142.808 124.872 ;
     RECT  142.808 2.148 142.912 26.472 ;
     RECT  142.808 27.744 142.912 127.452 ;
     RECT  142.912 2.418 143.104 26.472 ;
     RECT  142.912 27.744 143.104 127.182 ;
     RECT  143.104 124.848 143.201 124.968 ;
     RECT  143.104 13.296 148.208 15.192 ;
     RECT  143.104 16.272 148.208 16.296 ;
     RECT  143.104 21.408 148.208 21.432 ;
     RECT  143.104 23.088 148.208 23.112 ;
     RECT  143.104 24.336 148.208 26.472 ;
     RECT  143.104 27.744 148.208 104.904 ;
     RECT  143.104 106.416 148.208 106.44 ;
     RECT  143.201 124.944 148.208 124.968 ;
     RECT  148.208 2.148 148.312 26.472 ;
     RECT  148.208 27.744 148.312 127.452 ;
     RECT  148.312 2.418 148.504 26.472 ;
     RECT  148.312 27.744 148.504 127.182 ;
     RECT  148.504 13.296 153.608 15.192 ;
     RECT  148.504 16.272 153.608 16.296 ;
     RECT  148.504 21.408 153.608 21.432 ;
     RECT  148.504 23.088 153.608 23.112 ;
     RECT  148.504 24.336 153.608 26.472 ;
     RECT  148.504 27.744 153.608 104.904 ;
     RECT  148.504 106.416 153.608 106.44 ;
     RECT  148.504 124.944 153.608 124.968 ;
     RECT  153.608 2.148 153.712 26.472 ;
     RECT  153.608 27.744 153.712 127.452 ;
     RECT  153.712 2.418 153.904 26.472 ;
     RECT  153.712 27.744 153.904 127.182 ;
     RECT  153.904 13.296 159.008 15.192 ;
     RECT  153.904 16.272 159.008 16.296 ;
     RECT  153.904 21.408 159.008 21.432 ;
     RECT  153.904 23.088 159.008 23.112 ;
     RECT  153.904 24.336 159.008 26.472 ;
     RECT  153.904 27.744 159.008 104.904 ;
     RECT  153.904 106.416 159.008 106.44 ;
     RECT  153.904 124.944 159.008 124.968 ;
     RECT  159.008 2.148 159.112 26.472 ;
     RECT  159.008 27.744 159.112 127.452 ;
     RECT  159.112 2.418 159.304 26.472 ;
     RECT  159.112 27.744 159.304 127.182 ;
     RECT  159.304 13.296 164.408 15.192 ;
     RECT  159.304 16.272 164.408 16.296 ;
     RECT  159.304 21.408 164.408 21.432 ;
     RECT  159.304 23.088 164.408 23.112 ;
     RECT  159.304 24.336 164.408 26.472 ;
     RECT  159.304 27.744 164.408 104.904 ;
     RECT  159.304 106.416 164.408 106.44 ;
     RECT  159.304 124.944 164.408 124.968 ;
     RECT  160.501 127.248 164.408 127.272 ;
     RECT  164.408 2.148 164.512 26.472 ;
     RECT  164.408 27.744 164.512 127.452 ;
     RECT  164.512 2.418 164.704 26.472 ;
     RECT  164.512 27.744 164.704 127.272 ;
     RECT  164.704 23.088 167.033 23.112 ;
     RECT  164.704 13.296 169.808 15.192 ;
     RECT  164.704 16.272 169.808 16.296 ;
     RECT  164.704 21.408 169.808 21.432 ;
     RECT  164.704 24.336 169.808 26.472 ;
     RECT  164.704 27.744 169.808 104.904 ;
     RECT  164.704 106.416 169.808 106.44 ;
     RECT  164.704 124.944 169.808 124.968 ;
     RECT  164.704 127.248 169.808 127.272 ;
     RECT  169.808 2.148 169.912 26.472 ;
     RECT  169.808 27.744 169.912 127.452 ;
     RECT  169.912 2.418 170.104 26.472 ;
     RECT  169.912 27.744 170.104 127.272 ;
     RECT  170.104 13.296 175.208 15.192 ;
     RECT  170.104 16.272 175.208 16.296 ;
     RECT  170.104 21.408 175.208 21.432 ;
     RECT  170.104 24.336 175.208 26.472 ;
     RECT  170.104 27.744 175.208 104.904 ;
     RECT  170.104 106.416 175.208 106.44 ;
     RECT  170.104 124.944 175.208 124.968 ;
     RECT  170.104 127.248 175.208 127.272 ;
     RECT  175.208 2.148 175.312 26.472 ;
     RECT  175.208 27.744 175.312 127.452 ;
     RECT  175.312 2.418 175.504 26.472 ;
     RECT  175.312 27.744 175.504 127.272 ;
     RECT  175.504 13.296 180.608 15.192 ;
     RECT  175.504 16.272 180.608 16.296 ;
     RECT  175.504 21.408 180.608 21.432 ;
     RECT  175.504 24.336 180.608 26.472 ;
     RECT  175.504 27.744 180.608 104.904 ;
     RECT  175.504 106.416 180.608 106.44 ;
     RECT  175.504 124.944 180.608 124.968 ;
     RECT  175.504 127.248 180.608 127.272 ;
     RECT  180.608 2.148 180.712 26.472 ;
     RECT  180.608 27.744 180.712 127.452 ;
     RECT  180.712 2.418 180.904 26.472 ;
     RECT  180.712 27.744 180.904 127.272 ;
     RECT  180.904 13.296 186.008 15.192 ;
     RECT  180.904 16.272 186.008 16.296 ;
     RECT  180.904 21.408 186.008 21.432 ;
     RECT  180.904 24.336 186.008 26.472 ;
     RECT  180.904 27.744 186.008 104.904 ;
     RECT  180.904 106.416 186.008 106.44 ;
     RECT  185.564 120.96 186.008 120.984 ;
     RECT  180.904 124.944 186.008 124.968 ;
     RECT  180.904 127.248 186.008 127.272 ;
     RECT  186.008 2.148 186.112 26.472 ;
     RECT  186.008 27.744 186.112 127.452 ;
     RECT  186.112 2.418 186.304 26.472 ;
     RECT  186.112 27.744 186.304 127.272 ;
     RECT  186.304 13.296 191.408 15.192 ;
     RECT  186.304 16.272 191.408 16.296 ;
     RECT  186.304 21.408 191.408 21.432 ;
     RECT  186.304 24.336 191.408 26.472 ;
     RECT  186.304 27.744 191.408 104.904 ;
     RECT  186.304 106.416 191.408 106.44 ;
     RECT  186.304 121.008 191.408 121.32 ;
     RECT  186.304 124.944 191.408 124.968 ;
     RECT  186.304 127.248 191.408 127.272 ;
     RECT  191.408 2.148 191.512 26.472 ;
     RECT  191.408 27.744 191.512 127.452 ;
     RECT  191.512 2.418 191.704 26.472 ;
     RECT  191.512 27.744 191.704 127.272 ;
     RECT  191.704 27.744 194.209 104.904 ;
     RECT  194.209 27.744 194.353 105.384 ;
     RECT  191.704 106.416 194.353 106.44 ;
     RECT  194.353 27.744 195.157 106.44 ;
     RECT  191.704 121.008 195.203 121.32 ;
     RECT  195.157 27.744 195.329 106.92 ;
     RECT  195.157 107.904 196.309 107.928 ;
     RECT  195.329 27.744 196.657 106.584 ;
     RECT  191.704 13.296 196.808 15.192 ;
     RECT  191.704 16.272 196.808 16.296 ;
     RECT  191.704 21.408 196.808 21.432 ;
     RECT  191.704 24.336 196.808 26.472 ;
     RECT  196.657 27.696 196.808 106.584 ;
     RECT  196.309 107.712 196.808 108.072 ;
     RECT  195.203 121.296 196.808 121.32 ;
     RECT  191.704 124.944 196.808 124.968 ;
     RECT  191.704 127.248 196.808 127.272 ;
     RECT  196.808 2.148 196.912 26.472 ;
     RECT  196.808 27.696 196.912 127.452 ;
     RECT  196.912 2.418 197.104 26.472 ;
     RECT  196.912 27.696 197.104 127.272 ;
     RECT  197.104 27.696 197.568 107.544 ;
     RECT  197.568 98.496 197.747 107.544 ;
     RECT  197.568 27.696 197.777 68.712 ;
     RECT  197.747 98.496 197.795 105.384 ;
     RECT  197.747 106.56 197.795 107.544 ;
     RECT  197.777 57.552 197.813 60.456 ;
     RECT  197.795 98.592 198.275 105.384 ;
     RECT  197.795 107.52 198.277 107.544 ;
     RECT  198.275 98.592 198.323 103.224 ;
     RECT  197.777 27.696 198.353 55.224 ;
     RECT  197.813 57.648 198.353 60.456 ;
     RECT  197.777 63.312 198.353 65.544 ;
     RECT  198.353 54.672 198.389 55.224 ;
     RECT  197.777 62.064 198.461 62.088 ;
     RECT  198.353 51.888 198.497 53.544 ;
     RECT  198.323 98.592 198.659 100.152 ;
     RECT  198.323 101.136 198.707 103.224 ;
     RECT  198.659 98.592 198.755 100.056 ;
     RECT  198.661 79.776 198.757 79.8 ;
     RECT  198.755 98.592 198.803 99.432 ;
     RECT  198.353 48.912 198.929 48.936 ;
     RECT  198.497 51.888 198.929 53.016 ;
     RECT  198.707 103.2 199.235 103.224 ;
     RECT  197.568 87.552 199.237 87.576 ;
     RECT  198.707 101.136 199.253 102.168 ;
     RECT  198.275 104.352 199.283 105.384 ;
     RECT  198.353 27.696 199.505 46.728 ;
     RECT  199.505 44.496 199.609 46.728 ;
     RECT  198.389 55.2 199.681 55.224 ;
     RECT  199.189 61.68 199.717 61.704 ;
     RECT  199.237 87.408 199.825 87.576 ;
     RECT  197.568 89.184 199.825 89.208 ;
     RECT  197.777 66.768 199.861 67.176 ;
     RECT  197.777 68.304 199.861 68.712 ;
     RECT  198.353 64.992 199.865 65.544 ;
     RECT  197.104 24.336 199.933 26.472 ;
     RECT  199.505 27.696 199.933 42.12 ;
     RECT  199.609 44.496 199.937 47.016 ;
     RECT  199.681 55.2 200.009 55.8 ;
     RECT  199.865 64.992 200.009 65.448 ;
     RECT  198.803 98.592 200.041 98.952 ;
     RECT  197.568 94.992 200.06 95.016 ;
     RECT  200.041 98.304 200.06 98.952 ;
     RECT  197.568 93.504 200.069 93.528 ;
     RECT  200.06 94.56 200.069 95.016 ;
     RECT  197.568 91.344 200.108 91.896 ;
     RECT  199.933 24.336 200.117 42.12 ;
     RECT  199.937 44.496 200.117 46.728 ;
     RECT  199.861 50.688 200.117 50.712 ;
     RECT  199.861 66.768 200.117 68.712 ;
     RECT  199.825 87.408 200.149 89.208 ;
     RECT  200.108 90.768 200.149 91.896 ;
     RECT  200.069 93.504 200.153 95.016 ;
     RECT  200.117 24.336 200.189 41.736 ;
     RECT  199.505 43.44 200.225 43.464 ;
     RECT  200.117 44.496 200.225 46.584 ;
     RECT  198.757 79.536 200.293 79.8 ;
     RECT  200.113 60.096 200.297 60.12 ;
     RECT  200.117 67.152 200.333 68.712 ;
     RECT  197.104 127.248 200.339 127.272 ;
     RECT  200.153 94.56 200.365 95.016 ;
     RECT  200.06 98.208 200.387 98.952 ;
     RECT  200.189 24.336 200.435 41.4 ;
     RECT  199.253 101.712 200.435 102.168 ;
     RECT  197.568 85.44 200.437 85.464 ;
     RECT  200.225 44.496 200.441 45.288 ;
     RECT  200.293 79.536 200.473 80.664 ;
     RECT  200.365 94.56 200.531 95.4 ;
     RECT  200.545 96.288 200.581 96.312 ;
     RECT  200.581 96.288 200.629 97.08 ;
     RECT  200.629 96.912 200.653 97.08 ;
     RECT  200.387 98.208 200.653 98.616 ;
     RECT  200.149 87.408 200.657 91.896 ;
     RECT  200.437 85.44 200.677 86.088 ;
     RECT  200.677 84.912 200.693 86.088 ;
     RECT  200.657 87.552 200.693 91.896 ;
     RECT  200.693 84.912 200.723 85.608 ;
     RECT  200.723 84.912 200.725 85.464 ;
     RECT  197.568 71.52 200.761 72.072 ;
     RECT  200.473 79.536 200.761 81.528 ;
     RECT  200.725 84.384 200.837 85.464 ;
     RECT  200.693 91.824 200.869 91.896 ;
     RECT  200.761 79.44 200.905 81.528 ;
     RECT  200.761 83.232 200.905 83.256 ;
     RECT  200.837 84.384 200.905 85.32 ;
     RECT  200.435 24.384 200.909 41.4 ;
     RECT  200.905 83.232 201.011 85.32 ;
     RECT  200.293 74.64 201.013 74.664 ;
     RECT  200.761 71.52 201.049 72.36 ;
     RECT  200.693 87.552 201.053 90.6 ;
     RECT  199.283 104.88 201.059 105.384 ;
     RECT  200.905 79.44 201.125 82.056 ;
     RECT  201.125 79.44 201.155 79.512 ;
     RECT  200.435 101.712 201.155 101.736 ;
     RECT  200.869 91.824 201.205 91.992 ;
     RECT  200.909 28.992 201.301 41.4 ;
     RECT  200.797 44.352 201.373 44.376 ;
     RECT  201.301 28.992 201.397 41.64 ;
     RECT  201.205 91.824 201.404 92.376 ;
     RECT  200.153 93.504 201.404 93.528 ;
     RECT  201.301 76.944 201.409 76.968 ;
     RECT  201.409 76.944 201.481 77.064 ;
     RECT  200.225 46.56 201.553 46.584 ;
     RECT  201.397 28.992 201.589 41.832 ;
     RECT  201.553 45.6 201.625 46.584 ;
     RECT  201.596 47.856 201.625 47.88 ;
     RECT  201.404 91.824 201.685 93.528 ;
     RECT  200.531 94.56 201.685 95.016 ;
     RECT  200.341 60.048 201.692 60.072 ;
     RECT  201.013 74.592 201.697 74.664 ;
     RECT  201.637 49.056 201.733 49.08 ;
     RECT  201.373 50.16 201.733 50.184 ;
     RECT  201.692 60.048 201.733 60.504 ;
     RECT  199.717 61.632 201.733 61.704 ;
     RECT  201.155 79.44 201.761 79.464 ;
     RECT  201.685 91.824 201.769 95.016 ;
     RECT  201.053 90.48 201.805 90.6 ;
     RECT  200.653 96.912 201.805 98.616 ;
     RECT  200.653 78.096 201.829 78.12 ;
     RECT  201.761 79.248 201.829 79.464 ;
     RECT  201.121 58.128 201.841 58.152 ;
     RECT  201.053 87.552 201.841 89.496 ;
     RECT  197.104 21.408 201.877 21.432 ;
     RECT  201.733 60.048 201.877 61.704 ;
     RECT  200.909 24.384 201.913 27.912 ;
     RECT  201.589 28.992 201.913 42.648 ;
     RECT  201.877 59.712 201.913 61.704 ;
     RECT  201.769 91.824 201.921 95.16 ;
     RECT  201.841 86.688 201.973 89.496 ;
     RECT  201.805 90.48 201.973 90.696 ;
     RECT  201.921 91.68 201.973 95.16 ;
     RECT  201.481 76.272 201.985 77.064 ;
     RECT  201.829 78.096 201.985 79.464 ;
     RECT  201.973 90.48 201.985 95.16 ;
     RECT  198.929 52.464 202.021 53.016 ;
     RECT  201.625 45.6 202.129 47.88 ;
     RECT  200.009 55.2 202.129 55.32 ;
     RECT  197.104 13.296 202.208 15.192 ;
     RECT  197.104 16.272 202.208 16.296 ;
     RECT  201.877 21.408 202.208 21.72 ;
     RECT  201.913 24.384 202.208 42.648 ;
     RECT  201.373 43.68 202.208 44.376 ;
     RECT  202.129 45.552 202.208 47.88 ;
     RECT  201.733 49.056 202.208 50.184 ;
     RECT  200.869 51.264 202.208 51.288 ;
     RECT  202.021 52.464 202.208 53.592 ;
     RECT  202.129 55.2 202.208 55.992 ;
     RECT  201.841 58.128 202.208 58.728 ;
     RECT  201.913 59.712 202.208 61.752 ;
     RECT  200.009 64.992 202.208 65.016 ;
     RECT  200.333 67.68 202.208 68.712 ;
     RECT  201.049 70.848 202.208 72.36 ;
     RECT  201.697 74.592 202.208 75 ;
     RECT  201.985 76.272 202.208 79.464 ;
     RECT  201.125 80.544 202.208 82.056 ;
     RECT  201.011 83.232 202.208 84.984 ;
     RECT  201.973 86.64 202.208 89.496 ;
     RECT  201.985 90.48 202.208 95.688 ;
     RECT  201.805 96.864 202.208 98.616 ;
     RECT  201.059 105.216 202.208 105.384 ;
     RECT  198.277 107.52 202.208 107.832 ;
     RECT  197.104 124.944 202.208 124.968 ;
     RECT  202.208 2.148 202.312 127.452 ;
     RECT  202.312 2.418 202.504 127.182 ;
     RECT  202.504 26.112 202.529 34.68 ;
     RECT  202.504 83.232 202.565 83.784 ;
     RECT  202.504 36.096 202.643 41.16 ;
     RECT  202.504 57.6 202.673 60.072 ;
     RECT  202.504 87.264 202.691 89.736 ;
     RECT  202.504 90.864 202.691 98.616 ;
     RECT  202.504 61.584 202.709 61.752 ;
     RECT  202.504 80.544 202.709 81.48 ;
     RECT  202.691 87.264 202.739 89.304 ;
     RECT  202.504 74.592 202.745 75.288 ;
     RECT  202.504 76.944 202.745 76.968 ;
     RECT  202.504 45.552 202.787 49.08 ;
     RECT  202.787 45.696 202.817 49.08 ;
     RECT  202.643 38.16 202.825 41.16 ;
     RECT  202.504 63.264 202.825 63.288 ;
     RECT  202.673 57.6 202.835 59.64 ;
     RECT  202.643 36.096 202.853 36.936 ;
     RECT  202.709 61.584 202.853 61.704 ;
     RECT  202.504 51.84 202.883 54.792 ;
     RECT  202.883 52.992 202.897 54.792 ;
     RECT  202.853 61.584 202.925 61.608 ;
     RECT  202.825 38.16 202.961 38.184 ;
     RECT  202.817 47.568 202.961 49.08 ;
     RECT  202.739 87.552 202.961 89.304 ;
     RECT  202.825 39.216 202.979 41.16 ;
     RECT  202.709 81.456 202.997 81.48 ;
     RECT  202.504 86.064 203.005 86.088 ;
     RECT  202.835 58.704 203.033 59.64 ;
     RECT  203.033 59.616 203.075 59.64 ;
     RECT  202.817 45.696 203.105 45.72 ;
     RECT  202.691 91.68 203.105 98.616 ;
     RECT  202.745 74.592 203.177 74.616 ;
     RECT  203.105 96.528 203.177 98.616 ;
     RECT  203.105 91.68 203.213 95.16 ;
     RECT  203.177 96.528 203.213 97.32 ;
     RECT  202.504 64.416 203.219 65.016 ;
     RECT  202.504 72.24 203.219 72.264 ;
     RECT  202.979 39.216 203.308 41.016 ;
     RECT  203.308 39.216 203.321 40.872 ;
     RECT  202.504 44.112 203.321 44.472 ;
     RECT  202.529 26.112 203.393 34.488 ;
     RECT  203.213 97.296 203.429 97.32 ;
     RECT  202.961 47.568 203.459 47.592 ;
     RECT  202.961 87.552 203.465 88.968 ;
     RECT  202.897 53.04 203.501 54.792 ;
     RECT  202.504 55.968 203.501 55.992 ;
     RECT  203.213 91.68 203.501 94.872 ;
     RECT  203.393 26.112 203.537 32.04 ;
     RECT  203.321 44.448 203.537 44.472 ;
     RECT  202.504 50.112 203.537 50.136 ;
     RECT  203.501 91.68 203.537 92.376 ;
     RECT  203.501 93.6 203.537 94.872 ;
     RECT  202.504 43.008 203.557 43.032 ;
     RECT  202.961 48.624 203.569 49.08 ;
     RECT  203.537 29.232 203.573 32.04 ;
     RECT  203.501 53.04 203.603 54.696 ;
     RECT  203.465 87.552 203.603 88.152 ;
     RECT  203.603 54.672 203.645 54.696 ;
     RECT  203.537 91.728 203.645 91.752 ;
     RECT  202.883 51.84 203.677 51.864 ;
     RECT  203.393 33.024 203.681 34.488 ;
     RECT  203.677 51.36 203.717 51.864 ;
     RECT  203.557 43.008 203.749 43.32 ;
     RECT  203.681 33.936 203.753 34.488 ;
     RECT  203.569 48.624 203.753 49.272 ;
     RECT  202.835 57.6 203.785 57.624 ;
     RECT  203.573 29.232 203.789 31.896 ;
     RECT  203.537 94.032 203.789 94.872 ;
     RECT  203.321 39.216 203.795 40.104 ;
     RECT  203.749 42.96 203.795 43.32 ;
     RECT  203.753 49.248 203.861 49.272 ;
     RECT  203.753 34.128 203.897 34.2 ;
     RECT  203.603 53.04 203.933 53.592 ;
     RECT  203.785 57.264 203.933 57.624 ;
     RECT  203.933 53.04 204.005 53.064 ;
     RECT  203.897 34.176 204.077 34.2 ;
     RECT  202.853 36.096 204.149 36.408 ;
     RECT  203.795 39.36 204.221 40.104 ;
     RECT  204.221 39.504 204.257 40.104 ;
     RECT  203.933 57.264 204.257 57.288 ;
     RECT  204.149 36.384 204.401 36.408 ;
     RECT  202.565 83.664 204.437 83.784 ;
     RECT  203.717 51.36 204.509 51.384 ;
     RECT  203.537 26.112 204.545 27.912 ;
     RECT  203.789 29.232 204.581 31.416 ;
     RECT  204.581 29.232 204.653 31.368 ;
     RECT  204.257 40.08 204.689 40.104 ;
     RECT  204.785 75.84 204.829 75.864 ;
     RECT  204.829 75.84 204.869 76.344 ;
     RECT  203.789 94.848 204.899 94.872 ;
     RECT  204.869 76.32 204.913 76.344 ;
     RECT  203.219 64.656 205.081 65.016 ;
     RECT  204.545 27.888 205.405 27.912 ;
     RECT  204.653 29.232 205.405 30.936 ;
     RECT  205.405 27.888 205.772 30.936 ;
     RECT  205.772 27.744 205.859 30.936 ;
     RECT  204.437 83.664 205.945 83.688 ;
     RECT  205.945 83.664 205.985 83.784 ;
     RECT  203.795 42.96 206.341 43.032 ;
     RECT  202.504 13.296 206.381 15.192 ;
     RECT  206.341 42.96 206.381 43.08 ;
     RECT  205.859 27.888 206.597 30.936 ;
     RECT  206.381 13.296 207.608 15.048 ;
     RECT  202.504 16.272 207.608 16.296 ;
     RECT  202.504 21.408 207.608 21.72 ;
     RECT  202.504 24.384 207.608 24.984 ;
     RECT  204.545 26.112 207.608 26.76 ;
     RECT  206.597 27.888 207.608 27.912 ;
     RECT  206.597 29.232 207.608 30.936 ;
     RECT  206.381 43.008 207.608 43.08 ;
     RECT  205.081 64.608 207.608 65.016 ;
     RECT  205.985 83.76 207.608 83.784 ;
     RECT  203.603 87.552 207.608 87.576 ;
     RECT  203.177 98.448 207.608 98.616 ;
     RECT  202.504 105.216 207.608 105.384 ;
     RECT  202.504 107.52 207.608 107.544 ;
     RECT  202.504 124.944 207.608 124.968 ;
     RECT  207.608 2.148 207.712 127.452 ;
     RECT  207.712 2.418 207.904 127.182 ;
     RECT  207.904 26.112 209.009 26.664 ;
     RECT  207.904 33.36 209.797 33.384 ;
     RECT  207.904 21.408 210.188 21.72 ;
     RECT  207.904 27.888 210.227 27.912 ;
     RECT  209.329 12.24 210.229 12.264 ;
     RECT  210.149 36.48 210.233 36.504 ;
     RECT  209.797 33.36 210.265 33.624 ;
     RECT  210.181 34.944 210.269 34.968 ;
     RECT  210.188 20.784 210.275 21.72 ;
     RECT  207.904 105.216 210.275 105.384 ;
     RECT  207.904 43.008 210.481 43.08 ;
     RECT  207.904 13.296 210.485 15.048 ;
     RECT  207.904 24.384 210.485 24.984 ;
     RECT  210.481 42.768 210.485 43.08 ;
     RECT  209.009 26.112 210.611 26.52 ;
     RECT  210.524 35.088 210.611 35.112 ;
     RECT  210.275 21.408 210.949 21.72 ;
     RECT  207.904 83.76 211.021 83.784 ;
     RECT  210.485 13.296 211.025 13.32 ;
     RECT  210.985 121.44 211.069 121.464 ;
     RECT  210.275 105.36 211.187 105.384 ;
     RECT  207.904 29.232 211.237 29.256 ;
     RECT  211.165 27.744 211.283 27.768 ;
     RECT  211.237 29.088 211.283 29.256 ;
     RECT  207.904 16.272 211.349 16.296 ;
     RECT  210.485 24.96 211.349 24.984 ;
     RECT  210.485 14.64 211.381 15.048 ;
     RECT  211.057 95.568 211.417 95.592 ;
     RECT  211.417 95.136 211.429 95.592 ;
     RECT  207.904 64.608 211.436 65.016 ;
     RECT  211.021 83.76 211.484 84.552 ;
     RECT  210.265 33.024 211.493 33.624 ;
     RECT  211.429 95.136 211.501 95.784 ;
     RECT  211.436 64.608 211.523 65.352 ;
     RECT  207.904 87.552 211.525 87.576 ;
     RECT  211.381 14.64 211.565 16.008 ;
     RECT  211.484 83.76 211.571 85.176 ;
     RECT  211.523 64.992 211.637 65.016 ;
     RECT  210.611 26.496 211.849 26.52 ;
     RECT  211.849 26.256 211.889 26.52 ;
     RECT  211.565 14.64 211.909 14.904 ;
     RECT  207.904 30.816 211.909 30.84 ;
     RECT  211.909 30.816 211.921 31.608 ;
     RECT  211.921 30.816 211.955 31.896 ;
     RECT  210.485 42.768 211.993 42.792 ;
     RECT  211.955 31.344 212.005 31.896 ;
     RECT  211.501 95.328 212.029 95.784 ;
     RECT  211.993 42.768 212.033 43.32 ;
     RECT  212.029 95.328 212.041 96.312 ;
     RECT  211.705 100.608 212.137 100.632 ;
     RECT  211.489 90.048 212.348 90.072 ;
     RECT  211.525 87.552 212.389 87.816 ;
     RECT  212.348 89.184 212.389 90.072 ;
     RECT  207.904 107.52 212.389 107.544 ;
     RECT  210.997 118.464 212.389 118.488 ;
     RECT  211.525 17.088 212.396 17.112 ;
     RECT  211.283 29.088 212.396 29.112 ;
     RECT  211.597 74.64 212.396 74.664 ;
     RECT  212.396 16.992 212.397 17.112 ;
     RECT  207.904 98.448 212.425 98.616 ;
     RECT  212.396 28.848 212.437 29.112 ;
     RECT  211.493 33.072 212.437 33.624 ;
     RECT  211.909 14.4 212.525 14.904 ;
     RECT  212.525 14.208 212.533 14.904 ;
     RECT  211.565 15.984 212.533 16.008 ;
     RECT  210.229 12.192 212.569 12.264 ;
     RECT  211.633 105.744 212.569 105.768 ;
     RECT  210.877 23.952 212.588 23.976 ;
     RECT  212.397 16.992 212.629 17.976 ;
     RECT  210.949 21.408 212.629 22.056 ;
     RECT  212.588 23.328 212.629 23.976 ;
     RECT  211.849 25.2 212.629 25.224 ;
     RECT  212.425 98.448 212.629 99.192 ;
     RECT  212.353 92.976 212.636 93 ;
     RECT  212.569 12.192 212.713 13.128 ;
     RECT  212.533 14.208 212.713 16.008 ;
     RECT  212.396 73.68 212.965 74.664 ;
     RECT  212.101 9.792 213.008 9.816 ;
     RECT  212.713 12.192 213.008 16.008 ;
     RECT  212.629 16.992 213.008 18.216 ;
     RECT  212.629 21.408 213.008 25.224 ;
     RECT  211.889 26.256 213.008 26.28 ;
     RECT  212.437 28.848 213.008 29.304 ;
     RECT  212.437 30.288 213.008 30.312 ;
     RECT  212.005 31.344 213.008 31.8 ;
     RECT  212.437 33.072 213.008 34.344 ;
     RECT  211.489 35.808 213.008 35.832 ;
     RECT  211.453 40.944 213.008 40.968 ;
     RECT  212.033 43.296 213.008 43.32 ;
     RECT  211.477 68.736 213.008 68.76 ;
     RECT  212.965 73.68 213.008 74.904 ;
     RECT  212.389 77.952 213.008 77.976 ;
     RECT  212.785 81.12 213.008 81.144 ;
     RECT  211.571 83.76 213.008 84.36 ;
     RECT  212.389 87.552 213.008 90.072 ;
     RECT  212.636 92.976 213.008 93.576 ;
     RECT  212.041 95.76 213.008 96.312 ;
     RECT  212.629 97.584 213.008 99.192 ;
     RECT  212.137 100.272 213.008 100.632 ;
     RECT  212.437 102.672 213.008 102.696 ;
     RECT  212.353 103.728 213.008 103.752 ;
     RECT  212.569 105.648 213.008 105.768 ;
     RECT  212.389 107.52 213.008 108.456 ;
     RECT  210.805 110.352 213.008 110.376 ;
     RECT  212.389 118.08 213.008 118.488 ;
     RECT  207.904 124.944 213.008 124.968 ;
     RECT  213.008 2.148 213.112 127.452 ;
     RECT  213.112 2.418 213.304 127.182 ;
     RECT  213.304 12.24 213.365 14.232 ;
     RECT  213.304 24.48 213.401 24.504 ;
     RECT  213.304 29.184 213.437 29.304 ;
     RECT  213.304 74.592 213.437 74.904 ;
     RECT  213.304 39.408 213.443 39.624 ;
     RECT  213.304 40.944 213.443 40.968 ;
     RECT  213.304 110.016 213.443 111.576 ;
     RECT  213.304 97.44 213.473 99.192 ;
     RECT  213.443 110.016 213.517 110.04 ;
     RECT  213.304 88.368 213.539 88.824 ;
     RECT  213.473 97.44 213.539 98.76 ;
     RECT  213.304 85.44 213.545 87.192 ;
     RECT  213.304 95.712 213.617 96.312 ;
     RECT  213.365 12.24 213.653 13.128 ;
     RECT  213.304 90.624 213.689 93 ;
     RECT  213.545 86.064 213.697 87.192 ;
     RECT  213.304 77.376 213.725 77.976 ;
     RECT  213.304 104.544 213.725 108.456 ;
     RECT  213.653 12.48 213.731 13.128 ;
     RECT  213.304 31.776 213.731 31.992 ;
     RECT  213.304 43.296 213.731 43.32 ;
     RECT  213.725 104.544 213.731 108.312 ;
     RECT  213.437 29.184 213.779 29.208 ;
     RECT  213.539 98.736 213.779 98.76 ;
     RECT  213.304 100.752 213.779 102.696 ;
     RECT  213.697 86.064 213.797 87.048 ;
     RECT  213.304 81.12 213.868 83.784 ;
     RECT  213.539 97.44 213.869 97.608 ;
     RECT  213.304 27.888 213.905 27.912 ;
     RECT  213.539 88.368 213.905 88.632 ;
     RECT  213.797 86.064 213.923 86.76 ;
     RECT  213.779 100.848 213.923 102.696 ;
     RECT  213.731 104.544 213.964 107.064 ;
     RECT  213.437 74.64 213.971 74.664 ;
     RECT  213.964 105.312 213.977 107.064 ;
     RECT  213.304 72.576 214.012 72.6 ;
     RECT  213.923 102.672 214.013 102.696 ;
     RECT  213.977 105.744 214.019 106.728 ;
     RECT  213.304 118.08 214.019 118.104 ;
     RECT  213.869 97.488 214.049 97.608 ;
     RECT  213.304 114.576 214.06 115.128 ;
     RECT  214.049 97.584 214.085 97.608 ;
     RECT  214.06 114.576 214.093 114.6 ;
     RECT  213.905 88.608 214.115 88.632 ;
     RECT  213.689 91.152 214.115 93 ;
     RECT  213.731 108.288 214.121 108.312 ;
     RECT  213.304 44.448 214.157 44.472 ;
     RECT  213.725 77.376 214.229 77.544 ;
     RECT  214.115 92.976 214.265 93 ;
     RECT  214.229 77.376 214.307 77.4 ;
     RECT  213.868 81.12 214.307 82.104 ;
     RECT  213.731 12.48 214.373 12.504 ;
     RECT  213.304 17.952 214.46 17.976 ;
     RECT  213.304 22.032 214.513 22.056 ;
     RECT  214.46 17.808 214.547 17.976 ;
     RECT  213.365 14.208 214.553 14.232 ;
     RECT  214.115 91.152 214.553 91.464 ;
     RECT  213.731 31.968 214.556 31.992 ;
     RECT  213.617 96.288 214.589 96.312 ;
     RECT  214.556 31.968 214.643 32.952 ;
     RECT  213.304 9.792 214.693 9.816 ;
     RECT  214.513 22.032 214.693 22.824 ;
     RECT  213.923 101.424 214.697 101.448 ;
     RECT  213.304 7.584 214.739 7.608 ;
     RECT  214.693 9.024 214.739 9.816 ;
     RECT  214.652 12.432 214.739 12.456 ;
     RECT  214.547 17.952 214.739 17.976 ;
     RECT  214.652 19.104 214.739 19.128 ;
     RECT  213.304 20.448 214.739 20.472 ;
     RECT  214.693 21.552 214.739 22.824 ;
     RECT  213.443 111.552 214.769 111.576 ;
     RECT  214.739 9.024 214.78 9.048 ;
     RECT  213.868 83.76 214.805 83.784 ;
     RECT  214.739 21.552 214.877 21.576 ;
     RECT  213.304 26.256 214.877 26.28 ;
     RECT  213.304 75.888 214.913 75.912 ;
     RECT  214.307 81.12 214.913 81.24 ;
     RECT  213.304 35.808 214.931 35.832 ;
     RECT  213.443 39.408 214.931 39.432 ;
     RECT  214.885 37.44 214.972 38.088 ;
     RECT  214.309 6.24 215.057 6.264 ;
     RECT  213.304 42.048 215.129 42.072 ;
     RECT  214.501 16.512 215.165 16.536 ;
     RECT  213.304 68.736 215.377 68.76 ;
     RECT  214.913 81.12 215.489 81.144 ;
     RECT  215.377 68.736 215.633 69 ;
     RECT  213.923 86.064 215.633 86.088 ;
     RECT  214.553 91.152 215.633 91.176 ;
     RECT  214.019 106.704 215.633 106.728 ;
     RECT  214.693 11.136 215.777 11.16 ;
     RECT  215.633 68.88 215.777 69 ;
     RECT  215.777 68.88 216.353 68.904 ;
     RECT  214.643 31.968 216.389 31.992 ;
     RECT  214.972 37.44 216.389 37.464 ;
    LAYER M5 ;
     RECT  2.4 2.137 2.52 2.151 ;
     RECT  7.8 2.137 7.92 2.151 ;
     RECT  13.2 2.137 13.32 2.151 ;
     RECT  18.6 2.137 18.72 2.151 ;
     RECT  24 2.137 24.12 2.151 ;
     RECT  29.4 2.137 29.52 2.151 ;
     RECT  34.8 2.137 34.92 2.151 ;
     RECT  40.2 2.137 40.32 2.151 ;
     RECT  45.6 2.137 45.72 2.151 ;
     RECT  51 2.137 51.12 2.151 ;
     RECT  56.4 2.137 56.52 2.151 ;
     RECT  61.8 2.137 61.92 2.151 ;
     RECT  67.2 2.137 67.32 2.151 ;
     RECT  72.6 2.137 72.72 2.151 ;
     RECT  78 2.137 78.12 2.151 ;
     RECT  83.4 2.137 83.52 2.151 ;
     RECT  88.8 2.137 88.92 2.151 ;
     RECT  94.2 2.137 94.32 2.151 ;
     RECT  99.6 2.137 99.72 2.151 ;
     RECT  105 2.137 105.12 2.151 ;
     RECT  110.4 2.137 110.52 2.151 ;
     RECT  115.8 2.137 115.92 2.151 ;
     RECT  121.2 2.137 121.32 2.151 ;
     RECT  126.6 2.137 126.72 2.151 ;
     RECT  132 2.137 132.12 2.151 ;
     RECT  137.4 2.137 137.52 2.151 ;
     RECT  142.8 2.137 142.92 2.151 ;
     RECT  148.2 2.137 148.32 2.151 ;
     RECT  153.6 2.137 153.72 2.151 ;
     RECT  159 2.137 159.12 2.151 ;
     RECT  164.4 2.137 164.52 2.151 ;
     RECT  169.8 2.137 169.92 2.151 ;
     RECT  175.2 2.137 175.32 2.151 ;
     RECT  180.6 2.137 180.72 2.151 ;
     RECT  186 2.137 186.12 2.151 ;
     RECT  191.4 2.137 191.52 2.151 ;
     RECT  196.8 2.137 196.92 2.151 ;
     RECT  202.2 2.137 202.32 2.151 ;
     RECT  207.6 2.137 207.72 2.151 ;
     RECT  213 2.137 213.12 2.151 ;
     RECT  4.8 4.693 4.824 5.077 ;
     RECT  3.888 5.077 4.824 6.995 ;
     RECT  4.8 6.995 4.824 7.333 ;
     RECT  4.8 7.333 5.112 7.381 ;
     RECT  214.32 6.229 214.344 7.573 ;
     RECT  214.32 7.573 214.728 7.619 ;
     RECT  4.8 7.381 5.256 9.155 ;
     RECT  4.8 9.155 5.16 10.307 ;
     RECT  6.672 8.485 6.696 10.741 ;
     RECT  4.8 10.307 4.824 11.941 ;
     RECT  214.704 7.619 214.728 12.467 ;
     RECT  213 2.151 213.312 13.093 ;
     RECT  61.8 2.151 62.112 13.525 ;
     RECT  4.56 11.941 4.824 13.669 ;
     RECT  213 13.093 213.72 14.197 ;
     RECT  212.544 14.197 213.72 14.243 ;
     RECT  13.2 2.151 13.512 14.341 ;
     RECT  212.544 14.243 213.312 14.389 ;
     RECT  70.272 13.813 70.296 14.629 ;
     RECT  5.808 10.741 6.696 14.773 ;
     RECT  7.8 2.151 8.112 14.773 ;
     RECT  4.464 13.669 4.824 14.867 ;
     RECT  211.92 14.389 213.312 14.915 ;
     RECT  61.8 13.525 62.856 15.253 ;
     RECT  4.8 14.867 4.824 15.443 ;
     RECT  5.808 14.773 8.112 15.829 ;
     RECT  212.544 14.915 213.312 16.019 ;
     RECT  91.68 13.813 91.704 16.595 ;
     RECT  5.808 15.829 8.232 16.883 ;
     RECT  213 16.019 213.312 16.981 ;
     RECT  214.512 16.501 214.536 17.843 ;
     RECT  212.448 16.981 213.312 17.987 ;
     RECT  10.944 16.405 10.968 18.275 ;
     RECT  13.2 14.341 13.944 18.515 ;
     RECT  21.504 18.709 21.528 19.429 ;
     RECT  21.504 19.429 22.2 19.667 ;
     RECT  21.792 19.667 22.2 19.909 ;
     RECT  15.792 18.565 15.816 20.867 ;
     RECT  45.6 2.151 45.912 20.917 ;
     RECT  49.776 20.389 49.8 21.443 ;
     RECT  202.2 2.151 202.512 21.685 ;
     RECT  51 2.151 51.312 21.925 ;
     RECT  52.848 21.637 52.872 21.925 ;
     RECT  33.312 18.133 33.336 22.165 ;
     RECT  56.4 2.151 56.712 22.165 ;
     RECT  40.2 2.151 40.512 22.213 ;
     RECT  4.512 20.485 4.536 22.259 ;
     RECT  21.792 19.909 22.248 22.259 ;
     RECT  61.248 15.253 62.856 22.259 ;
     RECT  51 21.925 52.872 22.451 ;
     RECT  13.2 18.515 13.704 22.549 ;
     RECT  26.112 21.637 26.136 22.645 ;
     RECT  25.68 22.645 26.136 22.691 ;
     RECT  28.032 22.165 28.056 22.691 ;
     RECT  16.176 21.637 16.2 22.741 ;
     RECT  16.176 22.741 16.824 22.835 ;
     RECT  55.536 22.165 56.712 22.835 ;
     RECT  61.248 22.259 62.112 22.835 ;
     RECT  214.704 17.941 214.728 22.835 ;
     RECT  33.312 22.165 33.624 22.883 ;
     RECT  25.68 22.691 25.704 23.075 ;
     RECT  18.6 2.151 18.912 23.125 ;
     RECT  21.792 22.259 22.2 23.125 ;
     RECT  56.4 22.835 56.712 23.125 ;
     RECT  13.2 22.549 13.896 23.315 ;
     RECT  5.808 16.883 8.112 23.317 ;
     RECT  29.4 2.151 29.712 23.317 ;
     RECT  39.84 22.213 40.512 23.317 ;
     RECT  51 22.451 52.2 23.317 ;
     RECT  44.112 22.165 44.136 23.363 ;
     RECT  45.6 20.917 46.152 23.363 ;
     RECT  13.2 23.315 13.8 23.411 ;
     RECT  70.08 14.629 70.296 23.411 ;
     RECT  54 22.405 54.024 23.555 ;
     RECT  61.8 22.835 62.112 23.797 ;
     RECT  29.04 23.317 29.712 23.845 ;
     RECT  18.6 23.125 19.176 23.941 ;
     RECT  56.4 23.125 57.144 24.083 ;
     RECT  21.456 23.125 22.2 24.085 ;
     RECT  18.48 23.941 19.176 24.181 ;
     RECT  21.456 24.085 22.776 24.325 ;
     RECT  13.2 23.411 13.608 24.371 ;
     RECT  61.8 23.797 62.712 24.419 ;
     RECT  16.8 22.835 16.824 24.469 ;
     RECT  24 2.151 24.312 24.469 ;
     RECT  50.736 23.317 52.2 24.469 ;
     RECT  39.84 23.317 41.496 24.515 ;
     RECT  212.64 17.987 213.312 24.515 ;
     RECT  50.736 24.469 52.632 24.611 ;
     RECT  41.808 24.661 41.832 24.803 ;
     RECT  50.88 24.611 52.632 24.947 ;
     RECT  58.992 24.853 59.016 24.995 ;
     RECT  29.04 23.845 30.552 25.043 ;
     RECT  18.48 24.181 19.656 25.045 ;
     RECT  20.736 24.325 22.776 25.045 ;
     RECT  24 24.469 24.792 25.139 ;
     RECT  33.312 22.883 33.336 25.139 ;
     RECT  39.84 24.515 40.512 25.139 ;
     RECT  54.336 24.469 54.36 25.189 ;
     RECT  0.144 24.325 0.168 25.235 ;
     RECT  196.8 2.151 197.112 25.237 ;
     RECT  198.144 24.997 198.168 25.237 ;
     RECT  26.496 23.701 26.52 25.331 ;
     RECT  43.92 23.845 43.944 25.331 ;
     RECT  54.336 25.189 54.84 25.427 ;
     RECT  108.864 23.317 108.888 25.429 ;
     RECT  108.864 25.429 109.08 25.475 ;
     RECT  167.664 25.045 167.688 25.475 ;
     RECT  139.296 24.805 139.32 25.523 ;
     RECT  196.8 25.237 198.168 25.525 ;
     RECT  54.816 25.427 54.84 25.571 ;
     RECT  15.936 24.469 16.824 25.669 ;
     RECT  40.08 25.139 40.512 25.715 ;
     RECT  47.088 25.045 47.112 25.763 ;
     RECT  50.88 24.947 52.248 25.763 ;
     RECT  200.4 24.325 200.424 25.813 ;
     RECT  196.8 25.525 198.216 26.005 ;
     RECT  15.744 25.669 16.824 26.101 ;
     RECT  210.24 12.181 210.264 26.101 ;
     RECT  61.8 24.419 62.232 26.147 ;
     RECT  166.368 25.621 166.392 26.147 ;
     RECT  15.744 26.101 17.304 26.243 ;
     RECT  199.776 25.813 200.424 26.437 ;
     RECT  201.888 21.685 202.512 26.581 ;
     RECT  16.8 26.243 17.304 26.819 ;
     RECT  5.088 23.317 8.112 26.965 ;
     RECT  13.2 24.371 13.512 27.061 ;
     RECT  5.088 26.965 8.376 27.587 ;
     RECT  12.912 27.061 13.512 27.589 ;
     RECT  210.24 26.101 210.6 27.733 ;
     RECT  79.776 25.621 79.8 27.779 ;
     RECT  9.456 26.053 9.48 27.877 ;
     RECT  15.744 26.243 15.768 27.877 ;
     RECT  16.8 26.819 16.824 27.877 ;
     RECT  210.24 27.733 211.272 27.877 ;
     RECT  213 24.515 213.312 27.877 ;
     RECT  9.12 27.877 9.48 28.019 ;
     RECT  5.088 27.587 8.112 28.261 ;
     RECT  205.824 27.733 205.848 28.835 ;
     RECT  213 27.877 213.768 28.837 ;
     RECT  18.48 25.045 22.776 28.883 ;
     RECT  15.744 27.877 16.824 29.077 ;
     RECT  212.448 28.837 213.768 29.219 ;
     RECT  199.728 26.437 200.424 29.221 ;
     RECT  201.456 26.581 202.512 29.221 ;
     RECT  14.88 29.077 16.824 29.267 ;
     RECT  210.192 27.877 211.272 29.267 ;
     RECT  199.728 29.221 202.512 29.603 ;
     RECT  204.144 29.221 204.168 29.603 ;
     RECT  196.8 26.005 198.312 29.795 ;
     RECT  196.8 29.795 198.216 29.987 ;
     RECT  10.992 25.765 11.016 30.181 ;
     RECT  4.656 28.261 8.112 30.275 ;
     RECT  15.744 29.267 16.824 30.325 ;
     RECT  201.456 29.603 202.512 30.421 ;
     RECT  15.744 30.325 17.064 30.757 ;
     RECT  212.448 29.219 213.312 30.805 ;
     RECT  10.848 30.181 11.016 31.091 ;
     RECT  196.8 29.987 198.12 31.187 ;
     RECT  15.744 30.757 17.352 31.285 ;
     RECT  18.48 28.883 22.728 31.285 ;
     RECT  211.92 30.805 213.312 31.619 ;
     RECT  211.968 31.619 213.312 31.765 ;
     RECT  211.968 31.765 213.72 31.811 ;
     RECT  201.456 30.421 202.968 31.907 ;
     RECT  5.088 30.275 8.112 31.909 ;
     RECT  9.456 28.019 9.48 31.909 ;
     RECT  10.992 31.091 11.016 31.909 ;
     RECT  12.288 27.589 13.512 31.909 ;
     RECT  15.744 31.285 22.728 31.955 ;
     RECT  213 31.811 213.72 31.957 ;
     RECT  213 31.957 214.632 32.003 ;
     RECT  2.4 2.151 2.712 32.917 ;
     RECT  214.608 32.003 214.632 32.963 ;
     RECT  211.968 31.811 211.992 33.061 ;
     RECT  213 32.003 213.312 33.061 ;
     RECT  18.6 31.955 22.728 33.107 ;
     RECT  18.6 33.107 22.68 33.203 ;
     RECT  10.992 31.909 13.512 33.589 ;
     RECT  201.456 31.907 202.512 33.589 ;
     RECT  10.992 33.589 13.656 33.683 ;
     RECT  2.4 32.917 3.24 34.115 ;
     RECT  12.288 33.683 13.656 34.211 ;
     RECT  5.088 31.909 9.48 34.259 ;
     RECT  211.968 33.061 213.312 34.355 ;
     RECT  10.992 33.683 11.016 34.453 ;
     RECT  210.192 29.267 210.6 35.123 ;
     RECT  5.088 34.259 8.112 35.413 ;
     RECT  9.456 34.259 9.48 35.413 ;
     RECT  2.4 34.115 3.192 35.459 ;
     RECT  210.192 35.123 210.264 36.515 ;
     RECT  15.744 31.955 17.352 36.805 ;
     RECT  18.6 33.203 22.632 36.805 ;
     RECT  199.728 29.603 200.424 36.997 ;
     RECT  201.456 33.589 202.824 36.997 ;
     RECT  15.744 36.805 22.632 37.091 ;
     RECT  5.088 35.413 9.48 37.429 ;
     RECT  4.512 37.429 9.48 37.669 ;
     RECT  10.56 34.453 11.016 37.669 ;
     RECT  4.512 37.669 11.016 38.005 ;
     RECT  4.512 38.005 11.304 38.099 ;
     RECT  4.512 38.099 8.112 38.677 ;
     RECT  3.696 38.677 8.112 38.819 ;
     RECT  199.728 36.997 202.824 39.061 ;
     RECT  199.584 39.061 202.824 39.205 ;
     RECT  199.584 39.205 203.784 39.251 ;
     RECT  213 34.355 213.312 39.397 ;
     RECT  214.896 35.797 214.92 39.443 ;
     RECT  9.456 38.099 11.304 39.491 ;
     RECT  20.208 37.091 22.632 40.499 ;
     RECT  213 39.397 213.432 40.979 ;
     RECT  15.744 37.091 18.912 40.981 ;
     RECT  20.208 40.499 20.232 40.981 ;
     RECT  4.512 38.819 8.112 41.075 ;
     RECT  5.088 41.075 8.112 41.509 ;
     RECT  9.456 39.491 9.48 41.509 ;
     RECT  213 40.979 213.312 42.037 ;
     RECT  5.088 41.509 9.48 42.803 ;
     RECT  10.56 39.491 11.304 43.285 ;
     RECT  12.288 34.211 13.512 43.285 ;
     RECT  199.728 39.251 203.784 43.331 ;
     RECT  213 42.037 213.72 43.331 ;
     RECT  5.952 42.803 9.48 44.437 ;
     RECT  213 43.331 213.624 44.483 ;
     RECT  5.952 44.437 9.576 48.277 ;
     RECT  10.56 43.285 13.512 48.421 ;
     RECT  5.52 48.277 9.576 49.043 ;
     RECT  199.728 43.331 203.592 49.045 ;
     RECT  199.728 49.045 203.64 49.283 ;
     RECT  10.56 48.421 14.232 49.475 ;
     RECT  5.952 49.043 9.576 51.253 ;
     RECT  10.56 49.475 13.512 51.253 ;
     RECT  5.952 51.253 13.512 51.733 ;
     RECT  5.952 51.733 13.608 52.163 ;
     RECT  196.8 31.187 197.784 52.981 ;
     RECT  10.56 52.163 13.608 53.027 ;
     RECT  21.36 40.499 22.632 53.605 ;
     RECT  21.36 53.605 22.824 53.891 ;
     RECT  21.36 53.891 22.632 54.083 ;
     RECT  10.56 53.027 13.512 54.661 ;
     RECT  196.8 52.981 198.072 55.189 ;
     RECT  15.744 40.981 20.232 55.573 ;
     RECT  21.36 54.083 22.536 55.573 ;
     RECT  15.744 55.573 22.536 55.763 ;
     RECT  10.56 54.661 13.608 55.813 ;
     RECT  5.952 52.163 9.48 55.907 ;
     RECT  4.32 55.861 4.344 56.483 ;
     RECT  10.56 55.813 13.848 56.483 ;
     RECT  21.36 55.763 22.536 57.059 ;
     RECT  5.952 55.907 9.432 57.445 ;
     RECT  10.56 56.483 13.512 57.445 ;
     RECT  15.744 55.763 20.232 58.117 ;
     RECT  5.952 57.445 13.512 58.645 ;
     RECT  3.936 58.645 4.632 58.835 ;
     RECT  15.456 58.117 20.232 59.221 ;
     RECT  5.76 58.645 13.512 60.035 ;
     RECT  4.608 58.835 4.632 61.139 ;
     RECT  196.8 55.189 198.648 61.669 ;
     RECT  199.728 49.283 203.592 61.669 ;
     RECT  4.896 61.381 4.92 62.147 ;
     RECT  21.36 57.059 22.488 62.339 ;
     RECT  5.952 60.035 13.512 62.531 ;
     RECT  14.928 59.221 20.232 62.629 ;
     RECT  14.832 62.629 20.232 63.059 ;
     RECT  14.832 63.059 19.272 63.299 ;
     RECT  21.36 62.339 22.008 63.541 ;
     RECT  21.36 63.541 22.248 63.731 ;
     RECT  3.744 62.725 3.768 63.875 ;
     RECT  15.744 63.299 19.272 63.923 ;
     RECT  5.952 62.531 11.352 64.451 ;
     RECT  211.968 34.355 211.992 64.597 ;
     RECT  10.416 64.451 11.352 64.979 ;
     RECT  21.36 63.731 21.912 66.563 ;
     RECT  16.8 63.923 19.272 66.661 ;
     RECT  2.4 35.459 2.712 66.901 ;
     RECT  15.744 63.923 15.768 66.901 ;
     RECT  16.8 66.661 19.368 66.901 ;
     RECT  12.72 62.531 13.512 67.765 ;
     RECT  196.8 61.669 203.592 67.859 ;
     RECT  211.488 64.597 211.992 68.771 ;
     RECT  21.36 66.563 21.816 69.491 ;
     RECT  2.4 66.901 3.528 70.115 ;
     RECT  12.72 67.765 14.184 70.789 ;
     RECT  15.744 66.901 19.368 70.789 ;
     RECT  12.72 70.789 19.368 70.835 ;
     RECT  14.832 70.835 19.368 72.035 ;
     RECT  10.56 64.979 11.352 72.325 ;
     RECT  213 44.483 213.312 72.565 ;
     RECT  10.56 72.325 11.4 73.523 ;
     RECT  211.968 68.771 211.992 73.669 ;
     RECT  213 72.565 213.96 73.669 ;
     RECT  211.968 73.669 213.96 74.675 ;
     RECT  4.32 73.477 4.344 74.723 ;
     RECT  5.952 64.451 9.432 75.157 ;
     RECT  10.56 73.523 11.352 75.157 ;
     RECT  5.952 75.157 11.352 75.253 ;
     RECT  204.816 64.933 204.84 75.875 ;
     RECT  213 74.675 213.96 75.877 ;
     RECT  2.4 70.115 2.712 76.885 ;
     RECT  5.136 75.253 11.352 76.979 ;
     RECT  213 75.877 214.296 77.411 ;
     RECT  2.4 76.885 3.432 77.555 ;
     RECT  10.56 76.979 11.352 78.371 ;
     RECT  21.792 69.491 21.816 78.421 ;
     RECT  15.744 72.035 19.368 78.899 ;
     RECT  213 77.411 213.312 81.205 ;
     RECT  4.224 80.773 4.248 81.587 ;
     RECT  213 81.205 214.296 82.115 ;
     RECT  10.656 78.371 11.352 82.117 ;
     RECT  4.512 82.021 4.536 83.219 ;
     RECT  213 82.115 213.816 83.795 ;
     RECT  211.968 74.675 211.992 84.325 ;
     RECT  213 83.795 213.312 86.053 ;
     RECT  4.704 84.949 4.728 86.195 ;
     RECT  15.744 78.899 19.272 86.629 ;
     RECT  213 86.053 213.912 86.771 ;
     RECT  196.8 67.859 199.224 87.397 ;
     RECT  211.536 84.325 211.992 87.781 ;
     RECT  213 86.771 213.672 87.781 ;
     RECT  211.536 87.781 213.672 87.827 ;
     RECT  2.4 77.555 2.712 87.973 ;
     RECT  21.36 78.421 21.816 88.117 ;
     RECT  200.304 67.859 203.592 88.163 ;
     RECT  15.744 86.629 19.368 88.309 ;
     RECT  211.968 87.827 213.672 88.597 ;
     RECT  12.72 70.835 13.512 88.885 ;
     RECT  200.304 88.163 203.256 88.979 ;
     RECT  2.4 87.973 2.808 89.459 ;
     RECT  5.952 76.979 9.432 89.461 ;
     RECT  10.56 82.117 11.352 89.461 ;
     RECT  5.952 89.461 11.352 89.651 ;
     RECT  196.8 87.397 199.272 89.989 ;
     RECT  200.304 88.979 203.016 89.989 ;
     RECT  6.672 89.651 11.352 90.083 ;
     RECT  211.968 88.597 214.104 90.083 ;
     RECT  15.744 88.309 19.656 91.235 ;
     RECT  12.72 88.885 13.608 91.859 ;
     RECT  196.8 89.989 203.016 91.859 ;
     RECT  213 90.083 214.104 92.099 ;
     RECT  10.56 90.083 11.352 92.341 ;
     RECT  200.304 91.859 203.016 92.387 ;
     RECT  211.968 90.083 211.992 92.965 ;
     RECT  213 92.099 213.528 92.965 ;
     RECT  21.36 88.117 21.912 93.349 ;
     RECT  211.968 92.965 213.528 93.587 ;
     RECT  200.304 92.387 202.632 94.021 ;
     RECT  196.8 91.859 199.272 94.453 ;
     RECT  200.304 94.021 202.92 94.453 ;
     RECT  6.672 90.083 9.432 94.549 ;
     RECT  10.56 92.341 11.4 94.595 ;
     RECT  196.8 94.453 202.92 94.595 ;
     RECT  204.864 76.309 204.888 94.883 ;
     RECT  211.968 93.587 211.992 95.125 ;
     RECT  200.304 94.595 202.92 95.171 ;
     RECT  200.304 95.171 202.632 95.219 ;
     RECT  211.44 95.125 211.992 95.363 ;
     RECT  6.048 94.549 9.432 95.557 ;
     RECT  210.24 36.515 210.264 95.557 ;
     RECT  211.44 95.363 211.464 95.557 ;
     RECT  210.24 95.557 211.464 95.795 ;
     RECT  10.56 94.595 11.208 95.939 ;
     RECT  200.304 95.219 202.512 96.517 ;
     RECT  213 93.587 213.528 97.429 ;
     RECT  21.36 93.349 21.96 97.525 ;
     RECT  213 97.429 213.768 97.573 ;
     RECT  5.904 95.557 9.432 97.621 ;
     RECT  200.304 96.517 202.968 98.147 ;
     RECT  196.8 94.595 199.272 98.197 ;
     RECT  200.304 98.147 202.512 98.197 ;
     RECT  5.088 97.621 9.432 98.339 ;
     RECT  21.36 97.525 22.248 98.389 ;
     RECT  196.8 98.197 202.512 98.435 ;
     RECT  212.64 97.573 213.768 98.675 ;
     RECT  21.36 98.389 22.632 98.773 ;
     RECT  16.8 91.235 19.656 98.915 ;
     RECT  78 2.151 78.312 99.445 ;
     RECT  21.36 98.773 22.776 99.587 ;
     RECT  21.36 99.587 21.912 99.685 ;
     RECT  83.4 2.151 83.712 99.973 ;
     RECT  5.52 98.339 9.432 100.261 ;
     RECT  213 98.675 213.768 100.261 ;
     RECT  21.072 99.685 21.912 100.451 ;
     RECT  16.944 98.915 19.656 100.499 ;
     RECT  88.8 2.151 89.112 100.501 ;
     RECT  186 2.151 186.312 100.549 ;
     RECT  16.944 100.499 19.272 100.595 ;
     RECT  144.672 100.405 144.696 100.595 ;
     RECT  82.608 99.973 83.712 100.597 ;
     RECT  94.2 2.151 94.512 100.597 ;
     RECT  67.2 2.151 67.512 100.645 ;
     RECT  88.8 100.501 89.208 100.691 ;
     RECT  56.4 24.083 56.712 100.693 ;
     RECT  51 25.763 52.248 100.741 ;
     RECT  4.56 100.261 9.432 100.789 ;
     RECT  56.304 100.693 56.712 100.789 ;
     RECT  40.2 25.715 40.512 100.837 ;
     RECT  45.6 23.363 45.912 100.837 ;
     RECT  109.056 25.475 109.08 100.837 ;
     RECT  110.4 2.151 110.712 100.837 ;
     RECT  212.448 100.261 213.768 100.837 ;
     RECT  74.112 98.869 74.136 100.931 ;
     RECT  112.176 23.269 112.2 100.979 ;
     RECT  78 99.445 78.744 100.981 ;
     RECT  26.928 100.837 26.952 101.029 ;
     RECT  24 25.139 24.312 101.125 ;
     RECT  50.88 100.741 52.248 101.219 ;
     RECT  82.512 100.597 83.712 101.221 ;
     RECT  109.056 100.837 110.712 101.267 ;
     RECT  4.56 100.789 9.672 101.315 ;
     RECT  16.944 100.595 19.176 101.363 ;
     RECT  74.496 101.221 74.52 101.365 ;
     RECT  32.928 101.221 32.952 101.413 ;
     RECT  43.296 100.789 43.32 101.413 ;
     RECT  44.448 101.077 44.472 101.413 ;
     RECT  43.296 101.413 44.472 101.459 ;
     RECT  74.496 101.365 74.616 101.459 ;
     RECT  82.224 101.221 83.712 101.459 ;
     RECT  109.056 101.267 109.08 101.507 ;
     RECT  32.928 101.413 33.576 101.555 ;
     RECT  21.36 100.451 21.912 101.651 ;
     RECT  50.88 101.219 51.312 101.699 ;
     RECT  5.52 101.315 9.672 101.747 ;
     RECT  82.224 101.459 82.248 101.747 ;
     RECT  200.304 98.435 202.512 101.747 ;
     RECT  15.744 91.235 15.768 102.083 ;
     RECT  29.04 25.043 29.712 102.083 ;
     RECT  24 101.125 24.408 102.421 ;
     RECT  11.184 95.939 11.208 102.565 ;
     RECT  110.4 101.267 110.712 102.565 ;
     RECT  11.088 102.565 11.208 102.611 ;
     RECT  21.792 101.651 21.912 103.283 ;
     RECT  40.08 100.837 40.512 103.331 ;
     RECT  74.592 101.459 74.616 103.379 ;
     RECT  67.2 100.645 67.848 103.523 ;
     RECT  5.52 101.747 9.432 103.525 ;
     RECT  212.448 100.837 213.912 103.763 ;
     RECT  5.52 103.525 9.672 103.813 ;
     RECT  5.52 103.813 9.96 103.907 ;
     RECT  78 100.981 78.936 103.907 ;
     RECT  5.52 103.907 5.544 103.909 ;
     RECT  4.704 103.909 5.544 104.051 ;
     RECT  94.2 100.597 94.872 104.051 ;
     RECT  43.296 101.459 44.088 104.147 ;
     RECT  196.8 98.435 199.272 104.387 ;
     RECT  45.6 100.837 46.152 104.579 ;
     RECT  213 103.763 213.912 104.579 ;
     RECT  200.304 101.747 201.048 104.915 ;
     RECT  26.928 101.029 27.624 104.963 ;
     RECT  16.944 101.363 19.128 105.059 ;
     RECT  26.928 104.963 26.952 105.251 ;
     RECT  109.824 102.565 110.712 105.251 ;
     RECT  210.24 95.795 211.176 105.251 ;
     RECT  16.944 105.059 19.08 105.347 ;
     RECT  16.944 105.347 18.912 105.395 ;
     RECT  211.152 105.251 211.176 105.395 ;
     RECT  24 102.421 24.456 105.491 ;
     RECT  6.864 103.907 9.96 105.683 ;
     RECT  21.792 103.283 21.816 105.683 ;
     RECT  213 104.579 213.72 105.733 ;
     RECT  9.936 105.683 9.96 105.781 ;
     RECT  11.088 102.611 11.112 105.781 ;
     RECT  111.984 101.413 112.008 106.451 ;
     RECT  196.8 104.387 198.504 106.595 ;
     RECT  6.864 105.683 8.856 106.597 ;
     RECT  213 105.733 214.008 106.739 ;
     RECT  4.704 104.051 4.728 107.027 ;
     RECT  9.936 105.781 11.112 107.075 ;
     RECT  213 106.739 213.72 107.411 ;
     RECT  10.848 107.075 11.112 107.555 ;
     RECT  6.672 106.597 8.856 107.557 ;
     RECT  6.336 107.557 8.856 107.605 ;
     RECT  196.8 106.595 197.112 107.701 ;
     RECT  198.48 106.595 198.504 107.795 ;
     RECT  202.032 101.747 202.512 107.843 ;
     RECT  4.272 107.125 4.296 108.083 ;
     RECT  6.336 107.605 8.952 108.995 ;
     RECT  44.064 104.147 44.088 109.091 ;
     RECT  10.848 107.555 10.872 109.141 ;
     RECT  10.848 109.141 11.256 109.187 ;
     RECT  32.928 101.555 32.952 109.187 ;
     RECT  6.864 108.995 8.952 109.475 ;
     RECT  213 107.411 213.48 110.051 ;
     RECT  12.72 91.859 13.512 110.485 ;
     RECT  11.232 109.187 11.256 111.109 ;
     RECT  12.384 110.485 13.512 111.109 ;
     RECT  213 110.051 213.432 111.541 ;
     RECT  11.232 111.109 13.512 111.589 ;
     RECT  11.232 111.589 13.608 113.891 ;
     RECT  6.864 109.475 8.856 114.035 ;
     RECT  5.712 114.469 5.736 114.565 ;
     RECT  213 111.541 214.056 114.611 ;
     RECT  5.712 114.565 5.784 115.187 ;
     RECT  16.944 105.395 17.352 116.483 ;
     RECT  11.232 113.891 11.832 116.723 ;
     RECT  47.376 104.245 47.4 117.107 ;
     RECT  55.536 100.789 56.712 117.109 ;
     RECT  5.76 115.187 5.784 117.443 ;
     RECT  55.296 117.109 56.712 117.443 ;
     RECT  213 114.611 214.008 118.115 ;
     RECT  16.944 116.483 16.968 118.355 ;
     RECT  24 105.491 24.408 118.979 ;
     RECT  11.232 116.723 11.256 119.027 ;
     RECT  6.288 118.981 6.312 119.939 ;
     RECT  13.2 113.891 13.608 119.987 ;
     RECT  29.4 102.083 29.712 120.229 ;
     RECT  185.616 100.549 186.312 120.995 ;
     RECT  195.168 106.885 195.192 121.043 ;
     RECT  196.32 107.701 197.112 121.331 ;
     RECT  211.008 118.453 211.032 121.475 ;
     RECT  7.8 114.035 8.856 121.813 ;
     RECT  7.344 121.813 8.856 122.147 ;
     RECT  29.4 120.229 30.12 124.163 ;
     RECT  7.344 122.147 8.112 125.459 ;
     RECT  200.304 104.915 200.328 127.283 ;
     RECT  2.4 89.459 2.712 127.449 ;
     RECT  7.8 125.459 8.112 127.449 ;
     RECT  13.2 119.987 13.512 127.449 ;
     RECT  18.6 105.395 18.912 127.449 ;
     RECT  24 118.979 24.312 127.449 ;
     RECT  29.4 124.163 29.712 127.449 ;
     RECT  34.8 2.151 35.112 127.449 ;
     RECT  40.2 103.331 40.512 127.449 ;
     RECT  45.6 104.579 45.912 127.449 ;
     RECT  51 101.699 51.312 127.449 ;
     RECT  55.488 117.443 56.712 127.449 ;
     RECT  61.8 26.147 62.112 127.449 ;
     RECT  67.2 103.523 67.512 127.449 ;
     RECT  72.6 2.151 72.912 127.449 ;
     RECT  78 103.907 78.312 127.449 ;
     RECT  83.4 101.459 83.712 127.449 ;
     RECT  88.8 100.691 89.112 127.449 ;
     RECT  94.2 104.051 94.512 127.449 ;
     RECT  99.6 2.151 99.912 127.449 ;
     RECT  105 2.151 105.312 127.449 ;
     RECT  110.4 105.251 110.712 127.449 ;
     RECT  115.8 2.151 116.112 127.449 ;
     RECT  121.2 2.151 121.512 127.449 ;
     RECT  126.6 2.151 126.912 127.449 ;
     RECT  132 2.151 132.312 127.449 ;
     RECT  137.4 2.151 137.712 127.449 ;
     RECT  142.8 2.151 143.112 127.449 ;
     RECT  148.2 2.151 148.512 127.449 ;
     RECT  153.6 2.151 153.912 127.449 ;
     RECT  159 2.151 159.312 127.449 ;
     RECT  164.4 2.151 164.712 127.449 ;
     RECT  169.8 2.151 170.112 127.449 ;
     RECT  175.2 2.151 175.512 127.449 ;
     RECT  180.6 2.151 180.912 127.449 ;
     RECT  186 120.995 186.312 127.449 ;
     RECT  191.4 2.151 191.712 127.449 ;
     RECT  196.8 121.331 197.112 127.449 ;
     RECT  202.2 107.843 202.512 127.449 ;
     RECT  207.6 2.151 207.912 127.449 ;
     RECT  213 118.115 213.312 127.449 ;
     RECT  2.4 127.449 2.52 127.463 ;
     RECT  7.8 127.449 7.92 127.463 ;
     RECT  13.2 127.449 13.32 127.463 ;
     RECT  18.6 127.449 18.72 127.463 ;
     RECT  24 127.449 24.12 127.463 ;
     RECT  29.4 127.449 29.52 127.463 ;
     RECT  34.8 127.449 34.92 127.463 ;
     RECT  40.2 127.449 40.32 127.463 ;
     RECT  45.6 127.449 45.72 127.463 ;
     RECT  51 127.449 51.12 127.463 ;
     RECT  55.488 127.449 56.52 127.463 ;
     RECT  61.8 127.449 61.92 127.463 ;
     RECT  67.2 127.449 67.32 127.463 ;
     RECT  72.6 127.449 72.72 127.463 ;
     RECT  78 127.449 78.12 127.463 ;
     RECT  83.4 127.449 83.52 127.463 ;
     RECT  88.8 127.449 88.92 127.463 ;
     RECT  94.2 127.449 94.32 127.463 ;
     RECT  99.6 127.449 99.72 127.463 ;
     RECT  105 127.449 105.12 127.463 ;
     RECT  110.4 127.449 110.52 127.463 ;
     RECT  115.8 127.449 115.92 127.463 ;
     RECT  121.2 127.449 121.32 127.463 ;
     RECT  126.6 127.449 126.72 127.463 ;
     RECT  132 127.449 132.12 127.463 ;
     RECT  137.4 127.449 137.52 127.463 ;
     RECT  142.8 127.449 142.92 127.463 ;
     RECT  148.2 127.449 148.32 127.463 ;
     RECT  153.6 127.449 153.72 127.463 ;
     RECT  159 127.449 159.12 127.463 ;
     RECT  164.4 127.449 164.52 127.463 ;
     RECT  169.8 127.449 169.92 127.463 ;
     RECT  175.2 127.449 175.32 127.463 ;
     RECT  180.6 127.449 180.72 127.463 ;
     RECT  186 127.449 186.12 127.463 ;
     RECT  191.4 127.449 191.52 127.463 ;
     RECT  196.8 127.449 196.92 127.463 ;
     RECT  202.2 127.449 202.32 127.463 ;
     RECT  207.6 127.449 207.72 127.463 ;
     RECT  213 127.449 213.12 127.463 ;
     RECT  2.712 5.077 3.888 6.995 ;
     RECT  213.312 6.229 214.32 7.619 ;
     RECT  213.312 7.619 214.704 12.467 ;
     RECT  5.256 8.485 6.672 9.155 ;
     RECT  6.696 8.485 7.8 14.773 ;
     RECT  5.16 9.155 6.672 10.307 ;
     RECT  4.824 10.307 6.672 10.741 ;
     RECT  4.824 10.741 5.808 15.443 ;
     RECT  213.312 12.467 213.72 13.093 ;
     RECT  212.544 16.019 213 16.981 ;
     RECT  213.312 16.501 214.512 17.843 ;
     RECT  213.312 17.843 214.536 17.941 ;
     RECT  213.312 17.941 214.704 22.835 ;
     RECT  33.336 18.133 34.8 22.165 ;
     RECT  49.8 20.389 51 21.443 ;
     RECT  4.536 20.485 5.808 22.259 ;
     RECT  28.056 22.165 29.4 22.691 ;
     RECT  33.624 22.165 34.8 22.883 ;
     RECT  44.136 22.165 45.6 23.363 ;
     RECT  5.088 22.259 5.808 23.317 ;
     RECT  52.872 22.405 54 22.451 ;
     RECT  54.024 22.405 55.536 22.835 ;
     RECT  24.312 22.645 25.68 23.075 ;
     RECT  29.04 22.691 29.4 23.317 ;
     RECT  33.336 22.883 34.8 25.139 ;
     RECT  24.312 23.075 24.792 24.469 ;
     RECT  110.712 23.269 112.176 100.979 ;
     RECT  108.888 23.317 110.4 25.429 ;
     RECT  22.776 24.085 24 28.883 ;
     RECT  19.656 24.325 20.736 25.045 ;
     RECT  200.424 24.325 201.888 26.581 ;
     RECT  40.512 24.515 41.496 24.661 ;
     RECT  40.512 24.661 41.808 24.803 ;
     RECT  197.112 24.997 198.144 25.237 ;
     RECT  45.912 25.045 47.088 25.763 ;
     RECT  109.08 25.429 110.4 100.837 ;
     RECT  78.312 25.621 79.776 27.779 ;
     RECT  198.312 26.005 199.776 26.437 ;
     RECT  8.112 26.053 9.456 26.965 ;
     RECT  9.48 26.053 10.992 30.181 ;
     RECT  17.304 26.101 18.48 26.819 ;
     RECT  15.768 26.243 16.8 27.877 ;
     RECT  198.312 26.437 199.728 29.795 ;
     RECT  200.424 26.581 201.456 29.221 ;
     RECT  8.376 26.965 9.456 27.587 ;
     RECT  8.112 27.587 9.456 27.877 ;
     RECT  11.016 27.589 12.288 31.909 ;
     RECT  8.112 27.877 9.12 28.019 ;
     RECT  8.112 28.019 9.456 31.909 ;
     RECT  211.272 28.837 212.448 29.267 ;
     RECT  22.728 28.883 24 33.107 ;
     RECT  13.512 29.077 14.88 29.267 ;
     RECT  200.424 29.603 201.456 36.997 ;
     RECT  198.216 29.795 199.728 29.987 ;
     RECT  9.48 30.181 10.848 31.091 ;
     RECT  17.064 30.325 18.48 30.757 ;
     RECT  17.352 30.757 18.48 31.285 ;
     RECT  210.6 30.805 211.92 31.619 ;
     RECT  9.48 31.091 10.992 34.453 ;
     RECT  210.6 31.619 211.968 35.123 ;
     RECT  211.992 31.811 213 33.061 ;
     RECT  17.352 31.955 18.6 36.805 ;
     RECT  213.312 32.003 214.608 32.963 ;
     RECT  22.68 33.107 24 33.203 ;
     RECT  22.632 33.203 24 53.605 ;
     RECT  11.016 33.683 12.288 38.005 ;
     RECT  8.112 34.259 9.456 35.413 ;
     RECT  211.992 34.355 213 73.669 ;
     RECT  9.48 34.453 10.56 37.669 ;
     RECT  18.912 37.091 20.208 40.981 ;
     RECT  11.304 38.005 12.288 43.285 ;
     RECT  8.112 38.099 9.456 41.509 ;
     RECT  2.712 38.677 3.696 38.819 ;
     RECT  213.432 39.397 214.896 39.443 ;
     RECT  9.48 39.491 10.56 44.437 ;
     RECT  20.232 40.499 21.36 55.573 ;
     RECT  213.312 40.979 213.432 42.037 ;
     RECT  9.576 44.437 10.56 51.253 ;
     RECT  14.232 48.421 15.744 49.475 ;
     RECT  9.48 52.163 10.56 55.907 ;
     RECT  22.824 53.605 24 53.891 ;
     RECT  22.632 53.891 24 54.083 ;
     RECT  22.536 54.083 24 57.059 ;
     RECT  198.648 55.189 199.728 61.669 ;
     RECT  20.232 55.763 21.36 63.059 ;
     RECT  9.432 55.907 10.56 57.445 ;
     RECT  22.488 57.059 24 62.339 ;
     RECT  2.712 58.645 3.936 58.835 ;
     RECT  4.632 58.645 5.76 60.035 ;
     RECT  13.512 59.221 14.928 62.629 ;
     RECT  4.632 60.035 5.952 61.139 ;
     RECT  4.896 61.139 5.952 61.381 ;
     RECT  4.92 61.381 5.952 62.147 ;
     RECT  22.008 62.339 22.248 63.541 ;
     RECT  11.352 62.531 12.72 72.325 ;
     RECT  13.512 62.629 14.832 63.299 ;
     RECT  2.712 62.725 3.744 63.875 ;
     RECT  15.768 63.923 16.8 66.901 ;
     RECT  9.432 64.451 10.416 64.979 ;
     RECT  210.264 64.597 211.488 68.771 ;
     RECT  203.592 64.933 204.816 75.875 ;
     RECT  9.432 64.979 10.56 75.157 ;
     RECT  199.224 67.859 200.304 87.397 ;
     RECT  13.512 70.835 14.832 72.035 ;
     RECT  11.4 72.325 12.72 73.523 ;
     RECT  11.352 73.523 12.72 92.341 ;
     RECT  211.992 74.675 213 87.781 ;
     RECT  203.592 75.875 204.84 76.309 ;
     RECT  203.592 76.309 204.864 88.163 ;
     RECT  9.432 76.979 10.56 78.371 ;
     RECT  9.432 78.371 10.656 82.117 ;
     RECT  2.712 80.773 4.224 81.587 ;
     RECT  4.536 82.021 5.952 83.219 ;
     RECT  9.432 82.117 10.56 89.461 ;
     RECT  210.264 84.325 211.536 87.827 ;
     RECT  4.728 84.949 5.952 86.195 ;
     RECT  199.272 87.397 200.304 89.989 ;
     RECT  9.432 90.083 10.56 95.939 ;
     RECT  211.992 90.083 213 92.965 ;
     RECT  15.768 91.235 16.8 98.915 ;
     RECT  199.272 91.859 200.304 94.453 ;
     RECT  11.4 92.341 12.72 94.595 ;
     RECT  211.992 93.587 213 95.363 ;
     RECT  11.208 94.595 12.72 102.611 ;
     RECT  199.272 94.595 200.304 98.197 ;
     RECT  210.264 95.125 211.44 95.557 ;
     RECT  202.632 95.171 202.92 95.219 ;
     RECT  202.512 95.219 202.92 96.517 ;
     RECT  211.176 97.573 212.64 98.675 ;
     RECT  22.632 98.389 24 98.773 ;
     RECT  199.272 98.435 200.304 104.387 ;
     RECT  22.776 98.773 24 99.587 ;
     RECT  72.912 98.869 74.112 100.931 ;
     RECT  15.768 98.915 16.944 102.083 ;
     RECT  19.656 99.685 21.072 100.451 ;
     RECT  211.176 100.261 212.448 103.763 ;
     RECT  9.672 100.789 11.184 101.747 ;
     RECT  110.712 100.979 112.008 101.413 ;
     RECT  27.624 101.029 29.04 102.083 ;
     RECT  43.32 101.077 44.448 101.413 ;
     RECT  44.472 101.077 45.6 101.459 ;
     RECT  109.08 101.267 110.4 101.507 ;
     RECT  33.576 101.413 34.8 101.555 ;
     RECT  110.712 101.413 111.984 106.451 ;
     RECT  44.088 101.459 45.6 109.091 ;
     RECT  82.248 101.459 83.4 101.747 ;
     RECT  109.824 101.507 110.4 102.565 ;
     RECT  11.088 101.747 11.184 102.565 ;
     RECT  201.048 101.747 202.032 104.915 ;
     RECT  9.672 103.525 11.088 103.813 ;
     RECT  9.96 103.813 11.088 105.781 ;
     RECT  5.544 103.907 6.864 104.051 ;
     RECT  46.152 104.245 47.376 104.579 ;
     RECT  45.912 104.579 47.376 117.107 ;
     RECT  213.72 104.579 213.912 105.733 ;
     RECT  17.352 105.395 18.6 116.483 ;
     RECT  8.856 105.683 9.936 107.075 ;
     RECT  197.112 106.595 198.48 107.795 ;
     RECT  8.856 107.075 8.952 107.605 ;
     RECT  195.192 107.701 196.32 121.043 ;
     RECT  11.256 109.141 12.72 110.485 ;
     RECT  213.432 110.051 213.48 111.541 ;
     RECT  11.256 110.485 12.384 111.109 ;
     RECT  11.832 113.891 13.2 116.723 ;
     RECT  6.312 118.981 7.8 119.939 ;
  END
END ot_hgi_qdq_sw_program_leaf
END LIBRARY
